###############################################################
#  Generated by:      Cadence Innovus 23.30-p003_1
#  OS:                Linux x86_64(Host ID dell52)
#  Generated on:      Mon May  4 14:32:32 2026
#  Design:            top
#  Command:           write_lef_abstract -5.8 -specifyTopLayer M11 -PGpinLayers M8 -stripePin -cutObsMinSpacing ../models/lef/top.lef
###############################################################

VERSION 5.8 ;

BUSBITCHARS "[]" ;
DIVIDERCHAR "/" ;

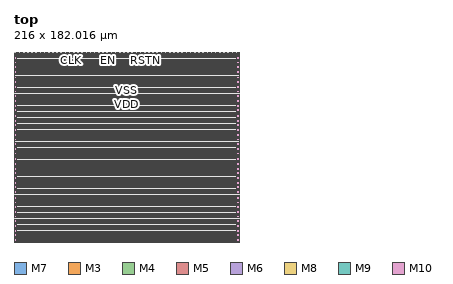
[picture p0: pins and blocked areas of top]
MACRO top
  CLASS BLOCK ;
  SIZE 216.000000 BY 182.016000 ;
  FOREIGN top 0.000000 0.000000 ;
  ORIGIN 0 0 ;
  SYMMETRY X Y R90 ;
  PIN CLK
    DIRECTION INPUT ;
    USE SIGNAL ;
    PORT
      LAYER M7 ;
        RECT 54.640000 181.641000 54.680000 182.016000 ;
    END
  END CLK
  PIN EN
    DIRECTION INPUT ;
    USE SIGNAL ;
    PORT
      LAYER M7 ;
        RECT 90.240000 181.641000 90.280000 182.016000 ;
    END
  END EN
  PIN RSTN
    DIRECTION INPUT ;
    USE SIGNAL ;
    PORT
      LAYER M7 ;
        RECT 125.840000 181.641000 125.880000 182.016000 ;
    END
  END RSTN
  PIN out_clk
    DIRECTION OUTPUT ;
    USE SIGNAL ;
    PORT
      LAYER M7 ;
        RECT 161.520000 181.641000 161.560000 182.016000 ;
    END
  END out_clk
  PIN VSS
    DIRECTION INOUT ;
    USE GROUND ;
    PORT
      LAYER M3 ;
        RECT 1.281000 0.000000 1.319000 0.038000 ;
    END
    PORT
      LAYER M3 ;
        RECT 1.281000 181.978000 1.319000 182.016000 ;
    END
    PORT
      LAYER M3 ;
        RECT 3.777000 0.000000 3.815000 0.038000 ;
    END
    PORT
      LAYER M3 ;
        RECT 3.777000 181.978000 3.815000 182.016000 ;
    END
    PORT
      LAYER M3 ;
        RECT 6.273000 0.000000 6.311000 0.038000 ;
    END
    PORT
      LAYER M3 ;
        RECT 6.273000 181.978000 6.311000 182.016000 ;
    END
    PORT
      LAYER M3 ;
        RECT 8.833000 0.000000 8.871000 0.038000 ;
    END
    PORT
      LAYER M3 ;
        RECT 8.833000 181.978000 8.871000 182.016000 ;
    END
    PORT
      LAYER M3 ;
        RECT 11.329000 0.000000 11.367000 0.038000 ;
    END
    PORT
      LAYER M3 ;
        RECT 11.329000 181.978000 11.367000 182.016000 ;
    END
    PORT
      LAYER M3 ;
        RECT 13.889000 0.000000 13.927000 0.038000 ;
    END
    PORT
      LAYER M3 ;
        RECT 13.889000 181.978000 13.927000 182.016000 ;
    END
    PORT
      LAYER M3 ;
        RECT 16.385000 0.000000 16.423000 0.038000 ;
    END
    PORT
      LAYER M3 ;
        RECT 16.385000 181.978000 16.423000 182.016000 ;
    END
    PORT
      LAYER M3 ;
        RECT 18.881000 0.000000 18.919000 0.038000 ;
    END
    PORT
      LAYER M3 ;
        RECT 18.881000 181.978000 18.919000 182.016000 ;
    END
    PORT
      LAYER M3 ;
        RECT 21.441000 0.000000 21.479000 0.038000 ;
    END
    PORT
      LAYER M3 ;
        RECT 21.441000 181.978000 21.479000 182.016000 ;
    END
    PORT
      LAYER M3 ;
        RECT 23.937000 0.000000 23.975000 0.038000 ;
    END
    PORT
      LAYER M3 ;
        RECT 23.937000 181.978000 23.975000 182.016000 ;
    END
    PORT
      LAYER M3 ;
        RECT 26.433000 0.000000 26.471000 0.038000 ;
    END
    PORT
      LAYER M3 ;
        RECT 26.433000 181.978000 26.471000 182.016000 ;
    END
    PORT
      LAYER M3 ;
        RECT 28.993000 0.000000 29.031000 0.038000 ;
    END
    PORT
      LAYER M3 ;
        RECT 28.993000 181.978000 29.031000 182.016000 ;
    END
    PORT
      LAYER M3 ;
        RECT 31.489000 0.000000 31.527000 0.038000 ;
    END
    PORT
      LAYER M3 ;
        RECT 31.489000 181.978000 31.527000 182.016000 ;
    END
    PORT
      LAYER M3 ;
        RECT 34.049000 0.000000 34.087000 0.038000 ;
    END
    PORT
      LAYER M3 ;
        RECT 34.049000 181.978000 34.087000 182.016000 ;
    END
    PORT
      LAYER M3 ;
        RECT 36.545000 0.000000 36.583000 0.038000 ;
    END
    PORT
      LAYER M3 ;
        RECT 36.545000 181.978000 36.583000 182.016000 ;
    END
    PORT
      LAYER M3 ;
        RECT 39.041000 0.000000 39.079000 0.038000 ;
    END
    PORT
      LAYER M3 ;
        RECT 39.041000 181.978000 39.079000 182.016000 ;
    END
    PORT
      LAYER M3 ;
        RECT 41.601000 0.000000 41.639000 0.038000 ;
    END
    PORT
      LAYER M3 ;
        RECT 41.601000 181.978000 41.639000 182.016000 ;
    END
    PORT
      LAYER M3 ;
        RECT 44.097000 0.000000 44.135000 0.038000 ;
    END
    PORT
      LAYER M3 ;
        RECT 44.097000 181.978000 44.135000 182.016000 ;
    END
    PORT
      LAYER M3 ;
        RECT 46.593000 0.000000 46.631000 0.038000 ;
    END
    PORT
      LAYER M3 ;
        RECT 46.593000 181.978000 46.631000 182.016000 ;
    END
    PORT
      LAYER M3 ;
        RECT 49.153000 0.000000 49.191000 0.038000 ;
    END
    PORT
      LAYER M3 ;
        RECT 49.153000 181.978000 49.191000 182.016000 ;
    END
    PORT
      LAYER M3 ;
        RECT 51.649000 0.000000 51.687000 0.038000 ;
    END
    PORT
      LAYER M3 ;
        RECT 51.649000 181.978000 51.687000 182.016000 ;
    END
    PORT
      LAYER M3 ;
        RECT 54.209000 0.000000 54.247000 0.038000 ;
    END
    PORT
      LAYER M3 ;
        RECT 54.209000 181.978000 54.247000 182.016000 ;
    END
    PORT
      LAYER M3 ;
        RECT 56.705000 0.000000 56.743000 0.038000 ;
    END
    PORT
      LAYER M3 ;
        RECT 56.705000 181.978000 56.743000 182.016000 ;
    END
    PORT
      LAYER M3 ;
        RECT 59.201000 0.000000 59.239000 0.038000 ;
    END
    PORT
      LAYER M3 ;
        RECT 59.201000 181.978000 59.239000 182.016000 ;
    END
    PORT
      LAYER M3 ;
        RECT 61.761000 0.000000 61.799000 0.038000 ;
    END
    PORT
      LAYER M3 ;
        RECT 61.761000 181.978000 61.799000 182.016000 ;
    END
    PORT
      LAYER M3 ;
        RECT 64.257000 0.000000 64.295000 0.038000 ;
    END
    PORT
      LAYER M3 ;
        RECT 64.257000 181.978000 64.295000 182.016000 ;
    END
    PORT
      LAYER M3 ;
        RECT 66.753000 0.000000 66.791000 0.038000 ;
    END
    PORT
      LAYER M3 ;
        RECT 66.753000 181.978000 66.791000 182.016000 ;
    END
    PORT
      LAYER M3 ;
        RECT 69.313000 0.000000 69.351000 0.038000 ;
    END
    PORT
      LAYER M3 ;
        RECT 69.313000 181.978000 69.351000 182.016000 ;
    END
    PORT
      LAYER M3 ;
        RECT 71.809000 0.000000 71.847000 0.038000 ;
    END
    PORT
      LAYER M3 ;
        RECT 71.809000 181.978000 71.847000 182.016000 ;
    END
    PORT
      LAYER M3 ;
        RECT 74.369000 0.000000 74.407000 0.038000 ;
    END
    PORT
      LAYER M3 ;
        RECT 74.369000 181.978000 74.407000 182.016000 ;
    END
    PORT
      LAYER M3 ;
        RECT 76.865000 0.000000 76.903000 0.038000 ;
    END
    PORT
      LAYER M3 ;
        RECT 76.865000 181.978000 76.903000 182.016000 ;
    END
    PORT
      LAYER M3 ;
        RECT 79.361000 0.000000 79.399000 0.038000 ;
    END
    PORT
      LAYER M3 ;
        RECT 79.361000 181.978000 79.399000 182.016000 ;
    END
    PORT
      LAYER M3 ;
        RECT 81.921000 0.000000 81.959000 0.038000 ;
    END
    PORT
      LAYER M3 ;
        RECT 81.921000 181.978000 81.959000 182.016000 ;
    END
    PORT
      LAYER M3 ;
        RECT 84.417000 0.000000 84.455000 0.038000 ;
    END
    PORT
      LAYER M3 ;
        RECT 84.417000 181.978000 84.455000 182.016000 ;
    END
    PORT
      LAYER M3 ;
        RECT 86.913000 0.000000 86.951000 0.038000 ;
    END
    PORT
      LAYER M3 ;
        RECT 86.913000 181.978000 86.951000 182.016000 ;
    END
    PORT
      LAYER M3 ;
        RECT 89.473000 0.000000 89.511000 0.038000 ;
    END
    PORT
      LAYER M3 ;
        RECT 89.473000 181.978000 89.511000 182.016000 ;
    END
    PORT
      LAYER M3 ;
        RECT 91.969000 0.000000 92.007000 0.038000 ;
    END
    PORT
      LAYER M3 ;
        RECT 91.969000 181.978000 92.007000 182.016000 ;
    END
    PORT
      LAYER M3 ;
        RECT 94.529000 0.000000 94.567000 0.038000 ;
    END
    PORT
      LAYER M3 ;
        RECT 94.529000 181.978000 94.567000 182.016000 ;
    END
    PORT
      LAYER M3 ;
        RECT 97.025000 0.000000 97.063000 0.038000 ;
    END
    PORT
      LAYER M3 ;
        RECT 97.025000 181.978000 97.063000 182.016000 ;
    END
    PORT
      LAYER M3 ;
        RECT 99.521000 0.000000 99.559000 0.038000 ;
    END
    PORT
      LAYER M3 ;
        RECT 99.521000 181.978000 99.559000 182.016000 ;
    END
    PORT
      LAYER M3 ;
        RECT 102.081000 0.000000 102.119000 0.038000 ;
    END
    PORT
      LAYER M3 ;
        RECT 102.081000 181.978000 102.119000 182.016000 ;
    END
    PORT
      LAYER M3 ;
        RECT 104.577000 0.000000 104.615000 0.038000 ;
    END
    PORT
      LAYER M3 ;
        RECT 104.577000 181.978000 104.615000 182.016000 ;
    END
    PORT
      LAYER M3 ;
        RECT 107.073000 0.000000 107.111000 0.038000 ;
    END
    PORT
      LAYER M3 ;
        RECT 107.073000 181.978000 107.111000 182.016000 ;
    END
    PORT
      LAYER M3 ;
        RECT 109.633000 0.000000 109.671000 0.038000 ;
    END
    PORT
      LAYER M3 ;
        RECT 109.633000 181.978000 109.671000 182.016000 ;
    END
    PORT
      LAYER M3 ;
        RECT 112.129000 0.000000 112.167000 0.038000 ;
    END
    PORT
      LAYER M3 ;
        RECT 112.129000 181.978000 112.167000 182.016000 ;
    END
    PORT
      LAYER M3 ;
        RECT 114.689000 0.000000 114.727000 0.038000 ;
    END
    PORT
      LAYER M3 ;
        RECT 114.689000 181.978000 114.727000 182.016000 ;
    END
    PORT
      LAYER M3 ;
        RECT 117.185000 0.000000 117.223000 0.038000 ;
    END
    PORT
      LAYER M3 ;
        RECT 117.185000 181.978000 117.223000 182.016000 ;
    END
    PORT
      LAYER M3 ;
        RECT 119.681000 0.000000 119.719000 0.038000 ;
    END
    PORT
      LAYER M3 ;
        RECT 119.681000 181.978000 119.719000 182.016000 ;
    END
    PORT
      LAYER M3 ;
        RECT 122.241000 0.000000 122.279000 0.038000 ;
    END
    PORT
      LAYER M3 ;
        RECT 122.241000 181.978000 122.279000 182.016000 ;
    END
    PORT
      LAYER M3 ;
        RECT 124.737000 0.000000 124.775000 0.038000 ;
    END
    PORT
      LAYER M3 ;
        RECT 124.737000 181.978000 124.775000 182.016000 ;
    END
    PORT
      LAYER M3 ;
        RECT 127.233000 0.000000 127.271000 0.038000 ;
    END
    PORT
      LAYER M3 ;
        RECT 127.233000 181.978000 127.271000 182.016000 ;
    END
    PORT
      LAYER M3 ;
        RECT 129.793000 0.000000 129.831000 0.038000 ;
    END
    PORT
      LAYER M3 ;
        RECT 129.793000 181.978000 129.831000 182.016000 ;
    END
    PORT
      LAYER M3 ;
        RECT 132.289000 0.000000 132.327000 0.038000 ;
    END
    PORT
      LAYER M3 ;
        RECT 132.289000 181.978000 132.327000 182.016000 ;
    END
    PORT
      LAYER M3 ;
        RECT 134.849000 0.000000 134.887000 0.038000 ;
    END
    PORT
      LAYER M3 ;
        RECT 134.849000 181.978000 134.887000 182.016000 ;
    END
    PORT
      LAYER M3 ;
        RECT 137.345000 0.000000 137.383000 0.038000 ;
    END
    PORT
      LAYER M3 ;
        RECT 137.345000 181.978000 137.383000 182.016000 ;
    END
    PORT
      LAYER M3 ;
        RECT 139.841000 0.000000 139.879000 0.038000 ;
    END
    PORT
      LAYER M3 ;
        RECT 139.841000 181.978000 139.879000 182.016000 ;
    END
    PORT
      LAYER M3 ;
        RECT 142.401000 0.000000 142.439000 0.038000 ;
    END
    PORT
      LAYER M3 ;
        RECT 142.401000 181.978000 142.439000 182.016000 ;
    END
    PORT
      LAYER M3 ;
        RECT 144.897000 0.000000 144.935000 0.038000 ;
    END
    PORT
      LAYER M3 ;
        RECT 144.897000 181.978000 144.935000 182.016000 ;
    END
    PORT
      LAYER M3 ;
        RECT 147.393000 0.000000 147.431000 0.038000 ;
    END
    PORT
      LAYER M3 ;
        RECT 147.393000 181.978000 147.431000 182.016000 ;
    END
    PORT
      LAYER M3 ;
        RECT 149.953000 0.000000 149.991000 0.038000 ;
    END
    PORT
      LAYER M3 ;
        RECT 149.953000 181.978000 149.991000 182.016000 ;
    END
    PORT
      LAYER M3 ;
        RECT 152.449000 0.000000 152.487000 0.038000 ;
    END
    PORT
      LAYER M3 ;
        RECT 152.449000 181.978000 152.487000 182.016000 ;
    END
    PORT
      LAYER M3 ;
        RECT 155.009000 0.000000 155.047000 0.038000 ;
    END
    PORT
      LAYER M3 ;
        RECT 155.009000 181.978000 155.047000 182.016000 ;
    END
    PORT
      LAYER M3 ;
        RECT 157.505000 0.000000 157.543000 0.038000 ;
    END
    PORT
      LAYER M3 ;
        RECT 157.505000 181.978000 157.543000 182.016000 ;
    END
    PORT
      LAYER M3 ;
        RECT 160.001000 0.000000 160.039000 0.038000 ;
    END
    PORT
      LAYER M3 ;
        RECT 160.001000 181.978000 160.039000 182.016000 ;
    END
    PORT
      LAYER M3 ;
        RECT 162.561000 0.000000 162.599000 0.038000 ;
    END
    PORT
      LAYER M3 ;
        RECT 162.561000 181.978000 162.599000 182.016000 ;
    END
    PORT
      LAYER M3 ;
        RECT 165.057000 0.000000 165.095000 0.038000 ;
    END
    PORT
      LAYER M3 ;
        RECT 165.057000 181.978000 165.095000 182.016000 ;
    END
    PORT
      LAYER M3 ;
        RECT 167.553000 0.000000 167.591000 0.038000 ;
    END
    PORT
      LAYER M3 ;
        RECT 167.553000 181.978000 167.591000 182.016000 ;
    END
    PORT
      LAYER M3 ;
        RECT 170.113000 0.000000 170.151000 0.038000 ;
    END
    PORT
      LAYER M3 ;
        RECT 170.113000 181.978000 170.151000 182.016000 ;
    END
    PORT
      LAYER M3 ;
        RECT 172.609000 0.000000 172.647000 0.038000 ;
    END
    PORT
      LAYER M3 ;
        RECT 172.609000 181.978000 172.647000 182.016000 ;
    END
    PORT
      LAYER M3 ;
        RECT 175.169000 0.000000 175.207000 0.038000 ;
    END
    PORT
      LAYER M3 ;
        RECT 175.169000 181.978000 175.207000 182.016000 ;
    END
    PORT
      LAYER M3 ;
        RECT 177.665000 0.000000 177.703000 0.038000 ;
    END
    PORT
      LAYER M3 ;
        RECT 177.665000 181.978000 177.703000 182.016000 ;
    END
    PORT
      LAYER M3 ;
        RECT 180.161000 0.000000 180.199000 0.038000 ;
    END
    PORT
      LAYER M3 ;
        RECT 180.161000 181.978000 180.199000 182.016000 ;
    END
    PORT
      LAYER M3 ;
        RECT 182.721000 0.000000 182.759000 0.038000 ;
    END
    PORT
      LAYER M3 ;
        RECT 182.721000 181.978000 182.759000 182.016000 ;
    END
    PORT
      LAYER M3 ;
        RECT 185.217000 0.000000 185.255000 0.038000 ;
    END
    PORT
      LAYER M3 ;
        RECT 185.217000 181.978000 185.255000 182.016000 ;
    END
    PORT
      LAYER M3 ;
        RECT 187.713000 0.000000 187.751000 0.038000 ;
    END
    PORT
      LAYER M3 ;
        RECT 187.713000 181.978000 187.751000 182.016000 ;
    END
    PORT
      LAYER M3 ;
        RECT 190.273000 0.000000 190.311000 0.038000 ;
    END
    PORT
      LAYER M3 ;
        RECT 190.273000 181.978000 190.311000 182.016000 ;
    END
    PORT
      LAYER M3 ;
        RECT 192.769000 0.000000 192.807000 0.038000 ;
    END
    PORT
      LAYER M3 ;
        RECT 192.769000 181.978000 192.807000 182.016000 ;
    END
    PORT
      LAYER M3 ;
        RECT 195.329000 0.000000 195.367000 0.038000 ;
    END
    PORT
      LAYER M3 ;
        RECT 195.329000 181.978000 195.367000 182.016000 ;
    END
    PORT
      LAYER M3 ;
        RECT 197.825000 0.000000 197.863000 0.038000 ;
    END
    PORT
      LAYER M3 ;
        RECT 197.825000 181.978000 197.863000 182.016000 ;
    END
    PORT
      LAYER M3 ;
        RECT 200.321000 0.000000 200.359000 0.038000 ;
    END
    PORT
      LAYER M3 ;
        RECT 200.321000 181.978000 200.359000 182.016000 ;
    END
    PORT
      LAYER M3 ;
        RECT 202.881000 0.000000 202.919000 0.038000 ;
    END
    PORT
      LAYER M3 ;
        RECT 202.881000 181.978000 202.919000 182.016000 ;
    END
    PORT
      LAYER M3 ;
        RECT 205.377000 0.000000 205.415000 0.038000 ;
    END
    PORT
      LAYER M3 ;
        RECT 205.377000 181.978000 205.415000 182.016000 ;
    END
    PORT
      LAYER M3 ;
        RECT 207.873000 0.000000 207.911000 0.038000 ;
    END
    PORT
      LAYER M3 ;
        RECT 207.873000 181.978000 207.911000 182.016000 ;
    END
    PORT
      LAYER M3 ;
        RECT 210.433000 0.000000 210.471000 0.038000 ;
    END
    PORT
      LAYER M3 ;
        RECT 210.433000 181.978000 210.471000 182.016000 ;
    END
    PORT
      LAYER M3 ;
        RECT 212.929000 0.000000 212.967000 0.038000 ;
    END
    PORT
      LAYER M3 ;
        RECT 212.929000 181.978000 212.967000 182.016000 ;
    END
    PORT
      LAYER M3 ;
        RECT 215.489000 0.000000 215.527000 0.038000 ;
    END
    PORT
      LAYER M3 ;
        RECT 215.489000 181.978000 215.527000 182.016000 ;
    END
    PORT
      LAYER M4 ;
        RECT 0.000000 1.228000 0.040000 1.268000 ;
    END
    PORT
      LAYER M4 ;
        RECT 215.960000 1.228000 216.000000 1.268000 ;
    END
    PORT
      LAYER M4 ;
        RECT 0.000000 3.468000 0.040000 3.508000 ;
    END
    PORT
      LAYER M4 ;
        RECT 215.960000 3.468000 216.000000 3.508000 ;
    END
    PORT
      LAYER M4 ;
        RECT 0.000000 5.788000 0.040000 5.828000 ;
    END
    PORT
      LAYER M4 ;
        RECT 215.960000 5.788000 216.000000 5.828000 ;
    END
    PORT
      LAYER M4 ;
        RECT 0.000000 8.028000 0.040000 8.068000 ;
    END
    PORT
      LAYER M4 ;
        RECT 215.960000 8.028000 216.000000 8.068000 ;
    END
    PORT
      LAYER M4 ;
        RECT 0.000000 10.348000 0.040000 10.388000 ;
    END
    PORT
      LAYER M4 ;
        RECT 215.960000 10.348000 216.000000 10.388000 ;
    END
    PORT
      LAYER M4 ;
        RECT 0.000000 12.668000 0.040000 12.708000 ;
    END
    PORT
      LAYER M4 ;
        RECT 215.960000 12.668000 216.000000 12.708000 ;
    END
    PORT
      LAYER M4 ;
        RECT 0.000000 14.988000 0.040000 15.028000 ;
    END
    PORT
      LAYER M4 ;
        RECT 215.960000 14.988000 216.000000 15.028000 ;
    END
    PORT
      LAYER M4 ;
        RECT 0.000000 17.308000 0.040000 17.348000 ;
    END
    PORT
      LAYER M4 ;
        RECT 215.960000 17.308000 216.000000 17.348000 ;
    END
    PORT
      LAYER M4 ;
        RECT 0.000000 19.548000 0.040000 19.588000 ;
    END
    PORT
      LAYER M4 ;
        RECT 215.960000 19.548000 216.000000 19.588000 ;
    END
    PORT
      LAYER M4 ;
        RECT 0.000000 21.868000 0.040000 21.908000 ;
    END
    PORT
      LAYER M4 ;
        RECT 215.960000 21.868000 216.000000 21.908000 ;
    END
    PORT
      LAYER M4 ;
        RECT 0.000000 24.188000 0.040000 24.228000 ;
    END
    PORT
      LAYER M4 ;
        RECT 215.960000 24.188000 216.000000 24.228000 ;
    END
    PORT
      LAYER M4 ;
        RECT 0.000000 26.508000 0.040000 26.548000 ;
    END
    PORT
      LAYER M4 ;
        RECT 215.960000 26.508000 216.000000 26.548000 ;
    END
    PORT
      LAYER M4 ;
        RECT 0.000000 28.828000 0.040000 28.868000 ;
    END
    PORT
      LAYER M4 ;
        RECT 215.960000 28.828000 216.000000 28.868000 ;
    END
    PORT
      LAYER M4 ;
        RECT 0.000000 31.068000 0.040000 31.108000 ;
    END
    PORT
      LAYER M4 ;
        RECT 215.960000 31.068000 216.000000 31.108000 ;
    END
    PORT
      LAYER M4 ;
        RECT 0.000000 33.388000 0.040000 33.428000 ;
    END
    PORT
      LAYER M4 ;
        RECT 215.960000 33.388000 216.000000 33.428000 ;
    END
    PORT
      LAYER M4 ;
        RECT 0.000000 35.708000 0.040000 35.748000 ;
    END
    PORT
      LAYER M4 ;
        RECT 215.960000 35.708000 216.000000 35.748000 ;
    END
    PORT
      LAYER M4 ;
        RECT 0.000000 38.028000 0.040000 38.068000 ;
    END
    PORT
      LAYER M4 ;
        RECT 215.960000 38.028000 216.000000 38.068000 ;
    END
    PORT
      LAYER M4 ;
        RECT 0.000000 40.348000 0.040000 40.388000 ;
    END
    PORT
      LAYER M4 ;
        RECT 215.960000 40.348000 216.000000 40.388000 ;
    END
    PORT
      LAYER M4 ;
        RECT 0.000000 42.588000 0.040000 42.628000 ;
    END
    PORT
      LAYER M4 ;
        RECT 215.960000 42.588000 216.000000 42.628000 ;
    END
    PORT
      LAYER M4 ;
        RECT 0.000000 44.908000 0.040000 44.948000 ;
    END
    PORT
      LAYER M4 ;
        RECT 215.960000 44.908000 216.000000 44.948000 ;
    END
    PORT
      LAYER M4 ;
        RECT 0.000000 47.228000 0.040000 47.268000 ;
    END
    PORT
      LAYER M4 ;
        RECT 215.960000 47.228000 216.000000 47.268000 ;
    END
    PORT
      LAYER M4 ;
        RECT 0.000000 49.548000 0.040000 49.588000 ;
    END
    PORT
      LAYER M4 ;
        RECT 215.960000 49.548000 216.000000 49.588000 ;
    END
    PORT
      LAYER M4 ;
        RECT 0.000000 51.868000 0.040000 51.908000 ;
    END
    PORT
      LAYER M4 ;
        RECT 215.960000 51.868000 216.000000 51.908000 ;
    END
    PORT
      LAYER M4 ;
        RECT 0.000000 54.108000 0.040000 54.148000 ;
    END
    PORT
      LAYER M4 ;
        RECT 215.960000 54.108000 216.000000 54.148000 ;
    END
    PORT
      LAYER M4 ;
        RECT 0.000000 56.428000 0.040000 56.468000 ;
    END
    PORT
      LAYER M4 ;
        RECT 215.960000 56.428000 216.000000 56.468000 ;
    END
    PORT
      LAYER M4 ;
        RECT 0.000000 58.748000 0.040000 58.788000 ;
    END
    PORT
      LAYER M4 ;
        RECT 215.960000 58.748000 216.000000 58.788000 ;
    END
    PORT
      LAYER M4 ;
        RECT 0.000000 61.068000 0.040000 61.108000 ;
    END
    PORT
      LAYER M4 ;
        RECT 215.960000 61.068000 216.000000 61.108000 ;
    END
    PORT
      LAYER M4 ;
        RECT 0.000000 63.388000 0.040000 63.428000 ;
    END
    PORT
      LAYER M4 ;
        RECT 215.960000 63.388000 216.000000 63.428000 ;
    END
    PORT
      LAYER M4 ;
        RECT 0.000000 65.628000 0.040000 65.668000 ;
    END
    PORT
      LAYER M4 ;
        RECT 215.960000 65.628000 216.000000 65.668000 ;
    END
    PORT
      LAYER M4 ;
        RECT 0.000000 67.948000 0.040000 67.988000 ;
    END
    PORT
      LAYER M4 ;
        RECT 215.960000 67.948000 216.000000 67.988000 ;
    END
    PORT
      LAYER M4 ;
        RECT 0.000000 70.268000 0.040000 70.308000 ;
    END
    PORT
      LAYER M4 ;
        RECT 215.960000 70.268000 216.000000 70.308000 ;
    END
    PORT
      LAYER M4 ;
        RECT 0.000000 72.588000 0.040000 72.628000 ;
    END
    PORT
      LAYER M4 ;
        RECT 215.960000 72.588000 216.000000 72.628000 ;
    END
    PORT
      LAYER M4 ;
        RECT 0.000000 74.908000 0.040000 74.948000 ;
    END
    PORT
      LAYER M4 ;
        RECT 215.960000 74.908000 216.000000 74.948000 ;
    END
    PORT
      LAYER M4 ;
        RECT 0.000000 77.148000 0.040000 77.188000 ;
    END
    PORT
      LAYER M4 ;
        RECT 215.960000 77.148000 216.000000 77.188000 ;
    END
    PORT
      LAYER M4 ;
        RECT 0.000000 79.468000 0.040000 79.508000 ;
    END
    PORT
      LAYER M4 ;
        RECT 215.960000 79.468000 216.000000 79.508000 ;
    END
    PORT
      LAYER M4 ;
        RECT 0.000000 81.788000 0.040000 81.828000 ;
    END
    PORT
      LAYER M4 ;
        RECT 215.960000 81.788000 216.000000 81.828000 ;
    END
    PORT
      LAYER M4 ;
        RECT 0.000000 84.108000 0.040000 84.148000 ;
    END
    PORT
      LAYER M4 ;
        RECT 215.960000 84.108000 216.000000 84.148000 ;
    END
    PORT
      LAYER M4 ;
        RECT 0.000000 86.428000 0.040000 86.468000 ;
    END
    PORT
      LAYER M4 ;
        RECT 215.960000 86.428000 216.000000 86.468000 ;
    END
    PORT
      LAYER M4 ;
        RECT 0.000000 88.668000 0.040000 88.708000 ;
    END
    PORT
      LAYER M4 ;
        RECT 215.960000 88.668000 216.000000 88.708000 ;
    END
    PORT
      LAYER M4 ;
        RECT 0.000000 90.988000 0.040000 91.028000 ;
    END
    PORT
      LAYER M4 ;
        RECT 215.960000 90.988000 216.000000 91.028000 ;
    END
    PORT
      LAYER M4 ;
        RECT 0.000000 93.308000 0.040000 93.348000 ;
    END
    PORT
      LAYER M4 ;
        RECT 215.960000 93.308000 216.000000 93.348000 ;
    END
    PORT
      LAYER M4 ;
        RECT 0.000000 95.628000 0.040000 95.668000 ;
    END
    PORT
      LAYER M4 ;
        RECT 215.960000 95.628000 216.000000 95.668000 ;
    END
    PORT
      LAYER M4 ;
        RECT 0.000000 97.948000 0.040000 97.988000 ;
    END
    PORT
      LAYER M4 ;
        RECT 215.960000 97.948000 216.000000 97.988000 ;
    END
    PORT
      LAYER M4 ;
        RECT 0.000000 100.188000 0.040000 100.228000 ;
    END
    PORT
      LAYER M4 ;
        RECT 215.960000 100.188000 216.000000 100.228000 ;
    END
    PORT
      LAYER M4 ;
        RECT 0.000000 102.508000 0.040000 102.548000 ;
    END
    PORT
      LAYER M4 ;
        RECT 215.960000 102.508000 216.000000 102.548000 ;
    END
    PORT
      LAYER M4 ;
        RECT 0.000000 104.828000 0.040000 104.868000 ;
    END
    PORT
      LAYER M4 ;
        RECT 215.960000 104.828000 216.000000 104.868000 ;
    END
    PORT
      LAYER M4 ;
        RECT 0.000000 107.148000 0.040000 107.188000 ;
    END
    PORT
      LAYER M4 ;
        RECT 215.960000 107.148000 216.000000 107.188000 ;
    END
    PORT
      LAYER M4 ;
        RECT 0.000000 109.468000 0.040000 109.508000 ;
    END
    PORT
      LAYER M4 ;
        RECT 215.960000 109.468000 216.000000 109.508000 ;
    END
    PORT
      LAYER M4 ;
        RECT 0.000000 111.708000 0.040000 111.748000 ;
    END
    PORT
      LAYER M4 ;
        RECT 215.960000 111.708000 216.000000 111.748000 ;
    END
    PORT
      LAYER M4 ;
        RECT 0.000000 114.028000 0.040000 114.068000 ;
    END
    PORT
      LAYER M4 ;
        RECT 215.960000 114.028000 216.000000 114.068000 ;
    END
    PORT
      LAYER M4 ;
        RECT 0.000000 116.348000 0.040000 116.388000 ;
    END
    PORT
      LAYER M4 ;
        RECT 215.960000 116.348000 216.000000 116.388000 ;
    END
    PORT
      LAYER M4 ;
        RECT 0.000000 118.668000 0.040000 118.708000 ;
    END
    PORT
      LAYER M4 ;
        RECT 215.960000 118.668000 216.000000 118.708000 ;
    END
    PORT
      LAYER M4 ;
        RECT 0.000000 120.988000 0.040000 121.028000 ;
    END
    PORT
      LAYER M4 ;
        RECT 215.960000 120.988000 216.000000 121.028000 ;
    END
    PORT
      LAYER M4 ;
        RECT 0.000000 123.228000 0.040000 123.268000 ;
    END
    PORT
      LAYER M4 ;
        RECT 215.960000 123.228000 216.000000 123.268000 ;
    END
    PORT
      LAYER M4 ;
        RECT 0.000000 125.548000 0.040000 125.588000 ;
    END
    PORT
      LAYER M4 ;
        RECT 215.960000 125.548000 216.000000 125.588000 ;
    END
    PORT
      LAYER M4 ;
        RECT 0.000000 127.868000 0.040000 127.908000 ;
    END
    PORT
      LAYER M4 ;
        RECT 215.960000 127.868000 216.000000 127.908000 ;
    END
    PORT
      LAYER M4 ;
        RECT 0.000000 130.188000 0.040000 130.228000 ;
    END
    PORT
      LAYER M4 ;
        RECT 215.960000 130.188000 216.000000 130.228000 ;
    END
    PORT
      LAYER M4 ;
        RECT 0.000000 132.508000 0.040000 132.548000 ;
    END
    PORT
      LAYER M4 ;
        RECT 215.960000 132.508000 216.000000 132.548000 ;
    END
    PORT
      LAYER M4 ;
        RECT 0.000000 134.748000 0.040000 134.788000 ;
    END
    PORT
      LAYER M4 ;
        RECT 215.960000 134.748000 216.000000 134.788000 ;
    END
    PORT
      LAYER M4 ;
        RECT 0.000000 137.068000 0.040000 137.108000 ;
    END
    PORT
      LAYER M4 ;
        RECT 215.960000 137.068000 216.000000 137.108000 ;
    END
    PORT
      LAYER M4 ;
        RECT 0.000000 139.388000 0.040000 139.428000 ;
    END
    PORT
      LAYER M4 ;
        RECT 215.960000 139.388000 216.000000 139.428000 ;
    END
    PORT
      LAYER M4 ;
        RECT 0.000000 141.708000 0.040000 141.748000 ;
    END
    PORT
      LAYER M4 ;
        RECT 215.960000 141.708000 216.000000 141.748000 ;
    END
    PORT
      LAYER M4 ;
        RECT 0.000000 144.028000 0.040000 144.068000 ;
    END
    PORT
      LAYER M4 ;
        RECT 215.960000 144.028000 216.000000 144.068000 ;
    END
    PORT
      LAYER M4 ;
        RECT 0.000000 146.268000 0.040000 146.308000 ;
    END
    PORT
      LAYER M4 ;
        RECT 215.960000 146.268000 216.000000 146.308000 ;
    END
    PORT
      LAYER M4 ;
        RECT 0.000000 148.588000 0.040000 148.628000 ;
    END
    PORT
      LAYER M4 ;
        RECT 215.960000 148.588000 216.000000 148.628000 ;
    END
    PORT
      LAYER M4 ;
        RECT 0.000000 150.908000 0.040000 150.948000 ;
    END
    PORT
      LAYER M4 ;
        RECT 215.960000 150.908000 216.000000 150.948000 ;
    END
    PORT
      LAYER M4 ;
        RECT 0.000000 153.228000 0.040000 153.268000 ;
    END
    PORT
      LAYER M4 ;
        RECT 215.960000 153.228000 216.000000 153.268000 ;
    END
    PORT
      LAYER M4 ;
        RECT 0.000000 155.548000 0.040000 155.588000 ;
    END
    PORT
      LAYER M4 ;
        RECT 215.960000 155.548000 216.000000 155.588000 ;
    END
    PORT
      LAYER M4 ;
        RECT 0.000000 157.788000 0.040000 157.828000 ;
    END
    PORT
      LAYER M4 ;
        RECT 215.960000 157.788000 216.000000 157.828000 ;
    END
    PORT
      LAYER M4 ;
        RECT 0.000000 160.108000 0.040000 160.148000 ;
    END
    PORT
      LAYER M4 ;
        RECT 215.960000 160.108000 216.000000 160.148000 ;
    END
    PORT
      LAYER M4 ;
        RECT 0.000000 162.428000 0.040000 162.468000 ;
    END
    PORT
      LAYER M4 ;
        RECT 215.960000 162.428000 216.000000 162.468000 ;
    END
    PORT
      LAYER M4 ;
        RECT 0.000000 164.748000 0.040000 164.788000 ;
    END
    PORT
      LAYER M4 ;
        RECT 215.960000 164.748000 216.000000 164.788000 ;
    END
    PORT
      LAYER M4 ;
        RECT 0.000000 167.068000 0.040000 167.108000 ;
    END
    PORT
      LAYER M4 ;
        RECT 215.960000 167.068000 216.000000 167.108000 ;
    END
    PORT
      LAYER M4 ;
        RECT 0.000000 169.308000 0.040000 169.348000 ;
    END
    PORT
      LAYER M4 ;
        RECT 215.960000 169.308000 216.000000 169.348000 ;
    END
    PORT
      LAYER M4 ;
        RECT 0.000000 171.628000 0.040000 171.668000 ;
    END
    PORT
      LAYER M4 ;
        RECT 215.960000 171.628000 216.000000 171.668000 ;
    END
    PORT
      LAYER M4 ;
        RECT 0.000000 173.948000 0.040000 173.988000 ;
    END
    PORT
      LAYER M4 ;
        RECT 215.960000 173.948000 216.000000 173.988000 ;
    END
    PORT
      LAYER M4 ;
        RECT 0.000000 176.268000 0.040000 176.308000 ;
    END
    PORT
      LAYER M4 ;
        RECT 215.960000 176.268000 216.000000 176.308000 ;
    END
    PORT
      LAYER M4 ;
        RECT 0.000000 178.588000 0.040000 178.628000 ;
    END
    PORT
      LAYER M4 ;
        RECT 215.960000 178.588000 216.000000 178.628000 ;
    END
    PORT
      LAYER M4 ;
        RECT 0.000000 180.828000 0.040000 180.868000 ;
    END
    PORT
      LAYER M4 ;
        RECT 215.960000 180.828000 216.000000 180.868000 ;
    END
    PORT
      LAYER M5 ;
        RECT 1.280000 0.000000 1.320000 0.040000 ;
    END
    PORT
      LAYER M5 ;
        RECT 1.280000 181.976000 1.320000 182.016000 ;
    END
    PORT
      LAYER M5 ;
        RECT 3.760000 0.000000 3.800000 0.040000 ;
    END
    PORT
      LAYER M5 ;
        RECT 3.760000 181.976000 3.800000 182.016000 ;
    END
    PORT
      LAYER M5 ;
        RECT 6.320000 0.000000 6.360000 0.040000 ;
    END
    PORT
      LAYER M5 ;
        RECT 6.320000 181.976000 6.360000 182.016000 ;
    END
    PORT
      LAYER M5 ;
        RECT 8.800000 0.000000 8.840000 0.040000 ;
    END
    PORT
      LAYER M5 ;
        RECT 8.800000 181.976000 8.840000 182.016000 ;
    END
    PORT
      LAYER M5 ;
        RECT 11.360000 0.000000 11.400000 0.040000 ;
    END
    PORT
      LAYER M5 ;
        RECT 11.360000 181.976000 11.400000 182.016000 ;
    END
    PORT
      LAYER M5 ;
        RECT 13.840000 0.000000 13.880000 0.040000 ;
    END
    PORT
      LAYER M5 ;
        RECT 13.840000 181.976000 13.880000 182.016000 ;
    END
    PORT
      LAYER M5 ;
        RECT 16.400000 0.000000 16.440000 0.040000 ;
    END
    PORT
      LAYER M5 ;
        RECT 16.400000 181.976000 16.440000 182.016000 ;
    END
    PORT
      LAYER M5 ;
        RECT 18.880000 0.000000 18.920000 0.040000 ;
    END
    PORT
      LAYER M5 ;
        RECT 18.880000 181.976000 18.920000 182.016000 ;
    END
    PORT
      LAYER M5 ;
        RECT 21.440000 0.000000 21.480000 0.040000 ;
    END
    PORT
      LAYER M5 ;
        RECT 21.440000 181.976000 21.480000 182.016000 ;
    END
    PORT
      LAYER M5 ;
        RECT 23.920000 0.000000 23.960000 0.040000 ;
    END
    PORT
      LAYER M5 ;
        RECT 23.920000 181.976000 23.960000 182.016000 ;
    END
    PORT
      LAYER M5 ;
        RECT 26.480000 0.000000 26.520000 0.040000 ;
    END
    PORT
      LAYER M5 ;
        RECT 26.480000 181.976000 26.520000 182.016000 ;
    END
    PORT
      LAYER M5 ;
        RECT 28.960000 0.000000 29.000000 0.040000 ;
    END
    PORT
      LAYER M5 ;
        RECT 28.960000 181.976000 29.000000 182.016000 ;
    END
    PORT
      LAYER M5 ;
        RECT 31.520000 0.000000 31.560000 0.040000 ;
    END
    PORT
      LAYER M5 ;
        RECT 31.520000 181.976000 31.560000 182.016000 ;
    END
    PORT
      LAYER M5 ;
        RECT 34.000000 0.000000 34.040000 0.040000 ;
    END
    PORT
      LAYER M5 ;
        RECT 34.000000 181.976000 34.040000 182.016000 ;
    END
    PORT
      LAYER M5 ;
        RECT 36.560000 0.000000 36.600000 0.040000 ;
    END
    PORT
      LAYER M5 ;
        RECT 36.560000 181.976000 36.600000 182.016000 ;
    END
    PORT
      LAYER M5 ;
        RECT 39.040000 0.000000 39.080000 0.040000 ;
    END
    PORT
      LAYER M5 ;
        RECT 39.040000 181.976000 39.080000 182.016000 ;
    END
    PORT
      LAYER M5 ;
        RECT 41.600000 0.000000 41.640000 0.040000 ;
    END
    PORT
      LAYER M5 ;
        RECT 41.600000 181.976000 41.640000 182.016000 ;
    END
    PORT
      LAYER M5 ;
        RECT 44.080000 0.000000 44.120000 0.040000 ;
    END
    PORT
      LAYER M5 ;
        RECT 44.080000 181.976000 44.120000 182.016000 ;
    END
    PORT
      LAYER M5 ;
        RECT 46.640000 0.000000 46.680000 0.040000 ;
    END
    PORT
      LAYER M5 ;
        RECT 46.640000 181.976000 46.680000 182.016000 ;
    END
    PORT
      LAYER M5 ;
        RECT 49.120000 0.000000 49.160000 0.040000 ;
    END
    PORT
      LAYER M5 ;
        RECT 49.120000 181.976000 49.160000 182.016000 ;
    END
    PORT
      LAYER M5 ;
        RECT 51.680000 0.000000 51.720000 0.040000 ;
    END
    PORT
      LAYER M5 ;
        RECT 51.680000 181.976000 51.720000 182.016000 ;
    END
    PORT
      LAYER M5 ;
        RECT 54.160000 0.000000 54.200000 0.040000 ;
    END
    PORT
      LAYER M5 ;
        RECT 54.160000 181.976000 54.200000 182.016000 ;
    END
    PORT
      LAYER M5 ;
        RECT 56.720000 0.000000 56.760000 0.040000 ;
    END
    PORT
      LAYER M5 ;
        RECT 56.720000 181.976000 56.760000 182.016000 ;
    END
    PORT
      LAYER M5 ;
        RECT 59.200000 0.000000 59.240000 0.040000 ;
    END
    PORT
      LAYER M5 ;
        RECT 59.200000 181.976000 59.240000 182.016000 ;
    END
    PORT
      LAYER M5 ;
        RECT 61.760000 0.000000 61.800000 0.040000 ;
    END
    PORT
      LAYER M5 ;
        RECT 61.760000 181.976000 61.800000 182.016000 ;
    END
    PORT
      LAYER M5 ;
        RECT 64.240000 0.000000 64.280000 0.040000 ;
    END
    PORT
      LAYER M5 ;
        RECT 64.240000 181.976000 64.280000 182.016000 ;
    END
    PORT
      LAYER M5 ;
        RECT 66.800000 0.000000 66.840000 0.040000 ;
    END
    PORT
      LAYER M5 ;
        RECT 66.800000 181.976000 66.840000 182.016000 ;
    END
    PORT
      LAYER M5 ;
        RECT 69.280000 0.000000 69.320000 0.040000 ;
    END
    PORT
      LAYER M5 ;
        RECT 69.280000 181.976000 69.320000 182.016000 ;
    END
    PORT
      LAYER M5 ;
        RECT 71.840000 0.000000 71.880000 0.040000 ;
    END
    PORT
      LAYER M5 ;
        RECT 71.840000 181.976000 71.880000 182.016000 ;
    END
    PORT
      LAYER M5 ;
        RECT 74.320000 0.000000 74.360000 0.040000 ;
    END
    PORT
      LAYER M5 ;
        RECT 74.320000 181.976000 74.360000 182.016000 ;
    END
    PORT
      LAYER M5 ;
        RECT 76.880000 0.000000 76.920000 0.040000 ;
    END
    PORT
      LAYER M5 ;
        RECT 76.880000 181.976000 76.920000 182.016000 ;
    END
    PORT
      LAYER M5 ;
        RECT 79.360000 0.000000 79.400000 0.040000 ;
    END
    PORT
      LAYER M5 ;
        RECT 79.360000 181.976000 79.400000 182.016000 ;
    END
    PORT
      LAYER M5 ;
        RECT 81.920000 0.000000 81.960000 0.040000 ;
    END
    PORT
      LAYER M5 ;
        RECT 81.920000 181.976000 81.960000 182.016000 ;
    END
    PORT
      LAYER M5 ;
        RECT 84.400000 0.000000 84.440000 0.040000 ;
    END
    PORT
      LAYER M5 ;
        RECT 84.400000 181.976000 84.440000 182.016000 ;
    END
    PORT
      LAYER M5 ;
        RECT 86.960000 0.000000 87.000000 0.040000 ;
    END
    PORT
      LAYER M5 ;
        RECT 86.960000 181.976000 87.000000 182.016000 ;
    END
    PORT
      LAYER M5 ;
        RECT 89.440000 0.000000 89.480000 0.040000 ;
    END
    PORT
      LAYER M5 ;
        RECT 89.440000 181.976000 89.480000 182.016000 ;
    END
    PORT
      LAYER M5 ;
        RECT 92.000000 0.000000 92.040000 0.040000 ;
    END
    PORT
      LAYER M5 ;
        RECT 92.000000 181.976000 92.040000 182.016000 ;
    END
    PORT
      LAYER M5 ;
        RECT 94.480000 0.000000 94.520000 0.040000 ;
    END
    PORT
      LAYER M5 ;
        RECT 94.480000 181.976000 94.520000 182.016000 ;
    END
    PORT
      LAYER M5 ;
        RECT 97.040000 0.000000 97.080000 0.040000 ;
    END
    PORT
      LAYER M5 ;
        RECT 97.040000 181.976000 97.080000 182.016000 ;
    END
    PORT
      LAYER M5 ;
        RECT 99.520000 0.000000 99.560000 0.040000 ;
    END
    PORT
      LAYER M5 ;
        RECT 99.520000 181.976000 99.560000 182.016000 ;
    END
    PORT
      LAYER M5 ;
        RECT 102.080000 0.000000 102.120000 0.040000 ;
    END
    PORT
      LAYER M5 ;
        RECT 102.080000 181.976000 102.120000 182.016000 ;
    END
    PORT
      LAYER M5 ;
        RECT 104.560000 0.000000 104.600000 0.040000 ;
    END
    PORT
      LAYER M5 ;
        RECT 104.560000 181.976000 104.600000 182.016000 ;
    END
    PORT
      LAYER M5 ;
        RECT 107.120000 0.000000 107.160000 0.040000 ;
    END
    PORT
      LAYER M5 ;
        RECT 107.120000 181.976000 107.160000 182.016000 ;
    END
    PORT
      LAYER M5 ;
        RECT 109.600000 0.000000 109.640000 0.040000 ;
    END
    PORT
      LAYER M5 ;
        RECT 109.600000 181.976000 109.640000 182.016000 ;
    END
    PORT
      LAYER M5 ;
        RECT 112.160000 0.000000 112.200000 0.040000 ;
    END
    PORT
      LAYER M5 ;
        RECT 112.160000 181.976000 112.200000 182.016000 ;
    END
    PORT
      LAYER M5 ;
        RECT 114.640000 0.000000 114.680000 0.040000 ;
    END
    PORT
      LAYER M5 ;
        RECT 114.640000 181.976000 114.680000 182.016000 ;
    END
    PORT
      LAYER M5 ;
        RECT 117.200000 0.000000 117.240000 0.040000 ;
    END
    PORT
      LAYER M5 ;
        RECT 117.200000 181.976000 117.240000 182.016000 ;
    END
    PORT
      LAYER M5 ;
        RECT 119.680000 0.000000 119.720000 0.040000 ;
    END
    PORT
      LAYER M5 ;
        RECT 119.680000 181.976000 119.720000 182.016000 ;
    END
    PORT
      LAYER M5 ;
        RECT 122.240000 0.000000 122.280000 0.040000 ;
    END
    PORT
      LAYER M5 ;
        RECT 122.240000 181.976000 122.280000 182.016000 ;
    END
    PORT
      LAYER M5 ;
        RECT 124.720000 0.000000 124.760000 0.040000 ;
    END
    PORT
      LAYER M5 ;
        RECT 124.720000 181.976000 124.760000 182.016000 ;
    END
    PORT
      LAYER M5 ;
        RECT 127.280000 0.000000 127.320000 0.040000 ;
    END
    PORT
      LAYER M5 ;
        RECT 127.280000 181.976000 127.320000 182.016000 ;
    END
    PORT
      LAYER M5 ;
        RECT 129.760000 0.000000 129.800000 0.040000 ;
    END
    PORT
      LAYER M5 ;
        RECT 129.760000 181.976000 129.800000 182.016000 ;
    END
    PORT
      LAYER M5 ;
        RECT 132.320000 0.000000 132.360000 0.040000 ;
    END
    PORT
      LAYER M5 ;
        RECT 132.320000 181.976000 132.360000 182.016000 ;
    END
    PORT
      LAYER M5 ;
        RECT 134.800000 0.000000 134.840000 0.040000 ;
    END
    PORT
      LAYER M5 ;
        RECT 134.800000 181.976000 134.840000 182.016000 ;
    END
    PORT
      LAYER M5 ;
        RECT 137.360000 0.000000 137.400000 0.040000 ;
    END
    PORT
      LAYER M5 ;
        RECT 137.360000 181.976000 137.400000 182.016000 ;
    END
    PORT
      LAYER M5 ;
        RECT 139.840000 0.000000 139.880000 0.040000 ;
    END
    PORT
      LAYER M5 ;
        RECT 139.840000 181.976000 139.880000 182.016000 ;
    END
    PORT
      LAYER M5 ;
        RECT 142.400000 0.000000 142.440000 0.040000 ;
    END
    PORT
      LAYER M5 ;
        RECT 142.400000 181.976000 142.440000 182.016000 ;
    END
    PORT
      LAYER M5 ;
        RECT 144.880000 0.000000 144.920000 0.040000 ;
    END
    PORT
      LAYER M5 ;
        RECT 144.880000 181.976000 144.920000 182.016000 ;
    END
    PORT
      LAYER M5 ;
        RECT 147.440000 0.000000 147.480000 0.040000 ;
    END
    PORT
      LAYER M5 ;
        RECT 147.440000 181.976000 147.480000 182.016000 ;
    END
    PORT
      LAYER M5 ;
        RECT 149.920000 0.000000 149.960000 0.040000 ;
    END
    PORT
      LAYER M5 ;
        RECT 149.920000 181.976000 149.960000 182.016000 ;
    END
    PORT
      LAYER M5 ;
        RECT 152.480000 0.000000 152.520000 0.040000 ;
    END
    PORT
      LAYER M5 ;
        RECT 152.480000 181.976000 152.520000 182.016000 ;
    END
    PORT
      LAYER M5 ;
        RECT 154.960000 0.000000 155.000000 0.040000 ;
    END
    PORT
      LAYER M5 ;
        RECT 154.960000 181.976000 155.000000 182.016000 ;
    END
    PORT
      LAYER M5 ;
        RECT 157.520000 0.000000 157.560000 0.040000 ;
    END
    PORT
      LAYER M5 ;
        RECT 157.520000 181.976000 157.560000 182.016000 ;
    END
    PORT
      LAYER M5 ;
        RECT 160.000000 0.000000 160.040000 0.040000 ;
    END
    PORT
      LAYER M5 ;
        RECT 160.000000 181.976000 160.040000 182.016000 ;
    END
    PORT
      LAYER M5 ;
        RECT 162.560000 0.000000 162.600000 0.040000 ;
    END
    PORT
      LAYER M5 ;
        RECT 162.560000 181.976000 162.600000 182.016000 ;
    END
    PORT
      LAYER M5 ;
        RECT 165.040000 0.000000 165.080000 0.040000 ;
    END
    PORT
      LAYER M5 ;
        RECT 165.040000 181.976000 165.080000 182.016000 ;
    END
    PORT
      LAYER M5 ;
        RECT 167.600000 0.000000 167.640000 0.040000 ;
    END
    PORT
      LAYER M5 ;
        RECT 167.600000 181.976000 167.640000 182.016000 ;
    END
    PORT
      LAYER M5 ;
        RECT 170.080000 0.000000 170.120000 0.040000 ;
    END
    PORT
      LAYER M5 ;
        RECT 170.080000 181.976000 170.120000 182.016000 ;
    END
    PORT
      LAYER M5 ;
        RECT 172.640000 0.000000 172.680000 0.040000 ;
    END
    PORT
      LAYER M5 ;
        RECT 172.640000 181.976000 172.680000 182.016000 ;
    END
    PORT
      LAYER M5 ;
        RECT 175.120000 0.000000 175.160000 0.040000 ;
    END
    PORT
      LAYER M5 ;
        RECT 175.120000 181.976000 175.160000 182.016000 ;
    END
    PORT
      LAYER M5 ;
        RECT 177.680000 0.000000 177.720000 0.040000 ;
    END
    PORT
      LAYER M5 ;
        RECT 177.680000 181.976000 177.720000 182.016000 ;
    END
    PORT
      LAYER M5 ;
        RECT 180.160000 0.000000 180.200000 0.040000 ;
    END
    PORT
      LAYER M5 ;
        RECT 180.160000 181.976000 180.200000 182.016000 ;
    END
    PORT
      LAYER M5 ;
        RECT 182.720000 0.000000 182.760000 0.040000 ;
    END
    PORT
      LAYER M5 ;
        RECT 182.720000 181.976000 182.760000 182.016000 ;
    END
    PORT
      LAYER M5 ;
        RECT 185.200000 0.000000 185.240000 0.040000 ;
    END
    PORT
      LAYER M5 ;
        RECT 185.200000 181.976000 185.240000 182.016000 ;
    END
    PORT
      LAYER M5 ;
        RECT 187.760000 0.000000 187.800000 0.040000 ;
    END
    PORT
      LAYER M5 ;
        RECT 187.760000 181.976000 187.800000 182.016000 ;
    END
    PORT
      LAYER M5 ;
        RECT 190.240000 0.000000 190.280000 0.040000 ;
    END
    PORT
      LAYER M5 ;
        RECT 190.240000 181.976000 190.280000 182.016000 ;
    END
    PORT
      LAYER M5 ;
        RECT 192.800000 0.000000 192.840000 0.040000 ;
    END
    PORT
      LAYER M5 ;
        RECT 192.800000 181.976000 192.840000 182.016000 ;
    END
    PORT
      LAYER M5 ;
        RECT 195.280000 0.000000 195.320000 0.040000 ;
    END
    PORT
      LAYER M5 ;
        RECT 195.280000 181.976000 195.320000 182.016000 ;
    END
    PORT
      LAYER M5 ;
        RECT 197.840000 0.000000 197.880000 0.040000 ;
    END
    PORT
      LAYER M5 ;
        RECT 197.840000 181.976000 197.880000 182.016000 ;
    END
    PORT
      LAYER M5 ;
        RECT 200.320000 0.000000 200.360000 0.040000 ;
    END
    PORT
      LAYER M5 ;
        RECT 200.320000 181.976000 200.360000 182.016000 ;
    END
    PORT
      LAYER M5 ;
        RECT 202.880000 0.000000 202.920000 0.040000 ;
    END
    PORT
      LAYER M5 ;
        RECT 202.880000 181.976000 202.920000 182.016000 ;
    END
    PORT
      LAYER M5 ;
        RECT 205.360000 0.000000 205.400000 0.040000 ;
    END
    PORT
      LAYER M5 ;
        RECT 205.360000 181.976000 205.400000 182.016000 ;
    END
    PORT
      LAYER M5 ;
        RECT 207.920000 0.000000 207.960000 0.040000 ;
    END
    PORT
      LAYER M5 ;
        RECT 207.920000 181.976000 207.960000 182.016000 ;
    END
    PORT
      LAYER M5 ;
        RECT 210.400000 0.000000 210.440000 0.040000 ;
    END
    PORT
      LAYER M5 ;
        RECT 210.400000 181.976000 210.440000 182.016000 ;
    END
    PORT
      LAYER M5 ;
        RECT 212.960000 0.000000 213.000000 0.040000 ;
    END
    PORT
      LAYER M5 ;
        RECT 212.960000 181.976000 213.000000 182.016000 ;
    END
    PORT
      LAYER M5 ;
        RECT 215.440000 0.000000 215.480000 0.040000 ;
    END
    PORT
      LAYER M5 ;
        RECT 215.440000 181.976000 215.480000 182.016000 ;
    END
    PORT
      LAYER M6 ;
        RECT 0.000000 1.228000 0.040000 1.268000 ;
    END
    PORT
      LAYER M6 ;
        RECT 215.960000 1.228000 216.000000 1.268000 ;
    END
    PORT
      LAYER M6 ;
        RECT 0.000000 3.468000 0.040000 3.508000 ;
    END
    PORT
      LAYER M6 ;
        RECT 215.960000 3.468000 216.000000 3.508000 ;
    END
    PORT
      LAYER M6 ;
        RECT 0.000000 5.788000 0.040000 5.828000 ;
    END
    PORT
      LAYER M6 ;
        RECT 215.960000 5.788000 216.000000 5.828000 ;
    END
    PORT
      LAYER M6 ;
        RECT 0.000000 8.028000 0.040000 8.068000 ;
    END
    PORT
      LAYER M6 ;
        RECT 215.960000 8.028000 216.000000 8.068000 ;
    END
    PORT
      LAYER M6 ;
        RECT 0.000000 10.348000 0.040000 10.388000 ;
    END
    PORT
      LAYER M6 ;
        RECT 215.960000 10.348000 216.000000 10.388000 ;
    END
    PORT
      LAYER M6 ;
        RECT 0.000000 12.668000 0.040000 12.708000 ;
    END
    PORT
      LAYER M6 ;
        RECT 215.960000 12.668000 216.000000 12.708000 ;
    END
    PORT
      LAYER M6 ;
        RECT 0.000000 14.988000 0.040000 15.028000 ;
    END
    PORT
      LAYER M6 ;
        RECT 215.960000 14.988000 216.000000 15.028000 ;
    END
    PORT
      LAYER M6 ;
        RECT 0.000000 17.308000 0.040000 17.348000 ;
    END
    PORT
      LAYER M6 ;
        RECT 215.960000 17.308000 216.000000 17.348000 ;
    END
    PORT
      LAYER M6 ;
        RECT 0.000000 19.548000 0.040000 19.588000 ;
    END
    PORT
      LAYER M6 ;
        RECT 215.960000 19.548000 216.000000 19.588000 ;
    END
    PORT
      LAYER M6 ;
        RECT 0.000000 21.868000 0.040000 21.908000 ;
    END
    PORT
      LAYER M6 ;
        RECT 215.960000 21.868000 216.000000 21.908000 ;
    END
    PORT
      LAYER M6 ;
        RECT 0.000000 24.188000 0.040000 24.228000 ;
    END
    PORT
      LAYER M6 ;
        RECT 215.960000 24.188000 216.000000 24.228000 ;
    END
    PORT
      LAYER M6 ;
        RECT 0.000000 26.508000 0.040000 26.548000 ;
    END
    PORT
      LAYER M6 ;
        RECT 215.960000 26.508000 216.000000 26.548000 ;
    END
    PORT
      LAYER M6 ;
        RECT 0.000000 28.828000 0.040000 28.868000 ;
    END
    PORT
      LAYER M6 ;
        RECT 215.960000 28.828000 216.000000 28.868000 ;
    END
    PORT
      LAYER M6 ;
        RECT 0.000000 31.068000 0.040000 31.108000 ;
    END
    PORT
      LAYER M6 ;
        RECT 215.960000 31.068000 216.000000 31.108000 ;
    END
    PORT
      LAYER M6 ;
        RECT 0.000000 33.388000 0.040000 33.428000 ;
    END
    PORT
      LAYER M6 ;
        RECT 215.960000 33.388000 216.000000 33.428000 ;
    END
    PORT
      LAYER M6 ;
        RECT 0.000000 35.708000 0.040000 35.748000 ;
    END
    PORT
      LAYER M6 ;
        RECT 215.960000 35.708000 216.000000 35.748000 ;
    END
    PORT
      LAYER M6 ;
        RECT 0.000000 38.028000 0.040000 38.068000 ;
    END
    PORT
      LAYER M6 ;
        RECT 215.960000 38.028000 216.000000 38.068000 ;
    END
    PORT
      LAYER M6 ;
        RECT 0.000000 40.348000 0.040000 40.388000 ;
    END
    PORT
      LAYER M6 ;
        RECT 215.960000 40.348000 216.000000 40.388000 ;
    END
    PORT
      LAYER M6 ;
        RECT 0.000000 42.588000 0.040000 42.628000 ;
    END
    PORT
      LAYER M6 ;
        RECT 215.960000 42.588000 216.000000 42.628000 ;
    END
    PORT
      LAYER M6 ;
        RECT 0.000000 44.908000 0.040000 44.948000 ;
    END
    PORT
      LAYER M6 ;
        RECT 215.960000 44.908000 216.000000 44.948000 ;
    END
    PORT
      LAYER M6 ;
        RECT 0.000000 47.228000 0.040000 47.268000 ;
    END
    PORT
      LAYER M6 ;
        RECT 215.960000 47.228000 216.000000 47.268000 ;
    END
    PORT
      LAYER M6 ;
        RECT 0.000000 49.548000 0.040000 49.588000 ;
    END
    PORT
      LAYER M6 ;
        RECT 215.960000 49.548000 216.000000 49.588000 ;
    END
    PORT
      LAYER M6 ;
        RECT 0.000000 51.868000 0.040000 51.908000 ;
    END
    PORT
      LAYER M6 ;
        RECT 215.960000 51.868000 216.000000 51.908000 ;
    END
    PORT
      LAYER M6 ;
        RECT 0.000000 54.108000 0.040000 54.148000 ;
    END
    PORT
      LAYER M6 ;
        RECT 215.960000 54.108000 216.000000 54.148000 ;
    END
    PORT
      LAYER M6 ;
        RECT 0.000000 56.428000 0.040000 56.468000 ;
    END
    PORT
      LAYER M6 ;
        RECT 215.960000 56.428000 216.000000 56.468000 ;
    END
    PORT
      LAYER M6 ;
        RECT 0.000000 58.748000 0.040000 58.788000 ;
    END
    PORT
      LAYER M6 ;
        RECT 215.960000 58.748000 216.000000 58.788000 ;
    END
    PORT
      LAYER M6 ;
        RECT 0.000000 61.068000 0.040000 61.108000 ;
    END
    PORT
      LAYER M6 ;
        RECT 215.960000 61.068000 216.000000 61.108000 ;
    END
    PORT
      LAYER M6 ;
        RECT 0.000000 63.388000 0.040000 63.428000 ;
    END
    PORT
      LAYER M6 ;
        RECT 215.960000 63.388000 216.000000 63.428000 ;
    END
    PORT
      LAYER M6 ;
        RECT 0.000000 65.628000 0.040000 65.668000 ;
    END
    PORT
      LAYER M6 ;
        RECT 215.960000 65.628000 216.000000 65.668000 ;
    END
    PORT
      LAYER M6 ;
        RECT 0.000000 67.948000 0.040000 67.988000 ;
    END
    PORT
      LAYER M6 ;
        RECT 215.960000 67.948000 216.000000 67.988000 ;
    END
    PORT
      LAYER M6 ;
        RECT 0.000000 70.268000 0.040000 70.308000 ;
    END
    PORT
      LAYER M6 ;
        RECT 215.960000 70.268000 216.000000 70.308000 ;
    END
    PORT
      LAYER M6 ;
        RECT 0.000000 72.588000 0.040000 72.628000 ;
    END
    PORT
      LAYER M6 ;
        RECT 215.960000 72.588000 216.000000 72.628000 ;
    END
    PORT
      LAYER M6 ;
        RECT 0.000000 74.908000 0.040000 74.948000 ;
    END
    PORT
      LAYER M6 ;
        RECT 215.960000 74.908000 216.000000 74.948000 ;
    END
    PORT
      LAYER M6 ;
        RECT 0.000000 77.148000 0.040000 77.188000 ;
    END
    PORT
      LAYER M6 ;
        RECT 215.960000 77.148000 216.000000 77.188000 ;
    END
    PORT
      LAYER M6 ;
        RECT 0.000000 79.468000 0.040000 79.508000 ;
    END
    PORT
      LAYER M6 ;
        RECT 215.960000 79.468000 216.000000 79.508000 ;
    END
    PORT
      LAYER M6 ;
        RECT 0.000000 81.788000 0.040000 81.828000 ;
    END
    PORT
      LAYER M6 ;
        RECT 215.960000 81.788000 216.000000 81.828000 ;
    END
    PORT
      LAYER M6 ;
        RECT 0.000000 84.108000 0.040000 84.148000 ;
    END
    PORT
      LAYER M6 ;
        RECT 215.960000 84.108000 216.000000 84.148000 ;
    END
    PORT
      LAYER M6 ;
        RECT 0.000000 86.428000 0.040000 86.468000 ;
    END
    PORT
      LAYER M6 ;
        RECT 215.960000 86.428000 216.000000 86.468000 ;
    END
    PORT
      LAYER M6 ;
        RECT 0.000000 88.668000 0.040000 88.708000 ;
    END
    PORT
      LAYER M6 ;
        RECT 215.960000 88.668000 216.000000 88.708000 ;
    END
    PORT
      LAYER M6 ;
        RECT 0.000000 90.988000 0.040000 91.028000 ;
    END
    PORT
      LAYER M6 ;
        RECT 215.960000 90.988000 216.000000 91.028000 ;
    END
    PORT
      LAYER M6 ;
        RECT 0.000000 93.308000 0.040000 93.348000 ;
    END
    PORT
      LAYER M6 ;
        RECT 215.960000 93.308000 216.000000 93.348000 ;
    END
    PORT
      LAYER M6 ;
        RECT 0.000000 95.628000 0.040000 95.668000 ;
    END
    PORT
      LAYER M6 ;
        RECT 215.960000 95.628000 216.000000 95.668000 ;
    END
    PORT
      LAYER M6 ;
        RECT 0.000000 97.948000 0.040000 97.988000 ;
    END
    PORT
      LAYER M6 ;
        RECT 215.960000 97.948000 216.000000 97.988000 ;
    END
    PORT
      LAYER M6 ;
        RECT 0.000000 100.188000 0.040000 100.228000 ;
    END
    PORT
      LAYER M6 ;
        RECT 215.960000 100.188000 216.000000 100.228000 ;
    END
    PORT
      LAYER M6 ;
        RECT 0.000000 102.508000 0.040000 102.548000 ;
    END
    PORT
      LAYER M6 ;
        RECT 215.960000 102.508000 216.000000 102.548000 ;
    END
    PORT
      LAYER M6 ;
        RECT 0.000000 104.828000 0.040000 104.868000 ;
    END
    PORT
      LAYER M6 ;
        RECT 215.960000 104.828000 216.000000 104.868000 ;
    END
    PORT
      LAYER M6 ;
        RECT 0.000000 107.148000 0.040000 107.188000 ;
    END
    PORT
      LAYER M6 ;
        RECT 215.960000 107.148000 216.000000 107.188000 ;
    END
    PORT
      LAYER M6 ;
        RECT 0.000000 109.468000 0.040000 109.508000 ;
    END
    PORT
      LAYER M6 ;
        RECT 215.960000 109.468000 216.000000 109.508000 ;
    END
    PORT
      LAYER M6 ;
        RECT 0.000000 111.708000 0.040000 111.748000 ;
    END
    PORT
      LAYER M6 ;
        RECT 215.960000 111.708000 216.000000 111.748000 ;
    END
    PORT
      LAYER M6 ;
        RECT 0.000000 114.028000 0.040000 114.068000 ;
    END
    PORT
      LAYER M6 ;
        RECT 215.960000 114.028000 216.000000 114.068000 ;
    END
    PORT
      LAYER M6 ;
        RECT 0.000000 116.348000 0.040000 116.388000 ;
    END
    PORT
      LAYER M6 ;
        RECT 215.960000 116.348000 216.000000 116.388000 ;
    END
    PORT
      LAYER M6 ;
        RECT 0.000000 118.668000 0.040000 118.708000 ;
    END
    PORT
      LAYER M6 ;
        RECT 215.960000 118.668000 216.000000 118.708000 ;
    END
    PORT
      LAYER M6 ;
        RECT 0.000000 120.988000 0.040000 121.028000 ;
    END
    PORT
      LAYER M6 ;
        RECT 215.960000 120.988000 216.000000 121.028000 ;
    END
    PORT
      LAYER M6 ;
        RECT 0.000000 123.228000 0.040000 123.268000 ;
    END
    PORT
      LAYER M6 ;
        RECT 215.960000 123.228000 216.000000 123.268000 ;
    END
    PORT
      LAYER M6 ;
        RECT 0.000000 125.548000 0.040000 125.588000 ;
    END
    PORT
      LAYER M6 ;
        RECT 215.960000 125.548000 216.000000 125.588000 ;
    END
    PORT
      LAYER M6 ;
        RECT 0.000000 127.868000 0.040000 127.908000 ;
    END
    PORT
      LAYER M6 ;
        RECT 215.960000 127.868000 216.000000 127.908000 ;
    END
    PORT
      LAYER M6 ;
        RECT 0.000000 130.188000 0.040000 130.228000 ;
    END
    PORT
      LAYER M6 ;
        RECT 215.960000 130.188000 216.000000 130.228000 ;
    END
    PORT
      LAYER M6 ;
        RECT 0.000000 132.508000 0.040000 132.548000 ;
    END
    PORT
      LAYER M6 ;
        RECT 215.960000 132.508000 216.000000 132.548000 ;
    END
    PORT
      LAYER M6 ;
        RECT 0.000000 134.748000 0.040000 134.788000 ;
    END
    PORT
      LAYER M6 ;
        RECT 215.960000 134.748000 216.000000 134.788000 ;
    END
    PORT
      LAYER M6 ;
        RECT 0.000000 137.068000 0.040000 137.108000 ;
    END
    PORT
      LAYER M6 ;
        RECT 215.960000 137.068000 216.000000 137.108000 ;
    END
    PORT
      LAYER M6 ;
        RECT 0.000000 139.388000 0.040000 139.428000 ;
    END
    PORT
      LAYER M6 ;
        RECT 215.960000 139.388000 216.000000 139.428000 ;
    END
    PORT
      LAYER M6 ;
        RECT 0.000000 141.708000 0.040000 141.748000 ;
    END
    PORT
      LAYER M6 ;
        RECT 215.960000 141.708000 216.000000 141.748000 ;
    END
    PORT
      LAYER M6 ;
        RECT 0.000000 144.028000 0.040000 144.068000 ;
    END
    PORT
      LAYER M6 ;
        RECT 215.960000 144.028000 216.000000 144.068000 ;
    END
    PORT
      LAYER M6 ;
        RECT 0.000000 146.268000 0.040000 146.308000 ;
    END
    PORT
      LAYER M6 ;
        RECT 215.960000 146.268000 216.000000 146.308000 ;
    END
    PORT
      LAYER M6 ;
        RECT 0.000000 148.588000 0.040000 148.628000 ;
    END
    PORT
      LAYER M6 ;
        RECT 215.960000 148.588000 216.000000 148.628000 ;
    END
    PORT
      LAYER M6 ;
        RECT 0.000000 150.908000 0.040000 150.948000 ;
    END
    PORT
      LAYER M6 ;
        RECT 215.960000 150.908000 216.000000 150.948000 ;
    END
    PORT
      LAYER M6 ;
        RECT 0.000000 153.228000 0.040000 153.268000 ;
    END
    PORT
      LAYER M6 ;
        RECT 215.960000 153.228000 216.000000 153.268000 ;
    END
    PORT
      LAYER M6 ;
        RECT 0.000000 155.548000 0.040000 155.588000 ;
    END
    PORT
      LAYER M6 ;
        RECT 215.960000 155.548000 216.000000 155.588000 ;
    END
    PORT
      LAYER M6 ;
        RECT 0.000000 157.788000 0.040000 157.828000 ;
    END
    PORT
      LAYER M6 ;
        RECT 215.960000 157.788000 216.000000 157.828000 ;
    END
    PORT
      LAYER M6 ;
        RECT 0.000000 160.108000 0.040000 160.148000 ;
    END
    PORT
      LAYER M6 ;
        RECT 215.960000 160.108000 216.000000 160.148000 ;
    END
    PORT
      LAYER M6 ;
        RECT 0.000000 162.428000 0.040000 162.468000 ;
    END
    PORT
      LAYER M6 ;
        RECT 215.960000 162.428000 216.000000 162.468000 ;
    END
    PORT
      LAYER M6 ;
        RECT 0.000000 164.748000 0.040000 164.788000 ;
    END
    PORT
      LAYER M6 ;
        RECT 215.960000 164.748000 216.000000 164.788000 ;
    END
    PORT
      LAYER M6 ;
        RECT 0.000000 167.068000 0.040000 167.108000 ;
    END
    PORT
      LAYER M6 ;
        RECT 215.960000 167.068000 216.000000 167.108000 ;
    END
    PORT
      LAYER M6 ;
        RECT 0.000000 169.308000 0.040000 169.348000 ;
    END
    PORT
      LAYER M6 ;
        RECT 215.960000 169.308000 216.000000 169.348000 ;
    END
    PORT
      LAYER M6 ;
        RECT 0.000000 171.628000 0.040000 171.668000 ;
    END
    PORT
      LAYER M6 ;
        RECT 215.960000 171.628000 216.000000 171.668000 ;
    END
    PORT
      LAYER M6 ;
        RECT 0.000000 173.948000 0.040000 173.988000 ;
    END
    PORT
      LAYER M6 ;
        RECT 215.960000 173.948000 216.000000 173.988000 ;
    END
    PORT
      LAYER M6 ;
        RECT 0.000000 176.268000 0.040000 176.308000 ;
    END
    PORT
      LAYER M6 ;
        RECT 215.960000 176.268000 216.000000 176.308000 ;
    END
    PORT
      LAYER M6 ;
        RECT 0.000000 178.588000 0.040000 178.628000 ;
    END
    PORT
      LAYER M6 ;
        RECT 215.960000 178.588000 216.000000 178.628000 ;
    END
    PORT
      LAYER M6 ;
        RECT 0.000000 180.828000 0.040000 180.868000 ;
    END
    PORT
      LAYER M6 ;
        RECT 215.960000 180.828000 216.000000 180.868000 ;
    END
    PORT
      LAYER M7 ;
        RECT 1.320000 0.000000 1.440000 0.120000 ;
    END
    PORT
      LAYER M7 ;
        RECT 1.320000 181.896000 1.440000 182.016000 ;
    END
    PORT
      LAYER M7 ;
        RECT 3.800000 0.000000 3.920000 0.120000 ;
    END
    PORT
      LAYER M7 ;
        RECT 3.800000 181.896000 3.920000 182.016000 ;
    END
    PORT
      LAYER M7 ;
        RECT 6.280000 0.000000 6.400000 0.120000 ;
    END
    PORT
      LAYER M7 ;
        RECT 6.280000 181.896000 6.400000 182.016000 ;
    END
    PORT
      LAYER M7 ;
        RECT 8.840000 0.000000 8.960000 0.120000 ;
    END
    PORT
      LAYER M7 ;
        RECT 8.840000 181.896000 8.960000 182.016000 ;
    END
    PORT
      LAYER M7 ;
        RECT 11.320000 0.000000 11.440000 0.120000 ;
    END
    PORT
      LAYER M7 ;
        RECT 11.320000 181.896000 11.440000 182.016000 ;
    END
    PORT
      LAYER M7 ;
        RECT 13.880000 0.000000 14.000000 0.120000 ;
    END
    PORT
      LAYER M7 ;
        RECT 13.880000 181.896000 14.000000 182.016000 ;
    END
    PORT
      LAYER M7 ;
        RECT 16.360000 0.000000 16.480000 0.120000 ;
    END
    PORT
      LAYER M7 ;
        RECT 16.360000 181.896000 16.480000 182.016000 ;
    END
    PORT
      LAYER M7 ;
        RECT 18.920000 0.000000 19.040000 0.120000 ;
    END
    PORT
      LAYER M7 ;
        RECT 18.920000 181.896000 19.040000 182.016000 ;
    END
    PORT
      LAYER M7 ;
        RECT 21.400000 0.000000 21.520000 0.120000 ;
    END
    PORT
      LAYER M7 ;
        RECT 21.400000 181.896000 21.520000 182.016000 ;
    END
    PORT
      LAYER M7 ;
        RECT 23.960000 0.000000 24.080000 0.120000 ;
    END
    PORT
      LAYER M7 ;
        RECT 23.960000 181.896000 24.080000 182.016000 ;
    END
    PORT
      LAYER M7 ;
        RECT 26.440000 0.000000 26.560000 0.120000 ;
    END
    PORT
      LAYER M7 ;
        RECT 26.440000 181.896000 26.560000 182.016000 ;
    END
    PORT
      LAYER M7 ;
        RECT 29.000000 0.000000 29.120000 0.120000 ;
    END
    PORT
      LAYER M7 ;
        RECT 29.000000 181.896000 29.120000 182.016000 ;
    END
    PORT
      LAYER M7 ;
        RECT 31.480000 0.000000 31.600000 0.120000 ;
    END
    PORT
      LAYER M7 ;
        RECT 31.480000 181.896000 31.600000 182.016000 ;
    END
    PORT
      LAYER M7 ;
        RECT 34.040000 0.000000 34.160000 0.120000 ;
    END
    PORT
      LAYER M7 ;
        RECT 34.040000 181.896000 34.160000 182.016000 ;
    END
    PORT
      LAYER M7 ;
        RECT 36.520000 0.000000 36.640000 0.120000 ;
    END
    PORT
      LAYER M7 ;
        RECT 36.520000 181.896000 36.640000 182.016000 ;
    END
    PORT
      LAYER M7 ;
        RECT 39.080000 0.000000 39.200000 0.120000 ;
    END
    PORT
      LAYER M7 ;
        RECT 39.080000 181.896000 39.200000 182.016000 ;
    END
    PORT
      LAYER M7 ;
        RECT 41.560000 0.000000 41.680000 0.120000 ;
    END
    PORT
      LAYER M7 ;
        RECT 41.560000 181.896000 41.680000 182.016000 ;
    END
    PORT
      LAYER M7 ;
        RECT 44.120000 0.000000 44.240000 0.120000 ;
    END
    PORT
      LAYER M7 ;
        RECT 44.120000 181.896000 44.240000 182.016000 ;
    END
    PORT
      LAYER M7 ;
        RECT 46.600000 0.000000 46.720000 0.120000 ;
    END
    PORT
      LAYER M7 ;
        RECT 46.600000 181.896000 46.720000 182.016000 ;
    END
    PORT
      LAYER M7 ;
        RECT 49.160000 0.000000 49.280000 0.120000 ;
    END
    PORT
      LAYER M7 ;
        RECT 49.160000 181.896000 49.280000 182.016000 ;
    END
    PORT
      LAYER M7 ;
        RECT 51.640000 0.000000 51.760000 0.120000 ;
    END
    PORT
      LAYER M7 ;
        RECT 51.640000 181.896000 51.760000 182.016000 ;
    END
    PORT
      LAYER M7 ;
        RECT 54.200000 0.000000 54.320000 0.120000 ;
    END
    PORT
      LAYER M7 ;
        RECT 54.200000 181.896000 54.320000 182.016000 ;
    END
    PORT
      LAYER M7 ;
        RECT 56.680000 0.000000 56.800000 0.120000 ;
    END
    PORT
      LAYER M7 ;
        RECT 56.680000 181.896000 56.800000 182.016000 ;
    END
    PORT
      LAYER M7 ;
        RECT 59.240000 0.000000 59.360000 0.120000 ;
    END
    PORT
      LAYER M7 ;
        RECT 59.240000 181.896000 59.360000 182.016000 ;
    END
    PORT
      LAYER M7 ;
        RECT 61.720000 0.000000 61.840000 0.120000 ;
    END
    PORT
      LAYER M7 ;
        RECT 61.720000 181.896000 61.840000 182.016000 ;
    END
    PORT
      LAYER M7 ;
        RECT 64.280000 0.000000 64.400000 0.120000 ;
    END
    PORT
      LAYER M7 ;
        RECT 64.280000 181.896000 64.400000 182.016000 ;
    END
    PORT
      LAYER M7 ;
        RECT 66.760000 0.000000 66.880000 0.120000 ;
    END
    PORT
      LAYER M7 ;
        RECT 66.760000 181.896000 66.880000 182.016000 ;
    END
    PORT
      LAYER M7 ;
        RECT 69.320000 0.000000 69.440000 0.120000 ;
    END
    PORT
      LAYER M7 ;
        RECT 69.320000 181.896000 69.440000 182.016000 ;
    END
    PORT
      LAYER M7 ;
        RECT 71.800000 0.000000 71.920000 0.120000 ;
    END
    PORT
      LAYER M7 ;
        RECT 71.800000 181.896000 71.920000 182.016000 ;
    END
    PORT
      LAYER M7 ;
        RECT 74.360000 0.000000 74.480000 0.120000 ;
    END
    PORT
      LAYER M7 ;
        RECT 74.360000 181.896000 74.480000 182.016000 ;
    END
    PORT
      LAYER M7 ;
        RECT 76.840000 0.000000 76.960000 0.120000 ;
    END
    PORT
      LAYER M7 ;
        RECT 76.840000 181.896000 76.960000 182.016000 ;
    END
    PORT
      LAYER M7 ;
        RECT 79.400000 0.000000 79.520000 0.120000 ;
    END
    PORT
      LAYER M7 ;
        RECT 79.400000 181.896000 79.520000 182.016000 ;
    END
    PORT
      LAYER M7 ;
        RECT 81.880000 0.000000 82.000000 0.120000 ;
    END
    PORT
      LAYER M7 ;
        RECT 81.880000 181.896000 82.000000 182.016000 ;
    END
    PORT
      LAYER M7 ;
        RECT 84.440000 0.000000 84.560000 0.120000 ;
    END
    PORT
      LAYER M7 ;
        RECT 84.440000 181.896000 84.560000 182.016000 ;
    END
    PORT
      LAYER M7 ;
        RECT 86.920000 0.000000 87.040000 0.120000 ;
    END
    PORT
      LAYER M7 ;
        RECT 86.920000 181.896000 87.040000 182.016000 ;
    END
    PORT
      LAYER M7 ;
        RECT 89.480000 0.000000 89.600000 0.120000 ;
    END
    PORT
      LAYER M7 ;
        RECT 89.480000 181.896000 89.600000 182.016000 ;
    END
    PORT
      LAYER M7 ;
        RECT 91.960000 0.000000 92.080000 0.120000 ;
    END
    PORT
      LAYER M7 ;
        RECT 91.960000 181.896000 92.080000 182.016000 ;
    END
    PORT
      LAYER M7 ;
        RECT 94.520000 0.000000 94.640000 0.120000 ;
    END
    PORT
      LAYER M7 ;
        RECT 94.520000 181.896000 94.640000 182.016000 ;
    END
    PORT
      LAYER M7 ;
        RECT 97.000000 0.000000 97.120000 0.120000 ;
    END
    PORT
      LAYER M7 ;
        RECT 97.000000 181.896000 97.120000 182.016000 ;
    END
    PORT
      LAYER M7 ;
        RECT 99.560000 0.000000 99.680000 0.120000 ;
    END
    PORT
      LAYER M7 ;
        RECT 99.560000 181.896000 99.680000 182.016000 ;
    END
    PORT
      LAYER M7 ;
        RECT 102.040000 0.000000 102.160000 0.120000 ;
    END
    PORT
      LAYER M7 ;
        RECT 102.040000 181.896000 102.160000 182.016000 ;
    END
    PORT
      LAYER M7 ;
        RECT 104.600000 0.000000 104.720000 0.120000 ;
    END
    PORT
      LAYER M7 ;
        RECT 104.600000 181.896000 104.720000 182.016000 ;
    END
    PORT
      LAYER M7 ;
        RECT 107.080000 0.000000 107.200000 0.120000 ;
    END
    PORT
      LAYER M7 ;
        RECT 107.080000 181.896000 107.200000 182.016000 ;
    END
    PORT
      LAYER M7 ;
        RECT 109.640000 0.000000 109.760000 0.120000 ;
    END
    PORT
      LAYER M7 ;
        RECT 109.640000 181.896000 109.760000 182.016000 ;
    END
    PORT
      LAYER M7 ;
        RECT 112.120000 0.000000 112.240000 0.120000 ;
    END
    PORT
      LAYER M7 ;
        RECT 112.120000 181.896000 112.240000 182.016000 ;
    END
    PORT
      LAYER M7 ;
        RECT 114.680000 0.000000 114.800000 0.120000 ;
    END
    PORT
      LAYER M7 ;
        RECT 114.680000 181.896000 114.800000 182.016000 ;
    END
    PORT
      LAYER M7 ;
        RECT 117.160000 0.000000 117.280000 0.120000 ;
    END
    PORT
      LAYER M7 ;
        RECT 117.160000 181.896000 117.280000 182.016000 ;
    END
    PORT
      LAYER M7 ;
        RECT 119.720000 0.000000 119.840000 0.120000 ;
    END
    PORT
      LAYER M7 ;
        RECT 119.720000 181.896000 119.840000 182.016000 ;
    END
    PORT
      LAYER M7 ;
        RECT 122.200000 0.000000 122.320000 0.120000 ;
    END
    PORT
      LAYER M7 ;
        RECT 122.200000 181.896000 122.320000 182.016000 ;
    END
    PORT
      LAYER M7 ;
        RECT 124.760000 0.000000 124.880000 0.120000 ;
    END
    PORT
      LAYER M7 ;
        RECT 124.760000 181.896000 124.880000 182.016000 ;
    END
    PORT
      LAYER M7 ;
        RECT 127.240000 0.000000 127.360000 0.120000 ;
    END
    PORT
      LAYER M7 ;
        RECT 127.240000 181.896000 127.360000 182.016000 ;
    END
    PORT
      LAYER M7 ;
        RECT 129.800000 0.000000 129.920000 0.120000 ;
    END
    PORT
      LAYER M7 ;
        RECT 129.800000 181.896000 129.920000 182.016000 ;
    END
    PORT
      LAYER M7 ;
        RECT 132.280000 0.000000 132.400000 0.120000 ;
    END
    PORT
      LAYER M7 ;
        RECT 132.280000 181.896000 132.400000 182.016000 ;
    END
    PORT
      LAYER M7 ;
        RECT 134.840000 0.000000 134.960000 0.120000 ;
    END
    PORT
      LAYER M7 ;
        RECT 134.840000 181.896000 134.960000 182.016000 ;
    END
    PORT
      LAYER M7 ;
        RECT 137.320000 0.000000 137.440000 0.120000 ;
    END
    PORT
      LAYER M7 ;
        RECT 137.320000 181.896000 137.440000 182.016000 ;
    END
    PORT
      LAYER M7 ;
        RECT 139.880000 0.000000 140.000000 0.120000 ;
    END
    PORT
      LAYER M7 ;
        RECT 139.880000 181.896000 140.000000 182.016000 ;
    END
    PORT
      LAYER M7 ;
        RECT 142.360000 0.000000 142.480000 0.120000 ;
    END
    PORT
      LAYER M7 ;
        RECT 142.360000 181.896000 142.480000 182.016000 ;
    END
    PORT
      LAYER M7 ;
        RECT 144.920000 0.000000 145.040000 0.120000 ;
    END
    PORT
      LAYER M7 ;
        RECT 144.920000 181.896000 145.040000 182.016000 ;
    END
    PORT
      LAYER M7 ;
        RECT 147.400000 0.000000 147.520000 0.120000 ;
    END
    PORT
      LAYER M7 ;
        RECT 147.400000 181.896000 147.520000 182.016000 ;
    END
    PORT
      LAYER M7 ;
        RECT 149.960000 0.000000 150.080000 0.120000 ;
    END
    PORT
      LAYER M7 ;
        RECT 149.960000 181.896000 150.080000 182.016000 ;
    END
    PORT
      LAYER M7 ;
        RECT 152.440000 0.000000 152.560000 0.120000 ;
    END
    PORT
      LAYER M7 ;
        RECT 152.440000 181.896000 152.560000 182.016000 ;
    END
    PORT
      LAYER M7 ;
        RECT 155.000000 0.000000 155.120000 0.120000 ;
    END
    PORT
      LAYER M7 ;
        RECT 155.000000 181.896000 155.120000 182.016000 ;
    END
    PORT
      LAYER M7 ;
        RECT 157.480000 0.000000 157.600000 0.120000 ;
    END
    PORT
      LAYER M7 ;
        RECT 157.480000 181.896000 157.600000 182.016000 ;
    END
    PORT
      LAYER M7 ;
        RECT 160.040000 0.000000 160.160000 0.120000 ;
    END
    PORT
      LAYER M7 ;
        RECT 160.040000 181.896000 160.160000 182.016000 ;
    END
    PORT
      LAYER M7 ;
        RECT 162.520000 0.000000 162.640000 0.120000 ;
    END
    PORT
      LAYER M7 ;
        RECT 162.520000 181.896000 162.640000 182.016000 ;
    END
    PORT
      LAYER M7 ;
        RECT 165.080000 0.000000 165.200000 0.120000 ;
    END
    PORT
      LAYER M7 ;
        RECT 165.080000 181.896000 165.200000 182.016000 ;
    END
    PORT
      LAYER M7 ;
        RECT 167.560000 0.000000 167.680000 0.120000 ;
    END
    PORT
      LAYER M7 ;
        RECT 167.560000 181.896000 167.680000 182.016000 ;
    END
    PORT
      LAYER M7 ;
        RECT 170.120000 0.000000 170.240000 0.120000 ;
    END
    PORT
      LAYER M7 ;
        RECT 170.120000 181.896000 170.240000 182.016000 ;
    END
    PORT
      LAYER M7 ;
        RECT 172.600000 0.000000 172.720000 0.120000 ;
    END
    PORT
      LAYER M7 ;
        RECT 172.600000 181.896000 172.720000 182.016000 ;
    END
    PORT
      LAYER M7 ;
        RECT 175.160000 0.000000 175.280000 0.120000 ;
    END
    PORT
      LAYER M7 ;
        RECT 175.160000 181.896000 175.280000 182.016000 ;
    END
    PORT
      LAYER M7 ;
        RECT 177.640000 0.000000 177.760000 0.120000 ;
    END
    PORT
      LAYER M7 ;
        RECT 177.640000 181.896000 177.760000 182.016000 ;
    END
    PORT
      LAYER M7 ;
        RECT 180.200000 0.000000 180.320000 0.120000 ;
    END
    PORT
      LAYER M7 ;
        RECT 180.200000 181.896000 180.320000 182.016000 ;
    END
    PORT
      LAYER M7 ;
        RECT 182.680000 0.000000 182.800000 0.120000 ;
    END
    PORT
      LAYER M7 ;
        RECT 182.680000 181.896000 182.800000 182.016000 ;
    END
    PORT
      LAYER M7 ;
        RECT 185.240000 0.000000 185.360000 0.120000 ;
    END
    PORT
      LAYER M7 ;
        RECT 185.240000 181.896000 185.360000 182.016000 ;
    END
    PORT
      LAYER M7 ;
        RECT 187.720000 0.000000 187.840000 0.120000 ;
    END
    PORT
      LAYER M7 ;
        RECT 187.720000 181.896000 187.840000 182.016000 ;
    END
    PORT
      LAYER M7 ;
        RECT 190.280000 0.000000 190.400000 0.120000 ;
    END
    PORT
      LAYER M7 ;
        RECT 190.280000 181.896000 190.400000 182.016000 ;
    END
    PORT
      LAYER M7 ;
        RECT 192.760000 0.000000 192.880000 0.120000 ;
    END
    PORT
      LAYER M7 ;
        RECT 192.760000 181.896000 192.880000 182.016000 ;
    END
    PORT
      LAYER M7 ;
        RECT 195.320000 0.000000 195.440000 0.120000 ;
    END
    PORT
      LAYER M7 ;
        RECT 195.320000 181.896000 195.440000 182.016000 ;
    END
    PORT
      LAYER M7 ;
        RECT 197.800000 0.000000 197.920000 0.120000 ;
    END
    PORT
      LAYER M7 ;
        RECT 197.800000 181.896000 197.920000 182.016000 ;
    END
    PORT
      LAYER M7 ;
        RECT 200.360000 0.000000 200.480000 0.120000 ;
    END
    PORT
      LAYER M7 ;
        RECT 200.360000 181.896000 200.480000 182.016000 ;
    END
    PORT
      LAYER M7 ;
        RECT 202.840000 0.000000 202.960000 0.120000 ;
    END
    PORT
      LAYER M7 ;
        RECT 202.840000 181.896000 202.960000 182.016000 ;
    END
    PORT
      LAYER M7 ;
        RECT 205.400000 0.000000 205.520000 0.120000 ;
    END
    PORT
      LAYER M7 ;
        RECT 205.400000 181.896000 205.520000 182.016000 ;
    END
    PORT
      LAYER M7 ;
        RECT 207.880000 0.000000 208.000000 0.120000 ;
    END
    PORT
      LAYER M7 ;
        RECT 207.880000 181.896000 208.000000 182.016000 ;
    END
    PORT
      LAYER M7 ;
        RECT 210.440000 0.000000 210.560000 0.120000 ;
    END
    PORT
      LAYER M7 ;
        RECT 210.440000 181.896000 210.560000 182.016000 ;
    END
    PORT
      LAYER M7 ;
        RECT 212.920000 0.000000 213.040000 0.120000 ;
    END
    PORT
      LAYER M7 ;
        RECT 212.920000 181.896000 213.040000 182.016000 ;
    END
    PORT
      LAYER M7 ;
        RECT 215.480000 0.000000 215.600000 0.120000 ;
    END
    PORT
      LAYER M7 ;
        RECT 215.480000 181.896000 215.600000 182.016000 ;
    END
    PORT
      LAYER M8 ;
        RECT 0.000000 1.175000 0.062000 1.237000 ;
    END
    PORT
      LAYER M8 ;
        RECT 215.938000 1.175000 216.000000 1.237000 ;
    END
    PORT
      LAYER M8 ;
        RECT 0.000000 3.443000 0.062000 3.505000 ;
    END
    PORT
      LAYER M8 ;
        RECT 215.938000 3.443000 216.000000 3.505000 ;
    END
    PORT
      LAYER M8 ;
        RECT 0.000000 5.711000 0.062000 5.773000 ;
    END
    PORT
      LAYER M8 ;
        RECT 215.938000 5.711000 216.000000 5.773000 ;
    END
    PORT
      LAYER M8 ;
        RECT 0.000000 8.105000 0.062000 8.167000 ;
    END
    PORT
      LAYER M8 ;
        RECT 215.938000 8.105000 216.000000 8.167000 ;
    END
    PORT
      LAYER M8 ;
        RECT 0.000000 10.373000 0.062000 10.435000 ;
    END
    PORT
      LAYER M8 ;
        RECT 215.938000 10.373000 216.000000 10.435000 ;
    END
    PORT
      LAYER M8 ;
        RECT 0.000000 12.641000 0.062000 12.703000 ;
    END
    PORT
      LAYER M8 ;
        RECT 215.938000 12.641000 216.000000 12.703000 ;
    END
    PORT
      LAYER M8 ;
        RECT 0.000000 15.035000 0.062000 15.097000 ;
    END
    PORT
      LAYER M8 ;
        RECT 215.938000 15.035000 216.000000 15.097000 ;
    END
    PORT
      LAYER M8 ;
        RECT 0.000000 17.303000 0.062000 17.365000 ;
    END
    PORT
      LAYER M8 ;
        RECT 215.938000 17.303000 216.000000 17.365000 ;
    END
    PORT
      LAYER M8 ;
        RECT 0.000000 19.571000 0.062000 19.633000 ;
    END
    PORT
      LAYER M8 ;
        RECT 215.938000 19.571000 216.000000 19.633000 ;
    END
    PORT
      LAYER M8 ;
        RECT 0.000000 21.839000 0.062000 21.901000 ;
    END
    PORT
      LAYER M8 ;
        RECT 215.938000 21.839000 216.000000 21.901000 ;
    END
    PORT
      LAYER M8 ;
        RECT 0.000000 24.233000 0.062000 24.295000 ;
    END
    PORT
      LAYER M8 ;
        RECT 215.938000 24.233000 216.000000 24.295000 ;
    END
    PORT
      LAYER M8 ;
        RECT 0.000000 26.501000 0.062000 26.563000 ;
    END
    PORT
      LAYER M8 ;
        RECT 215.938000 26.501000 216.000000 26.563000 ;
    END
    PORT
      LAYER M8 ;
        RECT 0.000000 28.769000 0.062000 28.831000 ;
    END
    PORT
      LAYER M8 ;
        RECT 215.938000 28.769000 216.000000 28.831000 ;
    END
    PORT
      LAYER M8 ;
        RECT 0.000000 31.163000 0.062000 31.225000 ;
    END
    PORT
      LAYER M8 ;
        RECT 215.938000 31.163000 216.000000 31.225000 ;
    END
    PORT
      LAYER M8 ;
        RECT 0.000000 33.431000 0.062000 33.493000 ;
    END
    PORT
      LAYER M8 ;
        RECT 215.938000 33.431000 216.000000 33.493000 ;
    END
    PORT
      LAYER M8 ;
        RECT 0.000000 35.699000 0.062000 35.761000 ;
    END
    PORT
      LAYER M8 ;
        RECT 215.938000 35.699000 216.000000 35.761000 ;
    END
    PORT
      LAYER M8 ;
        RECT 0.000000 37.967000 0.062000 38.029000 ;
    END
    PORT
      LAYER M8 ;
        RECT 215.938000 37.967000 216.000000 38.029000 ;
    END
    PORT
      LAYER M8 ;
        RECT 0.000000 40.361000 0.062000 40.423000 ;
    END
    PORT
      LAYER M8 ;
        RECT 215.938000 40.361000 216.000000 40.423000 ;
    END
    PORT
      LAYER M8 ;
        RECT 0.000000 42.629000 0.062000 42.691000 ;
    END
    PORT
      LAYER M8 ;
        RECT 215.938000 42.629000 216.000000 42.691000 ;
    END
    PORT
      LAYER M8 ;
        RECT 0.000000 44.897000 0.062000 44.959000 ;
    END
    PORT
      LAYER M8 ;
        RECT 215.938000 44.897000 216.000000 44.959000 ;
    END
    PORT
      LAYER M8 ;
        RECT 0.000000 47.291000 0.062000 47.353000 ;
    END
    PORT
      LAYER M8 ;
        RECT 215.938000 47.291000 216.000000 47.353000 ;
    END
    PORT
      LAYER M8 ;
        RECT 0.000000 49.559000 0.062000 49.621000 ;
    END
    PORT
      LAYER M8 ;
        RECT 215.938000 49.559000 216.000000 49.621000 ;
    END
    PORT
      LAYER M8 ;
        RECT 0.000000 51.827000 0.062000 51.889000 ;
    END
    PORT
      LAYER M8 ;
        RECT 215.938000 51.827000 216.000000 51.889000 ;
    END
    PORT
      LAYER M8 ;
        RECT 0.000000 54.095000 0.062000 54.157000 ;
    END
    PORT
      LAYER M8 ;
        RECT 215.938000 54.095000 216.000000 54.157000 ;
    END
    PORT
      LAYER M8 ;
        RECT 0.000000 56.489000 0.062000 56.551000 ;
    END
    PORT
      LAYER M8 ;
        RECT 215.938000 56.489000 216.000000 56.551000 ;
    END
    PORT
      LAYER M8 ;
        RECT 0.000000 58.757000 0.062000 58.819000 ;
    END
    PORT
      LAYER M8 ;
        RECT 215.938000 58.757000 216.000000 58.819000 ;
    END
    PORT
      LAYER M8 ;
        RECT 0.000000 61.025000 0.062000 61.087000 ;
    END
    PORT
      LAYER M8 ;
        RECT 215.938000 61.025000 216.000000 61.087000 ;
    END
    PORT
      LAYER M8 ;
        RECT 0.000000 63.419000 0.062000 63.481000 ;
    END
    PORT
      LAYER M8 ;
        RECT 215.938000 63.419000 216.000000 63.481000 ;
    END
    PORT
      LAYER M8 ;
        RECT 0.000000 65.687000 0.062000 65.749000 ;
    END
    PORT
      LAYER M8 ;
        RECT 215.938000 65.687000 216.000000 65.749000 ;
    END
    PORT
      LAYER M8 ;
        RECT 0.000000 67.955000 0.062000 68.017000 ;
    END
    PORT
      LAYER M8 ;
        RECT 215.938000 67.955000 216.000000 68.017000 ;
    END
    PORT
      LAYER M8 ;
        RECT 0.000000 70.223000 0.062000 70.285000 ;
    END
    PORT
      LAYER M8 ;
        RECT 215.938000 70.223000 216.000000 70.285000 ;
    END
    PORT
      LAYER M8 ;
        RECT 0.000000 72.617000 0.062000 72.679000 ;
    END
    PORT
      LAYER M8 ;
        RECT 215.938000 72.617000 216.000000 72.679000 ;
    END
    PORT
      LAYER M8 ;
        RECT 0.000000 74.885000 0.062000 74.947000 ;
    END
    PORT
      LAYER M8 ;
        RECT 215.938000 74.885000 216.000000 74.947000 ;
    END
    PORT
      LAYER M8 ;
        RECT 0.000000 77.153000 0.062000 77.215000 ;
    END
    PORT
      LAYER M8 ;
        RECT 215.938000 77.153000 216.000000 77.215000 ;
    END
    PORT
      LAYER M8 ;
        RECT 0.000000 79.547000 0.062000 79.609000 ;
    END
    PORT
      LAYER M8 ;
        RECT 215.938000 79.547000 216.000000 79.609000 ;
    END
    PORT
      LAYER M8 ;
        RECT 0.000000 81.815000 0.062000 81.877000 ;
    END
    PORT
      LAYER M8 ;
        RECT 215.938000 81.815000 216.000000 81.877000 ;
    END
    PORT
      LAYER M8 ;
        RECT 0.000000 84.083000 0.062000 84.145000 ;
    END
    PORT
      LAYER M8 ;
        RECT 215.938000 84.083000 216.000000 84.145000 ;
    END
    PORT
      LAYER M8 ;
        RECT 0.000000 86.351000 0.062000 86.413000 ;
    END
    PORT
      LAYER M8 ;
        RECT 215.938000 86.351000 216.000000 86.413000 ;
    END
    PORT
      LAYER M8 ;
        RECT 0.000000 88.745000 0.062000 88.807000 ;
    END
    PORT
      LAYER M8 ;
        RECT 215.938000 88.745000 216.000000 88.807000 ;
    END
    PORT
      LAYER M8 ;
        RECT 0.000000 91.013000 0.062000 91.075000 ;
    END
    PORT
      LAYER M8 ;
        RECT 215.938000 91.013000 216.000000 91.075000 ;
    END
    PORT
      LAYER M8 ;
        RECT 0.000000 93.281000 0.062000 93.343000 ;
    END
    PORT
      LAYER M8 ;
        RECT 215.938000 93.281000 216.000000 93.343000 ;
    END
    PORT
      LAYER M8 ;
        RECT 0.000000 95.675000 0.062000 95.737000 ;
    END
    PORT
      LAYER M8 ;
        RECT 215.938000 95.675000 216.000000 95.737000 ;
    END
    PORT
      LAYER M8 ;
        RECT 0.000000 97.943000 0.062000 98.005000 ;
    END
    PORT
      LAYER M8 ;
        RECT 215.938000 97.943000 216.000000 98.005000 ;
    END
    PORT
      LAYER M8 ;
        RECT 0.000000 100.211000 0.062000 100.273000 ;
    END
    PORT
      LAYER M8 ;
        RECT 215.938000 100.211000 216.000000 100.273000 ;
    END
    PORT
      LAYER M8 ;
        RECT 0.000000 102.479000 0.062000 102.541000 ;
    END
    PORT
      LAYER M8 ;
        RECT 215.938000 102.479000 216.000000 102.541000 ;
    END
    PORT
      LAYER M8 ;
        RECT 0.000000 104.873000 0.062000 104.935000 ;
    END
    PORT
      LAYER M8 ;
        RECT 215.938000 104.873000 216.000000 104.935000 ;
    END
    PORT
      LAYER M8 ;
        RECT 0.000000 107.141000 0.062000 107.203000 ;
    END
    PORT
      LAYER M8 ;
        RECT 215.938000 107.141000 216.000000 107.203000 ;
    END
    PORT
      LAYER M8 ;
        RECT 0.000000 109.409000 0.062000 109.471000 ;
    END
    PORT
      LAYER M8 ;
        RECT 215.938000 109.409000 216.000000 109.471000 ;
    END
    PORT
      LAYER M8 ;
        RECT 0.000000 111.803000 0.062000 111.865000 ;
    END
    PORT
      LAYER M8 ;
        RECT 215.938000 111.803000 216.000000 111.865000 ;
    END
    PORT
      LAYER M8 ;
        RECT 0.000000 114.071000 0.062000 114.133000 ;
    END
    PORT
      LAYER M8 ;
        RECT 215.938000 114.071000 216.000000 114.133000 ;
    END
    PORT
      LAYER M8 ;
        RECT 0.000000 116.339000 0.062000 116.401000 ;
    END
    PORT
      LAYER M8 ;
        RECT 215.938000 116.339000 216.000000 116.401000 ;
    END
    PORT
      LAYER M8 ;
        RECT 0.000000 118.607000 0.062000 118.669000 ;
    END
    PORT
      LAYER M8 ;
        RECT 215.938000 118.607000 216.000000 118.669000 ;
    END
    PORT
      LAYER M8 ;
        RECT 0.000000 121.001000 0.062000 121.063000 ;
    END
    PORT
      LAYER M8 ;
        RECT 215.938000 121.001000 216.000000 121.063000 ;
    END
    PORT
      LAYER M8 ;
        RECT 0.000000 123.269000 0.062000 123.331000 ;
    END
    PORT
      LAYER M8 ;
        RECT 215.938000 123.269000 216.000000 123.331000 ;
    END
    PORT
      LAYER M8 ;
        RECT 0.000000 125.537000 0.062000 125.599000 ;
    END
    PORT
      LAYER M8 ;
        RECT 215.938000 125.537000 216.000000 125.599000 ;
    END
    PORT
      LAYER M8 ;
        RECT 0.000000 127.931000 0.062000 127.993000 ;
    END
    PORT
      LAYER M8 ;
        RECT 215.938000 127.931000 216.000000 127.993000 ;
    END
    PORT
      LAYER M8 ;
        RECT 0.000000 130.199000 0.062000 130.261000 ;
    END
    PORT
      LAYER M8 ;
        RECT 215.938000 130.199000 216.000000 130.261000 ;
    END
    PORT
      LAYER M8 ;
        RECT 0.000000 132.467000 0.062000 132.529000 ;
    END
    PORT
      LAYER M8 ;
        RECT 215.938000 132.467000 216.000000 132.529000 ;
    END
    PORT
      LAYER M8 ;
        RECT 0.000000 134.735000 0.062000 134.797000 ;
    END
    PORT
      LAYER M8 ;
        RECT 215.938000 134.735000 216.000000 134.797000 ;
    END
    PORT
      LAYER M8 ;
        RECT 0.000000 137.129000 0.062000 137.191000 ;
    END
    PORT
      LAYER M8 ;
        RECT 215.938000 137.129000 216.000000 137.191000 ;
    END
    PORT
      LAYER M8 ;
        RECT 0.000000 139.397000 0.062000 139.459000 ;
    END
    PORT
      LAYER M8 ;
        RECT 215.938000 139.397000 216.000000 139.459000 ;
    END
    PORT
      LAYER M8 ;
        RECT 0.000000 141.665000 0.062000 141.727000 ;
    END
    PORT
      LAYER M8 ;
        RECT 215.938000 141.665000 216.000000 141.727000 ;
    END
    PORT
      LAYER M8 ;
        RECT 0.000000 144.059000 0.062000 144.121000 ;
    END
    PORT
      LAYER M8 ;
        RECT 215.938000 144.059000 216.000000 144.121000 ;
    END
    PORT
      LAYER M8 ;
        RECT 0.000000 146.327000 0.062000 146.389000 ;
    END
    PORT
      LAYER M8 ;
        RECT 215.938000 146.327000 216.000000 146.389000 ;
    END
    PORT
      LAYER M8 ;
        RECT 0.000000 148.595000 0.062000 148.657000 ;
    END
    PORT
      LAYER M8 ;
        RECT 215.938000 148.595000 216.000000 148.657000 ;
    END
    PORT
      LAYER M8 ;
        RECT 0.000000 150.863000 0.062000 150.925000 ;
    END
    PORT
      LAYER M8 ;
        RECT 215.938000 150.863000 216.000000 150.925000 ;
    END
    PORT
      LAYER M8 ;
        RECT 0.000000 153.257000 0.062000 153.319000 ;
    END
    PORT
      LAYER M8 ;
        RECT 215.938000 153.257000 216.000000 153.319000 ;
    END
    PORT
      LAYER M8 ;
        RECT 0.000000 155.525000 0.062000 155.587000 ;
    END
    PORT
      LAYER M8 ;
        RECT 215.938000 155.525000 216.000000 155.587000 ;
    END
    PORT
      LAYER M8 ;
        RECT 0.000000 157.793000 0.062000 157.855000 ;
    END
    PORT
      LAYER M8 ;
        RECT 215.938000 157.793000 216.000000 157.855000 ;
    END
    PORT
      LAYER M8 ;
        RECT 0.000000 160.187000 0.062000 160.249000 ;
    END
    PORT
      LAYER M8 ;
        RECT 215.938000 160.187000 216.000000 160.249000 ;
    END
    PORT
      LAYER M8 ;
        RECT 0.000000 162.455000 0.062000 162.517000 ;
    END
    PORT
      LAYER M8 ;
        RECT 215.938000 162.455000 216.000000 162.517000 ;
    END
    PORT
      LAYER M8 ;
        RECT 0.000000 164.723000 0.062000 164.785000 ;
    END
    PORT
      LAYER M8 ;
        RECT 215.938000 164.723000 216.000000 164.785000 ;
    END
    PORT
      LAYER M8 ;
        RECT 0.000000 166.991000 0.062000 167.053000 ;
    END
    PORT
      LAYER M8 ;
        RECT 215.938000 166.991000 216.000000 167.053000 ;
    END
    PORT
      LAYER M8 ;
        RECT 0.000000 169.385000 0.062000 169.447000 ;
    END
    PORT
      LAYER M8 ;
        RECT 215.938000 169.385000 216.000000 169.447000 ;
    END
    PORT
      LAYER M8 ;
        RECT 0.000000 171.653000 0.062000 171.715000 ;
    END
    PORT
      LAYER M8 ;
        RECT 215.938000 171.653000 216.000000 171.715000 ;
    END
    PORT
      LAYER M8 ;
        RECT 0.000000 173.921000 0.062000 173.983000 ;
    END
    PORT
      LAYER M8 ;
        RECT 215.938000 173.921000 216.000000 173.983000 ;
    END
    PORT
      LAYER M8 ;
        RECT 0.000000 176.315000 0.062000 176.377000 ;
    END
    PORT
      LAYER M8 ;
        RECT 215.938000 176.315000 216.000000 176.377000 ;
    END
    PORT
      LAYER M8 ;
        RECT 0.000000 178.583000 0.062000 178.645000 ;
    END
    PORT
      LAYER M8 ;
        RECT 215.938000 178.583000 216.000000 178.645000 ;
    END
    PORT
      LAYER M8 ;
        RECT 0.000000 180.851000 0.062000 180.913000 ;
    END
    PORT
      LAYER M8 ;
        RECT 215.938000 180.851000 216.000000 180.913000 ;
    END
    PORT
      LAYER M9 ;
        RECT 1.377000 0.000000 1.827000 0.450000 ;
    END
    PORT
      LAYER M9 ;
        RECT 1.377000 181.566000 1.827000 182.016000 ;
    END
    PORT
      LAYER M9 ;
        RECT 3.771000 0.000000 4.221000 0.450000 ;
    END
    PORT
      LAYER M9 ;
        RECT 3.771000 181.566000 4.221000 182.016000 ;
    END
    PORT
      LAYER M9 ;
        RECT 6.291000 0.000000 6.741000 0.450000 ;
    END
    PORT
      LAYER M9 ;
        RECT 6.291000 181.566000 6.741000 182.016000 ;
    END
    PORT
      LAYER M9 ;
        RECT 8.811000 0.000000 9.261000 0.450000 ;
    END
    PORT
      LAYER M9 ;
        RECT 8.811000 181.566000 9.261000 182.016000 ;
    END
    PORT
      LAYER M9 ;
        RECT 11.331000 0.000000 11.781000 0.450000 ;
    END
    PORT
      LAYER M9 ;
        RECT 11.331000 181.566000 11.781000 182.016000 ;
    END
    PORT
      LAYER M9 ;
        RECT 13.851000 0.000000 14.301000 0.450000 ;
    END
    PORT
      LAYER M9 ;
        RECT 13.851000 181.566000 14.301000 182.016000 ;
    END
    PORT
      LAYER M9 ;
        RECT 16.371000 0.000000 16.821000 0.450000 ;
    END
    PORT
      LAYER M9 ;
        RECT 16.371000 181.566000 16.821000 182.016000 ;
    END
    PORT
      LAYER M9 ;
        RECT 18.891000 0.000000 19.341000 0.450000 ;
    END
    PORT
      LAYER M9 ;
        RECT 18.891000 181.566000 19.341000 182.016000 ;
    END
    PORT
      LAYER M9 ;
        RECT 21.411000 0.000000 21.861000 0.450000 ;
    END
    PORT
      LAYER M9 ;
        RECT 21.411000 181.566000 21.861000 182.016000 ;
    END
    PORT
      LAYER M9 ;
        RECT 23.931000 0.000000 24.381000 0.450000 ;
    END
    PORT
      LAYER M9 ;
        RECT 23.931000 181.566000 24.381000 182.016000 ;
    END
    PORT
      LAYER M9 ;
        RECT 26.451000 0.000000 26.901000 0.450000 ;
    END
    PORT
      LAYER M9 ;
        RECT 26.451000 181.566000 26.901000 182.016000 ;
    END
    PORT
      LAYER M9 ;
        RECT 28.971000 0.000000 29.421000 0.450000 ;
    END
    PORT
      LAYER M9 ;
        RECT 28.971000 181.566000 29.421000 182.016000 ;
    END
    PORT
      LAYER M9 ;
        RECT 31.491000 0.000000 31.941000 0.450000 ;
    END
    PORT
      LAYER M9 ;
        RECT 31.491000 181.566000 31.941000 182.016000 ;
    END
    PORT
      LAYER M9 ;
        RECT 34.011000 0.000000 34.461000 0.450000 ;
    END
    PORT
      LAYER M9 ;
        RECT 34.011000 181.566000 34.461000 182.016000 ;
    END
    PORT
      LAYER M9 ;
        RECT 36.531000 0.000000 36.981000 0.450000 ;
    END
    PORT
      LAYER M9 ;
        RECT 36.531000 181.566000 36.981000 182.016000 ;
    END
    PORT
      LAYER M9 ;
        RECT 39.051000 0.000000 39.501000 0.450000 ;
    END
    PORT
      LAYER M9 ;
        RECT 39.051000 181.566000 39.501000 182.016000 ;
    END
    PORT
      LAYER M9 ;
        RECT 41.571000 0.000000 42.021000 0.450000 ;
    END
    PORT
      LAYER M9 ;
        RECT 41.571000 181.566000 42.021000 182.016000 ;
    END
    PORT
      LAYER M9 ;
        RECT 44.091000 0.000000 44.541000 0.450000 ;
    END
    PORT
      LAYER M9 ;
        RECT 44.091000 181.566000 44.541000 182.016000 ;
    END
    PORT
      LAYER M9 ;
        RECT 46.611000 0.000000 47.061000 0.450000 ;
    END
    PORT
      LAYER M9 ;
        RECT 46.611000 181.566000 47.061000 182.016000 ;
    END
    PORT
      LAYER M9 ;
        RECT 49.131000 0.000000 49.581000 0.450000 ;
    END
    PORT
      LAYER M9 ;
        RECT 49.131000 181.566000 49.581000 182.016000 ;
    END
    PORT
      LAYER M9 ;
        RECT 51.651000 0.000000 52.101000 0.450000 ;
    END
    PORT
      LAYER M9 ;
        RECT 51.651000 181.566000 52.101000 182.016000 ;
    END
    PORT
      LAYER M9 ;
        RECT 54.171000 0.000000 54.621000 0.450000 ;
    END
    PORT
      LAYER M9 ;
        RECT 54.171000 181.566000 54.621000 182.016000 ;
    END
    PORT
      LAYER M9 ;
        RECT 56.691000 0.000000 57.141000 0.450000 ;
    END
    PORT
      LAYER M9 ;
        RECT 56.691000 181.566000 57.141000 182.016000 ;
    END
    PORT
      LAYER M9 ;
        RECT 59.211000 0.000000 59.661000 0.450000 ;
    END
    PORT
      LAYER M9 ;
        RECT 59.211000 181.566000 59.661000 182.016000 ;
    END
    PORT
      LAYER M9 ;
        RECT 61.731000 0.000000 62.181000 0.450000 ;
    END
    PORT
      LAYER M9 ;
        RECT 61.731000 181.566000 62.181000 182.016000 ;
    END
    PORT
      LAYER M9 ;
        RECT 64.251000 0.000000 64.701000 0.450000 ;
    END
    PORT
      LAYER M9 ;
        RECT 64.251000 181.566000 64.701000 182.016000 ;
    END
    PORT
      LAYER M9 ;
        RECT 66.771000 0.000000 67.221000 0.450000 ;
    END
    PORT
      LAYER M9 ;
        RECT 66.771000 181.566000 67.221000 182.016000 ;
    END
    PORT
      LAYER M9 ;
        RECT 69.291000 0.000000 69.741000 0.450000 ;
    END
    PORT
      LAYER M9 ;
        RECT 69.291000 181.566000 69.741000 182.016000 ;
    END
    PORT
      LAYER M9 ;
        RECT 71.811000 0.000000 72.261000 0.450000 ;
    END
    PORT
      LAYER M9 ;
        RECT 71.811000 181.566000 72.261000 182.016000 ;
    END
    PORT
      LAYER M9 ;
        RECT 74.331000 0.000000 74.781000 0.450000 ;
    END
    PORT
      LAYER M9 ;
        RECT 74.331000 181.566000 74.781000 182.016000 ;
    END
    PORT
      LAYER M9 ;
        RECT 76.851000 0.000000 77.301000 0.450000 ;
    END
    PORT
      LAYER M9 ;
        RECT 76.851000 181.566000 77.301000 182.016000 ;
    END
    PORT
      LAYER M9 ;
        RECT 79.371000 0.000000 79.821000 0.450000 ;
    END
    PORT
      LAYER M9 ;
        RECT 79.371000 181.566000 79.821000 182.016000 ;
    END
    PORT
      LAYER M9 ;
        RECT 81.891000 0.000000 82.341000 0.450000 ;
    END
    PORT
      LAYER M9 ;
        RECT 81.891000 181.566000 82.341000 182.016000 ;
    END
    PORT
      LAYER M9 ;
        RECT 84.411000 0.000000 84.861000 0.450000 ;
    END
    PORT
      LAYER M9 ;
        RECT 84.411000 181.566000 84.861000 182.016000 ;
    END
    PORT
      LAYER M9 ;
        RECT 86.931000 0.000000 87.381000 0.450000 ;
    END
    PORT
      LAYER M9 ;
        RECT 86.931000 181.566000 87.381000 182.016000 ;
    END
    PORT
      LAYER M9 ;
        RECT 89.451000 0.000000 89.901000 0.450000 ;
    END
    PORT
      LAYER M9 ;
        RECT 89.451000 181.566000 89.901000 182.016000 ;
    END
    PORT
      LAYER M9 ;
        RECT 91.971000 0.000000 92.421000 0.450000 ;
    END
    PORT
      LAYER M9 ;
        RECT 91.971000 181.566000 92.421000 182.016000 ;
    END
    PORT
      LAYER M9 ;
        RECT 94.491000 0.000000 94.941000 0.450000 ;
    END
    PORT
      LAYER M9 ;
        RECT 94.491000 181.566000 94.941000 182.016000 ;
    END
    PORT
      LAYER M9 ;
        RECT 97.011000 0.000000 97.461000 0.450000 ;
    END
    PORT
      LAYER M9 ;
        RECT 97.011000 181.566000 97.461000 182.016000 ;
    END
    PORT
      LAYER M9 ;
        RECT 99.531000 0.000000 99.981000 0.450000 ;
    END
    PORT
      LAYER M9 ;
        RECT 99.531000 181.566000 99.981000 182.016000 ;
    END
    PORT
      LAYER M9 ;
        RECT 102.051000 0.000000 102.501000 0.450000 ;
    END
    PORT
      LAYER M9 ;
        RECT 102.051000 181.566000 102.501000 182.016000 ;
    END
    PORT
      LAYER M9 ;
        RECT 104.571000 0.000000 105.021000 0.450000 ;
    END
    PORT
      LAYER M9 ;
        RECT 104.571000 181.566000 105.021000 182.016000 ;
    END
    PORT
      LAYER M9 ;
        RECT 107.091000 0.000000 107.541000 0.450000 ;
    END
    PORT
      LAYER M9 ;
        RECT 107.091000 181.566000 107.541000 182.016000 ;
    END
    PORT
      LAYER M9 ;
        RECT 109.611000 0.000000 110.061000 0.450000 ;
    END
    PORT
      LAYER M9 ;
        RECT 109.611000 181.566000 110.061000 182.016000 ;
    END
    PORT
      LAYER M9 ;
        RECT 112.131000 0.000000 112.581000 0.450000 ;
    END
    PORT
      LAYER M9 ;
        RECT 112.131000 181.566000 112.581000 182.016000 ;
    END
    PORT
      LAYER M9 ;
        RECT 114.651000 0.000000 115.101000 0.450000 ;
    END
    PORT
      LAYER M9 ;
        RECT 114.651000 181.566000 115.101000 182.016000 ;
    END
    PORT
      LAYER M9 ;
        RECT 117.171000 0.000000 117.621000 0.450000 ;
    END
    PORT
      LAYER M9 ;
        RECT 117.171000 181.566000 117.621000 182.016000 ;
    END
    PORT
      LAYER M9 ;
        RECT 119.691000 0.000000 120.141000 0.450000 ;
    END
    PORT
      LAYER M9 ;
        RECT 119.691000 181.566000 120.141000 182.016000 ;
    END
    PORT
      LAYER M9 ;
        RECT 122.211000 0.000000 122.661000 0.450000 ;
    END
    PORT
      LAYER M9 ;
        RECT 122.211000 181.566000 122.661000 182.016000 ;
    END
    PORT
      LAYER M9 ;
        RECT 124.731000 0.000000 125.181000 0.450000 ;
    END
    PORT
      LAYER M9 ;
        RECT 124.731000 181.566000 125.181000 182.016000 ;
    END
    PORT
      LAYER M9 ;
        RECT 127.251000 0.000000 127.701000 0.450000 ;
    END
    PORT
      LAYER M9 ;
        RECT 127.251000 181.566000 127.701000 182.016000 ;
    END
    PORT
      LAYER M9 ;
        RECT 129.771000 0.000000 130.221000 0.450000 ;
    END
    PORT
      LAYER M9 ;
        RECT 129.771000 181.566000 130.221000 182.016000 ;
    END
    PORT
      LAYER M9 ;
        RECT 132.291000 0.000000 132.741000 0.450000 ;
    END
    PORT
      LAYER M9 ;
        RECT 132.291000 181.566000 132.741000 182.016000 ;
    END
    PORT
      LAYER M9 ;
        RECT 134.811000 0.000000 135.261000 0.450000 ;
    END
    PORT
      LAYER M9 ;
        RECT 134.811000 181.566000 135.261000 182.016000 ;
    END
    PORT
      LAYER M9 ;
        RECT 137.331000 0.000000 137.781000 0.450000 ;
    END
    PORT
      LAYER M9 ;
        RECT 137.331000 181.566000 137.781000 182.016000 ;
    END
    PORT
      LAYER M9 ;
        RECT 139.851000 0.000000 140.301000 0.450000 ;
    END
    PORT
      LAYER M9 ;
        RECT 139.851000 181.566000 140.301000 182.016000 ;
    END
    PORT
      LAYER M9 ;
        RECT 142.371000 0.000000 142.821000 0.450000 ;
    END
    PORT
      LAYER M9 ;
        RECT 142.371000 181.566000 142.821000 182.016000 ;
    END
    PORT
      LAYER M9 ;
        RECT 144.891000 0.000000 145.341000 0.450000 ;
    END
    PORT
      LAYER M9 ;
        RECT 144.891000 181.566000 145.341000 182.016000 ;
    END
    PORT
      LAYER M9 ;
        RECT 147.411000 0.000000 147.861000 0.450000 ;
    END
    PORT
      LAYER M9 ;
        RECT 147.411000 181.566000 147.861000 182.016000 ;
    END
    PORT
      LAYER M9 ;
        RECT 149.931000 0.000000 150.381000 0.450000 ;
    END
    PORT
      LAYER M9 ;
        RECT 149.931000 181.566000 150.381000 182.016000 ;
    END
    PORT
      LAYER M9 ;
        RECT 152.451000 0.000000 152.901000 0.450000 ;
    END
    PORT
      LAYER M9 ;
        RECT 152.451000 181.566000 152.901000 182.016000 ;
    END
    PORT
      LAYER M9 ;
        RECT 154.971000 0.000000 155.421000 0.450000 ;
    END
    PORT
      LAYER M9 ;
        RECT 154.971000 181.566000 155.421000 182.016000 ;
    END
    PORT
      LAYER M9 ;
        RECT 157.491000 0.000000 157.941000 0.450000 ;
    END
    PORT
      LAYER M9 ;
        RECT 157.491000 181.566000 157.941000 182.016000 ;
    END
    PORT
      LAYER M9 ;
        RECT 160.011000 0.000000 160.461000 0.450000 ;
    END
    PORT
      LAYER M9 ;
        RECT 160.011000 181.566000 160.461000 182.016000 ;
    END
    PORT
      LAYER M9 ;
        RECT 162.531000 0.000000 162.981000 0.450000 ;
    END
    PORT
      LAYER M9 ;
        RECT 162.531000 181.566000 162.981000 182.016000 ;
    END
    PORT
      LAYER M9 ;
        RECT 165.051000 0.000000 165.501000 0.450000 ;
    END
    PORT
      LAYER M9 ;
        RECT 165.051000 181.566000 165.501000 182.016000 ;
    END
    PORT
      LAYER M9 ;
        RECT 167.571000 0.000000 168.021000 0.450000 ;
    END
    PORT
      LAYER M9 ;
        RECT 167.571000 181.566000 168.021000 182.016000 ;
    END
    PORT
      LAYER M9 ;
        RECT 170.091000 0.000000 170.541000 0.450000 ;
    END
    PORT
      LAYER M9 ;
        RECT 170.091000 181.566000 170.541000 182.016000 ;
    END
    PORT
      LAYER M9 ;
        RECT 172.611000 0.000000 173.061000 0.450000 ;
    END
    PORT
      LAYER M9 ;
        RECT 172.611000 181.566000 173.061000 182.016000 ;
    END
    PORT
      LAYER M9 ;
        RECT 175.131000 0.000000 175.581000 0.450000 ;
    END
    PORT
      LAYER M9 ;
        RECT 175.131000 181.566000 175.581000 182.016000 ;
    END
    PORT
      LAYER M9 ;
        RECT 177.651000 0.000000 178.101000 0.450000 ;
    END
    PORT
      LAYER M9 ;
        RECT 177.651000 181.566000 178.101000 182.016000 ;
    END
    PORT
      LAYER M9 ;
        RECT 180.171000 0.000000 180.621000 0.450000 ;
    END
    PORT
      LAYER M9 ;
        RECT 180.171000 181.566000 180.621000 182.016000 ;
    END
    PORT
      LAYER M9 ;
        RECT 182.691000 0.000000 183.141000 0.450000 ;
    END
    PORT
      LAYER M9 ;
        RECT 182.691000 181.566000 183.141000 182.016000 ;
    END
    PORT
      LAYER M9 ;
        RECT 185.211000 0.000000 185.661000 0.450000 ;
    END
    PORT
      LAYER M9 ;
        RECT 185.211000 181.566000 185.661000 182.016000 ;
    END
    PORT
      LAYER M9 ;
        RECT 187.731000 0.000000 188.181000 0.450000 ;
    END
    PORT
      LAYER M9 ;
        RECT 187.731000 181.566000 188.181000 182.016000 ;
    END
    PORT
      LAYER M9 ;
        RECT 190.251000 0.000000 190.701000 0.450000 ;
    END
    PORT
      LAYER M9 ;
        RECT 190.251000 181.566000 190.701000 182.016000 ;
    END
    PORT
      LAYER M9 ;
        RECT 192.771000 0.000000 193.221000 0.450000 ;
    END
    PORT
      LAYER M9 ;
        RECT 192.771000 181.566000 193.221000 182.016000 ;
    END
    PORT
      LAYER M9 ;
        RECT 195.291000 0.000000 195.741000 0.450000 ;
    END
    PORT
      LAYER M9 ;
        RECT 195.291000 181.566000 195.741000 182.016000 ;
    END
    PORT
      LAYER M9 ;
        RECT 197.811000 0.000000 198.261000 0.450000 ;
    END
    PORT
      LAYER M9 ;
        RECT 197.811000 181.566000 198.261000 182.016000 ;
    END
    PORT
      LAYER M9 ;
        RECT 200.331000 0.000000 200.781000 0.450000 ;
    END
    PORT
      LAYER M9 ;
        RECT 200.331000 181.566000 200.781000 182.016000 ;
    END
    PORT
      LAYER M9 ;
        RECT 202.851000 0.000000 203.301000 0.450000 ;
    END
    PORT
      LAYER M9 ;
        RECT 202.851000 181.566000 203.301000 182.016000 ;
    END
    PORT
      LAYER M9 ;
        RECT 205.371000 0.000000 205.821000 0.450000 ;
    END
    PORT
      LAYER M9 ;
        RECT 205.371000 181.566000 205.821000 182.016000 ;
    END
    PORT
      LAYER M9 ;
        RECT 207.891000 0.000000 208.341000 0.450000 ;
    END
    PORT
      LAYER M9 ;
        RECT 207.891000 181.566000 208.341000 182.016000 ;
    END
    PORT
      LAYER M9 ;
        RECT 210.411000 0.000000 210.861000 0.450000 ;
    END
    PORT
      LAYER M9 ;
        RECT 210.411000 181.566000 210.861000 182.016000 ;
    END
    PORT
      LAYER M9 ;
        RECT 212.931000 0.000000 213.381000 0.450000 ;
    END
    PORT
      LAYER M9 ;
        RECT 212.931000 181.566000 213.381000 182.016000 ;
    END
    PORT
      LAYER M9 ;
        RECT 215.451000 0.000000 215.901000 0.450000 ;
    END
    PORT
      LAYER M9 ;
        RECT 215.451000 181.566000 215.901000 182.016000 ;
    END
    PORT
      LAYER M10 ;
        RECT 0.000000 5.058000 2.700000 7.758000 ;
    END
    PORT
      LAYER M10 ;
        RECT 213.300000 5.058000 216.000000 7.758000 ;
    END
    PORT
      LAYER M10 ;
        RECT 0.000000 14.058000 2.700000 16.758000 ;
    END
    PORT
      LAYER M10 ;
        RECT 213.300000 14.058000 216.000000 16.758000 ;
    END
    PORT
      LAYER M10 ;
        RECT 0.000000 23.058000 2.700000 25.758000 ;
    END
    PORT
      LAYER M10 ;
        RECT 213.300000 23.058000 216.000000 25.758000 ;
    END
    PORT
      LAYER M10 ;
        RECT 0.000000 32.058000 2.700000 34.758000 ;
    END
    PORT
      LAYER M10 ;
        RECT 213.300000 32.058000 216.000000 34.758000 ;
    END
    PORT
      LAYER M10 ;
        RECT 0.000000 41.058000 2.700000 43.758000 ;
    END
    PORT
      LAYER M10 ;
        RECT 213.300000 41.058000 216.000000 43.758000 ;
    END
    PORT
      LAYER M10 ;
        RECT 0.000000 50.958000 2.700000 53.658000 ;
    END
    PORT
      LAYER M10 ;
        RECT 213.300000 50.958000 216.000000 53.658000 ;
    END
    PORT
      LAYER M10 ;
        RECT 0.000000 59.958000 2.700000 62.658000 ;
    END
    PORT
      LAYER M10 ;
        RECT 213.300000 59.958000 216.000000 62.658000 ;
    END
    PORT
      LAYER M10 ;
        RECT 0.000000 68.958000 2.700000 71.658000 ;
    END
    PORT
      LAYER M10 ;
        RECT 213.300000 68.958000 216.000000 71.658000 ;
    END
    PORT
      LAYER M10 ;
        RECT 0.000000 77.958000 2.700000 80.658000 ;
    END
    PORT
      LAYER M10 ;
        RECT 213.300000 77.958000 216.000000 80.658000 ;
    END
    PORT
      LAYER M10 ;
        RECT 0.000000 87.858000 2.700000 90.558000 ;
    END
    PORT
      LAYER M10 ;
        RECT 213.300000 87.858000 216.000000 90.558000 ;
    END
    PORT
      LAYER M10 ;
        RECT 0.000000 96.858000 2.700000 99.558000 ;
    END
    PORT
      LAYER M10 ;
        RECT 213.300000 96.858000 216.000000 99.558000 ;
    END
    PORT
      LAYER M10 ;
        RECT 0.000000 105.858000 2.700000 108.558000 ;
    END
    PORT
      LAYER M10 ;
        RECT 213.300000 105.858000 216.000000 108.558000 ;
    END
    PORT
      LAYER M10 ;
        RECT 0.000000 114.858000 2.700000 117.558000 ;
    END
    PORT
      LAYER M10 ;
        RECT 213.300000 114.858000 216.000000 117.558000 ;
    END
    PORT
      LAYER M10 ;
        RECT 0.000000 124.758000 2.700000 127.458000 ;
    END
    PORT
      LAYER M10 ;
        RECT 213.300000 124.758000 216.000000 127.458000 ;
    END
    PORT
      LAYER M10 ;
        RECT 0.000000 133.758000 2.700000 136.458000 ;
    END
    PORT
      LAYER M10 ;
        RECT 213.300000 133.758000 216.000000 136.458000 ;
    END
    PORT
      LAYER M10 ;
        RECT 0.000000 142.758000 2.700000 145.458000 ;
    END
    PORT
      LAYER M10 ;
        RECT 213.300000 142.758000 216.000000 145.458000 ;
    END
    PORT
      LAYER M10 ;
        RECT 0.000000 151.758000 2.700000 154.458000 ;
    END
    PORT
      LAYER M10 ;
        RECT 213.300000 151.758000 216.000000 154.458000 ;
    END
    PORT
      LAYER M10 ;
        RECT 0.000000 161.658000 2.700000 164.358000 ;
    END
    PORT
      LAYER M10 ;
        RECT 213.300000 161.658000 216.000000 164.358000 ;
    END
    PORT
      LAYER M10 ;
        RECT 0.000000 170.658000 2.700000 173.358000 ;
    END
    PORT
      LAYER M10 ;
        RECT 213.300000 170.658000 216.000000 173.358000 ;
    END

# P/G power stripe data as pin
    PORT
      LAYER M8 ;
        RECT 0.000000 1.175000 216.000000 1.237000 ;
        RECT 0.000000 5.711000 216.000000 5.773000 ;
        RECT 0.000000 3.443000 216.000000 3.505000 ;
        RECT 0.000000 8.105000 216.000000 8.167000 ;
        RECT 0.000000 15.035000 216.000000 15.097000 ;
        RECT 0.000000 12.641000 216.000000 12.703000 ;
        RECT 0.000000 10.373000 216.000000 10.435000 ;
        RECT 0.000000 21.839000 216.000000 21.901000 ;
        RECT 0.000000 19.571000 216.000000 19.633000 ;
        RECT 0.000000 17.303000 216.000000 17.365000 ;
        RECT 0.000000 28.769000 216.000000 28.831000 ;
        RECT 0.000000 26.501000 216.000000 26.563000 ;
        RECT 0.000000 24.233000 216.000000 24.295000 ;
        RECT 0.000000 35.699000 216.000000 35.761000 ;
        RECT 0.000000 33.431000 216.000000 33.493000 ;
        RECT 0.000000 31.163000 216.000000 31.225000 ;
        RECT 0.000000 42.629000 216.000000 42.691000 ;
        RECT 0.000000 40.361000 216.000000 40.423000 ;
        RECT 0.000000 37.967000 216.000000 38.029000 ;
        RECT 0.000000 44.897000 216.000000 44.959000 ;
        RECT 0.000000 49.559000 216.000000 49.621000 ;
        RECT 0.000000 47.291000 216.000000 47.353000 ;
        RECT 0.000000 56.489000 216.000000 56.551000 ;
        RECT 0.000000 54.095000 216.000000 54.157000 ;
        RECT 0.000000 51.827000 216.000000 51.889000 ;
        RECT 0.000000 61.025000 216.000000 61.087000 ;
        RECT 0.000000 58.757000 216.000000 58.819000 ;
        RECT 0.000000 63.419000 216.000000 63.481000 ;
        RECT 0.000000 70.223000 216.000000 70.285000 ;
        RECT 0.000000 67.955000 216.000000 68.017000 ;
        RECT 0.000000 65.687000 216.000000 65.749000 ;
        RECT 0.000000 77.153000 216.000000 77.215000 ;
        RECT 0.000000 74.885000 216.000000 74.947000 ;
        RECT 0.000000 72.617000 216.000000 72.679000 ;
        RECT 0.000000 84.083000 216.000000 84.145000 ;
        RECT 0.000000 81.815000 216.000000 81.877000 ;
        RECT 0.000000 79.547000 216.000000 79.609000 ;
        RECT 0.000000 86.351000 216.000000 86.413000 ;
        RECT 0.000000 88.745000 216.000000 88.807000 ;
        RECT 0.000000 95.675000 216.000000 95.737000 ;
        RECT 0.000000 93.281000 216.000000 93.343000 ;
        RECT 0.000000 91.013000 216.000000 91.075000 ;
        RECT 0.000000 102.479000 216.000000 102.541000 ;
        RECT 0.000000 100.211000 216.000000 100.273000 ;
        RECT 0.000000 97.943000 216.000000 98.005000 ;
        RECT 0.000000 109.409000 216.000000 109.471000 ;
        RECT 0.000000 107.141000 216.000000 107.203000 ;
        RECT 0.000000 104.873000 216.000000 104.935000 ;
        RECT 0.000000 116.339000 216.000000 116.401000 ;
        RECT 0.000000 114.071000 216.000000 114.133000 ;
        RECT 0.000000 111.803000 216.000000 111.865000 ;
        RECT 0.000000 123.269000 216.000000 123.331000 ;
        RECT 0.000000 121.001000 216.000000 121.063000 ;
        RECT 0.000000 118.607000 216.000000 118.669000 ;
        RECT 0.000000 125.537000 216.000000 125.599000 ;
        RECT 0.000000 130.199000 216.000000 130.261000 ;
        RECT 0.000000 127.931000 216.000000 127.993000 ;
        RECT 0.000000 137.129000 216.000000 137.191000 ;
        RECT 0.000000 134.735000 216.000000 134.797000 ;
        RECT 0.000000 132.467000 216.000000 132.529000 ;
        RECT 0.000000 141.665000 216.000000 141.727000 ;
        RECT 0.000000 139.397000 216.000000 139.459000 ;
        RECT 0.000000 144.059000 216.000000 144.121000 ;
        RECT 0.000000 150.863000 216.000000 150.925000 ;
        RECT 0.000000 148.595000 216.000000 148.657000 ;
        RECT 0.000000 146.327000 216.000000 146.389000 ;
        RECT 0.000000 157.793000 216.000000 157.855000 ;
        RECT 0.000000 155.525000 216.000000 155.587000 ;
        RECT 0.000000 153.257000 216.000000 153.319000 ;
        RECT 0.000000 164.723000 216.000000 164.785000 ;
        RECT 0.000000 162.455000 216.000000 162.517000 ;
        RECT 0.000000 160.187000 216.000000 160.249000 ;
        RECT 0.000000 166.991000 216.000000 167.053000 ;
        RECT 0.000000 171.653000 216.000000 171.715000 ;
        RECT 0.000000 169.385000 216.000000 169.447000 ;
        RECT 0.000000 180.851000 216.000000 180.913000 ;
        RECT 0.000000 178.583000 216.000000 178.645000 ;
        RECT 0.000000 176.315000 216.000000 176.377000 ;
        RECT 0.000000 173.921000 216.000000 173.983000 ;
    END
# end of P/G power stripe data as pin

  END VSS
  PIN VDD
    DIRECTION INOUT ;
    USE POWER ;
    PORT
      LAYER M3 ;
        RECT 0.065000 0.000000 0.103000 0.038000 ;
    END
    PORT
      LAYER M3 ;
        RECT 0.065000 181.978000 0.103000 182.016000 ;
    END
    PORT
      LAYER M3 ;
        RECT 2.497000 0.000000 2.535000 0.038000 ;
    END
    PORT
      LAYER M3 ;
        RECT 2.497000 181.978000 2.535000 182.016000 ;
    END
    PORT
      LAYER M3 ;
        RECT 5.057000 0.000000 5.095000 0.038000 ;
    END
    PORT
      LAYER M3 ;
        RECT 5.057000 181.978000 5.095000 182.016000 ;
    END
    PORT
      LAYER M3 ;
        RECT 7.553000 0.000000 7.591000 0.038000 ;
    END
    PORT
      LAYER M3 ;
        RECT 7.553000 181.978000 7.591000 182.016000 ;
    END
    PORT
      LAYER M3 ;
        RECT 10.049000 0.000000 10.087000 0.038000 ;
    END
    PORT
      LAYER M3 ;
        RECT 10.049000 181.978000 10.087000 182.016000 ;
    END
    PORT
      LAYER M3 ;
        RECT 12.609000 0.000000 12.647000 0.038000 ;
    END
    PORT
      LAYER M3 ;
        RECT 12.609000 181.978000 12.647000 182.016000 ;
    END
    PORT
      LAYER M3 ;
        RECT 15.105000 0.000000 15.143000 0.038000 ;
    END
    PORT
      LAYER M3 ;
        RECT 15.105000 181.978000 15.143000 182.016000 ;
    END
    PORT
      LAYER M3 ;
        RECT 17.665000 0.000000 17.703000 0.038000 ;
    END
    PORT
      LAYER M3 ;
        RECT 17.665000 181.978000 17.703000 182.016000 ;
    END
    PORT
      LAYER M3 ;
        RECT 20.161000 0.000000 20.199000 0.038000 ;
    END
    PORT
      LAYER M3 ;
        RECT 20.161000 181.978000 20.199000 182.016000 ;
    END
    PORT
      LAYER M3 ;
        RECT 22.657000 0.000000 22.695000 0.038000 ;
    END
    PORT
      LAYER M3 ;
        RECT 22.657000 181.978000 22.695000 182.016000 ;
    END
    PORT
      LAYER M3 ;
        RECT 25.217000 0.000000 25.255000 0.038000 ;
    END
    PORT
      LAYER M3 ;
        RECT 25.217000 181.978000 25.255000 182.016000 ;
    END
    PORT
      LAYER M3 ;
        RECT 27.713000 0.000000 27.751000 0.038000 ;
    END
    PORT
      LAYER M3 ;
        RECT 27.713000 181.978000 27.751000 182.016000 ;
    END
    PORT
      LAYER M3 ;
        RECT 30.209000 0.000000 30.247000 0.038000 ;
    END
    PORT
      LAYER M3 ;
        RECT 30.209000 181.978000 30.247000 182.016000 ;
    END
    PORT
      LAYER M3 ;
        RECT 32.769000 0.000000 32.807000 0.038000 ;
    END
    PORT
      LAYER M3 ;
        RECT 32.769000 181.978000 32.807000 182.016000 ;
    END
    PORT
      LAYER M3 ;
        RECT 35.265000 0.000000 35.303000 0.038000 ;
    END
    PORT
      LAYER M3 ;
        RECT 35.265000 181.978000 35.303000 182.016000 ;
    END
    PORT
      LAYER M3 ;
        RECT 37.825000 0.000000 37.863000 0.038000 ;
    END
    PORT
      LAYER M3 ;
        RECT 37.825000 181.978000 37.863000 182.016000 ;
    END
    PORT
      LAYER M3 ;
        RECT 40.321000 0.000000 40.359000 0.038000 ;
    END
    PORT
      LAYER M3 ;
        RECT 40.321000 181.978000 40.359000 182.016000 ;
    END
    PORT
      LAYER M3 ;
        RECT 42.817000 0.000000 42.855000 0.038000 ;
    END
    PORT
      LAYER M3 ;
        RECT 42.817000 181.978000 42.855000 182.016000 ;
    END
    PORT
      LAYER M3 ;
        RECT 45.377000 0.000000 45.415000 0.038000 ;
    END
    PORT
      LAYER M3 ;
        RECT 45.377000 181.978000 45.415000 182.016000 ;
    END
    PORT
      LAYER M3 ;
        RECT 47.873000 0.000000 47.911000 0.038000 ;
    END
    PORT
      LAYER M3 ;
        RECT 47.873000 181.978000 47.911000 182.016000 ;
    END
    PORT
      LAYER M3 ;
        RECT 50.369000 0.000000 50.407000 0.038000 ;
    END
    PORT
      LAYER M3 ;
        RECT 50.369000 181.978000 50.407000 182.016000 ;
    END
    PORT
      LAYER M3 ;
        RECT 52.929000 0.000000 52.967000 0.038000 ;
    END
    PORT
      LAYER M3 ;
        RECT 52.929000 181.978000 52.967000 182.016000 ;
    END
    PORT
      LAYER M3 ;
        RECT 55.425000 0.000000 55.463000 0.038000 ;
    END
    PORT
      LAYER M3 ;
        RECT 55.425000 181.978000 55.463000 182.016000 ;
    END
    PORT
      LAYER M3 ;
        RECT 57.985000 0.000000 58.023000 0.038000 ;
    END
    PORT
      LAYER M3 ;
        RECT 57.985000 181.978000 58.023000 182.016000 ;
    END
    PORT
      LAYER M3 ;
        RECT 60.481000 0.000000 60.519000 0.038000 ;
    END
    PORT
      LAYER M3 ;
        RECT 60.481000 181.978000 60.519000 182.016000 ;
    END
    PORT
      LAYER M3 ;
        RECT 62.977000 0.000000 63.015000 0.038000 ;
    END
    PORT
      LAYER M3 ;
        RECT 62.977000 181.978000 63.015000 182.016000 ;
    END
    PORT
      LAYER M3 ;
        RECT 65.537000 0.000000 65.575000 0.038000 ;
    END
    PORT
      LAYER M3 ;
        RECT 65.537000 181.978000 65.575000 182.016000 ;
    END
    PORT
      LAYER M3 ;
        RECT 68.033000 0.000000 68.071000 0.038000 ;
    END
    PORT
      LAYER M3 ;
        RECT 68.033000 181.978000 68.071000 182.016000 ;
    END
    PORT
      LAYER M3 ;
        RECT 70.529000 0.000000 70.567000 0.038000 ;
    END
    PORT
      LAYER M3 ;
        RECT 70.529000 181.978000 70.567000 182.016000 ;
    END
    PORT
      LAYER M3 ;
        RECT 73.089000 0.000000 73.127000 0.038000 ;
    END
    PORT
      LAYER M3 ;
        RECT 73.089000 181.978000 73.127000 182.016000 ;
    END
    PORT
      LAYER M3 ;
        RECT 75.585000 0.000000 75.623000 0.038000 ;
    END
    PORT
      LAYER M3 ;
        RECT 75.585000 181.978000 75.623000 182.016000 ;
    END
    PORT
      LAYER M3 ;
        RECT 78.145000 0.000000 78.183000 0.038000 ;
    END
    PORT
      LAYER M3 ;
        RECT 78.145000 181.978000 78.183000 182.016000 ;
    END
    PORT
      LAYER M3 ;
        RECT 80.641000 0.000000 80.679000 0.038000 ;
    END
    PORT
      LAYER M3 ;
        RECT 80.641000 181.978000 80.679000 182.016000 ;
    END
    PORT
      LAYER M3 ;
        RECT 83.137000 0.000000 83.175000 0.038000 ;
    END
    PORT
      LAYER M3 ;
        RECT 83.137000 181.978000 83.175000 182.016000 ;
    END
    PORT
      LAYER M3 ;
        RECT 85.697000 0.000000 85.735000 0.038000 ;
    END
    PORT
      LAYER M3 ;
        RECT 85.697000 181.978000 85.735000 182.016000 ;
    END
    PORT
      LAYER M3 ;
        RECT 88.193000 0.000000 88.231000 0.038000 ;
    END
    PORT
      LAYER M3 ;
        RECT 88.193000 181.978000 88.231000 182.016000 ;
    END
    PORT
      LAYER M3 ;
        RECT 90.689000 0.000000 90.727000 0.038000 ;
    END
    PORT
      LAYER M3 ;
        RECT 90.689000 181.978000 90.727000 182.016000 ;
    END
    PORT
      LAYER M3 ;
        RECT 93.249000 0.000000 93.287000 0.038000 ;
    END
    PORT
      LAYER M3 ;
        RECT 93.249000 181.978000 93.287000 182.016000 ;
    END
    PORT
      LAYER M3 ;
        RECT 95.745000 0.000000 95.783000 0.038000 ;
    END
    PORT
      LAYER M3 ;
        RECT 95.745000 181.978000 95.783000 182.016000 ;
    END
    PORT
      LAYER M3 ;
        RECT 98.305000 0.000000 98.343000 0.038000 ;
    END
    PORT
      LAYER M3 ;
        RECT 98.305000 181.978000 98.343000 182.016000 ;
    END
    PORT
      LAYER M3 ;
        RECT 100.801000 0.000000 100.839000 0.038000 ;
    END
    PORT
      LAYER M3 ;
        RECT 100.801000 181.978000 100.839000 182.016000 ;
    END
    PORT
      LAYER M3 ;
        RECT 103.297000 0.000000 103.335000 0.038000 ;
    END
    PORT
      LAYER M3 ;
        RECT 103.297000 181.978000 103.335000 182.016000 ;
    END
    PORT
      LAYER M3 ;
        RECT 105.857000 0.000000 105.895000 0.038000 ;
    END
    PORT
      LAYER M3 ;
        RECT 105.857000 181.978000 105.895000 182.016000 ;
    END
    PORT
      LAYER M3 ;
        RECT 108.353000 0.000000 108.391000 0.038000 ;
    END
    PORT
      LAYER M3 ;
        RECT 108.353000 181.978000 108.391000 182.016000 ;
    END
    PORT
      LAYER M3 ;
        RECT 110.849000 0.000000 110.887000 0.038000 ;
    END
    PORT
      LAYER M3 ;
        RECT 110.849000 181.978000 110.887000 182.016000 ;
    END
    PORT
      LAYER M3 ;
        RECT 113.409000 0.000000 113.447000 0.038000 ;
    END
    PORT
      LAYER M3 ;
        RECT 113.409000 181.978000 113.447000 182.016000 ;
    END
    PORT
      LAYER M3 ;
        RECT 115.905000 0.000000 115.943000 0.038000 ;
    END
    PORT
      LAYER M3 ;
        RECT 115.905000 181.978000 115.943000 182.016000 ;
    END
    PORT
      LAYER M3 ;
        RECT 118.465000 0.000000 118.503000 0.038000 ;
    END
    PORT
      LAYER M3 ;
        RECT 118.465000 181.978000 118.503000 182.016000 ;
    END
    PORT
      LAYER M3 ;
        RECT 120.961000 0.000000 120.999000 0.038000 ;
    END
    PORT
      LAYER M3 ;
        RECT 120.961000 181.978000 120.999000 182.016000 ;
    END
    PORT
      LAYER M3 ;
        RECT 123.457000 0.000000 123.495000 0.038000 ;
    END
    PORT
      LAYER M3 ;
        RECT 123.457000 181.978000 123.495000 182.016000 ;
    END
    PORT
      LAYER M3 ;
        RECT 126.017000 0.000000 126.055000 0.038000 ;
    END
    PORT
      LAYER M3 ;
        RECT 126.017000 181.978000 126.055000 182.016000 ;
    END
    PORT
      LAYER M3 ;
        RECT 128.513000 0.000000 128.551000 0.038000 ;
    END
    PORT
      LAYER M3 ;
        RECT 128.513000 181.978000 128.551000 182.016000 ;
    END
    PORT
      LAYER M3 ;
        RECT 131.009000 0.000000 131.047000 0.038000 ;
    END
    PORT
      LAYER M3 ;
        RECT 131.009000 181.978000 131.047000 182.016000 ;
    END
    PORT
      LAYER M3 ;
        RECT 133.569000 0.000000 133.607000 0.038000 ;
    END
    PORT
      LAYER M3 ;
        RECT 133.569000 181.978000 133.607000 182.016000 ;
    END
    PORT
      LAYER M3 ;
        RECT 136.065000 0.000000 136.103000 0.038000 ;
    END
    PORT
      LAYER M3 ;
        RECT 136.065000 181.978000 136.103000 182.016000 ;
    END
    PORT
      LAYER M3 ;
        RECT 138.625000 0.000000 138.663000 0.038000 ;
    END
    PORT
      LAYER M3 ;
        RECT 138.625000 181.978000 138.663000 182.016000 ;
    END
    PORT
      LAYER M3 ;
        RECT 141.121000 0.000000 141.159000 0.038000 ;
    END
    PORT
      LAYER M3 ;
        RECT 141.121000 181.978000 141.159000 182.016000 ;
    END
    PORT
      LAYER M3 ;
        RECT 143.617000 0.000000 143.655000 0.038000 ;
    END
    PORT
      LAYER M3 ;
        RECT 143.617000 181.978000 143.655000 182.016000 ;
    END
    PORT
      LAYER M3 ;
        RECT 146.177000 0.000000 146.215000 0.038000 ;
    END
    PORT
      LAYER M3 ;
        RECT 146.177000 181.978000 146.215000 182.016000 ;
    END
    PORT
      LAYER M3 ;
        RECT 148.673000 0.000000 148.711000 0.038000 ;
    END
    PORT
      LAYER M3 ;
        RECT 148.673000 181.978000 148.711000 182.016000 ;
    END
    PORT
      LAYER M3 ;
        RECT 151.169000 0.000000 151.207000 0.038000 ;
    END
    PORT
      LAYER M3 ;
        RECT 151.169000 181.978000 151.207000 182.016000 ;
    END
    PORT
      LAYER M3 ;
        RECT 153.729000 0.000000 153.767000 0.038000 ;
    END
    PORT
      LAYER M3 ;
        RECT 153.729000 181.978000 153.767000 182.016000 ;
    END
    PORT
      LAYER M3 ;
        RECT 156.225000 0.000000 156.263000 0.038000 ;
    END
    PORT
      LAYER M3 ;
        RECT 156.225000 181.978000 156.263000 182.016000 ;
    END
    PORT
      LAYER M3 ;
        RECT 158.785000 0.000000 158.823000 0.038000 ;
    END
    PORT
      LAYER M3 ;
        RECT 158.785000 181.978000 158.823000 182.016000 ;
    END
    PORT
      LAYER M3 ;
        RECT 161.281000 0.000000 161.319000 0.038000 ;
    END
    PORT
      LAYER M3 ;
        RECT 161.281000 181.978000 161.319000 182.016000 ;
    END
    PORT
      LAYER M3 ;
        RECT 163.777000 0.000000 163.815000 0.038000 ;
    END
    PORT
      LAYER M3 ;
        RECT 163.777000 181.978000 163.815000 182.016000 ;
    END
    PORT
      LAYER M3 ;
        RECT 166.337000 0.000000 166.375000 0.038000 ;
    END
    PORT
      LAYER M3 ;
        RECT 166.337000 181.978000 166.375000 182.016000 ;
    END
    PORT
      LAYER M3 ;
        RECT 168.833000 0.000000 168.871000 0.038000 ;
    END
    PORT
      LAYER M3 ;
        RECT 168.833000 181.978000 168.871000 182.016000 ;
    END
    PORT
      LAYER M3 ;
        RECT 171.329000 0.000000 171.367000 0.038000 ;
    END
    PORT
      LAYER M3 ;
        RECT 171.329000 181.978000 171.367000 182.016000 ;
    END
    PORT
      LAYER M3 ;
        RECT 173.889000 0.000000 173.927000 0.038000 ;
    END
    PORT
      LAYER M3 ;
        RECT 173.889000 181.978000 173.927000 182.016000 ;
    END
    PORT
      LAYER M3 ;
        RECT 176.385000 0.000000 176.423000 0.038000 ;
    END
    PORT
      LAYER M3 ;
        RECT 176.385000 181.978000 176.423000 182.016000 ;
    END
    PORT
      LAYER M3 ;
        RECT 178.945000 0.000000 178.983000 0.038000 ;
    END
    PORT
      LAYER M3 ;
        RECT 178.945000 181.978000 178.983000 182.016000 ;
    END
    PORT
      LAYER M3 ;
        RECT 181.441000 0.000000 181.479000 0.038000 ;
    END
    PORT
      LAYER M3 ;
        RECT 181.441000 181.978000 181.479000 182.016000 ;
    END
    PORT
      LAYER M3 ;
        RECT 183.937000 0.000000 183.975000 0.038000 ;
    END
    PORT
      LAYER M3 ;
        RECT 183.937000 181.978000 183.975000 182.016000 ;
    END
    PORT
      LAYER M3 ;
        RECT 186.497000 0.000000 186.535000 0.038000 ;
    END
    PORT
      LAYER M3 ;
        RECT 186.497000 181.978000 186.535000 182.016000 ;
    END
    PORT
      LAYER M3 ;
        RECT 188.993000 0.000000 189.031000 0.038000 ;
    END
    PORT
      LAYER M3 ;
        RECT 188.993000 181.978000 189.031000 182.016000 ;
    END
    PORT
      LAYER M3 ;
        RECT 191.489000 0.000000 191.527000 0.038000 ;
    END
    PORT
      LAYER M3 ;
        RECT 191.489000 181.978000 191.527000 182.016000 ;
    END
    PORT
      LAYER M3 ;
        RECT 194.049000 0.000000 194.087000 0.038000 ;
    END
    PORT
      LAYER M3 ;
        RECT 194.049000 181.978000 194.087000 182.016000 ;
    END
    PORT
      LAYER M3 ;
        RECT 196.545000 0.000000 196.583000 0.038000 ;
    END
    PORT
      LAYER M3 ;
        RECT 196.545000 181.978000 196.583000 182.016000 ;
    END
    PORT
      LAYER M3 ;
        RECT 199.105000 0.000000 199.143000 0.038000 ;
    END
    PORT
      LAYER M3 ;
        RECT 199.105000 181.978000 199.143000 182.016000 ;
    END
    PORT
      LAYER M3 ;
        RECT 201.601000 0.000000 201.639000 0.038000 ;
    END
    PORT
      LAYER M3 ;
        RECT 201.601000 181.978000 201.639000 182.016000 ;
    END
    PORT
      LAYER M3 ;
        RECT 204.097000 0.000000 204.135000 0.038000 ;
    END
    PORT
      LAYER M3 ;
        RECT 204.097000 181.978000 204.135000 182.016000 ;
    END
    PORT
      LAYER M3 ;
        RECT 206.657000 0.000000 206.695000 0.038000 ;
    END
    PORT
      LAYER M3 ;
        RECT 206.657000 181.978000 206.695000 182.016000 ;
    END
    PORT
      LAYER M3 ;
        RECT 209.153000 0.000000 209.191000 0.038000 ;
    END
    PORT
      LAYER M3 ;
        RECT 209.153000 181.978000 209.191000 182.016000 ;
    END
    PORT
      LAYER M3 ;
        RECT 211.649000 0.000000 211.687000 0.038000 ;
    END
    PORT
      LAYER M3 ;
        RECT 211.649000 181.978000 211.687000 182.016000 ;
    END
    PORT
      LAYER M3 ;
        RECT 214.209000 0.000000 214.247000 0.038000 ;
    END
    PORT
      LAYER M3 ;
        RECT 214.209000 181.978000 214.247000 182.016000 ;
    END
    PORT
      LAYER M4 ;
        RECT 0.000000 0.028000 0.040000 0.068000 ;
    END
    PORT
      LAYER M4 ;
        RECT 215.960000 0.028000 216.000000 0.068000 ;
    END
    PORT
      LAYER M4 ;
        RECT 0.000000 2.268000 0.040000 2.308000 ;
    END
    PORT
      LAYER M4 ;
        RECT 215.960000 2.268000 216.000000 2.308000 ;
    END
    PORT
      LAYER M4 ;
        RECT 0.000000 4.588000 0.040000 4.628000 ;
    END
    PORT
      LAYER M4 ;
        RECT 215.960000 4.588000 216.000000 4.628000 ;
    END
    PORT
      LAYER M4 ;
        RECT 0.000000 6.908000 0.040000 6.948000 ;
    END
    PORT
      LAYER M4 ;
        RECT 215.960000 6.908000 216.000000 6.948000 ;
    END
    PORT
      LAYER M4 ;
        RECT 0.000000 9.228000 0.040000 9.268000 ;
    END
    PORT
      LAYER M4 ;
        RECT 215.960000 9.228000 216.000000 9.268000 ;
    END
    PORT
      LAYER M4 ;
        RECT 0.000000 11.548000 0.040000 11.588000 ;
    END
    PORT
      LAYER M4 ;
        RECT 215.960000 11.548000 216.000000 11.588000 ;
    END
    PORT
      LAYER M4 ;
        RECT 0.000000 13.788000 0.040000 13.828000 ;
    END
    PORT
      LAYER M4 ;
        RECT 215.960000 13.788000 216.000000 13.828000 ;
    END
    PORT
      LAYER M4 ;
        RECT 0.000000 16.108000 0.040000 16.148000 ;
    END
    PORT
      LAYER M4 ;
        RECT 215.960000 16.108000 216.000000 16.148000 ;
    END
    PORT
      LAYER M4 ;
        RECT 0.000000 18.428000 0.040000 18.468000 ;
    END
    PORT
      LAYER M4 ;
        RECT 215.960000 18.428000 216.000000 18.468000 ;
    END
    PORT
      LAYER M4 ;
        RECT 0.000000 20.748000 0.040000 20.788000 ;
    END
    PORT
      LAYER M4 ;
        RECT 215.960000 20.748000 216.000000 20.788000 ;
    END
    PORT
      LAYER M4 ;
        RECT 0.000000 23.068000 0.040000 23.108000 ;
    END
    PORT
      LAYER M4 ;
        RECT 215.960000 23.068000 216.000000 23.108000 ;
    END
    PORT
      LAYER M4 ;
        RECT 0.000000 25.308000 0.040000 25.348000 ;
    END
    PORT
      LAYER M4 ;
        RECT 215.960000 25.308000 216.000000 25.348000 ;
    END
    PORT
      LAYER M4 ;
        RECT 0.000000 27.628000 0.040000 27.668000 ;
    END
    PORT
      LAYER M4 ;
        RECT 215.960000 27.628000 216.000000 27.668000 ;
    END
    PORT
      LAYER M4 ;
        RECT 0.000000 29.948000 0.040000 29.988000 ;
    END
    PORT
      LAYER M4 ;
        RECT 215.960000 29.948000 216.000000 29.988000 ;
    END
    PORT
      LAYER M4 ;
        RECT 0.000000 32.268000 0.040000 32.308000 ;
    END
    PORT
      LAYER M4 ;
        RECT 215.960000 32.268000 216.000000 32.308000 ;
    END
    PORT
      LAYER M4 ;
        RECT 0.000000 34.588000 0.040000 34.628000 ;
    END
    PORT
      LAYER M4 ;
        RECT 215.960000 34.588000 216.000000 34.628000 ;
    END
    PORT
      LAYER M4 ;
        RECT 0.000000 36.828000 0.040000 36.868000 ;
    END
    PORT
      LAYER M4 ;
        RECT 215.960000 36.828000 216.000000 36.868000 ;
    END
    PORT
      LAYER M4 ;
        RECT 0.000000 39.148000 0.040000 39.188000 ;
    END
    PORT
      LAYER M4 ;
        RECT 215.960000 39.148000 216.000000 39.188000 ;
    END
    PORT
      LAYER M4 ;
        RECT 0.000000 41.468000 0.040000 41.508000 ;
    END
    PORT
      LAYER M4 ;
        RECT 215.960000 41.468000 216.000000 41.508000 ;
    END
    PORT
      LAYER M4 ;
        RECT 0.000000 43.788000 0.040000 43.828000 ;
    END
    PORT
      LAYER M4 ;
        RECT 215.960000 43.788000 216.000000 43.828000 ;
    END
    PORT
      LAYER M4 ;
        RECT 0.000000 46.108000 0.040000 46.148000 ;
    END
    PORT
      LAYER M4 ;
        RECT 215.960000 46.108000 216.000000 46.148000 ;
    END
    PORT
      LAYER M4 ;
        RECT 0.000000 48.348000 0.040000 48.388000 ;
    END
    PORT
      LAYER M4 ;
        RECT 215.960000 48.348000 216.000000 48.388000 ;
    END
    PORT
      LAYER M4 ;
        RECT 0.000000 50.668000 0.040000 50.708000 ;
    END
    PORT
      LAYER M4 ;
        RECT 215.960000 50.668000 216.000000 50.708000 ;
    END
    PORT
      LAYER M4 ;
        RECT 0.000000 52.988000 0.040000 53.028000 ;
    END
    PORT
      LAYER M4 ;
        RECT 215.960000 52.988000 216.000000 53.028000 ;
    END
    PORT
      LAYER M4 ;
        RECT 0.000000 55.308000 0.040000 55.348000 ;
    END
    PORT
      LAYER M4 ;
        RECT 215.960000 55.308000 216.000000 55.348000 ;
    END
    PORT
      LAYER M4 ;
        RECT 0.000000 57.628000 0.040000 57.668000 ;
    END
    PORT
      LAYER M4 ;
        RECT 215.960000 57.628000 216.000000 57.668000 ;
    END
    PORT
      LAYER M4 ;
        RECT 0.000000 59.868000 0.040000 59.908000 ;
    END
    PORT
      LAYER M4 ;
        RECT 215.960000 59.868000 216.000000 59.908000 ;
    END
    PORT
      LAYER M4 ;
        RECT 0.000000 62.188000 0.040000 62.228000 ;
    END
    PORT
      LAYER M4 ;
        RECT 215.960000 62.188000 216.000000 62.228000 ;
    END
    PORT
      LAYER M4 ;
        RECT 0.000000 64.508000 0.040000 64.548000 ;
    END
    PORT
      LAYER M4 ;
        RECT 215.960000 64.508000 216.000000 64.548000 ;
    END
    PORT
      LAYER M4 ;
        RECT 0.000000 66.828000 0.040000 66.868000 ;
    END
    PORT
      LAYER M4 ;
        RECT 215.960000 66.828000 216.000000 66.868000 ;
    END
    PORT
      LAYER M4 ;
        RECT 0.000000 69.148000 0.040000 69.188000 ;
    END
    PORT
      LAYER M4 ;
        RECT 215.960000 69.148000 216.000000 69.188000 ;
    END
    PORT
      LAYER M4 ;
        RECT 0.000000 71.388000 0.040000 71.428000 ;
    END
    PORT
      LAYER M4 ;
        RECT 215.960000 71.388000 216.000000 71.428000 ;
    END
    PORT
      LAYER M4 ;
        RECT 0.000000 73.708000 0.040000 73.748000 ;
    END
    PORT
      LAYER M4 ;
        RECT 215.960000 73.708000 216.000000 73.748000 ;
    END
    PORT
      LAYER M4 ;
        RECT 0.000000 76.028000 0.040000 76.068000 ;
    END
    PORT
      LAYER M4 ;
        RECT 215.960000 76.028000 216.000000 76.068000 ;
    END
    PORT
      LAYER M4 ;
        RECT 0.000000 78.348000 0.040000 78.388000 ;
    END
    PORT
      LAYER M4 ;
        RECT 215.960000 78.348000 216.000000 78.388000 ;
    END
    PORT
      LAYER M4 ;
        RECT 0.000000 80.668000 0.040000 80.708000 ;
    END
    PORT
      LAYER M4 ;
        RECT 215.960000 80.668000 216.000000 80.708000 ;
    END
    PORT
      LAYER M4 ;
        RECT 0.000000 82.908000 0.040000 82.948000 ;
    END
    PORT
      LAYER M4 ;
        RECT 215.960000 82.908000 216.000000 82.948000 ;
    END
    PORT
      LAYER M4 ;
        RECT 0.000000 85.228000 0.040000 85.268000 ;
    END
    PORT
      LAYER M4 ;
        RECT 215.960000 85.228000 216.000000 85.268000 ;
    END
    PORT
      LAYER M4 ;
        RECT 0.000000 87.548000 0.040000 87.588000 ;
    END
    PORT
      LAYER M4 ;
        RECT 215.960000 87.548000 216.000000 87.588000 ;
    END
    PORT
      LAYER M4 ;
        RECT 0.000000 89.868000 0.040000 89.908000 ;
    END
    PORT
      LAYER M4 ;
        RECT 215.960000 89.868000 216.000000 89.908000 ;
    END
    PORT
      LAYER M4 ;
        RECT 0.000000 92.188000 0.040000 92.228000 ;
    END
    PORT
      LAYER M4 ;
        RECT 215.960000 92.188000 216.000000 92.228000 ;
    END
    PORT
      LAYER M4 ;
        RECT 0.000000 94.428000 0.040000 94.468000 ;
    END
    PORT
      LAYER M4 ;
        RECT 215.960000 94.428000 216.000000 94.468000 ;
    END
    PORT
      LAYER M4 ;
        RECT 0.000000 96.748000 0.040000 96.788000 ;
    END
    PORT
      LAYER M4 ;
        RECT 215.960000 96.748000 216.000000 96.788000 ;
    END
    PORT
      LAYER M4 ;
        RECT 0.000000 99.068000 0.040000 99.108000 ;
    END
    PORT
      LAYER M4 ;
        RECT 215.960000 99.068000 216.000000 99.108000 ;
    END
    PORT
      LAYER M4 ;
        RECT 0.000000 101.388000 0.040000 101.428000 ;
    END
    PORT
      LAYER M4 ;
        RECT 215.960000 101.388000 216.000000 101.428000 ;
    END
    PORT
      LAYER M4 ;
        RECT 0.000000 103.708000 0.040000 103.748000 ;
    END
    PORT
      LAYER M4 ;
        RECT 215.960000 103.708000 216.000000 103.748000 ;
    END
    PORT
      LAYER M4 ;
        RECT 0.000000 105.948000 0.040000 105.988000 ;
    END
    PORT
      LAYER M4 ;
        RECT 215.960000 105.948000 216.000000 105.988000 ;
    END
    PORT
      LAYER M4 ;
        RECT 0.000000 108.268000 0.040000 108.308000 ;
    END
    PORT
      LAYER M4 ;
        RECT 215.960000 108.268000 216.000000 108.308000 ;
    END
    PORT
      LAYER M4 ;
        RECT 0.000000 110.588000 0.040000 110.628000 ;
    END
    PORT
      LAYER M4 ;
        RECT 215.960000 110.588000 216.000000 110.628000 ;
    END
    PORT
      LAYER M4 ;
        RECT 0.000000 112.908000 0.040000 112.948000 ;
    END
    PORT
      LAYER M4 ;
        RECT 215.960000 112.908000 216.000000 112.948000 ;
    END
    PORT
      LAYER M4 ;
        RECT 0.000000 115.228000 0.040000 115.268000 ;
    END
    PORT
      LAYER M4 ;
        RECT 215.960000 115.228000 216.000000 115.268000 ;
    END
    PORT
      LAYER M4 ;
        RECT 0.000000 117.468000 0.040000 117.508000 ;
    END
    PORT
      LAYER M4 ;
        RECT 215.960000 117.468000 216.000000 117.508000 ;
    END
    PORT
      LAYER M4 ;
        RECT 0.000000 119.788000 0.040000 119.828000 ;
    END
    PORT
      LAYER M4 ;
        RECT 215.960000 119.788000 216.000000 119.828000 ;
    END
    PORT
      LAYER M4 ;
        RECT 0.000000 122.108000 0.040000 122.148000 ;
    END
    PORT
      LAYER M4 ;
        RECT 215.960000 122.108000 216.000000 122.148000 ;
    END
    PORT
      LAYER M4 ;
        RECT 0.000000 124.428000 0.040000 124.468000 ;
    END
    PORT
      LAYER M4 ;
        RECT 215.960000 124.428000 216.000000 124.468000 ;
    END
    PORT
      LAYER M4 ;
        RECT 0.000000 126.748000 0.040000 126.788000 ;
    END
    PORT
      LAYER M4 ;
        RECT 215.960000 126.748000 216.000000 126.788000 ;
    END
    PORT
      LAYER M4 ;
        RECT 0.000000 128.988000 0.040000 129.028000 ;
    END
    PORT
      LAYER M4 ;
        RECT 215.960000 128.988000 216.000000 129.028000 ;
    END
    PORT
      LAYER M4 ;
        RECT 0.000000 131.308000 0.040000 131.348000 ;
    END
    PORT
      LAYER M4 ;
        RECT 215.960000 131.308000 216.000000 131.348000 ;
    END
    PORT
      LAYER M4 ;
        RECT 0.000000 133.628000 0.040000 133.668000 ;
    END
    PORT
      LAYER M4 ;
        RECT 215.960000 133.628000 216.000000 133.668000 ;
    END
    PORT
      LAYER M4 ;
        RECT 0.000000 135.948000 0.040000 135.988000 ;
    END
    PORT
      LAYER M4 ;
        RECT 215.960000 135.948000 216.000000 135.988000 ;
    END
    PORT
      LAYER M4 ;
        RECT 0.000000 138.268000 0.040000 138.308000 ;
    END
    PORT
      LAYER M4 ;
        RECT 215.960000 138.268000 216.000000 138.308000 ;
    END
    PORT
      LAYER M4 ;
        RECT 0.000000 140.508000 0.040000 140.548000 ;
    END
    PORT
      LAYER M4 ;
        RECT 215.960000 140.508000 216.000000 140.548000 ;
    END
    PORT
      LAYER M4 ;
        RECT 0.000000 142.828000 0.040000 142.868000 ;
    END
    PORT
      LAYER M4 ;
        RECT 215.960000 142.828000 216.000000 142.868000 ;
    END
    PORT
      LAYER M4 ;
        RECT 0.000000 145.148000 0.040000 145.188000 ;
    END
    PORT
      LAYER M4 ;
        RECT 215.960000 145.148000 216.000000 145.188000 ;
    END
    PORT
      LAYER M4 ;
        RECT 0.000000 147.468000 0.040000 147.508000 ;
    END
    PORT
      LAYER M4 ;
        RECT 215.960000 147.468000 216.000000 147.508000 ;
    END
    PORT
      LAYER M4 ;
        RECT 0.000000 149.788000 0.040000 149.828000 ;
    END
    PORT
      LAYER M4 ;
        RECT 215.960000 149.788000 216.000000 149.828000 ;
    END
    PORT
      LAYER M4 ;
        RECT 0.000000 152.028000 0.040000 152.068000 ;
    END
    PORT
      LAYER M4 ;
        RECT 215.960000 152.028000 216.000000 152.068000 ;
    END
    PORT
      LAYER M4 ;
        RECT 0.000000 154.348000 0.040000 154.388000 ;
    END
    PORT
      LAYER M4 ;
        RECT 215.960000 154.348000 216.000000 154.388000 ;
    END
    PORT
      LAYER M4 ;
        RECT 0.000000 156.668000 0.040000 156.708000 ;
    END
    PORT
      LAYER M4 ;
        RECT 215.960000 156.668000 216.000000 156.708000 ;
    END
    PORT
      LAYER M4 ;
        RECT 0.000000 158.988000 0.040000 159.028000 ;
    END
    PORT
      LAYER M4 ;
        RECT 215.960000 158.988000 216.000000 159.028000 ;
    END
    PORT
      LAYER M4 ;
        RECT 0.000000 161.308000 0.040000 161.348000 ;
    END
    PORT
      LAYER M4 ;
        RECT 215.960000 161.308000 216.000000 161.348000 ;
    END
    PORT
      LAYER M4 ;
        RECT 0.000000 163.548000 0.040000 163.588000 ;
    END
    PORT
      LAYER M4 ;
        RECT 215.960000 163.548000 216.000000 163.588000 ;
    END
    PORT
      LAYER M4 ;
        RECT 0.000000 165.868000 0.040000 165.908000 ;
    END
    PORT
      LAYER M4 ;
        RECT 215.960000 165.868000 216.000000 165.908000 ;
    END
    PORT
      LAYER M4 ;
        RECT 0.000000 168.188000 0.040000 168.228000 ;
    END
    PORT
      LAYER M4 ;
        RECT 215.960000 168.188000 216.000000 168.228000 ;
    END
    PORT
      LAYER M4 ;
        RECT 0.000000 170.508000 0.040000 170.548000 ;
    END
    PORT
      LAYER M4 ;
        RECT 215.960000 170.508000 216.000000 170.548000 ;
    END
    PORT
      LAYER M4 ;
        RECT 0.000000 172.828000 0.040000 172.868000 ;
    END
    PORT
      LAYER M4 ;
        RECT 215.960000 172.828000 216.000000 172.868000 ;
    END
    PORT
      LAYER M4 ;
        RECT 0.000000 175.068000 0.040000 175.108000 ;
    END
    PORT
      LAYER M4 ;
        RECT 215.960000 175.068000 216.000000 175.108000 ;
    END
    PORT
      LAYER M4 ;
        RECT 0.000000 177.388000 0.040000 177.428000 ;
    END
    PORT
      LAYER M4 ;
        RECT 215.960000 177.388000 216.000000 177.428000 ;
    END
    PORT
      LAYER M4 ;
        RECT 0.000000 179.708000 0.040000 179.748000 ;
    END
    PORT
      LAYER M4 ;
        RECT 215.960000 179.708000 216.000000 179.748000 ;
    END
    PORT
      LAYER M5 ;
        RECT 0.080000 0.000000 0.120000 0.040000 ;
    END
    PORT
      LAYER M5 ;
        RECT 0.080000 181.976000 0.120000 182.016000 ;
    END
    PORT
      LAYER M5 ;
        RECT 2.480000 0.000000 2.520000 0.040000 ;
    END
    PORT
      LAYER M5 ;
        RECT 2.480000 181.976000 2.520000 182.016000 ;
    END
    PORT
      LAYER M5 ;
        RECT 5.040000 0.000000 5.080000 0.040000 ;
    END
    PORT
      LAYER M5 ;
        RECT 5.040000 181.976000 5.080000 182.016000 ;
    END
    PORT
      LAYER M5 ;
        RECT 7.520000 0.000000 7.560000 0.040000 ;
    END
    PORT
      LAYER M5 ;
        RECT 7.520000 181.976000 7.560000 182.016000 ;
    END
    PORT
      LAYER M5 ;
        RECT 10.080000 0.000000 10.120000 0.040000 ;
    END
    PORT
      LAYER M5 ;
        RECT 10.080000 181.976000 10.120000 182.016000 ;
    END
    PORT
      LAYER M5 ;
        RECT 12.560000 0.000000 12.600000 0.040000 ;
    END
    PORT
      LAYER M5 ;
        RECT 12.560000 181.976000 12.600000 182.016000 ;
    END
    PORT
      LAYER M5 ;
        RECT 15.120000 0.000000 15.160000 0.040000 ;
    END
    PORT
      LAYER M5 ;
        RECT 15.120000 181.976000 15.160000 182.016000 ;
    END
    PORT
      LAYER M5 ;
        RECT 17.600000 0.000000 17.640000 0.040000 ;
    END
    PORT
      LAYER M5 ;
        RECT 17.600000 181.976000 17.640000 182.016000 ;
    END
    PORT
      LAYER M5 ;
        RECT 20.160000 0.000000 20.200000 0.040000 ;
    END
    PORT
      LAYER M5 ;
        RECT 20.160000 181.976000 20.200000 182.016000 ;
    END
    PORT
      LAYER M5 ;
        RECT 22.640000 0.000000 22.680000 0.040000 ;
    END
    PORT
      LAYER M5 ;
        RECT 22.640000 181.976000 22.680000 182.016000 ;
    END
    PORT
      LAYER M5 ;
        RECT 25.200000 0.000000 25.240000 0.040000 ;
    END
    PORT
      LAYER M5 ;
        RECT 25.200000 181.976000 25.240000 182.016000 ;
    END
    PORT
      LAYER M5 ;
        RECT 27.680000 0.000000 27.720000 0.040000 ;
    END
    PORT
      LAYER M5 ;
        RECT 27.680000 181.976000 27.720000 182.016000 ;
    END
    PORT
      LAYER M5 ;
        RECT 30.240000 0.000000 30.280000 0.040000 ;
    END
    PORT
      LAYER M5 ;
        RECT 30.240000 181.976000 30.280000 182.016000 ;
    END
    PORT
      LAYER M5 ;
        RECT 32.720000 0.000000 32.760000 0.040000 ;
    END
    PORT
      LAYER M5 ;
        RECT 32.720000 181.976000 32.760000 182.016000 ;
    END
    PORT
      LAYER M5 ;
        RECT 35.280000 0.000000 35.320000 0.040000 ;
    END
    PORT
      LAYER M5 ;
        RECT 35.280000 181.976000 35.320000 182.016000 ;
    END
    PORT
      LAYER M5 ;
        RECT 37.760000 0.000000 37.800000 0.040000 ;
    END
    PORT
      LAYER M5 ;
        RECT 37.760000 181.976000 37.800000 182.016000 ;
    END
    PORT
      LAYER M5 ;
        RECT 40.320000 0.000000 40.360000 0.040000 ;
    END
    PORT
      LAYER M5 ;
        RECT 40.320000 181.976000 40.360000 182.016000 ;
    END
    PORT
      LAYER M5 ;
        RECT 42.800000 0.000000 42.840000 0.040000 ;
    END
    PORT
      LAYER M5 ;
        RECT 42.800000 181.976000 42.840000 182.016000 ;
    END
    PORT
      LAYER M5 ;
        RECT 45.360000 0.000000 45.400000 0.040000 ;
    END
    PORT
      LAYER M5 ;
        RECT 45.360000 181.976000 45.400000 182.016000 ;
    END
    PORT
      LAYER M5 ;
        RECT 47.840000 0.000000 47.880000 0.040000 ;
    END
    PORT
      LAYER M5 ;
        RECT 47.840000 181.976000 47.880000 182.016000 ;
    END
    PORT
      LAYER M5 ;
        RECT 50.400000 0.000000 50.440000 0.040000 ;
    END
    PORT
      LAYER M5 ;
        RECT 50.400000 181.976000 50.440000 182.016000 ;
    END
    PORT
      LAYER M5 ;
        RECT 52.880000 0.000000 52.920000 0.040000 ;
    END
    PORT
      LAYER M5 ;
        RECT 52.880000 181.976000 52.920000 182.016000 ;
    END
    PORT
      LAYER M5 ;
        RECT 55.440000 0.000000 55.480000 0.040000 ;
    END
    PORT
      LAYER M5 ;
        RECT 55.440000 181.976000 55.480000 182.016000 ;
    END
    PORT
      LAYER M5 ;
        RECT 57.920000 0.000000 57.960000 0.040000 ;
    END
    PORT
      LAYER M5 ;
        RECT 57.920000 181.976000 57.960000 182.016000 ;
    END
    PORT
      LAYER M5 ;
        RECT 60.480000 0.000000 60.520000 0.040000 ;
    END
    PORT
      LAYER M5 ;
        RECT 60.480000 181.976000 60.520000 182.016000 ;
    END
    PORT
      LAYER M5 ;
        RECT 62.960000 0.000000 63.000000 0.040000 ;
    END
    PORT
      LAYER M5 ;
        RECT 62.960000 181.976000 63.000000 182.016000 ;
    END
    PORT
      LAYER M5 ;
        RECT 65.520000 0.000000 65.560000 0.040000 ;
    END
    PORT
      LAYER M5 ;
        RECT 65.520000 181.976000 65.560000 182.016000 ;
    END
    PORT
      LAYER M5 ;
        RECT 68.000000 0.000000 68.040000 0.040000 ;
    END
    PORT
      LAYER M5 ;
        RECT 68.000000 181.976000 68.040000 182.016000 ;
    END
    PORT
      LAYER M5 ;
        RECT 70.560000 0.000000 70.600000 0.040000 ;
    END
    PORT
      LAYER M5 ;
        RECT 70.560000 181.976000 70.600000 182.016000 ;
    END
    PORT
      LAYER M5 ;
        RECT 73.040000 0.000000 73.080000 0.040000 ;
    END
    PORT
      LAYER M5 ;
        RECT 73.040000 181.976000 73.080000 182.016000 ;
    END
    PORT
      LAYER M5 ;
        RECT 75.600000 0.000000 75.640000 0.040000 ;
    END
    PORT
      LAYER M5 ;
        RECT 75.600000 181.976000 75.640000 182.016000 ;
    END
    PORT
      LAYER M5 ;
        RECT 78.080000 0.000000 78.120000 0.040000 ;
    END
    PORT
      LAYER M5 ;
        RECT 78.080000 181.976000 78.120000 182.016000 ;
    END
    PORT
      LAYER M5 ;
        RECT 80.640000 0.000000 80.680000 0.040000 ;
    END
    PORT
      LAYER M5 ;
        RECT 80.640000 181.976000 80.680000 182.016000 ;
    END
    PORT
      LAYER M5 ;
        RECT 83.120000 0.000000 83.160000 0.040000 ;
    END
    PORT
      LAYER M5 ;
        RECT 83.120000 181.976000 83.160000 182.016000 ;
    END
    PORT
      LAYER M5 ;
        RECT 85.680000 0.000000 85.720000 0.040000 ;
    END
    PORT
      LAYER M5 ;
        RECT 85.680000 181.976000 85.720000 182.016000 ;
    END
    PORT
      LAYER M5 ;
        RECT 88.160000 0.000000 88.200000 0.040000 ;
    END
    PORT
      LAYER M5 ;
        RECT 88.160000 181.976000 88.200000 182.016000 ;
    END
    PORT
      LAYER M5 ;
        RECT 90.720000 0.000000 90.760000 0.040000 ;
    END
    PORT
      LAYER M5 ;
        RECT 90.720000 181.976000 90.760000 182.016000 ;
    END
    PORT
      LAYER M5 ;
        RECT 93.200000 0.000000 93.240000 0.040000 ;
    END
    PORT
      LAYER M5 ;
        RECT 93.200000 181.976000 93.240000 182.016000 ;
    END
    PORT
      LAYER M5 ;
        RECT 95.760000 0.000000 95.800000 0.040000 ;
    END
    PORT
      LAYER M5 ;
        RECT 95.760000 181.976000 95.800000 182.016000 ;
    END
    PORT
      LAYER M5 ;
        RECT 98.240000 0.000000 98.280000 0.040000 ;
    END
    PORT
      LAYER M5 ;
        RECT 98.240000 181.976000 98.280000 182.016000 ;
    END
    PORT
      LAYER M5 ;
        RECT 100.800000 0.000000 100.840000 0.040000 ;
    END
    PORT
      LAYER M5 ;
        RECT 100.800000 181.976000 100.840000 182.016000 ;
    END
    PORT
      LAYER M5 ;
        RECT 103.280000 0.000000 103.320000 0.040000 ;
    END
    PORT
      LAYER M5 ;
        RECT 103.280000 181.976000 103.320000 182.016000 ;
    END
    PORT
      LAYER M5 ;
        RECT 105.840000 0.000000 105.880000 0.040000 ;
    END
    PORT
      LAYER M5 ;
        RECT 105.840000 181.976000 105.880000 182.016000 ;
    END
    PORT
      LAYER M5 ;
        RECT 108.320000 0.000000 108.360000 0.040000 ;
    END
    PORT
      LAYER M5 ;
        RECT 108.320000 181.976000 108.360000 182.016000 ;
    END
    PORT
      LAYER M5 ;
        RECT 110.880000 0.000000 110.920000 0.040000 ;
    END
    PORT
      LAYER M5 ;
        RECT 110.880000 181.976000 110.920000 182.016000 ;
    END
    PORT
      LAYER M5 ;
        RECT 113.360000 0.000000 113.400000 0.040000 ;
    END
    PORT
      LAYER M5 ;
        RECT 113.360000 181.976000 113.400000 182.016000 ;
    END
    PORT
      LAYER M5 ;
        RECT 115.920000 0.000000 115.960000 0.040000 ;
    END
    PORT
      LAYER M5 ;
        RECT 115.920000 181.976000 115.960000 182.016000 ;
    END
    PORT
      LAYER M5 ;
        RECT 118.400000 0.000000 118.440000 0.040000 ;
    END
    PORT
      LAYER M5 ;
        RECT 118.400000 181.976000 118.440000 182.016000 ;
    END
    PORT
      LAYER M5 ;
        RECT 120.960000 0.000000 121.000000 0.040000 ;
    END
    PORT
      LAYER M5 ;
        RECT 120.960000 181.976000 121.000000 182.016000 ;
    END
    PORT
      LAYER M5 ;
        RECT 123.440000 0.000000 123.480000 0.040000 ;
    END
    PORT
      LAYER M5 ;
        RECT 123.440000 181.976000 123.480000 182.016000 ;
    END
    PORT
      LAYER M5 ;
        RECT 126.000000 0.000000 126.040000 0.040000 ;
    END
    PORT
      LAYER M5 ;
        RECT 126.000000 181.976000 126.040000 182.016000 ;
    END
    PORT
      LAYER M5 ;
        RECT 128.480000 0.000000 128.520000 0.040000 ;
    END
    PORT
      LAYER M5 ;
        RECT 128.480000 181.976000 128.520000 182.016000 ;
    END
    PORT
      LAYER M5 ;
        RECT 131.040000 0.000000 131.080000 0.040000 ;
    END
    PORT
      LAYER M5 ;
        RECT 131.040000 181.976000 131.080000 182.016000 ;
    END
    PORT
      LAYER M5 ;
        RECT 133.520000 0.000000 133.560000 0.040000 ;
    END
    PORT
      LAYER M5 ;
        RECT 133.520000 181.976000 133.560000 182.016000 ;
    END
    PORT
      LAYER M5 ;
        RECT 136.080000 0.000000 136.120000 0.040000 ;
    END
    PORT
      LAYER M5 ;
        RECT 136.080000 181.976000 136.120000 182.016000 ;
    END
    PORT
      LAYER M5 ;
        RECT 138.560000 0.000000 138.600000 0.040000 ;
    END
    PORT
      LAYER M5 ;
        RECT 138.560000 181.976000 138.600000 182.016000 ;
    END
    PORT
      LAYER M5 ;
        RECT 141.120000 0.000000 141.160000 0.040000 ;
    END
    PORT
      LAYER M5 ;
        RECT 141.120000 181.976000 141.160000 182.016000 ;
    END
    PORT
      LAYER M5 ;
        RECT 143.600000 0.000000 143.640000 0.040000 ;
    END
    PORT
      LAYER M5 ;
        RECT 143.600000 181.976000 143.640000 182.016000 ;
    END
    PORT
      LAYER M5 ;
        RECT 146.160000 0.000000 146.200000 0.040000 ;
    END
    PORT
      LAYER M5 ;
        RECT 146.160000 181.976000 146.200000 182.016000 ;
    END
    PORT
      LAYER M5 ;
        RECT 148.640000 0.000000 148.680000 0.040000 ;
    END
    PORT
      LAYER M5 ;
        RECT 148.640000 181.976000 148.680000 182.016000 ;
    END
    PORT
      LAYER M5 ;
        RECT 151.200000 0.000000 151.240000 0.040000 ;
    END
    PORT
      LAYER M5 ;
        RECT 151.200000 181.976000 151.240000 182.016000 ;
    END
    PORT
      LAYER M5 ;
        RECT 153.680000 0.000000 153.720000 0.040000 ;
    END
    PORT
      LAYER M5 ;
        RECT 153.680000 181.976000 153.720000 182.016000 ;
    END
    PORT
      LAYER M5 ;
        RECT 156.240000 0.000000 156.280000 0.040000 ;
    END
    PORT
      LAYER M5 ;
        RECT 156.240000 181.976000 156.280000 182.016000 ;
    END
    PORT
      LAYER M5 ;
        RECT 158.720000 0.000000 158.760000 0.040000 ;
    END
    PORT
      LAYER M5 ;
        RECT 158.720000 181.976000 158.760000 182.016000 ;
    END
    PORT
      LAYER M5 ;
        RECT 161.280000 0.000000 161.320000 0.040000 ;
    END
    PORT
      LAYER M5 ;
        RECT 161.280000 181.976000 161.320000 182.016000 ;
    END
    PORT
      LAYER M5 ;
        RECT 163.760000 0.000000 163.800000 0.040000 ;
    END
    PORT
      LAYER M5 ;
        RECT 163.760000 181.976000 163.800000 182.016000 ;
    END
    PORT
      LAYER M5 ;
        RECT 166.320000 0.000000 166.360000 0.040000 ;
    END
    PORT
      LAYER M5 ;
        RECT 166.320000 181.976000 166.360000 182.016000 ;
    END
    PORT
      LAYER M5 ;
        RECT 168.800000 0.000000 168.840000 0.040000 ;
    END
    PORT
      LAYER M5 ;
        RECT 168.800000 181.976000 168.840000 182.016000 ;
    END
    PORT
      LAYER M5 ;
        RECT 171.360000 0.000000 171.400000 0.040000 ;
    END
    PORT
      LAYER M5 ;
        RECT 171.360000 181.976000 171.400000 182.016000 ;
    END
    PORT
      LAYER M5 ;
        RECT 173.840000 0.000000 173.880000 0.040000 ;
    END
    PORT
      LAYER M5 ;
        RECT 173.840000 181.976000 173.880000 182.016000 ;
    END
    PORT
      LAYER M5 ;
        RECT 176.400000 0.000000 176.440000 0.040000 ;
    END
    PORT
      LAYER M5 ;
        RECT 176.400000 181.976000 176.440000 182.016000 ;
    END
    PORT
      LAYER M5 ;
        RECT 178.880000 0.000000 178.920000 0.040000 ;
    END
    PORT
      LAYER M5 ;
        RECT 178.880000 181.976000 178.920000 182.016000 ;
    END
    PORT
      LAYER M5 ;
        RECT 181.440000 0.000000 181.480000 0.040000 ;
    END
    PORT
      LAYER M5 ;
        RECT 181.440000 181.976000 181.480000 182.016000 ;
    END
    PORT
      LAYER M5 ;
        RECT 183.920000 0.000000 183.960000 0.040000 ;
    END
    PORT
      LAYER M5 ;
        RECT 183.920000 181.976000 183.960000 182.016000 ;
    END
    PORT
      LAYER M5 ;
        RECT 186.480000 0.000000 186.520000 0.040000 ;
    END
    PORT
      LAYER M5 ;
        RECT 186.480000 181.976000 186.520000 182.016000 ;
    END
    PORT
      LAYER M5 ;
        RECT 188.960000 0.000000 189.000000 0.040000 ;
    END
    PORT
      LAYER M5 ;
        RECT 188.960000 181.976000 189.000000 182.016000 ;
    END
    PORT
      LAYER M5 ;
        RECT 191.520000 0.000000 191.560000 0.040000 ;
    END
    PORT
      LAYER M5 ;
        RECT 191.520000 181.976000 191.560000 182.016000 ;
    END
    PORT
      LAYER M5 ;
        RECT 194.000000 0.000000 194.040000 0.040000 ;
    END
    PORT
      LAYER M5 ;
        RECT 194.000000 181.976000 194.040000 182.016000 ;
    END
    PORT
      LAYER M5 ;
        RECT 196.560000 0.000000 196.600000 0.040000 ;
    END
    PORT
      LAYER M5 ;
        RECT 196.560000 181.976000 196.600000 182.016000 ;
    END
    PORT
      LAYER M5 ;
        RECT 199.040000 0.000000 199.080000 0.040000 ;
    END
    PORT
      LAYER M5 ;
        RECT 199.040000 181.976000 199.080000 182.016000 ;
    END
    PORT
      LAYER M5 ;
        RECT 201.600000 0.000000 201.640000 0.040000 ;
    END
    PORT
      LAYER M5 ;
        RECT 201.600000 181.976000 201.640000 182.016000 ;
    END
    PORT
      LAYER M5 ;
        RECT 204.080000 0.000000 204.120000 0.040000 ;
    END
    PORT
      LAYER M5 ;
        RECT 204.080000 181.976000 204.120000 182.016000 ;
    END
    PORT
      LAYER M5 ;
        RECT 206.640000 0.000000 206.680000 0.040000 ;
    END
    PORT
      LAYER M5 ;
        RECT 206.640000 181.976000 206.680000 182.016000 ;
    END
    PORT
      LAYER M5 ;
        RECT 209.120000 0.000000 209.160000 0.040000 ;
    END
    PORT
      LAYER M5 ;
        RECT 209.120000 181.976000 209.160000 182.016000 ;
    END
    PORT
      LAYER M5 ;
        RECT 211.680000 0.000000 211.720000 0.040000 ;
    END
    PORT
      LAYER M5 ;
        RECT 211.680000 181.976000 211.720000 182.016000 ;
    END
    PORT
      LAYER M5 ;
        RECT 214.160000 0.000000 214.200000 0.040000 ;
    END
    PORT
      LAYER M5 ;
        RECT 214.160000 181.976000 214.200000 182.016000 ;
    END
    PORT
      LAYER M6 ;
        RECT 0.000000 0.028000 0.040000 0.068000 ;
    END
    PORT
      LAYER M6 ;
        RECT 215.960000 0.028000 216.000000 0.068000 ;
    END
    PORT
      LAYER M6 ;
        RECT 0.000000 2.268000 0.040000 2.308000 ;
    END
    PORT
      LAYER M6 ;
        RECT 215.960000 2.268000 216.000000 2.308000 ;
    END
    PORT
      LAYER M6 ;
        RECT 0.000000 4.588000 0.040000 4.628000 ;
    END
    PORT
      LAYER M6 ;
        RECT 215.960000 4.588000 216.000000 4.628000 ;
    END
    PORT
      LAYER M6 ;
        RECT 0.000000 6.908000 0.040000 6.948000 ;
    END
    PORT
      LAYER M6 ;
        RECT 215.960000 6.908000 216.000000 6.948000 ;
    END
    PORT
      LAYER M6 ;
        RECT 0.000000 9.228000 0.040000 9.268000 ;
    END
    PORT
      LAYER M6 ;
        RECT 215.960000 9.228000 216.000000 9.268000 ;
    END
    PORT
      LAYER M6 ;
        RECT 0.000000 11.548000 0.040000 11.588000 ;
    END
    PORT
      LAYER M6 ;
        RECT 215.960000 11.548000 216.000000 11.588000 ;
    END
    PORT
      LAYER M6 ;
        RECT 0.000000 13.788000 0.040000 13.828000 ;
    END
    PORT
      LAYER M6 ;
        RECT 215.960000 13.788000 216.000000 13.828000 ;
    END
    PORT
      LAYER M6 ;
        RECT 0.000000 16.108000 0.040000 16.148000 ;
    END
    PORT
      LAYER M6 ;
        RECT 215.960000 16.108000 216.000000 16.148000 ;
    END
    PORT
      LAYER M6 ;
        RECT 0.000000 18.428000 0.040000 18.468000 ;
    END
    PORT
      LAYER M6 ;
        RECT 215.960000 18.428000 216.000000 18.468000 ;
    END
    PORT
      LAYER M6 ;
        RECT 0.000000 20.748000 0.040000 20.788000 ;
    END
    PORT
      LAYER M6 ;
        RECT 215.960000 20.748000 216.000000 20.788000 ;
    END
    PORT
      LAYER M6 ;
        RECT 0.000000 23.068000 0.040000 23.108000 ;
    END
    PORT
      LAYER M6 ;
        RECT 215.960000 23.068000 216.000000 23.108000 ;
    END
    PORT
      LAYER M6 ;
        RECT 0.000000 25.308000 0.040000 25.348000 ;
    END
    PORT
      LAYER M6 ;
        RECT 215.960000 25.308000 216.000000 25.348000 ;
    END
    PORT
      LAYER M6 ;
        RECT 0.000000 27.628000 0.040000 27.668000 ;
    END
    PORT
      LAYER M6 ;
        RECT 215.960000 27.628000 216.000000 27.668000 ;
    END
    PORT
      LAYER M6 ;
        RECT 0.000000 29.948000 0.040000 29.988000 ;
    END
    PORT
      LAYER M6 ;
        RECT 215.960000 29.948000 216.000000 29.988000 ;
    END
    PORT
      LAYER M6 ;
        RECT 0.000000 32.268000 0.040000 32.308000 ;
    END
    PORT
      LAYER M6 ;
        RECT 215.960000 32.268000 216.000000 32.308000 ;
    END
    PORT
      LAYER M6 ;
        RECT 0.000000 34.588000 0.040000 34.628000 ;
    END
    PORT
      LAYER M6 ;
        RECT 215.960000 34.588000 216.000000 34.628000 ;
    END
    PORT
      LAYER M6 ;
        RECT 0.000000 36.828000 0.040000 36.868000 ;
    END
    PORT
      LAYER M6 ;
        RECT 215.960000 36.828000 216.000000 36.868000 ;
    END
    PORT
      LAYER M6 ;
        RECT 0.000000 39.148000 0.040000 39.188000 ;
    END
    PORT
      LAYER M6 ;
        RECT 215.960000 39.148000 216.000000 39.188000 ;
    END
    PORT
      LAYER M6 ;
        RECT 0.000000 41.468000 0.040000 41.508000 ;
    END
    PORT
      LAYER M6 ;
        RECT 215.960000 41.468000 216.000000 41.508000 ;
    END
    PORT
      LAYER M6 ;
        RECT 0.000000 43.788000 0.040000 43.828000 ;
    END
    PORT
      LAYER M6 ;
        RECT 215.960000 43.788000 216.000000 43.828000 ;
    END
    PORT
      LAYER M6 ;
        RECT 0.000000 46.108000 0.040000 46.148000 ;
    END
    PORT
      LAYER M6 ;
        RECT 215.960000 46.108000 216.000000 46.148000 ;
    END
    PORT
      LAYER M6 ;
        RECT 0.000000 48.348000 0.040000 48.388000 ;
    END
    PORT
      LAYER M6 ;
        RECT 215.960000 48.348000 216.000000 48.388000 ;
    END
    PORT
      LAYER M6 ;
        RECT 0.000000 50.668000 0.040000 50.708000 ;
    END
    PORT
      LAYER M6 ;
        RECT 215.960000 50.668000 216.000000 50.708000 ;
    END
    PORT
      LAYER M6 ;
        RECT 0.000000 52.988000 0.040000 53.028000 ;
    END
    PORT
      LAYER M6 ;
        RECT 215.960000 52.988000 216.000000 53.028000 ;
    END
    PORT
      LAYER M6 ;
        RECT 0.000000 55.308000 0.040000 55.348000 ;
    END
    PORT
      LAYER M6 ;
        RECT 215.960000 55.308000 216.000000 55.348000 ;
    END
    PORT
      LAYER M6 ;
        RECT 0.000000 57.628000 0.040000 57.668000 ;
    END
    PORT
      LAYER M6 ;
        RECT 215.960000 57.628000 216.000000 57.668000 ;
    END
    PORT
      LAYER M6 ;
        RECT 0.000000 59.868000 0.040000 59.908000 ;
    END
    PORT
      LAYER M6 ;
        RECT 215.960000 59.868000 216.000000 59.908000 ;
    END
    PORT
      LAYER M6 ;
        RECT 0.000000 62.188000 0.040000 62.228000 ;
    END
    PORT
      LAYER M6 ;
        RECT 215.960000 62.188000 216.000000 62.228000 ;
    END
    PORT
      LAYER M6 ;
        RECT 0.000000 64.508000 0.040000 64.548000 ;
    END
    PORT
      LAYER M6 ;
        RECT 215.960000 64.508000 216.000000 64.548000 ;
    END
    PORT
      LAYER M6 ;
        RECT 0.000000 66.828000 0.040000 66.868000 ;
    END
    PORT
      LAYER M6 ;
        RECT 215.960000 66.828000 216.000000 66.868000 ;
    END
    PORT
      LAYER M6 ;
        RECT 0.000000 69.148000 0.040000 69.188000 ;
    END
    PORT
      LAYER M6 ;
        RECT 215.960000 69.148000 216.000000 69.188000 ;
    END
    PORT
      LAYER M6 ;
        RECT 0.000000 71.388000 0.040000 71.428000 ;
    END
    PORT
      LAYER M6 ;
        RECT 215.960000 71.388000 216.000000 71.428000 ;
    END
    PORT
      LAYER M6 ;
        RECT 0.000000 73.708000 0.040000 73.748000 ;
    END
    PORT
      LAYER M6 ;
        RECT 215.960000 73.708000 216.000000 73.748000 ;
    END
    PORT
      LAYER M6 ;
        RECT 0.000000 76.028000 0.040000 76.068000 ;
    END
    PORT
      LAYER M6 ;
        RECT 215.960000 76.028000 216.000000 76.068000 ;
    END
    PORT
      LAYER M6 ;
        RECT 0.000000 78.348000 0.040000 78.388000 ;
    END
    PORT
      LAYER M6 ;
        RECT 215.960000 78.348000 216.000000 78.388000 ;
    END
    PORT
      LAYER M6 ;
        RECT 0.000000 80.668000 0.040000 80.708000 ;
    END
    PORT
      LAYER M6 ;
        RECT 215.960000 80.668000 216.000000 80.708000 ;
    END
    PORT
      LAYER M6 ;
        RECT 0.000000 82.908000 0.040000 82.948000 ;
    END
    PORT
      LAYER M6 ;
        RECT 215.960000 82.908000 216.000000 82.948000 ;
    END
    PORT
      LAYER M6 ;
        RECT 0.000000 85.228000 0.040000 85.268000 ;
    END
    PORT
      LAYER M6 ;
        RECT 215.960000 85.228000 216.000000 85.268000 ;
    END
    PORT
      LAYER M6 ;
        RECT 0.000000 87.548000 0.040000 87.588000 ;
    END
    PORT
      LAYER M6 ;
        RECT 215.960000 87.548000 216.000000 87.588000 ;
    END
    PORT
      LAYER M6 ;
        RECT 0.000000 89.868000 0.040000 89.908000 ;
    END
    PORT
      LAYER M6 ;
        RECT 215.960000 89.868000 216.000000 89.908000 ;
    END
    PORT
      LAYER M6 ;
        RECT 0.000000 92.188000 0.040000 92.228000 ;
    END
    PORT
      LAYER M6 ;
        RECT 215.960000 92.188000 216.000000 92.228000 ;
    END
    PORT
      LAYER M6 ;
        RECT 0.000000 94.428000 0.040000 94.468000 ;
    END
    PORT
      LAYER M6 ;
        RECT 215.960000 94.428000 216.000000 94.468000 ;
    END
    PORT
      LAYER M6 ;
        RECT 0.000000 96.748000 0.040000 96.788000 ;
    END
    PORT
      LAYER M6 ;
        RECT 215.960000 96.748000 216.000000 96.788000 ;
    END
    PORT
      LAYER M6 ;
        RECT 0.000000 99.068000 0.040000 99.108000 ;
    END
    PORT
      LAYER M6 ;
        RECT 215.960000 99.068000 216.000000 99.108000 ;
    END
    PORT
      LAYER M6 ;
        RECT 0.000000 101.388000 0.040000 101.428000 ;
    END
    PORT
      LAYER M6 ;
        RECT 215.960000 101.388000 216.000000 101.428000 ;
    END
    PORT
      LAYER M6 ;
        RECT 0.000000 103.708000 0.040000 103.748000 ;
    END
    PORT
      LAYER M6 ;
        RECT 215.960000 103.708000 216.000000 103.748000 ;
    END
    PORT
      LAYER M6 ;
        RECT 0.000000 105.948000 0.040000 105.988000 ;
    END
    PORT
      LAYER M6 ;
        RECT 215.960000 105.948000 216.000000 105.988000 ;
    END
    PORT
      LAYER M6 ;
        RECT 0.000000 108.268000 0.040000 108.308000 ;
    END
    PORT
      LAYER M6 ;
        RECT 215.960000 108.268000 216.000000 108.308000 ;
    END
    PORT
      LAYER M6 ;
        RECT 0.000000 110.588000 0.040000 110.628000 ;
    END
    PORT
      LAYER M6 ;
        RECT 215.960000 110.588000 216.000000 110.628000 ;
    END
    PORT
      LAYER M6 ;
        RECT 0.000000 112.908000 0.040000 112.948000 ;
    END
    PORT
      LAYER M6 ;
        RECT 215.960000 112.908000 216.000000 112.948000 ;
    END
    PORT
      LAYER M6 ;
        RECT 0.000000 115.228000 0.040000 115.268000 ;
    END
    PORT
      LAYER M6 ;
        RECT 215.960000 115.228000 216.000000 115.268000 ;
    END
    PORT
      LAYER M6 ;
        RECT 0.000000 117.468000 0.040000 117.508000 ;
    END
    PORT
      LAYER M6 ;
        RECT 215.960000 117.468000 216.000000 117.508000 ;
    END
    PORT
      LAYER M6 ;
        RECT 0.000000 119.788000 0.040000 119.828000 ;
    END
    PORT
      LAYER M6 ;
        RECT 215.960000 119.788000 216.000000 119.828000 ;
    END
    PORT
      LAYER M6 ;
        RECT 0.000000 122.108000 0.040000 122.148000 ;
    END
    PORT
      LAYER M6 ;
        RECT 215.960000 122.108000 216.000000 122.148000 ;
    END
    PORT
      LAYER M6 ;
        RECT 0.000000 124.428000 0.040000 124.468000 ;
    END
    PORT
      LAYER M6 ;
        RECT 215.960000 124.428000 216.000000 124.468000 ;
    END
    PORT
      LAYER M6 ;
        RECT 0.000000 126.748000 0.040000 126.788000 ;
    END
    PORT
      LAYER M6 ;
        RECT 215.960000 126.748000 216.000000 126.788000 ;
    END
    PORT
      LAYER M6 ;
        RECT 0.000000 128.988000 0.040000 129.028000 ;
    END
    PORT
      LAYER M6 ;
        RECT 215.960000 128.988000 216.000000 129.028000 ;
    END
    PORT
      LAYER M6 ;
        RECT 0.000000 131.308000 0.040000 131.348000 ;
    END
    PORT
      LAYER M6 ;
        RECT 215.960000 131.308000 216.000000 131.348000 ;
    END
    PORT
      LAYER M6 ;
        RECT 0.000000 133.628000 0.040000 133.668000 ;
    END
    PORT
      LAYER M6 ;
        RECT 215.960000 133.628000 216.000000 133.668000 ;
    END
    PORT
      LAYER M6 ;
        RECT 0.000000 135.948000 0.040000 135.988000 ;
    END
    PORT
      LAYER M6 ;
        RECT 215.960000 135.948000 216.000000 135.988000 ;
    END
    PORT
      LAYER M6 ;
        RECT 0.000000 138.268000 0.040000 138.308000 ;
    END
    PORT
      LAYER M6 ;
        RECT 215.960000 138.268000 216.000000 138.308000 ;
    END
    PORT
      LAYER M6 ;
        RECT 0.000000 140.508000 0.040000 140.548000 ;
    END
    PORT
      LAYER M6 ;
        RECT 215.960000 140.508000 216.000000 140.548000 ;
    END
    PORT
      LAYER M6 ;
        RECT 0.000000 142.828000 0.040000 142.868000 ;
    END
    PORT
      LAYER M6 ;
        RECT 215.960000 142.828000 216.000000 142.868000 ;
    END
    PORT
      LAYER M6 ;
        RECT 0.000000 145.148000 0.040000 145.188000 ;
    END
    PORT
      LAYER M6 ;
        RECT 215.960000 145.148000 216.000000 145.188000 ;
    END
    PORT
      LAYER M6 ;
        RECT 0.000000 147.468000 0.040000 147.508000 ;
    END
    PORT
      LAYER M6 ;
        RECT 215.960000 147.468000 216.000000 147.508000 ;
    END
    PORT
      LAYER M6 ;
        RECT 0.000000 149.788000 0.040000 149.828000 ;
    END
    PORT
      LAYER M6 ;
        RECT 215.960000 149.788000 216.000000 149.828000 ;
    END
    PORT
      LAYER M6 ;
        RECT 0.000000 152.028000 0.040000 152.068000 ;
    END
    PORT
      LAYER M6 ;
        RECT 215.960000 152.028000 216.000000 152.068000 ;
    END
    PORT
      LAYER M6 ;
        RECT 0.000000 154.348000 0.040000 154.388000 ;
    END
    PORT
      LAYER M6 ;
        RECT 215.960000 154.348000 216.000000 154.388000 ;
    END
    PORT
      LAYER M6 ;
        RECT 0.000000 156.668000 0.040000 156.708000 ;
    END
    PORT
      LAYER M6 ;
        RECT 215.960000 156.668000 216.000000 156.708000 ;
    END
    PORT
      LAYER M6 ;
        RECT 0.000000 158.988000 0.040000 159.028000 ;
    END
    PORT
      LAYER M6 ;
        RECT 215.960000 158.988000 216.000000 159.028000 ;
    END
    PORT
      LAYER M6 ;
        RECT 0.000000 161.308000 0.040000 161.348000 ;
    END
    PORT
      LAYER M6 ;
        RECT 215.960000 161.308000 216.000000 161.348000 ;
    END
    PORT
      LAYER M6 ;
        RECT 0.000000 163.548000 0.040000 163.588000 ;
    END
    PORT
      LAYER M6 ;
        RECT 215.960000 163.548000 216.000000 163.588000 ;
    END
    PORT
      LAYER M6 ;
        RECT 0.000000 165.868000 0.040000 165.908000 ;
    END
    PORT
      LAYER M6 ;
        RECT 215.960000 165.868000 216.000000 165.908000 ;
    END
    PORT
      LAYER M6 ;
        RECT 0.000000 168.188000 0.040000 168.228000 ;
    END
    PORT
      LAYER M6 ;
        RECT 215.960000 168.188000 216.000000 168.228000 ;
    END
    PORT
      LAYER M6 ;
        RECT 0.000000 170.508000 0.040000 170.548000 ;
    END
    PORT
      LAYER M6 ;
        RECT 215.960000 170.508000 216.000000 170.548000 ;
    END
    PORT
      LAYER M6 ;
        RECT 0.000000 172.828000 0.040000 172.868000 ;
    END
    PORT
      LAYER M6 ;
        RECT 215.960000 172.828000 216.000000 172.868000 ;
    END
    PORT
      LAYER M6 ;
        RECT 0.000000 175.068000 0.040000 175.108000 ;
    END
    PORT
      LAYER M6 ;
        RECT 215.960000 175.068000 216.000000 175.108000 ;
    END
    PORT
      LAYER M6 ;
        RECT 0.000000 177.388000 0.040000 177.428000 ;
    END
    PORT
      LAYER M6 ;
        RECT 215.960000 177.388000 216.000000 177.428000 ;
    END
    PORT
      LAYER M6 ;
        RECT 0.000000 179.708000 0.040000 179.748000 ;
    END
    PORT
      LAYER M6 ;
        RECT 215.960000 179.708000 216.000000 179.748000 ;
    END
    PORT
      LAYER M7 ;
        RECT 0.040000 0.000000 0.160000 0.120000 ;
    END
    PORT
      LAYER M7 ;
        RECT 0.040000 181.896000 0.160000 182.016000 ;
    END
    PORT
      LAYER M7 ;
        RECT 2.520000 0.000000 2.640000 0.120000 ;
    END
    PORT
      LAYER M7 ;
        RECT 2.520000 181.896000 2.640000 182.016000 ;
    END
    PORT
      LAYER M7 ;
        RECT 5.000000 0.000000 5.120000 0.120000 ;
    END
    PORT
      LAYER M7 ;
        RECT 5.000000 181.896000 5.120000 182.016000 ;
    END
    PORT
      LAYER M7 ;
        RECT 7.560000 0.000000 7.680000 0.120000 ;
    END
    PORT
      LAYER M7 ;
        RECT 7.560000 181.896000 7.680000 182.016000 ;
    END
    PORT
      LAYER M7 ;
        RECT 10.040000 0.000000 10.160000 0.120000 ;
    END
    PORT
      LAYER M7 ;
        RECT 10.040000 181.896000 10.160000 182.016000 ;
    END
    PORT
      LAYER M7 ;
        RECT 12.600000 0.000000 12.720000 0.120000 ;
    END
    PORT
      LAYER M7 ;
        RECT 12.600000 181.896000 12.720000 182.016000 ;
    END
    PORT
      LAYER M7 ;
        RECT 15.080000 0.000000 15.200000 0.120000 ;
    END
    PORT
      LAYER M7 ;
        RECT 15.080000 181.896000 15.200000 182.016000 ;
    END
    PORT
      LAYER M7 ;
        RECT 17.640000 0.000000 17.760000 0.120000 ;
    END
    PORT
      LAYER M7 ;
        RECT 17.640000 181.896000 17.760000 182.016000 ;
    END
    PORT
      LAYER M7 ;
        RECT 20.120000 0.000000 20.240000 0.120000 ;
    END
    PORT
      LAYER M7 ;
        RECT 20.120000 181.896000 20.240000 182.016000 ;
    END
    PORT
      LAYER M7 ;
        RECT 22.680000 0.000000 22.800000 0.120000 ;
    END
    PORT
      LAYER M7 ;
        RECT 22.680000 181.896000 22.800000 182.016000 ;
    END
    PORT
      LAYER M7 ;
        RECT 25.160000 0.000000 25.280000 0.120000 ;
    END
    PORT
      LAYER M7 ;
        RECT 25.160000 181.896000 25.280000 182.016000 ;
    END
    PORT
      LAYER M7 ;
        RECT 27.720000 0.000000 27.840000 0.120000 ;
    END
    PORT
      LAYER M7 ;
        RECT 27.720000 181.896000 27.840000 182.016000 ;
    END
    PORT
      LAYER M7 ;
        RECT 30.200000 0.000000 30.320000 0.120000 ;
    END
    PORT
      LAYER M7 ;
        RECT 30.200000 181.896000 30.320000 182.016000 ;
    END
    PORT
      LAYER M7 ;
        RECT 32.760000 0.000000 32.880000 0.120000 ;
    END
    PORT
      LAYER M7 ;
        RECT 32.760000 181.896000 32.880000 182.016000 ;
    END
    PORT
      LAYER M7 ;
        RECT 35.240000 0.000000 35.360000 0.120000 ;
    END
    PORT
      LAYER M7 ;
        RECT 35.240000 181.896000 35.360000 182.016000 ;
    END
    PORT
      LAYER M7 ;
        RECT 37.800000 0.000000 37.920000 0.120000 ;
    END
    PORT
      LAYER M7 ;
        RECT 37.800000 181.896000 37.920000 182.016000 ;
    END
    PORT
      LAYER M7 ;
        RECT 40.280000 0.000000 40.400000 0.120000 ;
    END
    PORT
      LAYER M7 ;
        RECT 40.280000 181.896000 40.400000 182.016000 ;
    END
    PORT
      LAYER M7 ;
        RECT 42.840000 0.000000 42.960000 0.120000 ;
    END
    PORT
      LAYER M7 ;
        RECT 42.840000 181.896000 42.960000 182.016000 ;
    END
    PORT
      LAYER M7 ;
        RECT 45.320000 0.000000 45.440000 0.120000 ;
    END
    PORT
      LAYER M7 ;
        RECT 45.320000 181.896000 45.440000 182.016000 ;
    END
    PORT
      LAYER M7 ;
        RECT 47.880000 0.000000 48.000000 0.120000 ;
    END
    PORT
      LAYER M7 ;
        RECT 47.880000 181.896000 48.000000 182.016000 ;
    END
    PORT
      LAYER M7 ;
        RECT 50.360000 0.000000 50.480000 0.120000 ;
    END
    PORT
      LAYER M7 ;
        RECT 50.360000 181.896000 50.480000 182.016000 ;
    END
    PORT
      LAYER M7 ;
        RECT 52.920000 0.000000 53.040000 0.120000 ;
    END
    PORT
      LAYER M7 ;
        RECT 52.920000 181.896000 53.040000 182.016000 ;
    END
    PORT
      LAYER M7 ;
        RECT 55.400000 0.000000 55.520000 0.120000 ;
    END
    PORT
      LAYER M7 ;
        RECT 55.400000 181.896000 55.520000 182.016000 ;
    END
    PORT
      LAYER M7 ;
        RECT 57.960000 0.000000 58.080000 0.120000 ;
    END
    PORT
      LAYER M7 ;
        RECT 57.960000 181.896000 58.080000 182.016000 ;
    END
    PORT
      LAYER M7 ;
        RECT 60.440000 0.000000 60.560000 0.120000 ;
    END
    PORT
      LAYER M7 ;
        RECT 60.440000 181.896000 60.560000 182.016000 ;
    END
    PORT
      LAYER M7 ;
        RECT 63.000000 0.000000 63.120000 0.120000 ;
    END
    PORT
      LAYER M7 ;
        RECT 63.000000 181.896000 63.120000 182.016000 ;
    END
    PORT
      LAYER M7 ;
        RECT 65.480000 0.000000 65.600000 0.120000 ;
    END
    PORT
      LAYER M7 ;
        RECT 65.480000 181.896000 65.600000 182.016000 ;
    END
    PORT
      LAYER M7 ;
        RECT 68.040000 0.000000 68.160000 0.120000 ;
    END
    PORT
      LAYER M7 ;
        RECT 68.040000 181.896000 68.160000 182.016000 ;
    END
    PORT
      LAYER M7 ;
        RECT 70.520000 0.000000 70.640000 0.120000 ;
    END
    PORT
      LAYER M7 ;
        RECT 70.520000 181.896000 70.640000 182.016000 ;
    END
    PORT
      LAYER M7 ;
        RECT 73.080000 0.000000 73.200000 0.120000 ;
    END
    PORT
      LAYER M7 ;
        RECT 73.080000 181.896000 73.200000 182.016000 ;
    END
    PORT
      LAYER M7 ;
        RECT 75.560000 0.000000 75.680000 0.120000 ;
    END
    PORT
      LAYER M7 ;
        RECT 75.560000 181.896000 75.680000 182.016000 ;
    END
    PORT
      LAYER M7 ;
        RECT 78.120000 0.000000 78.240000 0.120000 ;
    END
    PORT
      LAYER M7 ;
        RECT 78.120000 181.896000 78.240000 182.016000 ;
    END
    PORT
      LAYER M7 ;
        RECT 80.600000 0.000000 80.720000 0.120000 ;
    END
    PORT
      LAYER M7 ;
        RECT 80.600000 181.896000 80.720000 182.016000 ;
    END
    PORT
      LAYER M7 ;
        RECT 83.160000 0.000000 83.280000 0.120000 ;
    END
    PORT
      LAYER M7 ;
        RECT 83.160000 181.896000 83.280000 182.016000 ;
    END
    PORT
      LAYER M7 ;
        RECT 85.640000 0.000000 85.760000 0.120000 ;
    END
    PORT
      LAYER M7 ;
        RECT 85.640000 181.896000 85.760000 182.016000 ;
    END
    PORT
      LAYER M7 ;
        RECT 88.200000 0.000000 88.320000 0.120000 ;
    END
    PORT
      LAYER M7 ;
        RECT 88.200000 181.896000 88.320000 182.016000 ;
    END
    PORT
      LAYER M7 ;
        RECT 90.680000 0.000000 90.800000 0.120000 ;
    END
    PORT
      LAYER M7 ;
        RECT 90.680000 181.896000 90.800000 182.016000 ;
    END
    PORT
      LAYER M7 ;
        RECT 93.240000 0.000000 93.360000 0.120000 ;
    END
    PORT
      LAYER M7 ;
        RECT 93.240000 181.896000 93.360000 182.016000 ;
    END
    PORT
      LAYER M7 ;
        RECT 95.720000 0.000000 95.840000 0.120000 ;
    END
    PORT
      LAYER M7 ;
        RECT 95.720000 181.896000 95.840000 182.016000 ;
    END
    PORT
      LAYER M7 ;
        RECT 98.280000 0.000000 98.400000 0.120000 ;
    END
    PORT
      LAYER M7 ;
        RECT 98.280000 181.896000 98.400000 182.016000 ;
    END
    PORT
      LAYER M7 ;
        RECT 100.760000 0.000000 100.880000 0.120000 ;
    END
    PORT
      LAYER M7 ;
        RECT 100.760000 181.896000 100.880000 182.016000 ;
    END
    PORT
      LAYER M7 ;
        RECT 103.320000 0.000000 103.440000 0.120000 ;
    END
    PORT
      LAYER M7 ;
        RECT 103.320000 181.896000 103.440000 182.016000 ;
    END
    PORT
      LAYER M7 ;
        RECT 105.800000 0.000000 105.920000 0.120000 ;
    END
    PORT
      LAYER M7 ;
        RECT 105.800000 181.896000 105.920000 182.016000 ;
    END
    PORT
      LAYER M7 ;
        RECT 108.360000 0.000000 108.480000 0.120000 ;
    END
    PORT
      LAYER M7 ;
        RECT 108.360000 181.896000 108.480000 182.016000 ;
    END
    PORT
      LAYER M7 ;
        RECT 110.840000 0.000000 110.960000 0.120000 ;
    END
    PORT
      LAYER M7 ;
        RECT 110.840000 181.896000 110.960000 182.016000 ;
    END
    PORT
      LAYER M7 ;
        RECT 113.400000 0.000000 113.520000 0.120000 ;
    END
    PORT
      LAYER M7 ;
        RECT 113.400000 181.896000 113.520000 182.016000 ;
    END
    PORT
      LAYER M7 ;
        RECT 115.880000 0.000000 116.000000 0.120000 ;
    END
    PORT
      LAYER M7 ;
        RECT 115.880000 181.896000 116.000000 182.016000 ;
    END
    PORT
      LAYER M7 ;
        RECT 118.440000 0.000000 118.560000 0.120000 ;
    END
    PORT
      LAYER M7 ;
        RECT 118.440000 181.896000 118.560000 182.016000 ;
    END
    PORT
      LAYER M7 ;
        RECT 120.920000 0.000000 121.040000 0.120000 ;
    END
    PORT
      LAYER M7 ;
        RECT 120.920000 181.896000 121.040000 182.016000 ;
    END
    PORT
      LAYER M7 ;
        RECT 123.480000 0.000000 123.600000 0.120000 ;
    END
    PORT
      LAYER M7 ;
        RECT 123.480000 181.896000 123.600000 182.016000 ;
    END
    PORT
      LAYER M7 ;
        RECT 125.960000 0.000000 126.080000 0.120000 ;
    END
    PORT
      LAYER M7 ;
        RECT 125.960000 181.896000 126.080000 182.016000 ;
    END
    PORT
      LAYER M7 ;
        RECT 128.520000 0.000000 128.640000 0.120000 ;
    END
    PORT
      LAYER M7 ;
        RECT 128.520000 181.896000 128.640000 182.016000 ;
    END
    PORT
      LAYER M7 ;
        RECT 131.000000 0.000000 131.120000 0.120000 ;
    END
    PORT
      LAYER M7 ;
        RECT 131.000000 181.896000 131.120000 182.016000 ;
    END
    PORT
      LAYER M7 ;
        RECT 133.560000 0.000000 133.680000 0.120000 ;
    END
    PORT
      LAYER M7 ;
        RECT 133.560000 181.896000 133.680000 182.016000 ;
    END
    PORT
      LAYER M7 ;
        RECT 136.040000 0.000000 136.160000 0.120000 ;
    END
    PORT
      LAYER M7 ;
        RECT 136.040000 181.896000 136.160000 182.016000 ;
    END
    PORT
      LAYER M7 ;
        RECT 138.600000 0.000000 138.720000 0.120000 ;
    END
    PORT
      LAYER M7 ;
        RECT 138.600000 181.896000 138.720000 182.016000 ;
    END
    PORT
      LAYER M7 ;
        RECT 141.080000 0.000000 141.200000 0.120000 ;
    END
    PORT
      LAYER M7 ;
        RECT 141.080000 181.896000 141.200000 182.016000 ;
    END
    PORT
      LAYER M7 ;
        RECT 143.640000 0.000000 143.760000 0.120000 ;
    END
    PORT
      LAYER M7 ;
        RECT 143.640000 181.896000 143.760000 182.016000 ;
    END
    PORT
      LAYER M7 ;
        RECT 146.120000 0.000000 146.240000 0.120000 ;
    END
    PORT
      LAYER M7 ;
        RECT 146.120000 181.896000 146.240000 182.016000 ;
    END
    PORT
      LAYER M7 ;
        RECT 148.680000 0.000000 148.800000 0.120000 ;
    END
    PORT
      LAYER M7 ;
        RECT 148.680000 181.896000 148.800000 182.016000 ;
    END
    PORT
      LAYER M7 ;
        RECT 151.160000 0.000000 151.280000 0.120000 ;
    END
    PORT
      LAYER M7 ;
        RECT 151.160000 181.896000 151.280000 182.016000 ;
    END
    PORT
      LAYER M7 ;
        RECT 153.720000 0.000000 153.840000 0.120000 ;
    END
    PORT
      LAYER M7 ;
        RECT 153.720000 181.896000 153.840000 182.016000 ;
    END
    PORT
      LAYER M7 ;
        RECT 156.200000 0.000000 156.320000 0.120000 ;
    END
    PORT
      LAYER M7 ;
        RECT 156.200000 181.896000 156.320000 182.016000 ;
    END
    PORT
      LAYER M7 ;
        RECT 158.760000 0.000000 158.880000 0.120000 ;
    END
    PORT
      LAYER M7 ;
        RECT 158.760000 181.896000 158.880000 182.016000 ;
    END
    PORT
      LAYER M7 ;
        RECT 161.240000 0.000000 161.360000 0.120000 ;
    END
    PORT
      LAYER M7 ;
        RECT 161.240000 181.896000 161.360000 182.016000 ;
    END
    PORT
      LAYER M7 ;
        RECT 163.800000 0.000000 163.920000 0.120000 ;
    END
    PORT
      LAYER M7 ;
        RECT 163.800000 181.896000 163.920000 182.016000 ;
    END
    PORT
      LAYER M7 ;
        RECT 166.280000 0.000000 166.400000 0.120000 ;
    END
    PORT
      LAYER M7 ;
        RECT 166.280000 181.896000 166.400000 182.016000 ;
    END
    PORT
      LAYER M7 ;
        RECT 168.840000 0.000000 168.960000 0.120000 ;
    END
    PORT
      LAYER M7 ;
        RECT 168.840000 181.896000 168.960000 182.016000 ;
    END
    PORT
      LAYER M7 ;
        RECT 171.320000 0.000000 171.440000 0.120000 ;
    END
    PORT
      LAYER M7 ;
        RECT 171.320000 181.896000 171.440000 182.016000 ;
    END
    PORT
      LAYER M7 ;
        RECT 173.880000 0.000000 174.000000 0.120000 ;
    END
    PORT
      LAYER M7 ;
        RECT 173.880000 181.896000 174.000000 182.016000 ;
    END
    PORT
      LAYER M7 ;
        RECT 176.360000 0.000000 176.480000 0.120000 ;
    END
    PORT
      LAYER M7 ;
        RECT 176.360000 181.896000 176.480000 182.016000 ;
    END
    PORT
      LAYER M7 ;
        RECT 178.920000 0.000000 179.040000 0.120000 ;
    END
    PORT
      LAYER M7 ;
        RECT 178.920000 181.896000 179.040000 182.016000 ;
    END
    PORT
      LAYER M7 ;
        RECT 181.400000 0.000000 181.520000 0.120000 ;
    END
    PORT
      LAYER M7 ;
        RECT 181.400000 181.896000 181.520000 182.016000 ;
    END
    PORT
      LAYER M7 ;
        RECT 183.960000 0.000000 184.080000 0.120000 ;
    END
    PORT
      LAYER M7 ;
        RECT 183.960000 181.896000 184.080000 182.016000 ;
    END
    PORT
      LAYER M7 ;
        RECT 186.440000 0.000000 186.560000 0.120000 ;
    END
    PORT
      LAYER M7 ;
        RECT 186.440000 181.896000 186.560000 182.016000 ;
    END
    PORT
      LAYER M7 ;
        RECT 189.000000 0.000000 189.120000 0.120000 ;
    END
    PORT
      LAYER M7 ;
        RECT 189.000000 181.896000 189.120000 182.016000 ;
    END
    PORT
      LAYER M7 ;
        RECT 191.480000 0.000000 191.600000 0.120000 ;
    END
    PORT
      LAYER M7 ;
        RECT 191.480000 181.896000 191.600000 182.016000 ;
    END
    PORT
      LAYER M7 ;
        RECT 194.040000 0.000000 194.160000 0.120000 ;
    END
    PORT
      LAYER M7 ;
        RECT 194.040000 181.896000 194.160000 182.016000 ;
    END
    PORT
      LAYER M7 ;
        RECT 196.520000 0.000000 196.640000 0.120000 ;
    END
    PORT
      LAYER M7 ;
        RECT 196.520000 181.896000 196.640000 182.016000 ;
    END
    PORT
      LAYER M7 ;
        RECT 199.080000 0.000000 199.200000 0.120000 ;
    END
    PORT
      LAYER M7 ;
        RECT 199.080000 181.896000 199.200000 182.016000 ;
    END
    PORT
      LAYER M7 ;
        RECT 201.560000 0.000000 201.680000 0.120000 ;
    END
    PORT
      LAYER M7 ;
        RECT 201.560000 181.896000 201.680000 182.016000 ;
    END
    PORT
      LAYER M7 ;
        RECT 204.120000 0.000000 204.240000 0.120000 ;
    END
    PORT
      LAYER M7 ;
        RECT 204.120000 181.896000 204.240000 182.016000 ;
    END
    PORT
      LAYER M7 ;
        RECT 206.600000 0.000000 206.720000 0.120000 ;
    END
    PORT
      LAYER M7 ;
        RECT 206.600000 181.896000 206.720000 182.016000 ;
    END
    PORT
      LAYER M7 ;
        RECT 209.160000 0.000000 209.280000 0.120000 ;
    END
    PORT
      LAYER M7 ;
        RECT 209.160000 181.896000 209.280000 182.016000 ;
    END
    PORT
      LAYER M7 ;
        RECT 211.640000 0.000000 211.760000 0.120000 ;
    END
    PORT
      LAYER M7 ;
        RECT 211.640000 181.896000 211.760000 182.016000 ;
    END
    PORT
      LAYER M7 ;
        RECT 214.200000 0.000000 214.320000 0.120000 ;
    END
    PORT
      LAYER M7 ;
        RECT 214.200000 181.896000 214.320000 182.016000 ;
    END
    PORT
      LAYER M8 ;
        RECT 0.000000 0.041000 0.062000 0.103000 ;
    END
    PORT
      LAYER M8 ;
        RECT 215.938000 0.041000 216.000000 0.103000 ;
    END
    PORT
      LAYER M8 ;
        RECT 0.000000 2.309000 0.062000 2.371000 ;
    END
    PORT
      LAYER M8 ;
        RECT 215.938000 2.309000 216.000000 2.371000 ;
    END
    PORT
      LAYER M8 ;
        RECT 0.000000 4.577000 0.062000 4.639000 ;
    END
    PORT
      LAYER M8 ;
        RECT 215.938000 4.577000 216.000000 4.639000 ;
    END
    PORT
      LAYER M8 ;
        RECT 0.000000 6.971000 0.062000 7.033000 ;
    END
    PORT
      LAYER M8 ;
        RECT 215.938000 6.971000 216.000000 7.033000 ;
    END
    PORT
      LAYER M8 ;
        RECT 0.000000 9.239000 0.062000 9.301000 ;
    END
    PORT
      LAYER M8 ;
        RECT 215.938000 9.239000 216.000000 9.301000 ;
    END
    PORT
      LAYER M8 ;
        RECT 0.000000 11.507000 0.062000 11.569000 ;
    END
    PORT
      LAYER M8 ;
        RECT 215.938000 11.507000 216.000000 11.569000 ;
    END
    PORT
      LAYER M8 ;
        RECT 0.000000 13.775000 0.062000 13.837000 ;
    END
    PORT
      LAYER M8 ;
        RECT 215.938000 13.775000 216.000000 13.837000 ;
    END
    PORT
      LAYER M8 ;
        RECT 0.000000 16.169000 0.062000 16.231000 ;
    END
    PORT
      LAYER M8 ;
        RECT 215.938000 16.169000 216.000000 16.231000 ;
    END
    PORT
      LAYER M8 ;
        RECT 0.000000 18.437000 0.062000 18.499000 ;
    END
    PORT
      LAYER M8 ;
        RECT 215.938000 18.437000 216.000000 18.499000 ;
    END
    PORT
      LAYER M8 ;
        RECT 0.000000 20.705000 0.062000 20.767000 ;
    END
    PORT
      LAYER M8 ;
        RECT 215.938000 20.705000 216.000000 20.767000 ;
    END
    PORT
      LAYER M8 ;
        RECT 0.000000 23.099000 0.062000 23.161000 ;
    END
    PORT
      LAYER M8 ;
        RECT 215.938000 23.099000 216.000000 23.161000 ;
    END
    PORT
      LAYER M8 ;
        RECT 0.000000 25.367000 0.062000 25.429000 ;
    END
    PORT
      LAYER M8 ;
        RECT 215.938000 25.367000 216.000000 25.429000 ;
    END
    PORT
      LAYER M8 ;
        RECT 0.000000 27.635000 0.062000 27.697000 ;
    END
    PORT
      LAYER M8 ;
        RECT 215.938000 27.635000 216.000000 27.697000 ;
    END
    PORT
      LAYER M8 ;
        RECT 0.000000 29.903000 0.062000 29.965000 ;
    END
    PORT
      LAYER M8 ;
        RECT 215.938000 29.903000 216.000000 29.965000 ;
    END
    PORT
      LAYER M8 ;
        RECT 0.000000 32.297000 0.062000 32.359000 ;
    END
    PORT
      LAYER M8 ;
        RECT 215.938000 32.297000 216.000000 32.359000 ;
    END
    PORT
      LAYER M8 ;
        RECT 0.000000 34.565000 0.062000 34.627000 ;
    END
    PORT
      LAYER M8 ;
        RECT 215.938000 34.565000 216.000000 34.627000 ;
    END
    PORT
      LAYER M8 ;
        RECT 0.000000 36.833000 0.062000 36.895000 ;
    END
    PORT
      LAYER M8 ;
        RECT 215.938000 36.833000 216.000000 36.895000 ;
    END
    PORT
      LAYER M8 ;
        RECT 0.000000 39.227000 0.062000 39.289000 ;
    END
    PORT
      LAYER M8 ;
        RECT 215.938000 39.227000 216.000000 39.289000 ;
    END
    PORT
      LAYER M8 ;
        RECT 0.000000 41.495000 0.062000 41.557000 ;
    END
    PORT
      LAYER M8 ;
        RECT 215.938000 41.495000 216.000000 41.557000 ;
    END
    PORT
      LAYER M8 ;
        RECT 0.000000 43.763000 0.062000 43.825000 ;
    END
    PORT
      LAYER M8 ;
        RECT 215.938000 43.763000 216.000000 43.825000 ;
    END
    PORT
      LAYER M8 ;
        RECT 0.000000 46.031000 0.062000 46.093000 ;
    END
    PORT
      LAYER M8 ;
        RECT 215.938000 46.031000 216.000000 46.093000 ;
    END
    PORT
      LAYER M8 ;
        RECT 0.000000 48.425000 0.062000 48.487000 ;
    END
    PORT
      LAYER M8 ;
        RECT 215.938000 48.425000 216.000000 48.487000 ;
    END
    PORT
      LAYER M8 ;
        RECT 0.000000 50.693000 0.062000 50.755000 ;
    END
    PORT
      LAYER M8 ;
        RECT 215.938000 50.693000 216.000000 50.755000 ;
    END
    PORT
      LAYER M8 ;
        RECT 0.000000 52.961000 0.062000 53.023000 ;
    END
    PORT
      LAYER M8 ;
        RECT 215.938000 52.961000 216.000000 53.023000 ;
    END
    PORT
      LAYER M8 ;
        RECT 0.000000 55.355000 0.062000 55.417000 ;
    END
    PORT
      LAYER M8 ;
        RECT 215.938000 55.355000 216.000000 55.417000 ;
    END
    PORT
      LAYER M8 ;
        RECT 0.000000 57.623000 0.062000 57.685000 ;
    END
    PORT
      LAYER M8 ;
        RECT 215.938000 57.623000 216.000000 57.685000 ;
    END
    PORT
      LAYER M8 ;
        RECT 0.000000 59.891000 0.062000 59.953000 ;
    END
    PORT
      LAYER M8 ;
        RECT 215.938000 59.891000 216.000000 59.953000 ;
    END
    PORT
      LAYER M8 ;
        RECT 0.000000 62.159000 0.062000 62.221000 ;
    END
    PORT
      LAYER M8 ;
        RECT 215.938000 62.159000 216.000000 62.221000 ;
    END
    PORT
      LAYER M8 ;
        RECT 0.000000 64.553000 0.062000 64.615000 ;
    END
    PORT
      LAYER M8 ;
        RECT 215.938000 64.553000 216.000000 64.615000 ;
    END
    PORT
      LAYER M8 ;
        RECT 0.000000 66.821000 0.062000 66.883000 ;
    END
    PORT
      LAYER M8 ;
        RECT 215.938000 66.821000 216.000000 66.883000 ;
    END
    PORT
      LAYER M8 ;
        RECT 0.000000 69.089000 0.062000 69.151000 ;
    END
    PORT
      LAYER M8 ;
        RECT 215.938000 69.089000 216.000000 69.151000 ;
    END
    PORT
      LAYER M8 ;
        RECT 0.000000 71.483000 0.062000 71.545000 ;
    END
    PORT
      LAYER M8 ;
        RECT 215.938000 71.483000 216.000000 71.545000 ;
    END
    PORT
      LAYER M8 ;
        RECT 0.000000 73.751000 0.062000 73.813000 ;
    END
    PORT
      LAYER M8 ;
        RECT 215.938000 73.751000 216.000000 73.813000 ;
    END
    PORT
      LAYER M8 ;
        RECT 0.000000 76.019000 0.062000 76.081000 ;
    END
    PORT
      LAYER M8 ;
        RECT 215.938000 76.019000 216.000000 76.081000 ;
    END
    PORT
      LAYER M8 ;
        RECT 0.000000 78.287000 0.062000 78.349000 ;
    END
    PORT
      LAYER M8 ;
        RECT 215.938000 78.287000 216.000000 78.349000 ;
    END
    PORT
      LAYER M8 ;
        RECT 0.000000 80.681000 0.062000 80.743000 ;
    END
    PORT
      LAYER M8 ;
        RECT 215.938000 80.681000 216.000000 80.743000 ;
    END
    PORT
      LAYER M8 ;
        RECT 0.000000 82.949000 0.062000 83.011000 ;
    END
    PORT
      LAYER M8 ;
        RECT 215.938000 82.949000 216.000000 83.011000 ;
    END
    PORT
      LAYER M8 ;
        RECT 0.000000 85.217000 0.062000 85.279000 ;
    END
    PORT
      LAYER M8 ;
        RECT 215.938000 85.217000 216.000000 85.279000 ;
    END
    PORT
      LAYER M8 ;
        RECT 0.000000 87.611000 0.062000 87.673000 ;
    END
    PORT
      LAYER M8 ;
        RECT 215.938000 87.611000 216.000000 87.673000 ;
    END
    PORT
      LAYER M8 ;
        RECT 0.000000 89.879000 0.062000 89.941000 ;
    END
    PORT
      LAYER M8 ;
        RECT 215.938000 89.879000 216.000000 89.941000 ;
    END
    PORT
      LAYER M8 ;
        RECT 0.000000 92.147000 0.062000 92.209000 ;
    END
    PORT
      LAYER M8 ;
        RECT 215.938000 92.147000 216.000000 92.209000 ;
    END
    PORT
      LAYER M8 ;
        RECT 0.000000 94.415000 0.062000 94.477000 ;
    END
    PORT
      LAYER M8 ;
        RECT 215.938000 94.415000 216.000000 94.477000 ;
    END
    PORT
      LAYER M8 ;
        RECT 0.000000 96.809000 0.062000 96.871000 ;
    END
    PORT
      LAYER M8 ;
        RECT 215.938000 96.809000 216.000000 96.871000 ;
    END
    PORT
      LAYER M8 ;
        RECT 0.000000 99.077000 0.062000 99.139000 ;
    END
    PORT
      LAYER M8 ;
        RECT 215.938000 99.077000 216.000000 99.139000 ;
    END
    PORT
      LAYER M8 ;
        RECT 0.000000 101.345000 0.062000 101.407000 ;
    END
    PORT
      LAYER M8 ;
        RECT 215.938000 101.345000 216.000000 101.407000 ;
    END
    PORT
      LAYER M8 ;
        RECT 0.000000 103.739000 0.062000 103.801000 ;
    END
    PORT
      LAYER M8 ;
        RECT 215.938000 103.739000 216.000000 103.801000 ;
    END
    PORT
      LAYER M8 ;
        RECT 0.000000 106.007000 0.062000 106.069000 ;
    END
    PORT
      LAYER M8 ;
        RECT 215.938000 106.007000 216.000000 106.069000 ;
    END
    PORT
      LAYER M8 ;
        RECT 0.000000 108.275000 0.062000 108.337000 ;
    END
    PORT
      LAYER M8 ;
        RECT 215.938000 108.275000 216.000000 108.337000 ;
    END
    PORT
      LAYER M8 ;
        RECT 0.000000 110.543000 0.062000 110.605000 ;
    END
    PORT
      LAYER M8 ;
        RECT 215.938000 110.543000 216.000000 110.605000 ;
    END
    PORT
      LAYER M8 ;
        RECT 0.000000 112.937000 0.062000 112.999000 ;
    END
    PORT
      LAYER M8 ;
        RECT 215.938000 112.937000 216.000000 112.999000 ;
    END
    PORT
      LAYER M8 ;
        RECT 0.000000 115.205000 0.062000 115.267000 ;
    END
    PORT
      LAYER M8 ;
        RECT 215.938000 115.205000 216.000000 115.267000 ;
    END
    PORT
      LAYER M8 ;
        RECT 0.000000 117.473000 0.062000 117.535000 ;
    END
    PORT
      LAYER M8 ;
        RECT 215.938000 117.473000 216.000000 117.535000 ;
    END
    PORT
      LAYER M8 ;
        RECT 0.000000 119.867000 0.062000 119.929000 ;
    END
    PORT
      LAYER M8 ;
        RECT 215.938000 119.867000 216.000000 119.929000 ;
    END
    PORT
      LAYER M8 ;
        RECT 0.000000 122.135000 0.062000 122.197000 ;
    END
    PORT
      LAYER M8 ;
        RECT 215.938000 122.135000 216.000000 122.197000 ;
    END
    PORT
      LAYER M8 ;
        RECT 0.000000 124.403000 0.062000 124.465000 ;
    END
    PORT
      LAYER M8 ;
        RECT 215.938000 124.403000 216.000000 124.465000 ;
    END
    PORT
      LAYER M8 ;
        RECT 0.000000 126.671000 0.062000 126.733000 ;
    END
    PORT
      LAYER M8 ;
        RECT 215.938000 126.671000 216.000000 126.733000 ;
    END
    PORT
      LAYER M8 ;
        RECT 0.000000 129.065000 0.062000 129.127000 ;
    END
    PORT
      LAYER M8 ;
        RECT 215.938000 129.065000 216.000000 129.127000 ;
    END
    PORT
      LAYER M8 ;
        RECT 0.000000 131.333000 0.062000 131.395000 ;
    END
    PORT
      LAYER M8 ;
        RECT 215.938000 131.333000 216.000000 131.395000 ;
    END
    PORT
      LAYER M8 ;
        RECT 0.000000 133.601000 0.062000 133.663000 ;
    END
    PORT
      LAYER M8 ;
        RECT 215.938000 133.601000 216.000000 133.663000 ;
    END
    PORT
      LAYER M8 ;
        RECT 0.000000 135.995000 0.062000 136.057000 ;
    END
    PORT
      LAYER M8 ;
        RECT 215.938000 135.995000 216.000000 136.057000 ;
    END
    PORT
      LAYER M8 ;
        RECT 0.000000 138.263000 0.062000 138.325000 ;
    END
    PORT
      LAYER M8 ;
        RECT 215.938000 138.263000 216.000000 138.325000 ;
    END
    PORT
      LAYER M8 ;
        RECT 0.000000 140.531000 0.062000 140.593000 ;
    END
    PORT
      LAYER M8 ;
        RECT 215.938000 140.531000 216.000000 140.593000 ;
    END
    PORT
      LAYER M8 ;
        RECT 0.000000 142.799000 0.062000 142.861000 ;
    END
    PORT
      LAYER M8 ;
        RECT 215.938000 142.799000 216.000000 142.861000 ;
    END
    PORT
      LAYER M8 ;
        RECT 0.000000 145.193000 0.062000 145.255000 ;
    END
    PORT
      LAYER M8 ;
        RECT 215.938000 145.193000 216.000000 145.255000 ;
    END
    PORT
      LAYER M8 ;
        RECT 0.000000 147.461000 0.062000 147.523000 ;
    END
    PORT
      LAYER M8 ;
        RECT 215.938000 147.461000 216.000000 147.523000 ;
    END
    PORT
      LAYER M8 ;
        RECT 0.000000 149.729000 0.062000 149.791000 ;
    END
    PORT
      LAYER M8 ;
        RECT 215.938000 149.729000 216.000000 149.791000 ;
    END
    PORT
      LAYER M8 ;
        RECT 0.000000 152.123000 0.062000 152.185000 ;
    END
    PORT
      LAYER M8 ;
        RECT 215.938000 152.123000 216.000000 152.185000 ;
    END
    PORT
      LAYER M8 ;
        RECT 0.000000 154.391000 0.062000 154.453000 ;
    END
    PORT
      LAYER M8 ;
        RECT 215.938000 154.391000 216.000000 154.453000 ;
    END
    PORT
      LAYER M8 ;
        RECT 0.000000 156.659000 0.062000 156.721000 ;
    END
    PORT
      LAYER M8 ;
        RECT 215.938000 156.659000 216.000000 156.721000 ;
    END
    PORT
      LAYER M8 ;
        RECT 0.000000 158.927000 0.062000 158.989000 ;
    END
    PORT
      LAYER M8 ;
        RECT 215.938000 158.927000 216.000000 158.989000 ;
    END
    PORT
      LAYER M8 ;
        RECT 0.000000 161.321000 0.062000 161.383000 ;
    END
    PORT
      LAYER M8 ;
        RECT 215.938000 161.321000 216.000000 161.383000 ;
    END
    PORT
      LAYER M8 ;
        RECT 0.000000 163.589000 0.062000 163.651000 ;
    END
    PORT
      LAYER M8 ;
        RECT 215.938000 163.589000 216.000000 163.651000 ;
    END
    PORT
      LAYER M8 ;
        RECT 0.000000 165.857000 0.062000 165.919000 ;
    END
    PORT
      LAYER M8 ;
        RECT 215.938000 165.857000 216.000000 165.919000 ;
    END
    PORT
      LAYER M8 ;
        RECT 0.000000 168.251000 0.062000 168.313000 ;
    END
    PORT
      LAYER M8 ;
        RECT 215.938000 168.251000 216.000000 168.313000 ;
    END
    PORT
      LAYER M8 ;
        RECT 0.000000 170.519000 0.062000 170.581000 ;
    END
    PORT
      LAYER M8 ;
        RECT 215.938000 170.519000 216.000000 170.581000 ;
    END
    PORT
      LAYER M8 ;
        RECT 0.000000 172.787000 0.062000 172.849000 ;
    END
    PORT
      LAYER M8 ;
        RECT 215.938000 172.787000 216.000000 172.849000 ;
    END
    PORT
      LAYER M8 ;
        RECT 0.000000 175.055000 0.062000 175.117000 ;
    END
    PORT
      LAYER M8 ;
        RECT 215.938000 175.055000 216.000000 175.117000 ;
    END
    PORT
      LAYER M8 ;
        RECT 0.000000 177.449000 0.062000 177.511000 ;
    END
    PORT
      LAYER M8 ;
        RECT 215.938000 177.449000 216.000000 177.511000 ;
    END
    PORT
      LAYER M8 ;
        RECT 0.000000 179.717000 0.062000 179.779000 ;
    END
    PORT
      LAYER M8 ;
        RECT 215.938000 179.717000 216.000000 179.779000 ;
    END
    PORT
      LAYER M9 ;
        RECT 0.117000 0.000000 0.567000 0.450000 ;
    END
    PORT
      LAYER M9 ;
        RECT 0.117000 181.566000 0.567000 182.016000 ;
    END
    PORT
      LAYER M9 ;
        RECT 2.511000 0.000000 2.961000 0.450000 ;
    END
    PORT
      LAYER M9 ;
        RECT 2.511000 181.566000 2.961000 182.016000 ;
    END
    PORT
      LAYER M9 ;
        RECT 5.031000 0.000000 5.481000 0.450000 ;
    END
    PORT
      LAYER M9 ;
        RECT 5.031000 181.566000 5.481000 182.016000 ;
    END
    PORT
      LAYER M9 ;
        RECT 7.551000 0.000000 8.001000 0.450000 ;
    END
    PORT
      LAYER M9 ;
        RECT 7.551000 181.566000 8.001000 182.016000 ;
    END
    PORT
      LAYER M9 ;
        RECT 10.071000 0.000000 10.521000 0.450000 ;
    END
    PORT
      LAYER M9 ;
        RECT 10.071000 181.566000 10.521000 182.016000 ;
    END
    PORT
      LAYER M9 ;
        RECT 12.591000 0.000000 13.041000 0.450000 ;
    END
    PORT
      LAYER M9 ;
        RECT 12.591000 181.566000 13.041000 182.016000 ;
    END
    PORT
      LAYER M9 ;
        RECT 15.111000 0.000000 15.561000 0.450000 ;
    END
    PORT
      LAYER M9 ;
        RECT 15.111000 181.566000 15.561000 182.016000 ;
    END
    PORT
      LAYER M9 ;
        RECT 17.631000 0.000000 18.081000 0.450000 ;
    END
    PORT
      LAYER M9 ;
        RECT 17.631000 181.566000 18.081000 182.016000 ;
    END
    PORT
      LAYER M9 ;
        RECT 20.151000 0.000000 20.601000 0.450000 ;
    END
    PORT
      LAYER M9 ;
        RECT 20.151000 181.566000 20.601000 182.016000 ;
    END
    PORT
      LAYER M9 ;
        RECT 22.671000 0.000000 23.121000 0.450000 ;
    END
    PORT
      LAYER M9 ;
        RECT 22.671000 181.566000 23.121000 182.016000 ;
    END
    PORT
      LAYER M9 ;
        RECT 25.191000 0.000000 25.641000 0.450000 ;
    END
    PORT
      LAYER M9 ;
        RECT 25.191000 181.566000 25.641000 182.016000 ;
    END
    PORT
      LAYER M9 ;
        RECT 27.711000 0.000000 28.161000 0.450000 ;
    END
    PORT
      LAYER M9 ;
        RECT 27.711000 181.566000 28.161000 182.016000 ;
    END
    PORT
      LAYER M9 ;
        RECT 30.231000 0.000000 30.681000 0.450000 ;
    END
    PORT
      LAYER M9 ;
        RECT 30.231000 181.566000 30.681000 182.016000 ;
    END
    PORT
      LAYER M9 ;
        RECT 32.751000 0.000000 33.201000 0.450000 ;
    END
    PORT
      LAYER M9 ;
        RECT 32.751000 181.566000 33.201000 182.016000 ;
    END
    PORT
      LAYER M9 ;
        RECT 35.271000 0.000000 35.721000 0.450000 ;
    END
    PORT
      LAYER M9 ;
        RECT 35.271000 181.566000 35.721000 182.016000 ;
    END
    PORT
      LAYER M9 ;
        RECT 37.791000 0.000000 38.241000 0.450000 ;
    END
    PORT
      LAYER M9 ;
        RECT 37.791000 181.566000 38.241000 182.016000 ;
    END
    PORT
      LAYER M9 ;
        RECT 40.311000 0.000000 40.761000 0.450000 ;
    END
    PORT
      LAYER M9 ;
        RECT 40.311000 181.566000 40.761000 182.016000 ;
    END
    PORT
      LAYER M9 ;
        RECT 42.831000 0.000000 43.281000 0.450000 ;
    END
    PORT
      LAYER M9 ;
        RECT 42.831000 181.566000 43.281000 182.016000 ;
    END
    PORT
      LAYER M9 ;
        RECT 45.351000 0.000000 45.801000 0.450000 ;
    END
    PORT
      LAYER M9 ;
        RECT 45.351000 181.566000 45.801000 182.016000 ;
    END
    PORT
      LAYER M9 ;
        RECT 47.871000 0.000000 48.321000 0.450000 ;
    END
    PORT
      LAYER M9 ;
        RECT 47.871000 181.566000 48.321000 182.016000 ;
    END
    PORT
      LAYER M9 ;
        RECT 50.391000 0.000000 50.841000 0.450000 ;
    END
    PORT
      LAYER M9 ;
        RECT 50.391000 181.566000 50.841000 182.016000 ;
    END
    PORT
      LAYER M9 ;
        RECT 52.911000 0.000000 53.361000 0.450000 ;
    END
    PORT
      LAYER M9 ;
        RECT 52.911000 181.566000 53.361000 182.016000 ;
    END
    PORT
      LAYER M9 ;
        RECT 55.431000 0.000000 55.881000 0.450000 ;
    END
    PORT
      LAYER M9 ;
        RECT 55.431000 181.566000 55.881000 182.016000 ;
    END
    PORT
      LAYER M9 ;
        RECT 57.951000 0.000000 58.401000 0.450000 ;
    END
    PORT
      LAYER M9 ;
        RECT 57.951000 181.566000 58.401000 182.016000 ;
    END
    PORT
      LAYER M9 ;
        RECT 60.471000 0.000000 60.921000 0.450000 ;
    END
    PORT
      LAYER M9 ;
        RECT 60.471000 181.566000 60.921000 182.016000 ;
    END
    PORT
      LAYER M9 ;
        RECT 62.991000 0.000000 63.441000 0.450000 ;
    END
    PORT
      LAYER M9 ;
        RECT 62.991000 181.566000 63.441000 182.016000 ;
    END
    PORT
      LAYER M9 ;
        RECT 65.511000 0.000000 65.961000 0.450000 ;
    END
    PORT
      LAYER M9 ;
        RECT 65.511000 181.566000 65.961000 182.016000 ;
    END
    PORT
      LAYER M9 ;
        RECT 68.031000 0.000000 68.481000 0.450000 ;
    END
    PORT
      LAYER M9 ;
        RECT 68.031000 181.566000 68.481000 182.016000 ;
    END
    PORT
      LAYER M9 ;
        RECT 70.551000 0.000000 71.001000 0.450000 ;
    END
    PORT
      LAYER M9 ;
        RECT 70.551000 181.566000 71.001000 182.016000 ;
    END
    PORT
      LAYER M9 ;
        RECT 73.071000 0.000000 73.521000 0.450000 ;
    END
    PORT
      LAYER M9 ;
        RECT 73.071000 181.566000 73.521000 182.016000 ;
    END
    PORT
      LAYER M9 ;
        RECT 75.591000 0.000000 76.041000 0.450000 ;
    END
    PORT
      LAYER M9 ;
        RECT 75.591000 181.566000 76.041000 182.016000 ;
    END
    PORT
      LAYER M9 ;
        RECT 78.111000 0.000000 78.561000 0.450000 ;
    END
    PORT
      LAYER M9 ;
        RECT 78.111000 181.566000 78.561000 182.016000 ;
    END
    PORT
      LAYER M9 ;
        RECT 80.631000 0.000000 81.081000 0.450000 ;
    END
    PORT
      LAYER M9 ;
        RECT 80.631000 181.566000 81.081000 182.016000 ;
    END
    PORT
      LAYER M9 ;
        RECT 83.151000 0.000000 83.601000 0.450000 ;
    END
    PORT
      LAYER M9 ;
        RECT 83.151000 181.566000 83.601000 182.016000 ;
    END
    PORT
      LAYER M9 ;
        RECT 85.671000 0.000000 86.121000 0.450000 ;
    END
    PORT
      LAYER M9 ;
        RECT 85.671000 181.566000 86.121000 182.016000 ;
    END
    PORT
      LAYER M9 ;
        RECT 88.191000 0.000000 88.641000 0.450000 ;
    END
    PORT
      LAYER M9 ;
        RECT 88.191000 181.566000 88.641000 182.016000 ;
    END
    PORT
      LAYER M9 ;
        RECT 90.711000 0.000000 91.161000 0.450000 ;
    END
    PORT
      LAYER M9 ;
        RECT 90.711000 181.566000 91.161000 182.016000 ;
    END
    PORT
      LAYER M9 ;
        RECT 93.231000 0.000000 93.681000 0.450000 ;
    END
    PORT
      LAYER M9 ;
        RECT 93.231000 181.566000 93.681000 182.016000 ;
    END
    PORT
      LAYER M9 ;
        RECT 95.751000 0.000000 96.201000 0.450000 ;
    END
    PORT
      LAYER M9 ;
        RECT 95.751000 181.566000 96.201000 182.016000 ;
    END
    PORT
      LAYER M9 ;
        RECT 98.271000 0.000000 98.721000 0.450000 ;
    END
    PORT
      LAYER M9 ;
        RECT 98.271000 181.566000 98.721000 182.016000 ;
    END
    PORT
      LAYER M9 ;
        RECT 100.791000 0.000000 101.241000 0.450000 ;
    END
    PORT
      LAYER M9 ;
        RECT 100.791000 181.566000 101.241000 182.016000 ;
    END
    PORT
      LAYER M9 ;
        RECT 103.311000 0.000000 103.761000 0.450000 ;
    END
    PORT
      LAYER M9 ;
        RECT 103.311000 181.566000 103.761000 182.016000 ;
    END
    PORT
      LAYER M9 ;
        RECT 105.831000 0.000000 106.281000 0.450000 ;
    END
    PORT
      LAYER M9 ;
        RECT 105.831000 181.566000 106.281000 182.016000 ;
    END
    PORT
      LAYER M9 ;
        RECT 108.351000 0.000000 108.801000 0.450000 ;
    END
    PORT
      LAYER M9 ;
        RECT 108.351000 181.566000 108.801000 182.016000 ;
    END
    PORT
      LAYER M9 ;
        RECT 110.871000 0.000000 111.321000 0.450000 ;
    END
    PORT
      LAYER M9 ;
        RECT 110.871000 181.566000 111.321000 182.016000 ;
    END
    PORT
      LAYER M9 ;
        RECT 113.391000 0.000000 113.841000 0.450000 ;
    END
    PORT
      LAYER M9 ;
        RECT 113.391000 181.566000 113.841000 182.016000 ;
    END
    PORT
      LAYER M9 ;
        RECT 115.911000 0.000000 116.361000 0.450000 ;
    END
    PORT
      LAYER M9 ;
        RECT 115.911000 181.566000 116.361000 182.016000 ;
    END
    PORT
      LAYER M9 ;
        RECT 118.431000 0.000000 118.881000 0.450000 ;
    END
    PORT
      LAYER M9 ;
        RECT 118.431000 181.566000 118.881000 182.016000 ;
    END
    PORT
      LAYER M9 ;
        RECT 120.951000 0.000000 121.401000 0.450000 ;
    END
    PORT
      LAYER M9 ;
        RECT 120.951000 181.566000 121.401000 182.016000 ;
    END
    PORT
      LAYER M9 ;
        RECT 123.471000 0.000000 123.921000 0.450000 ;
    END
    PORT
      LAYER M9 ;
        RECT 123.471000 181.566000 123.921000 182.016000 ;
    END
    PORT
      LAYER M9 ;
        RECT 125.991000 0.000000 126.441000 0.450000 ;
    END
    PORT
      LAYER M9 ;
        RECT 125.991000 181.566000 126.441000 182.016000 ;
    END
    PORT
      LAYER M9 ;
        RECT 128.511000 0.000000 128.961000 0.450000 ;
    END
    PORT
      LAYER M9 ;
        RECT 128.511000 181.566000 128.961000 182.016000 ;
    END
    PORT
      LAYER M9 ;
        RECT 131.031000 0.000000 131.481000 0.450000 ;
    END
    PORT
      LAYER M9 ;
        RECT 131.031000 181.566000 131.481000 182.016000 ;
    END
    PORT
      LAYER M9 ;
        RECT 133.551000 0.000000 134.001000 0.450000 ;
    END
    PORT
      LAYER M9 ;
        RECT 133.551000 181.566000 134.001000 182.016000 ;
    END
    PORT
      LAYER M9 ;
        RECT 136.071000 0.000000 136.521000 0.450000 ;
    END
    PORT
      LAYER M9 ;
        RECT 136.071000 181.566000 136.521000 182.016000 ;
    END
    PORT
      LAYER M9 ;
        RECT 138.591000 0.000000 139.041000 0.450000 ;
    END
    PORT
      LAYER M9 ;
        RECT 138.591000 181.566000 139.041000 182.016000 ;
    END
    PORT
      LAYER M9 ;
        RECT 141.111000 0.000000 141.561000 0.450000 ;
    END
    PORT
      LAYER M9 ;
        RECT 141.111000 181.566000 141.561000 182.016000 ;
    END
    PORT
      LAYER M9 ;
        RECT 143.631000 0.000000 144.081000 0.450000 ;
    END
    PORT
      LAYER M9 ;
        RECT 143.631000 181.566000 144.081000 182.016000 ;
    END
    PORT
      LAYER M9 ;
        RECT 146.151000 0.000000 146.601000 0.450000 ;
    END
    PORT
      LAYER M9 ;
        RECT 146.151000 181.566000 146.601000 182.016000 ;
    END
    PORT
      LAYER M9 ;
        RECT 148.671000 0.000000 149.121000 0.450000 ;
    END
    PORT
      LAYER M9 ;
        RECT 148.671000 181.566000 149.121000 182.016000 ;
    END
    PORT
      LAYER M9 ;
        RECT 151.191000 0.000000 151.641000 0.450000 ;
    END
    PORT
      LAYER M9 ;
        RECT 151.191000 181.566000 151.641000 182.016000 ;
    END
    PORT
      LAYER M9 ;
        RECT 153.711000 0.000000 154.161000 0.450000 ;
    END
    PORT
      LAYER M9 ;
        RECT 153.711000 181.566000 154.161000 182.016000 ;
    END
    PORT
      LAYER M9 ;
        RECT 156.231000 0.000000 156.681000 0.450000 ;
    END
    PORT
      LAYER M9 ;
        RECT 156.231000 181.566000 156.681000 182.016000 ;
    END
    PORT
      LAYER M9 ;
        RECT 158.751000 0.000000 159.201000 0.450000 ;
    END
    PORT
      LAYER M9 ;
        RECT 158.751000 181.566000 159.201000 182.016000 ;
    END
    PORT
      LAYER M9 ;
        RECT 161.271000 0.000000 161.721000 0.450000 ;
    END
    PORT
      LAYER M9 ;
        RECT 161.271000 181.566000 161.721000 182.016000 ;
    END
    PORT
      LAYER M9 ;
        RECT 163.791000 0.000000 164.241000 0.450000 ;
    END
    PORT
      LAYER M9 ;
        RECT 163.791000 181.566000 164.241000 182.016000 ;
    END
    PORT
      LAYER M9 ;
        RECT 166.311000 0.000000 166.761000 0.450000 ;
    END
    PORT
      LAYER M9 ;
        RECT 166.311000 181.566000 166.761000 182.016000 ;
    END
    PORT
      LAYER M9 ;
        RECT 168.831000 0.000000 169.281000 0.450000 ;
    END
    PORT
      LAYER M9 ;
        RECT 168.831000 181.566000 169.281000 182.016000 ;
    END
    PORT
      LAYER M9 ;
        RECT 171.351000 0.000000 171.801000 0.450000 ;
    END
    PORT
      LAYER M9 ;
        RECT 171.351000 181.566000 171.801000 182.016000 ;
    END
    PORT
      LAYER M9 ;
        RECT 173.871000 0.000000 174.321000 0.450000 ;
    END
    PORT
      LAYER M9 ;
        RECT 173.871000 181.566000 174.321000 182.016000 ;
    END
    PORT
      LAYER M9 ;
        RECT 176.391000 0.000000 176.841000 0.450000 ;
    END
    PORT
      LAYER M9 ;
        RECT 176.391000 181.566000 176.841000 182.016000 ;
    END
    PORT
      LAYER M9 ;
        RECT 178.911000 0.000000 179.361000 0.450000 ;
    END
    PORT
      LAYER M9 ;
        RECT 178.911000 181.566000 179.361000 182.016000 ;
    END
    PORT
      LAYER M9 ;
        RECT 181.431000 0.000000 181.881000 0.450000 ;
    END
    PORT
      LAYER M9 ;
        RECT 181.431000 181.566000 181.881000 182.016000 ;
    END
    PORT
      LAYER M9 ;
        RECT 183.951000 0.000000 184.401000 0.450000 ;
    END
    PORT
      LAYER M9 ;
        RECT 183.951000 181.566000 184.401000 182.016000 ;
    END
    PORT
      LAYER M9 ;
        RECT 186.471000 0.000000 186.921000 0.450000 ;
    END
    PORT
      LAYER M9 ;
        RECT 186.471000 181.566000 186.921000 182.016000 ;
    END
    PORT
      LAYER M9 ;
        RECT 188.991000 0.000000 189.441000 0.450000 ;
    END
    PORT
      LAYER M9 ;
        RECT 188.991000 181.566000 189.441000 182.016000 ;
    END
    PORT
      LAYER M9 ;
        RECT 191.511000 0.000000 191.961000 0.450000 ;
    END
    PORT
      LAYER M9 ;
        RECT 191.511000 181.566000 191.961000 182.016000 ;
    END
    PORT
      LAYER M9 ;
        RECT 194.031000 0.000000 194.481000 0.450000 ;
    END
    PORT
      LAYER M9 ;
        RECT 194.031000 181.566000 194.481000 182.016000 ;
    END
    PORT
      LAYER M9 ;
        RECT 196.551000 0.000000 197.001000 0.450000 ;
    END
    PORT
      LAYER M9 ;
        RECT 196.551000 181.566000 197.001000 182.016000 ;
    END
    PORT
      LAYER M9 ;
        RECT 199.071000 0.000000 199.521000 0.450000 ;
    END
    PORT
      LAYER M9 ;
        RECT 199.071000 181.566000 199.521000 182.016000 ;
    END
    PORT
      LAYER M9 ;
        RECT 201.591000 0.000000 202.041000 0.450000 ;
    END
    PORT
      LAYER M9 ;
        RECT 201.591000 181.566000 202.041000 182.016000 ;
    END
    PORT
      LAYER M9 ;
        RECT 204.111000 0.000000 204.561000 0.450000 ;
    END
    PORT
      LAYER M9 ;
        RECT 204.111000 181.566000 204.561000 182.016000 ;
    END
    PORT
      LAYER M9 ;
        RECT 206.631000 0.000000 207.081000 0.450000 ;
    END
    PORT
      LAYER M9 ;
        RECT 206.631000 181.566000 207.081000 182.016000 ;
    END
    PORT
      LAYER M9 ;
        RECT 209.151000 0.000000 209.601000 0.450000 ;
    END
    PORT
      LAYER M9 ;
        RECT 209.151000 181.566000 209.601000 182.016000 ;
    END
    PORT
      LAYER M9 ;
        RECT 211.671000 0.000000 212.121000 0.450000 ;
    END
    PORT
      LAYER M9 ;
        RECT 211.671000 181.566000 212.121000 182.016000 ;
    END
    PORT
      LAYER M9 ;
        RECT 214.191000 0.000000 214.641000 0.450000 ;
    END
    PORT
      LAYER M9 ;
        RECT 214.191000 181.566000 214.641000 182.016000 ;
    END
    PORT
      LAYER M10 ;
        RECT 0.000000 0.558000 2.700000 3.258000 ;
    END
    PORT
      LAYER M10 ;
        RECT 213.300000 0.558000 216.000000 3.258000 ;
    END
    PORT
      LAYER M10 ;
        RECT 0.000000 9.558000 2.700000 12.258000 ;
    END
    PORT
      LAYER M10 ;
        RECT 213.300000 9.558000 216.000000 12.258000 ;
    END
    PORT
      LAYER M10 ;
        RECT 0.000000 18.558000 2.700000 21.258000 ;
    END
    PORT
      LAYER M10 ;
        RECT 213.300000 18.558000 216.000000 21.258000 ;
    END
    PORT
      LAYER M10 ;
        RECT 0.000000 27.558000 2.700000 30.258000 ;
    END
    PORT
      LAYER M10 ;
        RECT 213.300000 27.558000 216.000000 30.258000 ;
    END
    PORT
      LAYER M10 ;
        RECT 0.000000 36.558000 2.700000 39.258000 ;
    END
    PORT
      LAYER M10 ;
        RECT 213.300000 36.558000 216.000000 39.258000 ;
    END
    PORT
      LAYER M10 ;
        RECT 0.000000 46.458000 2.700000 49.158000 ;
    END
    PORT
      LAYER M10 ;
        RECT 213.300000 46.458000 216.000000 49.158000 ;
    END
    PORT
      LAYER M10 ;
        RECT 0.000000 55.458000 2.700000 58.158000 ;
    END
    PORT
      LAYER M10 ;
        RECT 213.300000 55.458000 216.000000 58.158000 ;
    END
    PORT
      LAYER M10 ;
        RECT 0.000000 64.458000 2.700000 67.158000 ;
    END
    PORT
      LAYER M10 ;
        RECT 213.300000 64.458000 216.000000 67.158000 ;
    END
    PORT
      LAYER M10 ;
        RECT 0.000000 73.458000 2.700000 76.158000 ;
    END
    PORT
      LAYER M10 ;
        RECT 213.300000 73.458000 216.000000 76.158000 ;
    END
    PORT
      LAYER M10 ;
        RECT 0.000000 83.358000 2.700000 86.058000 ;
    END
    PORT
      LAYER M10 ;
        RECT 213.300000 83.358000 216.000000 86.058000 ;
    END
    PORT
      LAYER M10 ;
        RECT 0.000000 92.358000 2.700000 95.058000 ;
    END
    PORT
      LAYER M10 ;
        RECT 213.300000 92.358000 216.000000 95.058000 ;
    END
    PORT
      LAYER M10 ;
        RECT 0.000000 101.358000 2.700000 104.058000 ;
    END
    PORT
      LAYER M10 ;
        RECT 213.300000 101.358000 216.000000 104.058000 ;
    END
    PORT
      LAYER M10 ;
        RECT 0.000000 110.358000 2.700000 113.058000 ;
    END
    PORT
      LAYER M10 ;
        RECT 213.300000 110.358000 216.000000 113.058000 ;
    END
    PORT
      LAYER M10 ;
        RECT 0.000000 119.358000 2.700000 122.058000 ;
    END
    PORT
      LAYER M10 ;
        RECT 213.300000 119.358000 216.000000 122.058000 ;
    END
    PORT
      LAYER M10 ;
        RECT 0.000000 129.258000 2.700000 131.958000 ;
    END
    PORT
      LAYER M10 ;
        RECT 213.300000 129.258000 216.000000 131.958000 ;
    END
    PORT
      LAYER M10 ;
        RECT 0.000000 138.258000 2.700000 140.958000 ;
    END
    PORT
      LAYER M10 ;
        RECT 213.300000 138.258000 216.000000 140.958000 ;
    END
    PORT
      LAYER M10 ;
        RECT 0.000000 147.258000 2.700000 149.958000 ;
    END
    PORT
      LAYER M10 ;
        RECT 213.300000 147.258000 216.000000 149.958000 ;
    END
    PORT
      LAYER M10 ;
        RECT 0.000000 156.258000 2.700000 158.958000 ;
    END
    PORT
      LAYER M10 ;
        RECT 213.300000 156.258000 216.000000 158.958000 ;
    END
    PORT
      LAYER M10 ;
        RECT 0.000000 166.158000 2.700000 168.858000 ;
    END
    PORT
      LAYER M10 ;
        RECT 213.300000 166.158000 216.000000 168.858000 ;
    END
    PORT
      LAYER M10 ;
        RECT 0.000000 175.158000 2.700000 177.858000 ;
    END
    PORT
      LAYER M10 ;
        RECT 213.300000 175.158000 216.000000 177.858000 ;
    END

# P/G power stripe data as pin
    PORT
      LAYER M8 ;
        RECT 0.000000 2.309000 216.000000 2.371000 ;
        RECT 0.000000 0.041000 216.000000 0.103000 ;
        RECT 0.000000 4.577000 216.000000 4.639000 ;
        RECT 0.000000 9.239000 216.000000 9.301000 ;
        RECT 0.000000 6.971000 216.000000 7.033000 ;
        RECT 0.000000 16.169000 216.000000 16.231000 ;
        RECT 0.000000 13.775000 216.000000 13.837000 ;
        RECT 0.000000 11.507000 216.000000 11.569000 ;
        RECT 0.000000 20.705000 216.000000 20.767000 ;
        RECT 0.000000 18.437000 216.000000 18.499000 ;
        RECT 0.000000 23.099000 216.000000 23.161000 ;
        RECT 0.000000 29.903000 216.000000 29.965000 ;
        RECT 0.000000 27.635000 216.000000 27.697000 ;
        RECT 0.000000 25.367000 216.000000 25.429000 ;
        RECT 0.000000 36.833000 216.000000 36.895000 ;
        RECT 0.000000 34.565000 216.000000 34.627000 ;
        RECT 0.000000 32.297000 216.000000 32.359000 ;
        RECT 0.000000 41.495000 216.000000 41.557000 ;
        RECT 0.000000 39.227000 216.000000 39.289000 ;
        RECT 0.000000 46.031000 216.000000 46.093000 ;
        RECT 0.000000 43.763000 216.000000 43.825000 ;
        RECT 0.000000 48.425000 216.000000 48.487000 ;
        RECT 0.000000 55.355000 216.000000 55.417000 ;
        RECT 0.000000 52.961000 216.000000 53.023000 ;
        RECT 0.000000 50.693000 216.000000 50.755000 ;
        RECT 0.000000 62.159000 216.000000 62.221000 ;
        RECT 0.000000 59.891000 216.000000 59.953000 ;
        RECT 0.000000 57.623000 216.000000 57.685000 ;
        RECT 0.000000 69.089000 216.000000 69.151000 ;
        RECT 0.000000 66.821000 216.000000 66.883000 ;
        RECT 0.000000 64.553000 216.000000 64.615000 ;
        RECT 0.000000 76.019000 216.000000 76.081000 ;
        RECT 0.000000 73.751000 216.000000 73.813000 ;
        RECT 0.000000 71.483000 216.000000 71.545000 ;
        RECT 0.000000 82.949000 216.000000 83.011000 ;
        RECT 0.000000 80.681000 216.000000 80.743000 ;
        RECT 0.000000 78.287000 216.000000 78.349000 ;
        RECT 0.000000 85.217000 216.000000 85.279000 ;
        RECT 0.000000 89.879000 216.000000 89.941000 ;
        RECT 0.000000 87.611000 216.000000 87.673000 ;
        RECT 0.000000 96.809000 216.000000 96.871000 ;
        RECT 0.000000 94.415000 216.000000 94.477000 ;
        RECT 0.000000 92.147000 216.000000 92.209000 ;
        RECT 0.000000 101.345000 216.000000 101.407000 ;
        RECT 0.000000 99.077000 216.000000 99.139000 ;
        RECT 0.000000 103.739000 216.000000 103.801000 ;
        RECT 0.000000 110.543000 216.000000 110.605000 ;
        RECT 0.000000 108.275000 216.000000 108.337000 ;
        RECT 0.000000 106.007000 216.000000 106.069000 ;
        RECT 0.000000 117.473000 216.000000 117.535000 ;
        RECT 0.000000 115.205000 216.000000 115.267000 ;
        RECT 0.000000 112.937000 216.000000 112.999000 ;
        RECT 0.000000 124.403000 216.000000 124.465000 ;
        RECT 0.000000 122.135000 216.000000 122.197000 ;
        RECT 0.000000 119.867000 216.000000 119.929000 ;
        RECT 0.000000 126.671000 216.000000 126.733000 ;
        RECT 0.000000 131.333000 216.000000 131.395000 ;
        RECT 0.000000 129.065000 216.000000 129.127000 ;
        RECT 0.000000 135.995000 216.000000 136.057000 ;
        RECT 0.000000 133.601000 216.000000 133.663000 ;
        RECT 0.000000 142.799000 216.000000 142.861000 ;
        RECT 0.000000 140.531000 216.000000 140.593000 ;
        RECT 0.000000 138.263000 216.000000 138.325000 ;
        RECT 0.000000 149.729000 216.000000 149.791000 ;
        RECT 0.000000 147.461000 216.000000 147.523000 ;
        RECT 0.000000 145.193000 216.000000 145.255000 ;
        RECT 0.000000 156.659000 216.000000 156.721000 ;
        RECT 0.000000 154.391000 216.000000 154.453000 ;
        RECT 0.000000 152.123000 216.000000 152.185000 ;
        RECT 0.000000 163.589000 216.000000 163.651000 ;
        RECT 0.000000 161.321000 216.000000 161.383000 ;
        RECT 0.000000 158.927000 216.000000 158.989000 ;
        RECT 0.000000 165.857000 216.000000 165.919000 ;
        RECT 0.000000 170.519000 216.000000 170.581000 ;
        RECT 0.000000 168.251000 216.000000 168.313000 ;
        RECT 0.000000 179.717000 216.000000 179.779000 ;
        RECT 0.000000 177.449000 216.000000 177.511000 ;
        RECT 0.000000 175.055000 216.000000 175.117000 ;
        RECT 0.000000 172.787000 216.000000 172.849000 ;
    END
# end of P/G power stripe data as pin

  END VDD
  OBS
    LAYER M1 ;
      RECT 0.000000 0.000000 216.000000 182.016000 ;
    LAYER M2 ;
      RECT 0.000000 0.000000 216.000000 182.016000 ;
    LAYER M3 ;
      RECT 215.559000 181.946000 216.000000 182.016000 ;
      RECT 214.279000 181.946000 215.457000 182.016000 ;
      RECT 212.999000 181.946000 214.177000 182.016000 ;
      RECT 211.719000 181.946000 212.897000 182.016000 ;
      RECT 210.503000 181.946000 211.617000 182.016000 ;
      RECT 209.223000 181.946000 210.401000 182.016000 ;
      RECT 207.943000 181.946000 209.121000 182.016000 ;
      RECT 206.727000 181.946000 207.841000 182.016000 ;
      RECT 205.447000 181.946000 206.625000 182.016000 ;
      RECT 204.167000 181.946000 205.345000 182.016000 ;
      RECT 202.951000 181.946000 204.065000 182.016000 ;
      RECT 201.671000 181.946000 202.849000 182.016000 ;
      RECT 200.391000 181.946000 201.569000 182.016000 ;
      RECT 199.175000 181.946000 200.289000 182.016000 ;
      RECT 197.895000 181.946000 199.073000 182.016000 ;
      RECT 196.615000 181.946000 197.793000 182.016000 ;
      RECT 195.399000 181.946000 196.513000 182.016000 ;
      RECT 194.119000 181.946000 195.297000 182.016000 ;
      RECT 192.839000 181.946000 194.017000 182.016000 ;
      RECT 191.559000 181.946000 192.737000 182.016000 ;
      RECT 190.343000 181.946000 191.457000 182.016000 ;
      RECT 189.063000 181.946000 190.241000 182.016000 ;
      RECT 187.783000 181.946000 188.961000 182.016000 ;
      RECT 186.567000 181.946000 187.681000 182.016000 ;
      RECT 185.287000 181.946000 186.465000 182.016000 ;
      RECT 184.007000 181.946000 185.185000 182.016000 ;
      RECT 182.791000 181.946000 183.905000 182.016000 ;
      RECT 181.511000 181.946000 182.689000 182.016000 ;
      RECT 180.231000 181.946000 181.409000 182.016000 ;
      RECT 179.015000 181.946000 180.129000 182.016000 ;
      RECT 177.735000 181.946000 178.913000 182.016000 ;
      RECT 176.455000 181.946000 177.633000 182.016000 ;
      RECT 175.239000 181.946000 176.353000 182.016000 ;
      RECT 173.959000 181.946000 175.137000 182.016000 ;
      RECT 172.679000 181.946000 173.857000 182.016000 ;
      RECT 171.399000 181.946000 172.577000 182.016000 ;
      RECT 170.183000 181.946000 171.297000 182.016000 ;
      RECT 168.903000 181.946000 170.081000 182.016000 ;
      RECT 167.623000 181.946000 168.801000 182.016000 ;
      RECT 166.407000 181.946000 167.521000 182.016000 ;
      RECT 165.127000 181.946000 166.305000 182.016000 ;
      RECT 163.847000 181.946000 165.025000 182.016000 ;
      RECT 162.631000 181.946000 163.745000 182.016000 ;
      RECT 161.351000 181.946000 162.529000 182.016000 ;
      RECT 160.071000 181.946000 161.249000 182.016000 ;
      RECT 158.855000 181.946000 159.969000 182.016000 ;
      RECT 157.575000 181.946000 158.753000 182.016000 ;
      RECT 156.295000 181.946000 157.473000 182.016000 ;
      RECT 155.079000 181.946000 156.193000 182.016000 ;
      RECT 153.799000 181.946000 154.977000 182.016000 ;
      RECT 152.519000 181.946000 153.697000 182.016000 ;
      RECT 151.239000 181.946000 152.417000 182.016000 ;
      RECT 150.023000 181.946000 151.137000 182.016000 ;
      RECT 148.743000 181.946000 149.921000 182.016000 ;
      RECT 147.463000 181.946000 148.641000 182.016000 ;
      RECT 146.247000 181.946000 147.361000 182.016000 ;
      RECT 144.967000 181.946000 146.145000 182.016000 ;
      RECT 143.687000 181.946000 144.865000 182.016000 ;
      RECT 142.471000 181.946000 143.585000 182.016000 ;
      RECT 141.191000 181.946000 142.369000 182.016000 ;
      RECT 139.911000 181.946000 141.089000 182.016000 ;
      RECT 138.695000 181.946000 139.809000 182.016000 ;
      RECT 137.415000 181.946000 138.593000 182.016000 ;
      RECT 136.135000 181.946000 137.313000 182.016000 ;
      RECT 134.919000 181.946000 136.033000 182.016000 ;
      RECT 133.639000 181.946000 134.817000 182.016000 ;
      RECT 132.359000 181.946000 133.537000 182.016000 ;
      RECT 131.079000 181.946000 132.257000 182.016000 ;
      RECT 129.863000 181.946000 130.977000 182.016000 ;
      RECT 128.583000 181.946000 129.761000 182.016000 ;
      RECT 127.303000 181.946000 128.481000 182.016000 ;
      RECT 126.087000 181.946000 127.201000 182.016000 ;
      RECT 124.807000 181.946000 125.985000 182.016000 ;
      RECT 123.527000 181.946000 124.705000 182.016000 ;
      RECT 122.311000 181.946000 123.425000 182.016000 ;
      RECT 121.031000 181.946000 122.209000 182.016000 ;
      RECT 119.751000 181.946000 120.929000 182.016000 ;
      RECT 118.535000 181.946000 119.649000 182.016000 ;
      RECT 117.255000 181.946000 118.433000 182.016000 ;
      RECT 115.975000 181.946000 117.153000 182.016000 ;
      RECT 114.759000 181.946000 115.873000 182.016000 ;
      RECT 113.479000 181.946000 114.657000 182.016000 ;
      RECT 112.199000 181.946000 113.377000 182.016000 ;
      RECT 110.919000 181.946000 112.097000 182.016000 ;
      RECT 109.703000 181.946000 110.817000 182.016000 ;
      RECT 108.423000 181.946000 109.601000 182.016000 ;
      RECT 107.143000 181.946000 108.321000 182.016000 ;
      RECT 105.927000 181.946000 107.041000 182.016000 ;
      RECT 104.647000 181.946000 105.825000 182.016000 ;
      RECT 103.367000 181.946000 104.545000 182.016000 ;
      RECT 102.151000 181.946000 103.265000 182.016000 ;
      RECT 100.871000 181.946000 102.049000 182.016000 ;
      RECT 99.591000 181.946000 100.769000 182.016000 ;
      RECT 98.375000 181.946000 99.489000 182.016000 ;
      RECT 97.095000 181.946000 98.273000 182.016000 ;
      RECT 95.815000 181.946000 96.993000 182.016000 ;
      RECT 94.599000 181.946000 95.713000 182.016000 ;
      RECT 93.319000 181.946000 94.497000 182.016000 ;
      RECT 92.039000 181.946000 93.217000 182.016000 ;
      RECT 90.759000 181.946000 91.937000 182.016000 ;
      RECT 89.543000 181.946000 90.657000 182.016000 ;
      RECT 88.263000 181.946000 89.441000 182.016000 ;
      RECT 86.983000 181.946000 88.161000 182.016000 ;
      RECT 85.767000 181.946000 86.881000 182.016000 ;
      RECT 84.487000 181.946000 85.665000 182.016000 ;
      RECT 83.207000 181.946000 84.385000 182.016000 ;
      RECT 81.991000 181.946000 83.105000 182.016000 ;
      RECT 80.711000 181.946000 81.889000 182.016000 ;
      RECT 79.431000 181.946000 80.609000 182.016000 ;
      RECT 78.215000 181.946000 79.329000 182.016000 ;
      RECT 76.935000 181.946000 78.113000 182.016000 ;
      RECT 75.655000 181.946000 76.833000 182.016000 ;
      RECT 74.439000 181.946000 75.553000 182.016000 ;
      RECT 73.159000 181.946000 74.337000 182.016000 ;
      RECT 71.879000 181.946000 73.057000 182.016000 ;
      RECT 70.599000 181.946000 71.777000 182.016000 ;
      RECT 69.383000 181.946000 70.497000 182.016000 ;
      RECT 68.103000 181.946000 69.281000 182.016000 ;
      RECT 66.823000 181.946000 68.001000 182.016000 ;
      RECT 65.607000 181.946000 66.721000 182.016000 ;
      RECT 64.327000 181.946000 65.505000 182.016000 ;
      RECT 63.047000 181.946000 64.225000 182.016000 ;
      RECT 61.831000 181.946000 62.945000 182.016000 ;
      RECT 60.551000 181.946000 61.729000 182.016000 ;
      RECT 59.271000 181.946000 60.449000 182.016000 ;
      RECT 58.055000 181.946000 59.169000 182.016000 ;
      RECT 56.775000 181.946000 57.953000 182.016000 ;
      RECT 55.495000 181.946000 56.673000 182.016000 ;
      RECT 54.279000 181.946000 55.393000 182.016000 ;
      RECT 52.999000 181.946000 54.177000 182.016000 ;
      RECT 51.719000 181.946000 52.897000 182.016000 ;
      RECT 50.439000 181.946000 51.617000 182.016000 ;
      RECT 49.223000 181.946000 50.337000 182.016000 ;
      RECT 47.943000 181.946000 49.121000 182.016000 ;
      RECT 46.663000 181.946000 47.841000 182.016000 ;
      RECT 45.447000 181.946000 46.561000 182.016000 ;
      RECT 44.167000 181.946000 45.345000 182.016000 ;
      RECT 42.887000 181.946000 44.065000 182.016000 ;
      RECT 41.671000 181.946000 42.785000 182.016000 ;
      RECT 40.391000 181.946000 41.569000 182.016000 ;
      RECT 39.111000 181.946000 40.289000 182.016000 ;
      RECT 37.895000 181.946000 39.009000 182.016000 ;
      RECT 36.615000 181.946000 37.793000 182.016000 ;
      RECT 35.335000 181.946000 36.513000 182.016000 ;
      RECT 34.119000 181.946000 35.233000 182.016000 ;
      RECT 32.839000 181.946000 34.017000 182.016000 ;
      RECT 31.559000 181.946000 32.737000 182.016000 ;
      RECT 30.279000 181.946000 31.457000 182.016000 ;
      RECT 29.063000 181.946000 30.177000 182.016000 ;
      RECT 27.783000 181.946000 28.961000 182.016000 ;
      RECT 26.503000 181.946000 27.681000 182.016000 ;
      RECT 25.287000 181.946000 26.401000 182.016000 ;
      RECT 24.007000 181.946000 25.185000 182.016000 ;
      RECT 22.727000 181.946000 23.905000 182.016000 ;
      RECT 21.511000 181.946000 22.625000 182.016000 ;
      RECT 20.231000 181.946000 21.409000 182.016000 ;
      RECT 18.951000 181.946000 20.129000 182.016000 ;
      RECT 17.735000 181.946000 18.849000 182.016000 ;
      RECT 16.455000 181.946000 17.633000 182.016000 ;
      RECT 15.175000 181.946000 16.353000 182.016000 ;
      RECT 13.959000 181.946000 15.073000 182.016000 ;
      RECT 12.679000 181.946000 13.857000 182.016000 ;
      RECT 11.399000 181.946000 12.577000 182.016000 ;
      RECT 10.119000 181.946000 11.297000 182.016000 ;
      RECT 8.903000 181.946000 10.017000 182.016000 ;
      RECT 7.623000 181.946000 8.801000 182.016000 ;
      RECT 6.343000 181.946000 7.521000 182.016000 ;
      RECT 5.127000 181.946000 6.241000 182.016000 ;
      RECT 3.847000 181.946000 5.025000 182.016000 ;
      RECT 2.567000 181.946000 3.745000 182.016000 ;
      RECT 1.351000 181.946000 2.465000 182.016000 ;
      RECT 0.135000 181.946000 1.249000 182.016000 ;
      RECT 0.000000 181.946000 0.033000 182.016000 ;
      RECT 0.000000 0.070000 216.000000 181.946000 ;
      RECT 215.559000 0.000000 216.000000 0.070000 ;
      RECT 214.279000 0.000000 215.457000 0.070000 ;
      RECT 212.999000 0.000000 214.177000 0.070000 ;
      RECT 211.719000 0.000000 212.897000 0.070000 ;
      RECT 210.503000 0.000000 211.617000 0.070000 ;
      RECT 209.223000 0.000000 210.401000 0.070000 ;
      RECT 207.943000 0.000000 209.121000 0.070000 ;
      RECT 206.727000 0.000000 207.841000 0.070000 ;
      RECT 205.447000 0.000000 206.625000 0.070000 ;
      RECT 204.167000 0.000000 205.345000 0.070000 ;
      RECT 202.951000 0.000000 204.065000 0.070000 ;
      RECT 201.671000 0.000000 202.849000 0.070000 ;
      RECT 200.391000 0.000000 201.569000 0.070000 ;
      RECT 199.175000 0.000000 200.289000 0.070000 ;
      RECT 197.895000 0.000000 199.073000 0.070000 ;
      RECT 196.615000 0.000000 197.793000 0.070000 ;
      RECT 195.399000 0.000000 196.513000 0.070000 ;
      RECT 194.119000 0.000000 195.297000 0.070000 ;
      RECT 192.839000 0.000000 194.017000 0.070000 ;
      RECT 191.559000 0.000000 192.737000 0.070000 ;
      RECT 190.343000 0.000000 191.457000 0.070000 ;
      RECT 189.063000 0.000000 190.241000 0.070000 ;
      RECT 187.783000 0.000000 188.961000 0.070000 ;
      RECT 186.567000 0.000000 187.681000 0.070000 ;
      RECT 185.287000 0.000000 186.465000 0.070000 ;
      RECT 184.007000 0.000000 185.185000 0.070000 ;
      RECT 182.791000 0.000000 183.905000 0.070000 ;
      RECT 181.511000 0.000000 182.689000 0.070000 ;
      RECT 180.231000 0.000000 181.409000 0.070000 ;
      RECT 179.015000 0.000000 180.129000 0.070000 ;
      RECT 177.735000 0.000000 178.913000 0.070000 ;
      RECT 176.455000 0.000000 177.633000 0.070000 ;
      RECT 175.239000 0.000000 176.353000 0.070000 ;
      RECT 173.959000 0.000000 175.137000 0.070000 ;
      RECT 172.679000 0.000000 173.857000 0.070000 ;
      RECT 171.399000 0.000000 172.577000 0.070000 ;
      RECT 170.183000 0.000000 171.297000 0.070000 ;
      RECT 168.903000 0.000000 170.081000 0.070000 ;
      RECT 167.623000 0.000000 168.801000 0.070000 ;
      RECT 166.407000 0.000000 167.521000 0.070000 ;
      RECT 165.127000 0.000000 166.305000 0.070000 ;
      RECT 163.847000 0.000000 165.025000 0.070000 ;
      RECT 162.631000 0.000000 163.745000 0.070000 ;
      RECT 161.351000 0.000000 162.529000 0.070000 ;
      RECT 160.071000 0.000000 161.249000 0.070000 ;
      RECT 158.855000 0.000000 159.969000 0.070000 ;
      RECT 157.575000 0.000000 158.753000 0.070000 ;
      RECT 156.295000 0.000000 157.473000 0.070000 ;
      RECT 155.079000 0.000000 156.193000 0.070000 ;
      RECT 153.799000 0.000000 154.977000 0.070000 ;
      RECT 152.519000 0.000000 153.697000 0.070000 ;
      RECT 151.239000 0.000000 152.417000 0.070000 ;
      RECT 150.023000 0.000000 151.137000 0.070000 ;
      RECT 148.743000 0.000000 149.921000 0.070000 ;
      RECT 147.463000 0.000000 148.641000 0.070000 ;
      RECT 146.247000 0.000000 147.361000 0.070000 ;
      RECT 144.967000 0.000000 146.145000 0.070000 ;
      RECT 143.687000 0.000000 144.865000 0.070000 ;
      RECT 142.471000 0.000000 143.585000 0.070000 ;
      RECT 141.191000 0.000000 142.369000 0.070000 ;
      RECT 139.911000 0.000000 141.089000 0.070000 ;
      RECT 138.695000 0.000000 139.809000 0.070000 ;
      RECT 137.415000 0.000000 138.593000 0.070000 ;
      RECT 136.135000 0.000000 137.313000 0.070000 ;
      RECT 134.919000 0.000000 136.033000 0.070000 ;
      RECT 133.639000 0.000000 134.817000 0.070000 ;
      RECT 132.359000 0.000000 133.537000 0.070000 ;
      RECT 131.079000 0.000000 132.257000 0.070000 ;
      RECT 129.863000 0.000000 130.977000 0.070000 ;
      RECT 128.583000 0.000000 129.761000 0.070000 ;
      RECT 127.303000 0.000000 128.481000 0.070000 ;
      RECT 126.087000 0.000000 127.201000 0.070000 ;
      RECT 124.807000 0.000000 125.985000 0.070000 ;
      RECT 123.527000 0.000000 124.705000 0.070000 ;
      RECT 122.311000 0.000000 123.425000 0.070000 ;
      RECT 121.031000 0.000000 122.209000 0.070000 ;
      RECT 119.751000 0.000000 120.929000 0.070000 ;
      RECT 118.535000 0.000000 119.649000 0.070000 ;
      RECT 117.255000 0.000000 118.433000 0.070000 ;
      RECT 115.975000 0.000000 117.153000 0.070000 ;
      RECT 114.759000 0.000000 115.873000 0.070000 ;
      RECT 113.479000 0.000000 114.657000 0.070000 ;
      RECT 112.199000 0.000000 113.377000 0.070000 ;
      RECT 110.919000 0.000000 112.097000 0.070000 ;
      RECT 109.703000 0.000000 110.817000 0.070000 ;
      RECT 108.423000 0.000000 109.601000 0.070000 ;
      RECT 107.143000 0.000000 108.321000 0.070000 ;
      RECT 105.927000 0.000000 107.041000 0.070000 ;
      RECT 104.647000 0.000000 105.825000 0.070000 ;
      RECT 103.367000 0.000000 104.545000 0.070000 ;
      RECT 102.151000 0.000000 103.265000 0.070000 ;
      RECT 100.871000 0.000000 102.049000 0.070000 ;
      RECT 99.591000 0.000000 100.769000 0.070000 ;
      RECT 98.375000 0.000000 99.489000 0.070000 ;
      RECT 97.095000 0.000000 98.273000 0.070000 ;
      RECT 95.815000 0.000000 96.993000 0.070000 ;
      RECT 94.599000 0.000000 95.713000 0.070000 ;
      RECT 93.319000 0.000000 94.497000 0.070000 ;
      RECT 92.039000 0.000000 93.217000 0.070000 ;
      RECT 90.759000 0.000000 91.937000 0.070000 ;
      RECT 89.543000 0.000000 90.657000 0.070000 ;
      RECT 88.263000 0.000000 89.441000 0.070000 ;
      RECT 86.983000 0.000000 88.161000 0.070000 ;
      RECT 85.767000 0.000000 86.881000 0.070000 ;
      RECT 84.487000 0.000000 85.665000 0.070000 ;
      RECT 83.207000 0.000000 84.385000 0.070000 ;
      RECT 81.991000 0.000000 83.105000 0.070000 ;
      RECT 80.711000 0.000000 81.889000 0.070000 ;
      RECT 79.431000 0.000000 80.609000 0.070000 ;
      RECT 78.215000 0.000000 79.329000 0.070000 ;
      RECT 76.935000 0.000000 78.113000 0.070000 ;
      RECT 75.655000 0.000000 76.833000 0.070000 ;
      RECT 74.439000 0.000000 75.553000 0.070000 ;
      RECT 73.159000 0.000000 74.337000 0.070000 ;
      RECT 71.879000 0.000000 73.057000 0.070000 ;
      RECT 70.599000 0.000000 71.777000 0.070000 ;
      RECT 69.383000 0.000000 70.497000 0.070000 ;
      RECT 68.103000 0.000000 69.281000 0.070000 ;
      RECT 66.823000 0.000000 68.001000 0.070000 ;
      RECT 65.607000 0.000000 66.721000 0.070000 ;
      RECT 64.327000 0.000000 65.505000 0.070000 ;
      RECT 63.047000 0.000000 64.225000 0.070000 ;
      RECT 61.831000 0.000000 62.945000 0.070000 ;
      RECT 60.551000 0.000000 61.729000 0.070000 ;
      RECT 59.271000 0.000000 60.449000 0.070000 ;
      RECT 58.055000 0.000000 59.169000 0.070000 ;
      RECT 56.775000 0.000000 57.953000 0.070000 ;
      RECT 55.495000 0.000000 56.673000 0.070000 ;
      RECT 54.279000 0.000000 55.393000 0.070000 ;
      RECT 52.999000 0.000000 54.177000 0.070000 ;
      RECT 51.719000 0.000000 52.897000 0.070000 ;
      RECT 50.439000 0.000000 51.617000 0.070000 ;
      RECT 49.223000 0.000000 50.337000 0.070000 ;
      RECT 47.943000 0.000000 49.121000 0.070000 ;
      RECT 46.663000 0.000000 47.841000 0.070000 ;
      RECT 45.447000 0.000000 46.561000 0.070000 ;
      RECT 44.167000 0.000000 45.345000 0.070000 ;
      RECT 42.887000 0.000000 44.065000 0.070000 ;
      RECT 41.671000 0.000000 42.785000 0.070000 ;
      RECT 40.391000 0.000000 41.569000 0.070000 ;
      RECT 39.111000 0.000000 40.289000 0.070000 ;
      RECT 37.895000 0.000000 39.009000 0.070000 ;
      RECT 36.615000 0.000000 37.793000 0.070000 ;
      RECT 35.335000 0.000000 36.513000 0.070000 ;
      RECT 34.119000 0.000000 35.233000 0.070000 ;
      RECT 32.839000 0.000000 34.017000 0.070000 ;
      RECT 31.559000 0.000000 32.737000 0.070000 ;
      RECT 30.279000 0.000000 31.457000 0.070000 ;
      RECT 29.063000 0.000000 30.177000 0.070000 ;
      RECT 27.783000 0.000000 28.961000 0.070000 ;
      RECT 26.503000 0.000000 27.681000 0.070000 ;
      RECT 25.287000 0.000000 26.401000 0.070000 ;
      RECT 24.007000 0.000000 25.185000 0.070000 ;
      RECT 22.727000 0.000000 23.905000 0.070000 ;
      RECT 21.511000 0.000000 22.625000 0.070000 ;
      RECT 20.231000 0.000000 21.409000 0.070000 ;
      RECT 18.951000 0.000000 20.129000 0.070000 ;
      RECT 17.735000 0.000000 18.849000 0.070000 ;
      RECT 16.455000 0.000000 17.633000 0.070000 ;
      RECT 15.175000 0.000000 16.353000 0.070000 ;
      RECT 13.959000 0.000000 15.073000 0.070000 ;
      RECT 12.679000 0.000000 13.857000 0.070000 ;
      RECT 11.399000 0.000000 12.577000 0.070000 ;
      RECT 10.119000 0.000000 11.297000 0.070000 ;
      RECT 8.903000 0.000000 10.017000 0.070000 ;
      RECT 7.623000 0.000000 8.801000 0.070000 ;
      RECT 6.343000 0.000000 7.521000 0.070000 ;
      RECT 5.127000 0.000000 6.241000 0.070000 ;
      RECT 3.847000 0.000000 5.025000 0.070000 ;
      RECT 2.567000 0.000000 3.745000 0.070000 ;
      RECT 1.351000 0.000000 2.465000 0.070000 ;
      RECT 0.135000 0.000000 1.249000 0.070000 ;
      RECT 0.000000 0.000000 0.033000 0.070000 ;
    LAYER M4 ;
      RECT 0.000000 180.908000 216.000000 182.016000 ;
      RECT 0.080000 180.788000 215.920000 180.908000 ;
      RECT 0.000000 179.788000 216.000000 180.788000 ;
      RECT 0.080000 179.668000 215.920000 179.788000 ;
      RECT 0.000000 178.668000 216.000000 179.668000 ;
      RECT 0.080000 178.548000 215.920000 178.668000 ;
      RECT 0.000000 177.468000 216.000000 178.548000 ;
      RECT 0.080000 177.348000 215.920000 177.468000 ;
      RECT 0.000000 176.348000 216.000000 177.348000 ;
      RECT 0.080000 176.228000 215.920000 176.348000 ;
      RECT 0.000000 175.148000 216.000000 176.228000 ;
      RECT 0.080000 175.028000 215.920000 175.148000 ;
      RECT 0.000000 174.028000 216.000000 175.028000 ;
      RECT 0.080000 173.908000 215.920000 174.028000 ;
      RECT 0.000000 172.908000 216.000000 173.908000 ;
      RECT 0.080000 172.788000 215.920000 172.908000 ;
      RECT 0.000000 171.708000 216.000000 172.788000 ;
      RECT 0.080000 171.588000 215.920000 171.708000 ;
      RECT 0.000000 170.588000 216.000000 171.588000 ;
      RECT 0.080000 170.468000 215.920000 170.588000 ;
      RECT 0.000000 169.388000 216.000000 170.468000 ;
      RECT 0.080000 169.268000 215.920000 169.388000 ;
      RECT 0.000000 168.268000 216.000000 169.268000 ;
      RECT 0.080000 168.148000 215.920000 168.268000 ;
      RECT 0.000000 167.148000 216.000000 168.148000 ;
      RECT 0.080000 167.028000 215.920000 167.148000 ;
      RECT 0.000000 165.948000 216.000000 167.028000 ;
      RECT 0.080000 165.828000 215.920000 165.948000 ;
      RECT 0.000000 164.828000 216.000000 165.828000 ;
      RECT 0.080000 164.708000 215.920000 164.828000 ;
      RECT 0.000000 163.628000 216.000000 164.708000 ;
      RECT 0.080000 163.508000 215.920000 163.628000 ;
      RECT 0.000000 162.508000 216.000000 163.508000 ;
      RECT 0.080000 162.388000 215.920000 162.508000 ;
      RECT 0.000000 161.388000 216.000000 162.388000 ;
      RECT 0.080000 161.268000 215.920000 161.388000 ;
      RECT 0.000000 160.188000 216.000000 161.268000 ;
      RECT 0.080000 160.068000 215.920000 160.188000 ;
      RECT 0.000000 159.068000 216.000000 160.068000 ;
      RECT 0.080000 158.948000 215.920000 159.068000 ;
      RECT 0.000000 157.868000 216.000000 158.948000 ;
      RECT 0.080000 157.748000 215.920000 157.868000 ;
      RECT 0.000000 156.748000 216.000000 157.748000 ;
      RECT 0.080000 156.628000 215.920000 156.748000 ;
      RECT 0.000000 155.628000 216.000000 156.628000 ;
      RECT 0.080000 155.508000 215.920000 155.628000 ;
      RECT 0.000000 154.428000 216.000000 155.508000 ;
      RECT 0.080000 154.308000 215.920000 154.428000 ;
      RECT 0.000000 153.308000 216.000000 154.308000 ;
      RECT 0.080000 153.188000 215.920000 153.308000 ;
      RECT 0.000000 152.108000 216.000000 153.188000 ;
      RECT 0.080000 151.988000 215.920000 152.108000 ;
      RECT 0.000000 150.988000 216.000000 151.988000 ;
      RECT 0.080000 150.868000 215.920000 150.988000 ;
      RECT 0.000000 149.868000 216.000000 150.868000 ;
      RECT 0.080000 149.748000 215.920000 149.868000 ;
      RECT 0.000000 148.668000 216.000000 149.748000 ;
      RECT 0.080000 148.548000 215.920000 148.668000 ;
      RECT 0.000000 147.548000 216.000000 148.548000 ;
      RECT 0.080000 147.428000 215.920000 147.548000 ;
      RECT 0.000000 146.348000 216.000000 147.428000 ;
      RECT 0.080000 146.228000 215.920000 146.348000 ;
      RECT 0.000000 145.228000 216.000000 146.228000 ;
      RECT 0.080000 145.108000 215.920000 145.228000 ;
      RECT 0.000000 144.108000 216.000000 145.108000 ;
      RECT 0.080000 143.988000 215.920000 144.108000 ;
      RECT 0.000000 142.908000 216.000000 143.988000 ;
      RECT 0.080000 142.788000 215.920000 142.908000 ;
      RECT 0.000000 141.788000 216.000000 142.788000 ;
      RECT 0.080000 141.668000 215.920000 141.788000 ;
      RECT 0.000000 140.588000 216.000000 141.668000 ;
      RECT 0.080000 140.468000 215.920000 140.588000 ;
      RECT 0.000000 139.468000 216.000000 140.468000 ;
      RECT 0.080000 139.348000 215.920000 139.468000 ;
      RECT 0.000000 138.348000 216.000000 139.348000 ;
      RECT 0.080000 138.228000 215.920000 138.348000 ;
      RECT 0.000000 137.148000 216.000000 138.228000 ;
      RECT 0.080000 137.028000 215.920000 137.148000 ;
      RECT 0.000000 136.028000 216.000000 137.028000 ;
      RECT 0.080000 135.908000 215.920000 136.028000 ;
      RECT 0.000000 134.828000 216.000000 135.908000 ;
      RECT 0.080000 134.708000 215.920000 134.828000 ;
      RECT 0.000000 133.708000 216.000000 134.708000 ;
      RECT 0.080000 133.588000 215.920000 133.708000 ;
      RECT 0.000000 132.588000 216.000000 133.588000 ;
      RECT 0.080000 132.468000 215.920000 132.588000 ;
      RECT 0.000000 131.388000 216.000000 132.468000 ;
      RECT 0.080000 131.268000 215.920000 131.388000 ;
      RECT 0.000000 130.268000 216.000000 131.268000 ;
      RECT 0.080000 130.148000 215.920000 130.268000 ;
      RECT 0.000000 129.068000 216.000000 130.148000 ;
      RECT 0.080000 128.948000 215.920000 129.068000 ;
      RECT 0.000000 127.948000 216.000000 128.948000 ;
      RECT 0.080000 127.828000 215.920000 127.948000 ;
      RECT 0.000000 126.828000 216.000000 127.828000 ;
      RECT 0.080000 126.708000 215.920000 126.828000 ;
      RECT 0.000000 125.628000 216.000000 126.708000 ;
      RECT 0.080000 125.508000 215.920000 125.628000 ;
      RECT 0.000000 124.508000 216.000000 125.508000 ;
      RECT 0.080000 124.388000 215.920000 124.508000 ;
      RECT 0.000000 123.308000 216.000000 124.388000 ;
      RECT 0.080000 123.188000 215.920000 123.308000 ;
      RECT 0.000000 122.188000 216.000000 123.188000 ;
      RECT 0.080000 122.068000 215.920000 122.188000 ;
      RECT 0.000000 121.068000 216.000000 122.068000 ;
      RECT 0.080000 120.948000 215.920000 121.068000 ;
      RECT 0.000000 119.868000 216.000000 120.948000 ;
      RECT 0.080000 119.748000 215.920000 119.868000 ;
      RECT 0.000000 118.748000 216.000000 119.748000 ;
      RECT 0.080000 118.628000 215.920000 118.748000 ;
      RECT 0.000000 117.548000 216.000000 118.628000 ;
      RECT 0.080000 117.428000 215.920000 117.548000 ;
      RECT 0.000000 116.428000 216.000000 117.428000 ;
      RECT 0.080000 116.308000 215.920000 116.428000 ;
      RECT 0.000000 115.308000 216.000000 116.308000 ;
      RECT 0.080000 115.188000 215.920000 115.308000 ;
      RECT 0.000000 114.108000 216.000000 115.188000 ;
      RECT 0.080000 113.988000 215.920000 114.108000 ;
      RECT 0.000000 112.988000 216.000000 113.988000 ;
      RECT 0.080000 112.868000 215.920000 112.988000 ;
      RECT 0.000000 111.788000 216.000000 112.868000 ;
      RECT 0.080000 111.668000 215.920000 111.788000 ;
      RECT 0.000000 110.668000 216.000000 111.668000 ;
      RECT 0.080000 110.548000 215.920000 110.668000 ;
      RECT 0.000000 109.548000 216.000000 110.548000 ;
      RECT 0.080000 109.428000 215.920000 109.548000 ;
      RECT 0.000000 108.348000 216.000000 109.428000 ;
      RECT 0.080000 108.228000 215.920000 108.348000 ;
      RECT 0.000000 107.228000 216.000000 108.228000 ;
      RECT 0.080000 107.108000 215.920000 107.228000 ;
      RECT 0.000000 106.028000 216.000000 107.108000 ;
      RECT 0.080000 105.908000 215.920000 106.028000 ;
      RECT 0.000000 104.908000 216.000000 105.908000 ;
      RECT 0.080000 104.788000 215.920000 104.908000 ;
      RECT 0.000000 103.788000 216.000000 104.788000 ;
      RECT 0.080000 103.668000 215.920000 103.788000 ;
      RECT 0.000000 102.588000 216.000000 103.668000 ;
      RECT 0.080000 102.468000 215.920000 102.588000 ;
      RECT 0.000000 101.468000 216.000000 102.468000 ;
      RECT 0.080000 101.348000 215.920000 101.468000 ;
      RECT 0.000000 100.268000 216.000000 101.348000 ;
      RECT 0.080000 100.148000 215.920000 100.268000 ;
      RECT 0.000000 99.148000 216.000000 100.148000 ;
      RECT 0.080000 99.028000 215.920000 99.148000 ;
      RECT 0.000000 98.028000 216.000000 99.028000 ;
      RECT 0.080000 97.908000 215.920000 98.028000 ;
      RECT 0.000000 96.828000 216.000000 97.908000 ;
      RECT 0.080000 96.708000 215.920000 96.828000 ;
      RECT 0.000000 95.708000 216.000000 96.708000 ;
      RECT 0.080000 95.588000 215.920000 95.708000 ;
      RECT 0.000000 94.508000 216.000000 95.588000 ;
      RECT 0.080000 94.388000 215.920000 94.508000 ;
      RECT 0.000000 93.388000 216.000000 94.388000 ;
      RECT 0.080000 93.268000 215.920000 93.388000 ;
      RECT 0.000000 92.268000 216.000000 93.268000 ;
      RECT 0.080000 92.148000 215.920000 92.268000 ;
      RECT 0.000000 91.068000 216.000000 92.148000 ;
      RECT 0.080000 90.948000 215.920000 91.068000 ;
      RECT 0.000000 89.948000 216.000000 90.948000 ;
      RECT 0.080000 89.828000 215.920000 89.948000 ;
      RECT 0.000000 88.748000 216.000000 89.828000 ;
      RECT 0.080000 88.628000 215.920000 88.748000 ;
      RECT 0.000000 87.628000 216.000000 88.628000 ;
      RECT 0.080000 87.508000 215.920000 87.628000 ;
      RECT 0.000000 86.508000 216.000000 87.508000 ;
      RECT 0.080000 86.388000 215.920000 86.508000 ;
      RECT 0.000000 85.308000 216.000000 86.388000 ;
      RECT 0.080000 85.188000 215.920000 85.308000 ;
      RECT 0.000000 84.188000 216.000000 85.188000 ;
      RECT 0.080000 84.068000 215.920000 84.188000 ;
      RECT 0.000000 82.988000 216.000000 84.068000 ;
      RECT 0.080000 82.868000 215.920000 82.988000 ;
      RECT 0.000000 81.868000 216.000000 82.868000 ;
      RECT 0.080000 81.748000 215.920000 81.868000 ;
      RECT 0.000000 80.748000 216.000000 81.748000 ;
      RECT 0.080000 80.628000 215.920000 80.748000 ;
      RECT 0.000000 79.548000 216.000000 80.628000 ;
      RECT 0.080000 79.428000 215.920000 79.548000 ;
      RECT 0.000000 78.428000 216.000000 79.428000 ;
      RECT 0.080000 78.308000 215.920000 78.428000 ;
      RECT 0.000000 77.228000 216.000000 78.308000 ;
      RECT 0.080000 77.108000 215.920000 77.228000 ;
      RECT 0.000000 76.108000 216.000000 77.108000 ;
      RECT 0.080000 75.988000 215.920000 76.108000 ;
      RECT 0.000000 74.988000 216.000000 75.988000 ;
      RECT 0.080000 74.868000 215.920000 74.988000 ;
      RECT 0.000000 73.788000 216.000000 74.868000 ;
      RECT 0.080000 73.668000 215.920000 73.788000 ;
      RECT 0.000000 72.668000 216.000000 73.668000 ;
      RECT 0.080000 72.548000 215.920000 72.668000 ;
      RECT 0.000000 71.468000 216.000000 72.548000 ;
      RECT 0.080000 71.348000 215.920000 71.468000 ;
      RECT 0.000000 70.348000 216.000000 71.348000 ;
      RECT 0.080000 70.228000 215.920000 70.348000 ;
      RECT 0.000000 69.228000 216.000000 70.228000 ;
      RECT 0.080000 69.108000 215.920000 69.228000 ;
      RECT 0.000000 68.028000 216.000000 69.108000 ;
      RECT 0.080000 67.908000 215.920000 68.028000 ;
      RECT 0.000000 66.908000 216.000000 67.908000 ;
      RECT 0.080000 66.788000 215.920000 66.908000 ;
      RECT 0.000000 65.708000 216.000000 66.788000 ;
      RECT 0.080000 65.588000 215.920000 65.708000 ;
      RECT 0.000000 64.588000 216.000000 65.588000 ;
      RECT 0.080000 64.468000 215.920000 64.588000 ;
      RECT 0.000000 63.468000 216.000000 64.468000 ;
      RECT 0.080000 63.348000 215.920000 63.468000 ;
      RECT 0.000000 62.268000 216.000000 63.348000 ;
      RECT 0.080000 62.148000 215.920000 62.268000 ;
      RECT 0.000000 61.148000 216.000000 62.148000 ;
      RECT 0.080000 61.028000 215.920000 61.148000 ;
      RECT 0.000000 59.948000 216.000000 61.028000 ;
      RECT 0.080000 59.828000 215.920000 59.948000 ;
      RECT 0.000000 58.828000 216.000000 59.828000 ;
      RECT 0.080000 58.708000 215.920000 58.828000 ;
      RECT 0.000000 57.708000 216.000000 58.708000 ;
      RECT 0.080000 57.588000 215.920000 57.708000 ;
      RECT 0.000000 56.508000 216.000000 57.588000 ;
      RECT 0.080000 56.388000 215.920000 56.508000 ;
      RECT 0.000000 55.388000 216.000000 56.388000 ;
      RECT 0.080000 55.268000 215.920000 55.388000 ;
      RECT 0.000000 54.188000 216.000000 55.268000 ;
      RECT 0.080000 54.068000 215.920000 54.188000 ;
      RECT 0.000000 53.068000 216.000000 54.068000 ;
      RECT 0.080000 52.948000 215.920000 53.068000 ;
      RECT 0.000000 51.948000 216.000000 52.948000 ;
      RECT 0.080000 51.828000 215.920000 51.948000 ;
      RECT 0.000000 50.748000 216.000000 51.828000 ;
      RECT 0.080000 50.628000 215.920000 50.748000 ;
      RECT 0.000000 49.628000 216.000000 50.628000 ;
      RECT 0.080000 49.508000 215.920000 49.628000 ;
      RECT 0.000000 48.428000 216.000000 49.508000 ;
      RECT 0.080000 48.308000 215.920000 48.428000 ;
      RECT 0.000000 47.308000 216.000000 48.308000 ;
      RECT 0.080000 47.188000 215.920000 47.308000 ;
      RECT 0.000000 46.188000 216.000000 47.188000 ;
      RECT 0.080000 46.068000 215.920000 46.188000 ;
      RECT 0.000000 44.988000 216.000000 46.068000 ;
      RECT 0.080000 44.868000 215.920000 44.988000 ;
      RECT 0.000000 43.868000 216.000000 44.868000 ;
      RECT 0.080000 43.748000 215.920000 43.868000 ;
      RECT 0.000000 42.668000 216.000000 43.748000 ;
      RECT 0.080000 42.548000 215.920000 42.668000 ;
      RECT 0.000000 41.548000 216.000000 42.548000 ;
      RECT 0.080000 41.428000 215.920000 41.548000 ;
      RECT 0.000000 40.428000 216.000000 41.428000 ;
      RECT 0.080000 40.308000 215.920000 40.428000 ;
      RECT 0.000000 39.228000 216.000000 40.308000 ;
      RECT 0.080000 39.108000 215.920000 39.228000 ;
      RECT 0.000000 38.108000 216.000000 39.108000 ;
      RECT 0.080000 37.988000 215.920000 38.108000 ;
      RECT 0.000000 36.908000 216.000000 37.988000 ;
      RECT 0.080000 36.788000 215.920000 36.908000 ;
      RECT 0.000000 35.788000 216.000000 36.788000 ;
      RECT 0.080000 35.668000 215.920000 35.788000 ;
      RECT 0.000000 34.668000 216.000000 35.668000 ;
      RECT 0.080000 34.548000 215.920000 34.668000 ;
      RECT 0.000000 33.468000 216.000000 34.548000 ;
      RECT 0.080000 33.348000 215.920000 33.468000 ;
      RECT 0.000000 32.348000 216.000000 33.348000 ;
      RECT 0.080000 32.228000 215.920000 32.348000 ;
      RECT 0.000000 31.148000 216.000000 32.228000 ;
      RECT 0.080000 31.028000 215.920000 31.148000 ;
      RECT 0.000000 30.028000 216.000000 31.028000 ;
      RECT 0.080000 29.908000 215.920000 30.028000 ;
      RECT 0.000000 28.908000 216.000000 29.908000 ;
      RECT 0.080000 28.788000 215.920000 28.908000 ;
      RECT 0.000000 27.708000 216.000000 28.788000 ;
      RECT 0.080000 27.588000 215.920000 27.708000 ;
      RECT 0.000000 26.588000 216.000000 27.588000 ;
      RECT 0.080000 26.468000 215.920000 26.588000 ;
      RECT 0.000000 25.388000 216.000000 26.468000 ;
      RECT 0.080000 25.268000 215.920000 25.388000 ;
      RECT 0.000000 24.268000 216.000000 25.268000 ;
      RECT 0.080000 24.148000 215.920000 24.268000 ;
      RECT 0.000000 23.148000 216.000000 24.148000 ;
      RECT 0.080000 23.028000 215.920000 23.148000 ;
      RECT 0.000000 21.948000 216.000000 23.028000 ;
      RECT 0.080000 21.828000 215.920000 21.948000 ;
      RECT 0.000000 20.828000 216.000000 21.828000 ;
      RECT 0.080000 20.708000 215.920000 20.828000 ;
      RECT 0.000000 19.628000 216.000000 20.708000 ;
      RECT 0.080000 19.508000 215.920000 19.628000 ;
      RECT 0.000000 18.508000 216.000000 19.508000 ;
      RECT 0.080000 18.388000 215.920000 18.508000 ;
      RECT 0.000000 17.388000 216.000000 18.388000 ;
      RECT 0.080000 17.268000 215.920000 17.388000 ;
      RECT 0.000000 16.188000 216.000000 17.268000 ;
      RECT 0.080000 16.068000 215.920000 16.188000 ;
      RECT 0.000000 15.068000 216.000000 16.068000 ;
      RECT 0.080000 14.948000 215.920000 15.068000 ;
      RECT 0.000000 13.868000 216.000000 14.948000 ;
      RECT 0.080000 13.748000 215.920000 13.868000 ;
      RECT 0.000000 12.748000 216.000000 13.748000 ;
      RECT 0.080000 12.628000 215.920000 12.748000 ;
      RECT 0.000000 11.628000 216.000000 12.628000 ;
      RECT 0.080000 11.508000 215.920000 11.628000 ;
      RECT 0.000000 10.428000 216.000000 11.508000 ;
      RECT 0.080000 10.308000 215.920000 10.428000 ;
      RECT 0.000000 9.308000 216.000000 10.308000 ;
      RECT 0.080000 9.188000 215.920000 9.308000 ;
      RECT 0.000000 8.108000 216.000000 9.188000 ;
      RECT 0.080000 7.988000 215.920000 8.108000 ;
      RECT 0.000000 6.988000 216.000000 7.988000 ;
      RECT 0.080000 6.868000 215.920000 6.988000 ;
      RECT 0.000000 5.868000 216.000000 6.868000 ;
      RECT 0.080000 5.748000 215.920000 5.868000 ;
      RECT 0.000000 4.668000 216.000000 5.748000 ;
      RECT 0.080000 4.548000 215.920000 4.668000 ;
      RECT 0.000000 3.548000 216.000000 4.548000 ;
      RECT 0.080000 3.428000 215.920000 3.548000 ;
      RECT 0.000000 2.348000 216.000000 3.428000 ;
      RECT 0.080000 2.228000 215.920000 2.348000 ;
      RECT 0.000000 1.308000 216.000000 2.228000 ;
      RECT 0.080000 1.188000 215.920000 1.308000 ;
      RECT 0.000000 0.108000 216.000000 1.188000 ;
      RECT 0.080000 0.000000 215.920000 0.108000 ;
    LAYER M5 ;
      RECT 215.560000 181.896000 216.000000 182.016000 ;
      RECT 214.280000 181.896000 215.360000 182.016000 ;
      RECT 213.080000 181.896000 214.080000 182.016000 ;
      RECT 211.800000 181.896000 212.880000 182.016000 ;
      RECT 210.520000 181.896000 211.600000 182.016000 ;
      RECT 209.240000 181.896000 210.320000 182.016000 ;
      RECT 208.040000 181.896000 209.040000 182.016000 ;
      RECT 206.760000 181.896000 207.840000 182.016000 ;
      RECT 205.480000 181.896000 206.560000 182.016000 ;
      RECT 204.200000 181.896000 205.280000 182.016000 ;
      RECT 203.000000 181.896000 204.000000 182.016000 ;
      RECT 201.720000 181.896000 202.800000 182.016000 ;
      RECT 200.440000 181.896000 201.520000 182.016000 ;
      RECT 199.160000 181.896000 200.240000 182.016000 ;
      RECT 197.960000 181.896000 198.960000 182.016000 ;
      RECT 196.680000 181.896000 197.760000 182.016000 ;
      RECT 195.400000 181.896000 196.480000 182.016000 ;
      RECT 194.120000 181.896000 195.200000 182.016000 ;
      RECT 192.920000 181.896000 193.920000 182.016000 ;
      RECT 191.640000 181.896000 192.720000 182.016000 ;
      RECT 190.360000 181.896000 191.440000 182.016000 ;
      RECT 189.080000 181.896000 190.160000 182.016000 ;
      RECT 187.880000 181.896000 188.880000 182.016000 ;
      RECT 186.600000 181.896000 187.680000 182.016000 ;
      RECT 185.320000 181.896000 186.400000 182.016000 ;
      RECT 184.040000 181.896000 185.120000 182.016000 ;
      RECT 182.840000 181.896000 183.840000 182.016000 ;
      RECT 181.560000 181.896000 182.640000 182.016000 ;
      RECT 180.280000 181.896000 181.360000 182.016000 ;
      RECT 179.000000 181.896000 180.080000 182.016000 ;
      RECT 177.800000 181.896000 178.800000 182.016000 ;
      RECT 176.520000 181.896000 177.600000 182.016000 ;
      RECT 175.240000 181.896000 176.320000 182.016000 ;
      RECT 173.960000 181.896000 175.040000 182.016000 ;
      RECT 172.760000 181.896000 173.760000 182.016000 ;
      RECT 171.480000 181.896000 172.560000 182.016000 ;
      RECT 170.200000 181.896000 171.280000 182.016000 ;
      RECT 168.920000 181.896000 170.000000 182.016000 ;
      RECT 167.720000 181.896000 168.720000 182.016000 ;
      RECT 166.440000 181.896000 167.520000 182.016000 ;
      RECT 165.160000 181.896000 166.240000 182.016000 ;
      RECT 163.880000 181.896000 164.960000 182.016000 ;
      RECT 162.680000 181.896000 163.680000 182.016000 ;
      RECT 161.400000 181.896000 162.480000 182.016000 ;
      RECT 160.120000 181.896000 161.200000 182.016000 ;
      RECT 158.840000 181.896000 159.920000 182.016000 ;
      RECT 157.640000 181.896000 158.640000 182.016000 ;
      RECT 156.360000 181.896000 157.440000 182.016000 ;
      RECT 155.080000 181.896000 156.160000 182.016000 ;
      RECT 153.800000 181.896000 154.880000 182.016000 ;
      RECT 152.600000 181.896000 153.600000 182.016000 ;
      RECT 151.320000 181.896000 152.400000 182.016000 ;
      RECT 150.040000 181.896000 151.120000 182.016000 ;
      RECT 148.760000 181.896000 149.840000 182.016000 ;
      RECT 147.560000 181.896000 148.560000 182.016000 ;
      RECT 146.280000 181.896000 147.360000 182.016000 ;
      RECT 145.000000 181.896000 146.080000 182.016000 ;
      RECT 143.720000 181.896000 144.800000 182.016000 ;
      RECT 142.520000 181.896000 143.520000 182.016000 ;
      RECT 141.240000 181.896000 142.320000 182.016000 ;
      RECT 139.960000 181.896000 141.040000 182.016000 ;
      RECT 138.680000 181.896000 139.760000 182.016000 ;
      RECT 137.480000 181.896000 138.480000 182.016000 ;
      RECT 136.200000 181.896000 137.280000 182.016000 ;
      RECT 134.920000 181.896000 136.000000 182.016000 ;
      RECT 133.640000 181.896000 134.720000 182.016000 ;
      RECT 132.440000 181.896000 133.440000 182.016000 ;
      RECT 131.160000 181.896000 132.240000 182.016000 ;
      RECT 129.880000 181.896000 130.960000 182.016000 ;
      RECT 128.600000 181.896000 129.680000 182.016000 ;
      RECT 127.400000 181.896000 128.400000 182.016000 ;
      RECT 126.120000 181.896000 127.200000 182.016000 ;
      RECT 124.840000 181.896000 125.920000 182.016000 ;
      RECT 123.560000 181.896000 124.640000 182.016000 ;
      RECT 122.360000 181.896000 123.360000 182.016000 ;
      RECT 121.080000 181.896000 122.160000 182.016000 ;
      RECT 119.800000 181.896000 120.880000 182.016000 ;
      RECT 118.520000 181.896000 119.600000 182.016000 ;
      RECT 117.320000 181.896000 118.320000 182.016000 ;
      RECT 116.040000 181.896000 117.120000 182.016000 ;
      RECT 114.760000 181.896000 115.840000 182.016000 ;
      RECT 113.480000 181.896000 114.560000 182.016000 ;
      RECT 112.280000 181.896000 113.280000 182.016000 ;
      RECT 111.000000 181.896000 112.080000 182.016000 ;
      RECT 109.720000 181.896000 110.800000 182.016000 ;
      RECT 108.440000 181.896000 109.520000 182.016000 ;
      RECT 107.240000 181.896000 108.240000 182.016000 ;
      RECT 105.960000 181.896000 107.040000 182.016000 ;
      RECT 104.680000 181.896000 105.760000 182.016000 ;
      RECT 103.400000 181.896000 104.480000 182.016000 ;
      RECT 102.200000 181.896000 103.200000 182.016000 ;
      RECT 100.920000 181.896000 102.000000 182.016000 ;
      RECT 99.640000 181.896000 100.720000 182.016000 ;
      RECT 98.360000 181.896000 99.440000 182.016000 ;
      RECT 97.160000 181.896000 98.160000 182.016000 ;
      RECT 95.880000 181.896000 96.960000 182.016000 ;
      RECT 94.600000 181.896000 95.680000 182.016000 ;
      RECT 93.320000 181.896000 94.400000 182.016000 ;
      RECT 92.120000 181.896000 93.120000 182.016000 ;
      RECT 90.840000 181.896000 91.920000 182.016000 ;
      RECT 89.560000 181.896000 90.640000 182.016000 ;
      RECT 88.280000 181.896000 89.360000 182.016000 ;
      RECT 87.080000 181.896000 88.080000 182.016000 ;
      RECT 85.800000 181.896000 86.880000 182.016000 ;
      RECT 84.520000 181.896000 85.600000 182.016000 ;
      RECT 83.240000 181.896000 84.320000 182.016000 ;
      RECT 82.040000 181.896000 83.040000 182.016000 ;
      RECT 80.760000 181.896000 81.840000 182.016000 ;
      RECT 79.480000 181.896000 80.560000 182.016000 ;
      RECT 78.200000 181.896000 79.280000 182.016000 ;
      RECT 77.000000 181.896000 78.000000 182.016000 ;
      RECT 75.720000 181.896000 76.800000 182.016000 ;
      RECT 74.440000 181.896000 75.520000 182.016000 ;
      RECT 73.160000 181.896000 74.240000 182.016000 ;
      RECT 71.960000 181.896000 72.960000 182.016000 ;
      RECT 70.680000 181.896000 71.760000 182.016000 ;
      RECT 69.400000 181.896000 70.480000 182.016000 ;
      RECT 68.120000 181.896000 69.200000 182.016000 ;
      RECT 66.920000 181.896000 67.920000 182.016000 ;
      RECT 65.640000 181.896000 66.720000 182.016000 ;
      RECT 64.360000 181.896000 65.440000 182.016000 ;
      RECT 63.080000 181.896000 64.160000 182.016000 ;
      RECT 61.880000 181.896000 62.880000 182.016000 ;
      RECT 60.600000 181.896000 61.680000 182.016000 ;
      RECT 59.320000 181.896000 60.400000 182.016000 ;
      RECT 58.040000 181.896000 59.120000 182.016000 ;
      RECT 56.840000 181.896000 57.840000 182.016000 ;
      RECT 55.560000 181.896000 56.640000 182.016000 ;
      RECT 54.280000 181.896000 55.360000 182.016000 ;
      RECT 53.000000 181.896000 54.080000 182.016000 ;
      RECT 51.800000 181.896000 52.800000 182.016000 ;
      RECT 50.520000 181.896000 51.600000 182.016000 ;
      RECT 49.240000 181.896000 50.320000 182.016000 ;
      RECT 47.960000 181.896000 49.040000 182.016000 ;
      RECT 46.760000 181.896000 47.760000 182.016000 ;
      RECT 45.480000 181.896000 46.560000 182.016000 ;
      RECT 44.200000 181.896000 45.280000 182.016000 ;
      RECT 42.920000 181.896000 44.000000 182.016000 ;
      RECT 41.720000 181.896000 42.720000 182.016000 ;
      RECT 40.440000 181.896000 41.520000 182.016000 ;
      RECT 39.160000 181.896000 40.240000 182.016000 ;
      RECT 37.880000 181.896000 38.960000 182.016000 ;
      RECT 36.680000 181.896000 37.680000 182.016000 ;
      RECT 35.400000 181.896000 36.480000 182.016000 ;
      RECT 34.120000 181.896000 35.200000 182.016000 ;
      RECT 32.840000 181.896000 33.920000 182.016000 ;
      RECT 31.640000 181.896000 32.640000 182.016000 ;
      RECT 30.360000 181.896000 31.440000 182.016000 ;
      RECT 29.080000 181.896000 30.160000 182.016000 ;
      RECT 27.800000 181.896000 28.880000 182.016000 ;
      RECT 26.600000 181.896000 27.600000 182.016000 ;
      RECT 25.320000 181.896000 26.400000 182.016000 ;
      RECT 24.040000 181.896000 25.120000 182.016000 ;
      RECT 22.760000 181.896000 23.840000 182.016000 ;
      RECT 21.560000 181.896000 22.560000 182.016000 ;
      RECT 20.280000 181.896000 21.360000 182.016000 ;
      RECT 19.000000 181.896000 20.080000 182.016000 ;
      RECT 17.720000 181.896000 18.800000 182.016000 ;
      RECT 16.520000 181.896000 17.520000 182.016000 ;
      RECT 15.240000 181.896000 16.320000 182.016000 ;
      RECT 13.960000 181.896000 15.040000 182.016000 ;
      RECT 12.680000 181.896000 13.760000 182.016000 ;
      RECT 11.480000 181.896000 12.480000 182.016000 ;
      RECT 10.200000 181.896000 11.280000 182.016000 ;
      RECT 8.920000 181.896000 10.000000 182.016000 ;
      RECT 7.640000 181.896000 8.720000 182.016000 ;
      RECT 6.440000 181.896000 7.440000 182.016000 ;
      RECT 5.160000 181.896000 6.240000 182.016000 ;
      RECT 3.880000 181.896000 4.960000 182.016000 ;
      RECT 2.600000 181.896000 3.680000 182.016000 ;
      RECT 1.400000 181.896000 2.400000 182.016000 ;
      RECT 0.200000 181.896000 1.200000 182.016000 ;
      RECT 0.000000 0.120000 216.000000 181.896000 ;
      RECT 215.560000 0.000000 216.000000 0.120000 ;
      RECT 214.280000 0.000000 215.360000 0.120000 ;
      RECT 213.080000 0.000000 214.080000 0.120000 ;
      RECT 211.800000 0.000000 212.880000 0.120000 ;
      RECT 210.520000 0.000000 211.600000 0.120000 ;
      RECT 209.240000 0.000000 210.320000 0.120000 ;
      RECT 208.040000 0.000000 209.040000 0.120000 ;
      RECT 206.760000 0.000000 207.840000 0.120000 ;
      RECT 205.480000 0.000000 206.560000 0.120000 ;
      RECT 204.200000 0.000000 205.280000 0.120000 ;
      RECT 203.000000 0.000000 204.000000 0.120000 ;
      RECT 201.720000 0.000000 202.800000 0.120000 ;
      RECT 200.440000 0.000000 201.520000 0.120000 ;
      RECT 199.160000 0.000000 200.240000 0.120000 ;
      RECT 197.960000 0.000000 198.960000 0.120000 ;
      RECT 196.680000 0.000000 197.760000 0.120000 ;
      RECT 195.400000 0.000000 196.480000 0.120000 ;
      RECT 194.120000 0.000000 195.200000 0.120000 ;
      RECT 192.920000 0.000000 193.920000 0.120000 ;
      RECT 191.640000 0.000000 192.720000 0.120000 ;
      RECT 190.360000 0.000000 191.440000 0.120000 ;
      RECT 189.080000 0.000000 190.160000 0.120000 ;
      RECT 187.880000 0.000000 188.880000 0.120000 ;
      RECT 186.600000 0.000000 187.680000 0.120000 ;
      RECT 185.320000 0.000000 186.400000 0.120000 ;
      RECT 184.040000 0.000000 185.120000 0.120000 ;
      RECT 182.840000 0.000000 183.840000 0.120000 ;
      RECT 181.560000 0.000000 182.640000 0.120000 ;
      RECT 180.280000 0.000000 181.360000 0.120000 ;
      RECT 179.000000 0.000000 180.080000 0.120000 ;
      RECT 177.800000 0.000000 178.800000 0.120000 ;
      RECT 176.520000 0.000000 177.600000 0.120000 ;
      RECT 175.240000 0.000000 176.320000 0.120000 ;
      RECT 173.960000 0.000000 175.040000 0.120000 ;
      RECT 172.760000 0.000000 173.760000 0.120000 ;
      RECT 171.480000 0.000000 172.560000 0.120000 ;
      RECT 170.200000 0.000000 171.280000 0.120000 ;
      RECT 168.920000 0.000000 170.000000 0.120000 ;
      RECT 167.720000 0.000000 168.720000 0.120000 ;
      RECT 166.440000 0.000000 167.520000 0.120000 ;
      RECT 165.160000 0.000000 166.240000 0.120000 ;
      RECT 163.880000 0.000000 164.960000 0.120000 ;
      RECT 162.680000 0.000000 163.680000 0.120000 ;
      RECT 161.400000 0.000000 162.480000 0.120000 ;
      RECT 160.120000 0.000000 161.200000 0.120000 ;
      RECT 158.840000 0.000000 159.920000 0.120000 ;
      RECT 157.640000 0.000000 158.640000 0.120000 ;
      RECT 156.360000 0.000000 157.440000 0.120000 ;
      RECT 155.080000 0.000000 156.160000 0.120000 ;
      RECT 153.800000 0.000000 154.880000 0.120000 ;
      RECT 152.600000 0.000000 153.600000 0.120000 ;
      RECT 151.320000 0.000000 152.400000 0.120000 ;
      RECT 150.040000 0.000000 151.120000 0.120000 ;
      RECT 148.760000 0.000000 149.840000 0.120000 ;
      RECT 147.560000 0.000000 148.560000 0.120000 ;
      RECT 146.280000 0.000000 147.360000 0.120000 ;
      RECT 145.000000 0.000000 146.080000 0.120000 ;
      RECT 143.720000 0.000000 144.800000 0.120000 ;
      RECT 142.520000 0.000000 143.520000 0.120000 ;
      RECT 141.240000 0.000000 142.320000 0.120000 ;
      RECT 139.960000 0.000000 141.040000 0.120000 ;
      RECT 138.680000 0.000000 139.760000 0.120000 ;
      RECT 137.480000 0.000000 138.480000 0.120000 ;
      RECT 136.200000 0.000000 137.280000 0.120000 ;
      RECT 134.920000 0.000000 136.000000 0.120000 ;
      RECT 133.640000 0.000000 134.720000 0.120000 ;
      RECT 132.440000 0.000000 133.440000 0.120000 ;
      RECT 131.160000 0.000000 132.240000 0.120000 ;
      RECT 129.880000 0.000000 130.960000 0.120000 ;
      RECT 128.600000 0.000000 129.680000 0.120000 ;
      RECT 127.400000 0.000000 128.400000 0.120000 ;
      RECT 126.120000 0.000000 127.200000 0.120000 ;
      RECT 124.840000 0.000000 125.920000 0.120000 ;
      RECT 123.560000 0.000000 124.640000 0.120000 ;
      RECT 122.360000 0.000000 123.360000 0.120000 ;
      RECT 121.080000 0.000000 122.160000 0.120000 ;
      RECT 119.800000 0.000000 120.880000 0.120000 ;
      RECT 118.520000 0.000000 119.600000 0.120000 ;
      RECT 117.320000 0.000000 118.320000 0.120000 ;
      RECT 116.040000 0.000000 117.120000 0.120000 ;
      RECT 114.760000 0.000000 115.840000 0.120000 ;
      RECT 113.480000 0.000000 114.560000 0.120000 ;
      RECT 112.280000 0.000000 113.280000 0.120000 ;
      RECT 111.000000 0.000000 112.080000 0.120000 ;
      RECT 109.720000 0.000000 110.800000 0.120000 ;
      RECT 108.440000 0.000000 109.520000 0.120000 ;
      RECT 107.240000 0.000000 108.240000 0.120000 ;
      RECT 105.960000 0.000000 107.040000 0.120000 ;
      RECT 104.680000 0.000000 105.760000 0.120000 ;
      RECT 103.400000 0.000000 104.480000 0.120000 ;
      RECT 102.200000 0.000000 103.200000 0.120000 ;
      RECT 100.920000 0.000000 102.000000 0.120000 ;
      RECT 99.640000 0.000000 100.720000 0.120000 ;
      RECT 98.360000 0.000000 99.440000 0.120000 ;
      RECT 97.160000 0.000000 98.160000 0.120000 ;
      RECT 95.880000 0.000000 96.960000 0.120000 ;
      RECT 94.600000 0.000000 95.680000 0.120000 ;
      RECT 93.320000 0.000000 94.400000 0.120000 ;
      RECT 92.120000 0.000000 93.120000 0.120000 ;
      RECT 90.840000 0.000000 91.920000 0.120000 ;
      RECT 89.560000 0.000000 90.640000 0.120000 ;
      RECT 88.280000 0.000000 89.360000 0.120000 ;
      RECT 87.080000 0.000000 88.080000 0.120000 ;
      RECT 85.800000 0.000000 86.880000 0.120000 ;
      RECT 84.520000 0.000000 85.600000 0.120000 ;
      RECT 83.240000 0.000000 84.320000 0.120000 ;
      RECT 82.040000 0.000000 83.040000 0.120000 ;
      RECT 80.760000 0.000000 81.840000 0.120000 ;
      RECT 79.480000 0.000000 80.560000 0.120000 ;
      RECT 78.200000 0.000000 79.280000 0.120000 ;
      RECT 77.000000 0.000000 78.000000 0.120000 ;
      RECT 75.720000 0.000000 76.800000 0.120000 ;
      RECT 74.440000 0.000000 75.520000 0.120000 ;
      RECT 73.160000 0.000000 74.240000 0.120000 ;
      RECT 71.960000 0.000000 72.960000 0.120000 ;
      RECT 70.680000 0.000000 71.760000 0.120000 ;
      RECT 69.400000 0.000000 70.480000 0.120000 ;
      RECT 68.120000 0.000000 69.200000 0.120000 ;
      RECT 66.920000 0.000000 67.920000 0.120000 ;
      RECT 65.640000 0.000000 66.720000 0.120000 ;
      RECT 64.360000 0.000000 65.440000 0.120000 ;
      RECT 63.080000 0.000000 64.160000 0.120000 ;
      RECT 61.880000 0.000000 62.880000 0.120000 ;
      RECT 60.600000 0.000000 61.680000 0.120000 ;
      RECT 59.320000 0.000000 60.400000 0.120000 ;
      RECT 58.040000 0.000000 59.120000 0.120000 ;
      RECT 56.840000 0.000000 57.840000 0.120000 ;
      RECT 55.560000 0.000000 56.640000 0.120000 ;
      RECT 54.280000 0.000000 55.360000 0.120000 ;
      RECT 53.000000 0.000000 54.080000 0.120000 ;
      RECT 51.800000 0.000000 52.800000 0.120000 ;
      RECT 50.520000 0.000000 51.600000 0.120000 ;
      RECT 49.240000 0.000000 50.320000 0.120000 ;
      RECT 47.960000 0.000000 49.040000 0.120000 ;
      RECT 46.760000 0.000000 47.760000 0.120000 ;
      RECT 45.480000 0.000000 46.560000 0.120000 ;
      RECT 44.200000 0.000000 45.280000 0.120000 ;
      RECT 42.920000 0.000000 44.000000 0.120000 ;
      RECT 41.720000 0.000000 42.720000 0.120000 ;
      RECT 40.440000 0.000000 41.520000 0.120000 ;
      RECT 39.160000 0.000000 40.240000 0.120000 ;
      RECT 37.880000 0.000000 38.960000 0.120000 ;
      RECT 36.680000 0.000000 37.680000 0.120000 ;
      RECT 35.400000 0.000000 36.480000 0.120000 ;
      RECT 34.120000 0.000000 35.200000 0.120000 ;
      RECT 32.840000 0.000000 33.920000 0.120000 ;
      RECT 31.640000 0.000000 32.640000 0.120000 ;
      RECT 30.360000 0.000000 31.440000 0.120000 ;
      RECT 29.080000 0.000000 30.160000 0.120000 ;
      RECT 27.800000 0.000000 28.880000 0.120000 ;
      RECT 26.600000 0.000000 27.600000 0.120000 ;
      RECT 25.320000 0.000000 26.400000 0.120000 ;
      RECT 24.040000 0.000000 25.120000 0.120000 ;
      RECT 22.760000 0.000000 23.840000 0.120000 ;
      RECT 21.560000 0.000000 22.560000 0.120000 ;
      RECT 20.280000 0.000000 21.360000 0.120000 ;
      RECT 19.000000 0.000000 20.080000 0.120000 ;
      RECT 17.720000 0.000000 18.800000 0.120000 ;
      RECT 16.520000 0.000000 17.520000 0.120000 ;
      RECT 15.240000 0.000000 16.320000 0.120000 ;
      RECT 13.960000 0.000000 15.040000 0.120000 ;
      RECT 12.680000 0.000000 13.760000 0.120000 ;
      RECT 11.480000 0.000000 12.480000 0.120000 ;
      RECT 10.200000 0.000000 11.280000 0.120000 ;
      RECT 8.920000 0.000000 10.000000 0.120000 ;
      RECT 7.640000 0.000000 8.720000 0.120000 ;
      RECT 6.440000 0.000000 7.440000 0.120000 ;
      RECT 5.160000 0.000000 6.240000 0.120000 ;
      RECT 3.880000 0.000000 4.960000 0.120000 ;
      RECT 2.600000 0.000000 3.680000 0.120000 ;
      RECT 1.400000 0.000000 2.400000 0.120000 ;
      RECT 0.200000 0.000000 1.200000 0.120000 ;
    LAYER M6 ;
      RECT 0.000000 180.908000 216.000000 182.016000 ;
      RECT 0.080000 180.788000 215.920000 180.908000 ;
      RECT 0.000000 179.788000 216.000000 180.788000 ;
      RECT 0.080000 179.668000 215.920000 179.788000 ;
      RECT 0.000000 178.668000 216.000000 179.668000 ;
      RECT 0.080000 178.548000 215.920000 178.668000 ;
      RECT 0.000000 177.468000 216.000000 178.548000 ;
      RECT 0.080000 177.348000 215.920000 177.468000 ;
      RECT 0.000000 176.348000 216.000000 177.348000 ;
      RECT 0.080000 176.228000 215.920000 176.348000 ;
      RECT 0.000000 175.148000 216.000000 176.228000 ;
      RECT 0.080000 175.028000 215.920000 175.148000 ;
      RECT 0.000000 174.028000 216.000000 175.028000 ;
      RECT 0.080000 173.908000 215.920000 174.028000 ;
      RECT 0.000000 172.908000 216.000000 173.908000 ;
      RECT 0.080000 172.788000 215.920000 172.908000 ;
      RECT 0.000000 171.708000 216.000000 172.788000 ;
      RECT 0.080000 171.588000 215.920000 171.708000 ;
      RECT 0.000000 170.588000 216.000000 171.588000 ;
      RECT 0.080000 170.468000 215.920000 170.588000 ;
      RECT 0.000000 169.388000 216.000000 170.468000 ;
      RECT 0.080000 169.268000 215.920000 169.388000 ;
      RECT 0.000000 168.268000 216.000000 169.268000 ;
      RECT 0.080000 168.148000 215.920000 168.268000 ;
      RECT 0.000000 167.148000 216.000000 168.148000 ;
      RECT 0.080000 167.028000 215.920000 167.148000 ;
      RECT 0.000000 165.948000 216.000000 167.028000 ;
      RECT 0.080000 165.828000 215.920000 165.948000 ;
      RECT 0.000000 164.828000 216.000000 165.828000 ;
      RECT 0.080000 164.708000 215.920000 164.828000 ;
      RECT 0.000000 163.628000 216.000000 164.708000 ;
      RECT 0.080000 163.508000 215.920000 163.628000 ;
      RECT 0.000000 162.508000 216.000000 163.508000 ;
      RECT 0.080000 162.388000 215.920000 162.508000 ;
      RECT 0.000000 161.388000 216.000000 162.388000 ;
      RECT 0.080000 161.268000 215.920000 161.388000 ;
      RECT 0.000000 160.188000 216.000000 161.268000 ;
      RECT 0.080000 160.068000 215.920000 160.188000 ;
      RECT 0.000000 159.068000 216.000000 160.068000 ;
      RECT 0.080000 158.948000 215.920000 159.068000 ;
      RECT 0.000000 157.868000 216.000000 158.948000 ;
      RECT 0.080000 157.748000 215.920000 157.868000 ;
      RECT 0.000000 156.748000 216.000000 157.748000 ;
      RECT 0.080000 156.628000 215.920000 156.748000 ;
      RECT 0.000000 155.628000 216.000000 156.628000 ;
      RECT 0.080000 155.508000 215.920000 155.628000 ;
      RECT 0.000000 154.428000 216.000000 155.508000 ;
      RECT 0.080000 154.308000 215.920000 154.428000 ;
      RECT 0.000000 153.308000 216.000000 154.308000 ;
      RECT 0.080000 153.188000 215.920000 153.308000 ;
      RECT 0.000000 152.108000 216.000000 153.188000 ;
      RECT 0.080000 151.988000 215.920000 152.108000 ;
      RECT 0.000000 150.988000 216.000000 151.988000 ;
      RECT 0.080000 150.868000 215.920000 150.988000 ;
      RECT 0.000000 149.868000 216.000000 150.868000 ;
      RECT 0.080000 149.748000 215.920000 149.868000 ;
      RECT 0.000000 148.668000 216.000000 149.748000 ;
      RECT 0.080000 148.548000 215.920000 148.668000 ;
      RECT 0.000000 147.548000 216.000000 148.548000 ;
      RECT 0.080000 147.428000 215.920000 147.548000 ;
      RECT 0.000000 146.348000 216.000000 147.428000 ;
      RECT 0.080000 146.228000 215.920000 146.348000 ;
      RECT 0.000000 145.228000 216.000000 146.228000 ;
      RECT 0.080000 145.108000 215.920000 145.228000 ;
      RECT 0.000000 144.108000 216.000000 145.108000 ;
      RECT 0.080000 143.988000 215.920000 144.108000 ;
      RECT 0.000000 142.908000 216.000000 143.988000 ;
      RECT 0.080000 142.788000 215.920000 142.908000 ;
      RECT 0.000000 141.788000 216.000000 142.788000 ;
      RECT 0.080000 141.668000 215.920000 141.788000 ;
      RECT 0.000000 140.588000 216.000000 141.668000 ;
      RECT 0.080000 140.468000 215.920000 140.588000 ;
      RECT 0.000000 139.468000 216.000000 140.468000 ;
      RECT 0.080000 139.348000 215.920000 139.468000 ;
      RECT 0.000000 138.348000 216.000000 139.348000 ;
      RECT 0.080000 138.228000 215.920000 138.348000 ;
      RECT 0.000000 137.148000 216.000000 138.228000 ;
      RECT 0.080000 137.028000 215.920000 137.148000 ;
      RECT 0.000000 136.028000 216.000000 137.028000 ;
      RECT 0.080000 135.908000 215.920000 136.028000 ;
      RECT 0.000000 134.828000 216.000000 135.908000 ;
      RECT 0.080000 134.708000 215.920000 134.828000 ;
      RECT 0.000000 133.708000 216.000000 134.708000 ;
      RECT 0.080000 133.588000 215.920000 133.708000 ;
      RECT 0.000000 132.588000 216.000000 133.588000 ;
      RECT 0.080000 132.468000 215.920000 132.588000 ;
      RECT 0.000000 131.388000 216.000000 132.468000 ;
      RECT 0.080000 131.268000 215.920000 131.388000 ;
      RECT 0.000000 130.268000 216.000000 131.268000 ;
      RECT 0.080000 130.148000 215.920000 130.268000 ;
      RECT 0.000000 129.068000 216.000000 130.148000 ;
      RECT 0.080000 128.948000 215.920000 129.068000 ;
      RECT 0.000000 127.948000 216.000000 128.948000 ;
      RECT 0.080000 127.828000 215.920000 127.948000 ;
      RECT 0.000000 126.828000 216.000000 127.828000 ;
      RECT 0.080000 126.708000 215.920000 126.828000 ;
      RECT 0.000000 125.628000 216.000000 126.708000 ;
      RECT 0.080000 125.508000 215.920000 125.628000 ;
      RECT 0.000000 124.508000 216.000000 125.508000 ;
      RECT 0.080000 124.388000 215.920000 124.508000 ;
      RECT 0.000000 123.308000 216.000000 124.388000 ;
      RECT 0.080000 123.188000 215.920000 123.308000 ;
      RECT 0.000000 122.188000 216.000000 123.188000 ;
      RECT 0.080000 122.068000 215.920000 122.188000 ;
      RECT 0.000000 121.068000 216.000000 122.068000 ;
      RECT 0.080000 120.948000 215.920000 121.068000 ;
      RECT 0.000000 119.868000 216.000000 120.948000 ;
      RECT 0.080000 119.748000 215.920000 119.868000 ;
      RECT 0.000000 118.748000 216.000000 119.748000 ;
      RECT 0.080000 118.628000 215.920000 118.748000 ;
      RECT 0.000000 117.548000 216.000000 118.628000 ;
      RECT 0.080000 117.428000 215.920000 117.548000 ;
      RECT 0.000000 116.428000 216.000000 117.428000 ;
      RECT 0.080000 116.308000 215.920000 116.428000 ;
      RECT 0.000000 115.308000 216.000000 116.308000 ;
      RECT 0.080000 115.188000 215.920000 115.308000 ;
      RECT 0.000000 114.108000 216.000000 115.188000 ;
      RECT 0.080000 113.988000 215.920000 114.108000 ;
      RECT 0.000000 112.988000 216.000000 113.988000 ;
      RECT 0.080000 112.868000 215.920000 112.988000 ;
      RECT 0.000000 111.788000 216.000000 112.868000 ;
      RECT 0.080000 111.668000 215.920000 111.788000 ;
      RECT 0.000000 110.668000 216.000000 111.668000 ;
      RECT 0.080000 110.548000 215.920000 110.668000 ;
      RECT 0.000000 109.548000 216.000000 110.548000 ;
      RECT 0.080000 109.428000 215.920000 109.548000 ;
      RECT 0.000000 108.348000 216.000000 109.428000 ;
      RECT 0.080000 108.228000 215.920000 108.348000 ;
      RECT 0.000000 107.228000 216.000000 108.228000 ;
      RECT 0.080000 107.108000 215.920000 107.228000 ;
      RECT 0.000000 106.028000 216.000000 107.108000 ;
      RECT 0.080000 105.908000 215.920000 106.028000 ;
      RECT 0.000000 104.908000 216.000000 105.908000 ;
      RECT 0.080000 104.788000 215.920000 104.908000 ;
      RECT 0.000000 103.788000 216.000000 104.788000 ;
      RECT 0.080000 103.668000 215.920000 103.788000 ;
      RECT 0.000000 102.588000 216.000000 103.668000 ;
      RECT 0.080000 102.468000 215.920000 102.588000 ;
      RECT 0.000000 101.468000 216.000000 102.468000 ;
      RECT 0.080000 101.348000 215.920000 101.468000 ;
      RECT 0.000000 100.268000 216.000000 101.348000 ;
      RECT 0.080000 100.148000 215.920000 100.268000 ;
      RECT 0.000000 99.148000 216.000000 100.148000 ;
      RECT 0.080000 99.028000 215.920000 99.148000 ;
      RECT 0.000000 98.028000 216.000000 99.028000 ;
      RECT 0.080000 97.908000 215.920000 98.028000 ;
      RECT 0.000000 96.828000 216.000000 97.908000 ;
      RECT 0.080000 96.708000 215.920000 96.828000 ;
      RECT 0.000000 95.708000 216.000000 96.708000 ;
      RECT 0.080000 95.588000 215.920000 95.708000 ;
      RECT 0.000000 94.508000 216.000000 95.588000 ;
      RECT 0.080000 94.388000 215.920000 94.508000 ;
      RECT 0.000000 93.388000 216.000000 94.388000 ;
      RECT 0.080000 93.268000 215.920000 93.388000 ;
      RECT 0.000000 92.268000 216.000000 93.268000 ;
      RECT 0.080000 92.148000 215.920000 92.268000 ;
      RECT 0.000000 91.068000 216.000000 92.148000 ;
      RECT 0.080000 90.948000 215.920000 91.068000 ;
      RECT 0.000000 89.948000 216.000000 90.948000 ;
      RECT 0.080000 89.828000 215.920000 89.948000 ;
      RECT 0.000000 88.748000 216.000000 89.828000 ;
      RECT 0.080000 88.628000 215.920000 88.748000 ;
      RECT 0.000000 87.628000 216.000000 88.628000 ;
      RECT 0.080000 87.508000 215.920000 87.628000 ;
      RECT 0.000000 86.508000 216.000000 87.508000 ;
      RECT 0.080000 86.388000 215.920000 86.508000 ;
      RECT 0.000000 85.308000 216.000000 86.388000 ;
      RECT 0.080000 85.188000 215.920000 85.308000 ;
      RECT 0.000000 84.188000 216.000000 85.188000 ;
      RECT 0.080000 84.068000 215.920000 84.188000 ;
      RECT 0.000000 82.988000 216.000000 84.068000 ;
      RECT 0.080000 82.868000 215.920000 82.988000 ;
      RECT 0.000000 81.868000 216.000000 82.868000 ;
      RECT 0.080000 81.748000 215.920000 81.868000 ;
      RECT 0.000000 80.748000 216.000000 81.748000 ;
      RECT 0.080000 80.628000 215.920000 80.748000 ;
      RECT 0.000000 79.548000 216.000000 80.628000 ;
      RECT 0.080000 79.428000 215.920000 79.548000 ;
      RECT 0.000000 78.428000 216.000000 79.428000 ;
      RECT 0.080000 78.308000 215.920000 78.428000 ;
      RECT 0.000000 77.228000 216.000000 78.308000 ;
      RECT 0.080000 77.108000 215.920000 77.228000 ;
      RECT 0.000000 76.108000 216.000000 77.108000 ;
      RECT 0.080000 75.988000 215.920000 76.108000 ;
      RECT 0.000000 74.988000 216.000000 75.988000 ;
      RECT 0.080000 74.868000 215.920000 74.988000 ;
      RECT 0.000000 73.788000 216.000000 74.868000 ;
      RECT 0.080000 73.668000 215.920000 73.788000 ;
      RECT 0.000000 72.668000 216.000000 73.668000 ;
      RECT 0.080000 72.548000 215.920000 72.668000 ;
      RECT 0.000000 71.468000 216.000000 72.548000 ;
      RECT 0.080000 71.348000 215.920000 71.468000 ;
      RECT 0.000000 70.348000 216.000000 71.348000 ;
      RECT 0.080000 70.228000 215.920000 70.348000 ;
      RECT 0.000000 69.228000 216.000000 70.228000 ;
      RECT 0.080000 69.108000 215.920000 69.228000 ;
      RECT 0.000000 68.028000 216.000000 69.108000 ;
      RECT 0.080000 67.908000 215.920000 68.028000 ;
      RECT 0.000000 66.908000 216.000000 67.908000 ;
      RECT 0.080000 66.788000 215.920000 66.908000 ;
      RECT 0.000000 65.708000 216.000000 66.788000 ;
      RECT 0.080000 65.588000 215.920000 65.708000 ;
      RECT 0.000000 64.588000 216.000000 65.588000 ;
      RECT 0.080000 64.468000 215.920000 64.588000 ;
      RECT 0.000000 63.468000 216.000000 64.468000 ;
      RECT 0.080000 63.348000 215.920000 63.468000 ;
      RECT 0.000000 62.268000 216.000000 63.348000 ;
      RECT 0.080000 62.148000 215.920000 62.268000 ;
      RECT 0.000000 61.148000 216.000000 62.148000 ;
      RECT 0.080000 61.028000 215.920000 61.148000 ;
      RECT 0.000000 59.948000 216.000000 61.028000 ;
      RECT 0.080000 59.828000 215.920000 59.948000 ;
      RECT 0.000000 58.828000 216.000000 59.828000 ;
      RECT 0.080000 58.708000 215.920000 58.828000 ;
      RECT 0.000000 57.708000 216.000000 58.708000 ;
      RECT 0.080000 57.588000 215.920000 57.708000 ;
      RECT 0.000000 56.508000 216.000000 57.588000 ;
      RECT 0.080000 56.388000 215.920000 56.508000 ;
      RECT 0.000000 55.388000 216.000000 56.388000 ;
      RECT 0.080000 55.268000 215.920000 55.388000 ;
      RECT 0.000000 54.188000 216.000000 55.268000 ;
      RECT 0.080000 54.068000 215.920000 54.188000 ;
      RECT 0.000000 53.068000 216.000000 54.068000 ;
      RECT 0.080000 52.948000 215.920000 53.068000 ;
      RECT 0.000000 51.948000 216.000000 52.948000 ;
      RECT 0.080000 51.828000 215.920000 51.948000 ;
      RECT 0.000000 50.748000 216.000000 51.828000 ;
      RECT 0.080000 50.628000 215.920000 50.748000 ;
      RECT 0.000000 49.628000 216.000000 50.628000 ;
      RECT 0.080000 49.508000 215.920000 49.628000 ;
      RECT 0.000000 48.428000 216.000000 49.508000 ;
      RECT 0.080000 48.308000 215.920000 48.428000 ;
      RECT 0.000000 47.308000 216.000000 48.308000 ;
      RECT 0.080000 47.188000 215.920000 47.308000 ;
      RECT 0.000000 46.188000 216.000000 47.188000 ;
      RECT 0.080000 46.068000 215.920000 46.188000 ;
      RECT 0.000000 44.988000 216.000000 46.068000 ;
      RECT 0.080000 44.868000 215.920000 44.988000 ;
      RECT 0.000000 43.868000 216.000000 44.868000 ;
      RECT 0.080000 43.748000 215.920000 43.868000 ;
      RECT 0.000000 42.668000 216.000000 43.748000 ;
      RECT 0.080000 42.548000 215.920000 42.668000 ;
      RECT 0.000000 41.548000 216.000000 42.548000 ;
      RECT 0.080000 41.428000 215.920000 41.548000 ;
      RECT 0.000000 40.428000 216.000000 41.428000 ;
      RECT 0.080000 40.308000 215.920000 40.428000 ;
      RECT 0.000000 39.228000 216.000000 40.308000 ;
      RECT 0.080000 39.108000 215.920000 39.228000 ;
      RECT 0.000000 38.108000 216.000000 39.108000 ;
      RECT 0.080000 37.988000 215.920000 38.108000 ;
      RECT 0.000000 36.908000 216.000000 37.988000 ;
      RECT 0.080000 36.788000 215.920000 36.908000 ;
      RECT 0.000000 35.788000 216.000000 36.788000 ;
      RECT 0.080000 35.668000 215.920000 35.788000 ;
      RECT 0.000000 34.668000 216.000000 35.668000 ;
      RECT 0.080000 34.548000 215.920000 34.668000 ;
      RECT 0.000000 33.468000 216.000000 34.548000 ;
      RECT 0.080000 33.348000 215.920000 33.468000 ;
      RECT 0.000000 32.348000 216.000000 33.348000 ;
      RECT 0.080000 32.228000 215.920000 32.348000 ;
      RECT 0.000000 31.148000 216.000000 32.228000 ;
      RECT 0.080000 31.028000 215.920000 31.148000 ;
      RECT 0.000000 30.028000 216.000000 31.028000 ;
      RECT 0.080000 29.908000 215.920000 30.028000 ;
      RECT 0.000000 28.908000 216.000000 29.908000 ;
      RECT 0.080000 28.788000 215.920000 28.908000 ;
      RECT 0.000000 27.708000 216.000000 28.788000 ;
      RECT 0.080000 27.588000 215.920000 27.708000 ;
      RECT 0.000000 26.588000 216.000000 27.588000 ;
      RECT 0.080000 26.468000 215.920000 26.588000 ;
      RECT 0.000000 25.388000 216.000000 26.468000 ;
      RECT 0.080000 25.268000 215.920000 25.388000 ;
      RECT 0.000000 24.268000 216.000000 25.268000 ;
      RECT 0.080000 24.148000 215.920000 24.268000 ;
      RECT 0.000000 23.148000 216.000000 24.148000 ;
      RECT 0.080000 23.028000 215.920000 23.148000 ;
      RECT 0.000000 21.948000 216.000000 23.028000 ;
      RECT 0.080000 21.828000 215.920000 21.948000 ;
      RECT 0.000000 20.828000 216.000000 21.828000 ;
      RECT 0.080000 20.708000 215.920000 20.828000 ;
      RECT 0.000000 19.628000 216.000000 20.708000 ;
      RECT 0.080000 19.508000 215.920000 19.628000 ;
      RECT 0.000000 18.508000 216.000000 19.508000 ;
      RECT 0.080000 18.388000 215.920000 18.508000 ;
      RECT 0.000000 17.388000 216.000000 18.388000 ;
      RECT 0.080000 17.268000 215.920000 17.388000 ;
      RECT 0.000000 16.188000 216.000000 17.268000 ;
      RECT 0.080000 16.068000 215.920000 16.188000 ;
      RECT 0.000000 15.068000 216.000000 16.068000 ;
      RECT 0.080000 14.948000 215.920000 15.068000 ;
      RECT 0.000000 13.868000 216.000000 14.948000 ;
      RECT 0.080000 13.748000 215.920000 13.868000 ;
      RECT 0.000000 12.748000 216.000000 13.748000 ;
      RECT 0.080000 12.628000 215.920000 12.748000 ;
      RECT 0.000000 11.628000 216.000000 12.628000 ;
      RECT 0.080000 11.508000 215.920000 11.628000 ;
      RECT 0.000000 10.428000 216.000000 11.508000 ;
      RECT 0.080000 10.308000 215.920000 10.428000 ;
      RECT 0.000000 9.308000 216.000000 10.308000 ;
      RECT 0.080000 9.188000 215.920000 9.308000 ;
      RECT 0.000000 8.108000 216.000000 9.188000 ;
      RECT 0.080000 7.988000 215.920000 8.108000 ;
      RECT 0.000000 6.988000 216.000000 7.988000 ;
      RECT 0.080000 6.868000 215.920000 6.988000 ;
      RECT 0.000000 5.868000 216.000000 6.868000 ;
      RECT 0.080000 5.748000 215.920000 5.868000 ;
      RECT 0.000000 4.668000 216.000000 5.748000 ;
      RECT 0.080000 4.548000 215.920000 4.668000 ;
      RECT 0.000000 3.548000 216.000000 4.548000 ;
      RECT 0.080000 3.428000 215.920000 3.548000 ;
      RECT 0.000000 2.348000 216.000000 3.428000 ;
      RECT 0.080000 2.228000 215.920000 2.348000 ;
      RECT 0.000000 1.308000 216.000000 2.228000 ;
      RECT 0.080000 1.188000 215.920000 1.308000 ;
      RECT 0.000000 0.108000 216.000000 1.188000 ;
      RECT 0.080000 0.000000 215.920000 0.108000 ;
    LAYER M7 ;
      RECT 215.680000 181.816000 216.000000 182.016000 ;
      RECT 214.400000 181.816000 215.400000 182.016000 ;
      RECT 213.120000 181.816000 214.120000 182.016000 ;
      RECT 211.840000 181.816000 212.840000 182.016000 ;
      RECT 210.640000 181.816000 211.560000 182.016000 ;
      RECT 209.360000 181.816000 210.360000 182.016000 ;
      RECT 208.080000 181.816000 209.080000 182.016000 ;
      RECT 206.800000 181.816000 207.800000 182.016000 ;
      RECT 205.600000 181.816000 206.520000 182.016000 ;
      RECT 204.320000 181.816000 205.320000 182.016000 ;
      RECT 203.040000 181.816000 204.040000 182.016000 ;
      RECT 201.760000 181.816000 202.760000 182.016000 ;
      RECT 200.560000 181.816000 201.480000 182.016000 ;
      RECT 199.280000 181.816000 200.280000 182.016000 ;
      RECT 198.000000 181.816000 199.000000 182.016000 ;
      RECT 196.720000 181.816000 197.720000 182.016000 ;
      RECT 195.520000 181.816000 196.440000 182.016000 ;
      RECT 194.240000 181.816000 195.240000 182.016000 ;
      RECT 192.960000 181.816000 193.960000 182.016000 ;
      RECT 191.680000 181.816000 192.680000 182.016000 ;
      RECT 190.480000 181.816000 191.400000 182.016000 ;
      RECT 189.200000 181.816000 190.200000 182.016000 ;
      RECT 187.920000 181.816000 188.920000 182.016000 ;
      RECT 186.640000 181.816000 187.640000 182.016000 ;
      RECT 185.440000 181.816000 186.360000 182.016000 ;
      RECT 184.160000 181.816000 185.160000 182.016000 ;
      RECT 182.880000 181.816000 183.880000 182.016000 ;
      RECT 181.600000 181.816000 182.600000 182.016000 ;
      RECT 180.400000 181.816000 181.320000 182.016000 ;
      RECT 179.120000 181.816000 180.120000 182.016000 ;
      RECT 177.840000 181.816000 178.840000 182.016000 ;
      RECT 176.560000 181.816000 177.560000 182.016000 ;
      RECT 175.360000 181.816000 176.280000 182.016000 ;
      RECT 174.080000 181.816000 175.080000 182.016000 ;
      RECT 172.800000 181.816000 173.800000 182.016000 ;
      RECT 171.520000 181.816000 172.520000 182.016000 ;
      RECT 170.320000 181.816000 171.240000 182.016000 ;
      RECT 169.040000 181.816000 170.040000 182.016000 ;
      RECT 167.760000 181.816000 168.760000 182.016000 ;
      RECT 166.480000 181.816000 167.480000 182.016000 ;
      RECT 165.280000 181.816000 166.200000 182.016000 ;
      RECT 164.000000 181.816000 165.000000 182.016000 ;
      RECT 162.720000 181.816000 163.720000 182.016000 ;
      RECT 161.640000 181.816000 162.440000 182.016000 ;
      RECT 160.240000 181.816000 161.160000 182.016000 ;
      RECT 158.960000 181.816000 159.960000 182.016000 ;
      RECT 157.680000 181.816000 158.680000 182.016000 ;
      RECT 156.400000 181.816000 157.400000 182.016000 ;
      RECT 155.200000 181.816000 156.120000 182.016000 ;
      RECT 153.920000 181.816000 154.920000 182.016000 ;
      RECT 152.640000 181.816000 153.640000 182.016000 ;
      RECT 151.360000 181.816000 152.360000 182.016000 ;
      RECT 150.160000 181.816000 151.080000 182.016000 ;
      RECT 148.880000 181.816000 149.880000 182.016000 ;
      RECT 147.600000 181.816000 148.600000 182.016000 ;
      RECT 146.320000 181.816000 147.320000 182.016000 ;
      RECT 145.120000 181.816000 146.040000 182.016000 ;
      RECT 143.840000 181.816000 144.840000 182.016000 ;
      RECT 142.560000 181.816000 143.560000 182.016000 ;
      RECT 141.280000 181.816000 142.280000 182.016000 ;
      RECT 140.080000 181.816000 141.000000 182.016000 ;
      RECT 138.800000 181.816000 139.800000 182.016000 ;
      RECT 137.520000 181.816000 138.520000 182.016000 ;
      RECT 136.240000 181.816000 137.240000 182.016000 ;
      RECT 135.040000 181.816000 135.960000 182.016000 ;
      RECT 133.760000 181.816000 134.760000 182.016000 ;
      RECT 132.480000 181.816000 133.480000 182.016000 ;
      RECT 131.200000 181.816000 132.200000 182.016000 ;
      RECT 130.000000 181.816000 130.920000 182.016000 ;
      RECT 128.720000 181.816000 129.720000 182.016000 ;
      RECT 127.440000 181.816000 128.440000 182.016000 ;
      RECT 126.160000 181.816000 127.160000 182.016000 ;
      RECT 124.960000 181.816000 125.760000 182.016000 ;
      RECT 123.680000 181.816000 124.680000 182.016000 ;
      RECT 122.400000 181.816000 123.400000 182.016000 ;
      RECT 121.120000 181.816000 122.120000 182.016000 ;
      RECT 119.920000 181.816000 120.840000 182.016000 ;
      RECT 118.640000 181.816000 119.640000 182.016000 ;
      RECT 117.360000 181.816000 118.360000 182.016000 ;
      RECT 116.080000 181.816000 117.080000 182.016000 ;
      RECT 114.880000 181.816000 115.800000 182.016000 ;
      RECT 113.600000 181.816000 114.600000 182.016000 ;
      RECT 112.320000 181.816000 113.320000 182.016000 ;
      RECT 111.040000 181.816000 112.040000 182.016000 ;
      RECT 109.840000 181.816000 110.760000 182.016000 ;
      RECT 108.560000 181.816000 109.560000 182.016000 ;
      RECT 107.280000 181.816000 108.280000 182.016000 ;
      RECT 106.000000 181.816000 107.000000 182.016000 ;
      RECT 104.800000 181.816000 105.720000 182.016000 ;
      RECT 103.520000 181.816000 104.520000 182.016000 ;
      RECT 102.240000 181.816000 103.240000 182.016000 ;
      RECT 100.960000 181.816000 101.960000 182.016000 ;
      RECT 99.760000 181.816000 100.680000 182.016000 ;
      RECT 98.480000 181.816000 99.480000 182.016000 ;
      RECT 97.200000 181.816000 98.200000 182.016000 ;
      RECT 95.920000 181.816000 96.920000 182.016000 ;
      RECT 94.720000 181.816000 95.640000 182.016000 ;
      RECT 93.440000 181.816000 94.440000 182.016000 ;
      RECT 92.160000 181.816000 93.160000 182.016000 ;
      RECT 90.880000 181.816000 91.880000 182.016000 ;
      RECT 90.360000 181.816000 90.600000 182.016000 ;
      RECT 89.680000 181.816000 90.160000 182.016000 ;
      RECT 88.400000 181.816000 89.400000 182.016000 ;
      RECT 87.120000 181.816000 88.120000 182.016000 ;
      RECT 85.840000 181.816000 86.840000 182.016000 ;
      RECT 84.640000 181.816000 85.560000 182.016000 ;
      RECT 83.360000 181.816000 84.360000 182.016000 ;
      RECT 82.080000 181.816000 83.080000 182.016000 ;
      RECT 80.800000 181.816000 81.800000 182.016000 ;
      RECT 79.600000 181.816000 80.520000 182.016000 ;
      RECT 78.320000 181.816000 79.320000 182.016000 ;
      RECT 77.040000 181.816000 78.040000 182.016000 ;
      RECT 75.760000 181.816000 76.760000 182.016000 ;
      RECT 74.560000 181.816000 75.480000 182.016000 ;
      RECT 73.280000 181.816000 74.280000 182.016000 ;
      RECT 72.000000 181.816000 73.000000 182.016000 ;
      RECT 70.720000 181.816000 71.720000 182.016000 ;
      RECT 69.520000 181.816000 70.440000 182.016000 ;
      RECT 68.240000 181.816000 69.240000 182.016000 ;
      RECT 66.960000 181.816000 67.960000 182.016000 ;
      RECT 65.680000 181.816000 66.680000 182.016000 ;
      RECT 64.480000 181.816000 65.400000 182.016000 ;
      RECT 63.200000 181.816000 64.200000 182.016000 ;
      RECT 61.920000 181.816000 62.920000 182.016000 ;
      RECT 60.640000 181.816000 61.640000 182.016000 ;
      RECT 59.440000 181.816000 60.360000 182.016000 ;
      RECT 58.160000 181.816000 59.160000 182.016000 ;
      RECT 56.880000 181.816000 57.880000 182.016000 ;
      RECT 55.600000 181.816000 56.600000 182.016000 ;
      RECT 54.760000 181.816000 55.320000 182.016000 ;
      RECT 54.400000 181.816000 54.560000 182.016000 ;
      RECT 53.120000 181.816000 54.120000 182.016000 ;
      RECT 51.840000 181.816000 52.840000 182.016000 ;
      RECT 50.560000 181.816000 51.560000 182.016000 ;
      RECT 49.360000 181.816000 50.280000 182.016000 ;
      RECT 48.080000 181.816000 49.080000 182.016000 ;
      RECT 46.800000 181.816000 47.800000 182.016000 ;
      RECT 45.520000 181.816000 46.520000 182.016000 ;
      RECT 44.320000 181.816000 45.240000 182.016000 ;
      RECT 43.040000 181.816000 44.040000 182.016000 ;
      RECT 41.760000 181.816000 42.760000 182.016000 ;
      RECT 40.480000 181.816000 41.480000 182.016000 ;
      RECT 39.280000 181.816000 40.200000 182.016000 ;
      RECT 38.000000 181.816000 39.000000 182.016000 ;
      RECT 36.720000 181.816000 37.720000 182.016000 ;
      RECT 35.440000 181.816000 36.440000 182.016000 ;
      RECT 34.240000 181.816000 35.160000 182.016000 ;
      RECT 32.960000 181.816000 33.960000 182.016000 ;
      RECT 31.680000 181.816000 32.680000 182.016000 ;
      RECT 30.400000 181.816000 31.400000 182.016000 ;
      RECT 29.200000 181.816000 30.120000 182.016000 ;
      RECT 27.920000 181.816000 28.920000 182.016000 ;
      RECT 26.640000 181.816000 27.640000 182.016000 ;
      RECT 25.360000 181.816000 26.360000 182.016000 ;
      RECT 24.160000 181.816000 25.080000 182.016000 ;
      RECT 22.880000 181.816000 23.880000 182.016000 ;
      RECT 21.600000 181.816000 22.600000 182.016000 ;
      RECT 20.320000 181.816000 21.320000 182.016000 ;
      RECT 19.120000 181.816000 20.040000 182.016000 ;
      RECT 17.840000 181.816000 18.840000 182.016000 ;
      RECT 16.560000 181.816000 17.560000 182.016000 ;
      RECT 15.280000 181.816000 16.280000 182.016000 ;
      RECT 14.080000 181.816000 15.000000 182.016000 ;
      RECT 12.800000 181.816000 13.800000 182.016000 ;
      RECT 11.520000 181.816000 12.520000 182.016000 ;
      RECT 10.240000 181.816000 11.240000 182.016000 ;
      RECT 9.040000 181.816000 9.960000 182.016000 ;
      RECT 7.760000 181.816000 8.760000 182.016000 ;
      RECT 6.480000 181.816000 7.480000 182.016000 ;
      RECT 5.200000 181.816000 6.200000 182.016000 ;
      RECT 4.000000 181.816000 4.920000 182.016000 ;
      RECT 2.720000 181.816000 3.720000 182.016000 ;
      RECT 1.520000 181.816000 2.440000 182.016000 ;
      RECT 0.240000 181.816000 1.240000 182.016000 ;
      RECT 161.640000 181.541000 216.000000 181.816000 ;
      RECT 125.960000 181.541000 161.440000 181.816000 ;
      RECT 90.360000 181.541000 125.760000 181.816000 ;
      RECT 54.760000 181.541000 90.160000 181.816000 ;
      RECT 0.000000 181.541000 54.560000 181.816000 ;
      RECT 0.000000 0.200000 216.000000 181.541000 ;
      RECT 215.680000 0.000000 216.000000 0.200000 ;
      RECT 214.400000 0.000000 215.400000 0.200000 ;
      RECT 213.120000 0.000000 214.120000 0.200000 ;
      RECT 211.840000 0.000000 212.840000 0.200000 ;
      RECT 210.640000 0.000000 211.560000 0.200000 ;
      RECT 209.360000 0.000000 210.360000 0.200000 ;
      RECT 208.080000 0.000000 209.080000 0.200000 ;
      RECT 206.800000 0.000000 207.800000 0.200000 ;
      RECT 205.600000 0.000000 206.520000 0.200000 ;
      RECT 204.320000 0.000000 205.320000 0.200000 ;
      RECT 203.040000 0.000000 204.040000 0.200000 ;
      RECT 201.760000 0.000000 202.760000 0.200000 ;
      RECT 200.560000 0.000000 201.480000 0.200000 ;
      RECT 199.280000 0.000000 200.280000 0.200000 ;
      RECT 198.000000 0.000000 199.000000 0.200000 ;
      RECT 196.720000 0.000000 197.720000 0.200000 ;
      RECT 195.520000 0.000000 196.440000 0.200000 ;
      RECT 194.240000 0.000000 195.240000 0.200000 ;
      RECT 192.960000 0.000000 193.960000 0.200000 ;
      RECT 191.680000 0.000000 192.680000 0.200000 ;
      RECT 190.480000 0.000000 191.400000 0.200000 ;
      RECT 189.200000 0.000000 190.200000 0.200000 ;
      RECT 187.920000 0.000000 188.920000 0.200000 ;
      RECT 186.640000 0.000000 187.640000 0.200000 ;
      RECT 185.440000 0.000000 186.360000 0.200000 ;
      RECT 184.160000 0.000000 185.160000 0.200000 ;
      RECT 182.880000 0.000000 183.880000 0.200000 ;
      RECT 181.600000 0.000000 182.600000 0.200000 ;
      RECT 180.400000 0.000000 181.320000 0.200000 ;
      RECT 179.120000 0.000000 180.120000 0.200000 ;
      RECT 177.840000 0.000000 178.840000 0.200000 ;
      RECT 176.560000 0.000000 177.560000 0.200000 ;
      RECT 175.360000 0.000000 176.280000 0.200000 ;
      RECT 174.080000 0.000000 175.080000 0.200000 ;
      RECT 172.800000 0.000000 173.800000 0.200000 ;
      RECT 171.520000 0.000000 172.520000 0.200000 ;
      RECT 170.320000 0.000000 171.240000 0.200000 ;
      RECT 169.040000 0.000000 170.040000 0.200000 ;
      RECT 167.760000 0.000000 168.760000 0.200000 ;
      RECT 166.480000 0.000000 167.480000 0.200000 ;
      RECT 165.280000 0.000000 166.200000 0.200000 ;
      RECT 164.000000 0.000000 165.000000 0.200000 ;
      RECT 162.720000 0.000000 163.720000 0.200000 ;
      RECT 161.440000 0.000000 162.440000 0.200000 ;
      RECT 160.240000 0.000000 161.160000 0.200000 ;
      RECT 158.960000 0.000000 159.960000 0.200000 ;
      RECT 157.680000 0.000000 158.680000 0.200000 ;
      RECT 156.400000 0.000000 157.400000 0.200000 ;
      RECT 155.200000 0.000000 156.120000 0.200000 ;
      RECT 153.920000 0.000000 154.920000 0.200000 ;
      RECT 152.640000 0.000000 153.640000 0.200000 ;
      RECT 151.360000 0.000000 152.360000 0.200000 ;
      RECT 150.160000 0.000000 151.080000 0.200000 ;
      RECT 148.880000 0.000000 149.880000 0.200000 ;
      RECT 147.600000 0.000000 148.600000 0.200000 ;
      RECT 146.320000 0.000000 147.320000 0.200000 ;
      RECT 145.120000 0.000000 146.040000 0.200000 ;
      RECT 143.840000 0.000000 144.840000 0.200000 ;
      RECT 142.560000 0.000000 143.560000 0.200000 ;
      RECT 141.280000 0.000000 142.280000 0.200000 ;
      RECT 140.080000 0.000000 141.000000 0.200000 ;
      RECT 138.800000 0.000000 139.800000 0.200000 ;
      RECT 137.520000 0.000000 138.520000 0.200000 ;
      RECT 136.240000 0.000000 137.240000 0.200000 ;
      RECT 135.040000 0.000000 135.960000 0.200000 ;
      RECT 133.760000 0.000000 134.760000 0.200000 ;
      RECT 132.480000 0.000000 133.480000 0.200000 ;
      RECT 131.200000 0.000000 132.200000 0.200000 ;
      RECT 130.000000 0.000000 130.920000 0.200000 ;
      RECT 128.720000 0.000000 129.720000 0.200000 ;
      RECT 127.440000 0.000000 128.440000 0.200000 ;
      RECT 126.160000 0.000000 127.160000 0.200000 ;
      RECT 124.960000 0.000000 125.880000 0.200000 ;
      RECT 123.680000 0.000000 124.680000 0.200000 ;
      RECT 122.400000 0.000000 123.400000 0.200000 ;
      RECT 121.120000 0.000000 122.120000 0.200000 ;
      RECT 119.920000 0.000000 120.840000 0.200000 ;
      RECT 118.640000 0.000000 119.640000 0.200000 ;
      RECT 117.360000 0.000000 118.360000 0.200000 ;
      RECT 116.080000 0.000000 117.080000 0.200000 ;
      RECT 114.880000 0.000000 115.800000 0.200000 ;
      RECT 113.600000 0.000000 114.600000 0.200000 ;
      RECT 112.320000 0.000000 113.320000 0.200000 ;
      RECT 111.040000 0.000000 112.040000 0.200000 ;
      RECT 109.840000 0.000000 110.760000 0.200000 ;
      RECT 108.560000 0.000000 109.560000 0.200000 ;
      RECT 107.280000 0.000000 108.280000 0.200000 ;
      RECT 106.000000 0.000000 107.000000 0.200000 ;
      RECT 104.800000 0.000000 105.720000 0.200000 ;
      RECT 103.520000 0.000000 104.520000 0.200000 ;
      RECT 102.240000 0.000000 103.240000 0.200000 ;
      RECT 100.960000 0.000000 101.960000 0.200000 ;
      RECT 99.760000 0.000000 100.680000 0.200000 ;
      RECT 98.480000 0.000000 99.480000 0.200000 ;
      RECT 97.200000 0.000000 98.200000 0.200000 ;
      RECT 95.920000 0.000000 96.920000 0.200000 ;
      RECT 94.720000 0.000000 95.640000 0.200000 ;
      RECT 93.440000 0.000000 94.440000 0.200000 ;
      RECT 92.160000 0.000000 93.160000 0.200000 ;
      RECT 90.880000 0.000000 91.880000 0.200000 ;
      RECT 89.680000 0.000000 90.600000 0.200000 ;
      RECT 88.400000 0.000000 89.400000 0.200000 ;
      RECT 87.120000 0.000000 88.120000 0.200000 ;
      RECT 85.840000 0.000000 86.840000 0.200000 ;
      RECT 84.640000 0.000000 85.560000 0.200000 ;
      RECT 83.360000 0.000000 84.360000 0.200000 ;
      RECT 82.080000 0.000000 83.080000 0.200000 ;
      RECT 80.800000 0.000000 81.800000 0.200000 ;
      RECT 79.600000 0.000000 80.520000 0.200000 ;
      RECT 78.320000 0.000000 79.320000 0.200000 ;
      RECT 77.040000 0.000000 78.040000 0.200000 ;
      RECT 75.760000 0.000000 76.760000 0.200000 ;
      RECT 74.560000 0.000000 75.480000 0.200000 ;
      RECT 73.280000 0.000000 74.280000 0.200000 ;
      RECT 72.000000 0.000000 73.000000 0.200000 ;
      RECT 70.720000 0.000000 71.720000 0.200000 ;
      RECT 69.520000 0.000000 70.440000 0.200000 ;
      RECT 68.240000 0.000000 69.240000 0.200000 ;
      RECT 66.960000 0.000000 67.960000 0.200000 ;
      RECT 65.680000 0.000000 66.680000 0.200000 ;
      RECT 64.480000 0.000000 65.400000 0.200000 ;
      RECT 63.200000 0.000000 64.200000 0.200000 ;
      RECT 61.920000 0.000000 62.920000 0.200000 ;
      RECT 60.640000 0.000000 61.640000 0.200000 ;
      RECT 59.440000 0.000000 60.360000 0.200000 ;
      RECT 58.160000 0.000000 59.160000 0.200000 ;
      RECT 56.880000 0.000000 57.880000 0.200000 ;
      RECT 55.600000 0.000000 56.600000 0.200000 ;
      RECT 54.400000 0.000000 55.320000 0.200000 ;
      RECT 53.120000 0.000000 54.120000 0.200000 ;
      RECT 51.840000 0.000000 52.840000 0.200000 ;
      RECT 50.560000 0.000000 51.560000 0.200000 ;
      RECT 49.360000 0.000000 50.280000 0.200000 ;
      RECT 48.080000 0.000000 49.080000 0.200000 ;
      RECT 46.800000 0.000000 47.800000 0.200000 ;
      RECT 45.520000 0.000000 46.520000 0.200000 ;
      RECT 44.320000 0.000000 45.240000 0.200000 ;
      RECT 43.040000 0.000000 44.040000 0.200000 ;
      RECT 41.760000 0.000000 42.760000 0.200000 ;
      RECT 40.480000 0.000000 41.480000 0.200000 ;
      RECT 39.280000 0.000000 40.200000 0.200000 ;
      RECT 38.000000 0.000000 39.000000 0.200000 ;
      RECT 36.720000 0.000000 37.720000 0.200000 ;
      RECT 35.440000 0.000000 36.440000 0.200000 ;
      RECT 34.240000 0.000000 35.160000 0.200000 ;
      RECT 32.960000 0.000000 33.960000 0.200000 ;
      RECT 31.680000 0.000000 32.680000 0.200000 ;
      RECT 30.400000 0.000000 31.400000 0.200000 ;
      RECT 29.200000 0.000000 30.120000 0.200000 ;
      RECT 27.920000 0.000000 28.920000 0.200000 ;
      RECT 26.640000 0.000000 27.640000 0.200000 ;
      RECT 25.360000 0.000000 26.360000 0.200000 ;
      RECT 24.160000 0.000000 25.080000 0.200000 ;
      RECT 22.880000 0.000000 23.880000 0.200000 ;
      RECT 21.600000 0.000000 22.600000 0.200000 ;
      RECT 20.320000 0.000000 21.320000 0.200000 ;
      RECT 19.120000 0.000000 20.040000 0.200000 ;
      RECT 17.840000 0.000000 18.840000 0.200000 ;
      RECT 16.560000 0.000000 17.560000 0.200000 ;
      RECT 15.280000 0.000000 16.280000 0.200000 ;
      RECT 14.080000 0.000000 15.000000 0.200000 ;
      RECT 12.800000 0.000000 13.800000 0.200000 ;
      RECT 11.520000 0.000000 12.520000 0.200000 ;
      RECT 10.240000 0.000000 11.240000 0.200000 ;
      RECT 9.040000 0.000000 9.960000 0.200000 ;
      RECT 7.760000 0.000000 8.760000 0.200000 ;
      RECT 6.480000 0.000000 7.480000 0.200000 ;
      RECT 5.200000 0.000000 6.200000 0.200000 ;
      RECT 4.000000 0.000000 4.920000 0.200000 ;
      RECT 2.720000 0.000000 3.720000 0.200000 ;
      RECT 1.520000 0.000000 2.440000 0.200000 ;
      RECT 0.240000 0.000000 1.240000 0.200000 ;
    LAYER M8 ;
      RECT 0.000000 180.977000 216.000000 182.016000 ;
      RECT 0.000000 179.843000 216.000000 180.787000 ;
      RECT 0.000000 178.709000 216.000000 179.653000 ;
      RECT 0.000000 177.575000 216.000000 178.519000 ;
      RECT 0.000000 176.441000 216.000000 177.385000 ;
      RECT 0.000000 175.181000 216.000000 176.251000 ;
      RECT 0.000000 174.047000 216.000000 174.991000 ;
      RECT 0.000000 172.913000 216.000000 173.857000 ;
      RECT 0.000000 171.779000 216.000000 172.723000 ;
      RECT 0.000000 170.645000 216.000000 171.589000 ;
      RECT 0.000000 169.511000 216.000000 170.455000 ;
      RECT 0.000000 168.377000 216.000000 169.321000 ;
      RECT 0.000000 167.117000 216.000000 168.187000 ;
      RECT 0.000000 165.983000 216.000000 166.927000 ;
      RECT 0.000000 164.849000 216.000000 165.793000 ;
      RECT 0.000000 163.715000 216.000000 164.659000 ;
      RECT 0.000000 162.581000 216.000000 163.525000 ;
      RECT 0.000000 161.447000 216.000000 162.391000 ;
      RECT 0.000000 160.313000 216.000000 161.257000 ;
      RECT 0.000000 159.053000 216.000000 160.123000 ;
      RECT 0.000000 157.919000 216.000000 158.863000 ;
      RECT 0.000000 156.785000 216.000000 157.729000 ;
      RECT 0.000000 155.651000 216.000000 156.595000 ;
      RECT 0.000000 154.517000 216.000000 155.461000 ;
      RECT 0.000000 153.383000 216.000000 154.327000 ;
      RECT 0.000000 152.249000 216.000000 153.193000 ;
      RECT 0.000000 150.989000 216.000000 152.059000 ;
      RECT 0.000000 149.855000 216.000000 150.799000 ;
      RECT 0.000000 148.721000 216.000000 149.665000 ;
      RECT 0.000000 147.587000 216.000000 148.531000 ;
      RECT 0.000000 146.453000 216.000000 147.397000 ;
      RECT 0.000000 145.319000 216.000000 146.263000 ;
      RECT 0.000000 144.185000 216.000000 145.129000 ;
      RECT 0.000000 142.925000 216.000000 143.995000 ;
      RECT 0.000000 141.791000 216.000000 142.735000 ;
      RECT 0.000000 140.657000 216.000000 141.601000 ;
      RECT 0.000000 139.523000 216.000000 140.467000 ;
      RECT 0.000000 138.389000 216.000000 139.333000 ;
      RECT 0.000000 137.255000 216.000000 138.199000 ;
      RECT 0.000000 136.121000 216.000000 137.065000 ;
      RECT 0.000000 134.861000 216.000000 135.931000 ;
      RECT 0.000000 133.727000 216.000000 134.671000 ;
      RECT 0.000000 132.593000 216.000000 133.537000 ;
      RECT 0.000000 131.459000 216.000000 132.403000 ;
      RECT 0.000000 130.325000 216.000000 131.269000 ;
      RECT 0.000000 129.191000 216.000000 130.135000 ;
      RECT 0.000000 128.057000 216.000000 129.001000 ;
      RECT 0.000000 126.797000 216.000000 127.867000 ;
      RECT 0.000000 125.663000 216.000000 126.607000 ;
      RECT 0.000000 124.529000 216.000000 125.473000 ;
      RECT 0.000000 123.395000 216.000000 124.339000 ;
      RECT 0.000000 122.261000 216.000000 123.205000 ;
      RECT 0.000000 121.127000 216.000000 122.071000 ;
      RECT 0.000000 119.993000 216.000000 120.937000 ;
      RECT 0.000000 118.733000 216.000000 119.803000 ;
      RECT 0.000000 117.599000 216.000000 118.543000 ;
      RECT 0.000000 116.465000 216.000000 117.409000 ;
      RECT 0.000000 115.331000 216.000000 116.275000 ;
      RECT 0.000000 114.197000 216.000000 115.141000 ;
      RECT 0.000000 113.063000 216.000000 114.007000 ;
      RECT 0.000000 111.929000 216.000000 112.873000 ;
      RECT 0.000000 110.669000 216.000000 111.739000 ;
      RECT 0.000000 109.535000 216.000000 110.479000 ;
      RECT 0.000000 108.401000 216.000000 109.345000 ;
      RECT 0.000000 107.267000 216.000000 108.211000 ;
      RECT 0.000000 106.133000 216.000000 107.077000 ;
      RECT 0.000000 104.999000 216.000000 105.943000 ;
      RECT 0.000000 103.865000 216.000000 104.809000 ;
      RECT 0.000000 102.605000 216.000000 103.675000 ;
      RECT 0.000000 101.471000 216.000000 102.415000 ;
      RECT 0.000000 100.337000 216.000000 101.281000 ;
      RECT 0.000000 99.203000 216.000000 100.147000 ;
      RECT 0.000000 98.069000 216.000000 99.013000 ;
      RECT 0.000000 96.935000 216.000000 97.879000 ;
      RECT 0.000000 95.801000 216.000000 96.745000 ;
      RECT 0.000000 94.541000 216.000000 95.611000 ;
      RECT 0.000000 93.407000 216.000000 94.351000 ;
      RECT 0.000000 92.273000 216.000000 93.217000 ;
      RECT 0.000000 91.139000 216.000000 92.083000 ;
      RECT 0.000000 90.005000 216.000000 90.949000 ;
      RECT 0.000000 88.871000 216.000000 89.815000 ;
      RECT 0.000000 87.737000 216.000000 88.681000 ;
      RECT 0.000000 86.477000 216.000000 87.547000 ;
      RECT 0.000000 85.343000 216.000000 86.287000 ;
      RECT 0.000000 84.209000 216.000000 85.153000 ;
      RECT 0.000000 83.075000 216.000000 84.019000 ;
      RECT 0.000000 81.941000 216.000000 82.885000 ;
      RECT 0.000000 80.807000 216.000000 81.751000 ;
      RECT 0.000000 79.673000 216.000000 80.617000 ;
      RECT 0.000000 78.413000 216.000000 79.483000 ;
      RECT 0.000000 77.279000 216.000000 78.223000 ;
      RECT 0.000000 76.145000 216.000000 77.089000 ;
      RECT 0.000000 75.011000 216.000000 75.955000 ;
      RECT 0.000000 73.877000 216.000000 74.821000 ;
      RECT 0.000000 72.743000 216.000000 73.687000 ;
      RECT 0.000000 71.609000 216.000000 72.553000 ;
      RECT 0.000000 70.349000 216.000000 71.419000 ;
      RECT 0.000000 69.215000 216.000000 70.159000 ;
      RECT 0.000000 68.081000 216.000000 69.025000 ;
      RECT 0.000000 66.947000 216.000000 67.891000 ;
      RECT 0.000000 65.813000 216.000000 66.757000 ;
      RECT 0.000000 64.679000 216.000000 65.623000 ;
      RECT 0.000000 63.545000 216.000000 64.489000 ;
      RECT 0.000000 62.285000 216.000000 63.355000 ;
      RECT 0.000000 61.151000 216.000000 62.095000 ;
      RECT 0.000000 60.017000 216.000000 60.961000 ;
      RECT 0.000000 58.883000 216.000000 59.827000 ;
      RECT 0.000000 57.749000 216.000000 58.693000 ;
      RECT 0.000000 56.615000 216.000000 57.559000 ;
      RECT 0.000000 55.481000 216.000000 56.425000 ;
      RECT 0.000000 54.221000 216.000000 55.291000 ;
      RECT 0.000000 53.087000 216.000000 54.031000 ;
      RECT 0.000000 51.953000 216.000000 52.897000 ;
      RECT 0.000000 50.819000 216.000000 51.763000 ;
      RECT 0.000000 49.685000 216.000000 50.629000 ;
      RECT 0.000000 48.551000 216.000000 49.495000 ;
      RECT 0.000000 47.417000 216.000000 48.361000 ;
      RECT 0.000000 46.157000 216.000000 47.227000 ;
      RECT 0.000000 45.023000 216.000000 45.967000 ;
      RECT 0.000000 43.889000 216.000000 44.833000 ;
      RECT 0.000000 42.755000 216.000000 43.699000 ;
      RECT 0.000000 41.621000 216.000000 42.565000 ;
      RECT 0.000000 40.487000 216.000000 41.431000 ;
      RECT 0.000000 39.353000 216.000000 40.297000 ;
      RECT 0.000000 38.093000 216.000000 39.163000 ;
      RECT 0.000000 36.959000 216.000000 37.903000 ;
      RECT 0.000000 35.825000 216.000000 36.769000 ;
      RECT 0.000000 34.691000 216.000000 35.635000 ;
      RECT 0.000000 33.557000 216.000000 34.501000 ;
      RECT 0.000000 32.423000 216.000000 33.367000 ;
      RECT 0.000000 31.289000 216.000000 32.233000 ;
      RECT 0.000000 30.029000 216.000000 31.099000 ;
      RECT 0.000000 28.895000 216.000000 29.839000 ;
      RECT 0.000000 27.761000 216.000000 28.705000 ;
      RECT 0.000000 26.627000 216.000000 27.571000 ;
      RECT 0.000000 25.493000 216.000000 26.437000 ;
      RECT 0.000000 24.359000 216.000000 25.303000 ;
      RECT 0.000000 23.225000 216.000000 24.169000 ;
      RECT 0.000000 21.965000 216.000000 23.035000 ;
      RECT 0.000000 20.831000 216.000000 21.775000 ;
      RECT 0.000000 19.697000 216.000000 20.641000 ;
      RECT 0.000000 18.563000 216.000000 19.507000 ;
      RECT 0.000000 17.429000 216.000000 18.373000 ;
      RECT 0.000000 16.295000 216.000000 17.239000 ;
      RECT 0.000000 15.161000 216.000000 16.105000 ;
      RECT 0.000000 13.901000 216.000000 14.971000 ;
      RECT 0.000000 12.767000 216.000000 13.711000 ;
      RECT 0.000000 11.633000 216.000000 12.577000 ;
      RECT 0.000000 10.499000 216.000000 11.443000 ;
      RECT 0.000000 9.365000 216.000000 10.309000 ;
      RECT 0.000000 8.231000 216.000000 9.175000 ;
      RECT 0.000000 7.097000 216.000000 8.041000 ;
      RECT 0.000000 5.837000 216.000000 6.907000 ;
      RECT 0.000000 4.703000 216.000000 5.647000 ;
      RECT 0.000000 3.569000 216.000000 4.513000 ;
      RECT 0.000000 2.435000 216.000000 3.379000 ;
      RECT 0.000000 1.301000 216.000000 2.245000 ;
      RECT 0.000000 0.167000 216.000000 1.111000 ;
    LAYER M9 ;
      RECT 214.776000 181.431000 215.316000 182.016000 ;
      RECT 213.516000 181.431000 214.056000 182.016000 ;
      RECT 212.256000 181.431000 212.796000 182.016000 ;
      RECT 210.996000 181.431000 211.536000 182.016000 ;
      RECT 209.736000 181.431000 210.276000 182.016000 ;
      RECT 208.476000 181.431000 209.016000 182.016000 ;
      RECT 207.216000 181.431000 207.756000 182.016000 ;
      RECT 205.956000 181.431000 206.496000 182.016000 ;
      RECT 204.696000 181.431000 205.236000 182.016000 ;
      RECT 203.436000 181.431000 203.976000 182.016000 ;
      RECT 202.176000 181.431000 202.716000 182.016000 ;
      RECT 200.916000 181.431000 201.456000 182.016000 ;
      RECT 199.656000 181.431000 200.196000 182.016000 ;
      RECT 198.396000 181.431000 198.936000 182.016000 ;
      RECT 197.136000 181.431000 197.676000 182.016000 ;
      RECT 195.876000 181.431000 196.416000 182.016000 ;
      RECT 194.616000 181.431000 195.156000 182.016000 ;
      RECT 193.356000 181.431000 193.896000 182.016000 ;
      RECT 192.096000 181.431000 192.636000 182.016000 ;
      RECT 190.836000 181.431000 191.376000 182.016000 ;
      RECT 189.576000 181.431000 190.116000 182.016000 ;
      RECT 188.316000 181.431000 188.856000 182.016000 ;
      RECT 187.056000 181.431000 187.596000 182.016000 ;
      RECT 185.796000 181.431000 186.336000 182.016000 ;
      RECT 184.536000 181.431000 185.076000 182.016000 ;
      RECT 183.276000 181.431000 183.816000 182.016000 ;
      RECT 182.016000 181.431000 182.556000 182.016000 ;
      RECT 180.756000 181.431000 181.296000 182.016000 ;
      RECT 179.496000 181.431000 180.036000 182.016000 ;
      RECT 178.236000 181.431000 178.776000 182.016000 ;
      RECT 176.976000 181.431000 177.516000 182.016000 ;
      RECT 175.716000 181.431000 176.256000 182.016000 ;
      RECT 174.456000 181.431000 174.996000 182.016000 ;
      RECT 173.196000 181.431000 173.736000 182.016000 ;
      RECT 171.936000 181.431000 172.476000 182.016000 ;
      RECT 170.676000 181.431000 171.216000 182.016000 ;
      RECT 169.416000 181.431000 169.956000 182.016000 ;
      RECT 168.156000 181.431000 168.696000 182.016000 ;
      RECT 166.896000 181.431000 167.436000 182.016000 ;
      RECT 165.636000 181.431000 166.176000 182.016000 ;
      RECT 164.376000 181.431000 164.916000 182.016000 ;
      RECT 163.116000 181.431000 163.656000 182.016000 ;
      RECT 161.856000 181.431000 162.396000 182.016000 ;
      RECT 160.596000 181.431000 161.136000 182.016000 ;
      RECT 159.336000 181.431000 159.876000 182.016000 ;
      RECT 158.076000 181.431000 158.616000 182.016000 ;
      RECT 156.816000 181.431000 157.356000 182.016000 ;
      RECT 155.556000 181.431000 156.096000 182.016000 ;
      RECT 154.296000 181.431000 154.836000 182.016000 ;
      RECT 153.036000 181.431000 153.576000 182.016000 ;
      RECT 151.776000 181.431000 152.316000 182.016000 ;
      RECT 150.516000 181.431000 151.056000 182.016000 ;
      RECT 149.256000 181.431000 149.796000 182.016000 ;
      RECT 147.996000 181.431000 148.536000 182.016000 ;
      RECT 146.736000 181.431000 147.276000 182.016000 ;
      RECT 145.476000 181.431000 146.016000 182.016000 ;
      RECT 144.216000 181.431000 144.756000 182.016000 ;
      RECT 142.956000 181.431000 143.496000 182.016000 ;
      RECT 141.696000 181.431000 142.236000 182.016000 ;
      RECT 140.436000 181.431000 140.976000 182.016000 ;
      RECT 139.176000 181.431000 139.716000 182.016000 ;
      RECT 137.916000 181.431000 138.456000 182.016000 ;
      RECT 136.656000 181.431000 137.196000 182.016000 ;
      RECT 135.396000 181.431000 135.936000 182.016000 ;
      RECT 134.136000 181.431000 134.676000 182.016000 ;
      RECT 132.876000 181.431000 133.416000 182.016000 ;
      RECT 131.616000 181.431000 132.156000 182.016000 ;
      RECT 130.356000 181.431000 130.896000 182.016000 ;
      RECT 129.096000 181.431000 129.636000 182.016000 ;
      RECT 127.836000 181.431000 128.376000 182.016000 ;
      RECT 126.576000 181.431000 127.116000 182.016000 ;
      RECT 125.316000 181.431000 125.856000 182.016000 ;
      RECT 124.056000 181.431000 124.596000 182.016000 ;
      RECT 122.796000 181.431000 123.336000 182.016000 ;
      RECT 121.536000 181.431000 122.076000 182.016000 ;
      RECT 120.276000 181.431000 120.816000 182.016000 ;
      RECT 119.016000 181.431000 119.556000 182.016000 ;
      RECT 117.756000 181.431000 118.296000 182.016000 ;
      RECT 116.496000 181.431000 117.036000 182.016000 ;
      RECT 115.236000 181.431000 115.776000 182.016000 ;
      RECT 113.976000 181.431000 114.516000 182.016000 ;
      RECT 112.716000 181.431000 113.256000 182.016000 ;
      RECT 111.456000 181.431000 111.996000 182.016000 ;
      RECT 110.196000 181.431000 110.736000 182.016000 ;
      RECT 108.936000 181.431000 109.476000 182.016000 ;
      RECT 107.676000 181.431000 108.216000 182.016000 ;
      RECT 106.416000 181.431000 106.956000 182.016000 ;
      RECT 105.156000 181.431000 105.696000 182.016000 ;
      RECT 103.896000 181.431000 104.436000 182.016000 ;
      RECT 102.636000 181.431000 103.176000 182.016000 ;
      RECT 101.376000 181.431000 101.916000 182.016000 ;
      RECT 100.116000 181.431000 100.656000 182.016000 ;
      RECT 98.856000 181.431000 99.396000 182.016000 ;
      RECT 97.596000 181.431000 98.136000 182.016000 ;
      RECT 96.336000 181.431000 96.876000 182.016000 ;
      RECT 95.076000 181.431000 95.616000 182.016000 ;
      RECT 93.816000 181.431000 94.356000 182.016000 ;
      RECT 92.556000 181.431000 93.096000 182.016000 ;
      RECT 91.296000 181.431000 91.836000 182.016000 ;
      RECT 90.036000 181.431000 90.576000 182.016000 ;
      RECT 88.776000 181.431000 89.316000 182.016000 ;
      RECT 87.516000 181.431000 88.056000 182.016000 ;
      RECT 86.256000 181.431000 86.796000 182.016000 ;
      RECT 84.996000 181.431000 85.536000 182.016000 ;
      RECT 83.736000 181.431000 84.276000 182.016000 ;
      RECT 82.476000 181.431000 83.016000 182.016000 ;
      RECT 81.216000 181.431000 81.756000 182.016000 ;
      RECT 79.956000 181.431000 80.496000 182.016000 ;
      RECT 78.696000 181.431000 79.236000 182.016000 ;
      RECT 77.436000 181.431000 77.976000 182.016000 ;
      RECT 76.176000 181.431000 76.716000 182.016000 ;
      RECT 74.916000 181.431000 75.456000 182.016000 ;
      RECT 73.656000 181.431000 74.196000 182.016000 ;
      RECT 72.396000 181.431000 72.936000 182.016000 ;
      RECT 71.136000 181.431000 71.676000 182.016000 ;
      RECT 69.876000 181.431000 70.416000 182.016000 ;
      RECT 68.616000 181.431000 69.156000 182.016000 ;
      RECT 67.356000 181.431000 67.896000 182.016000 ;
      RECT 66.096000 181.431000 66.636000 182.016000 ;
      RECT 64.836000 181.431000 65.376000 182.016000 ;
      RECT 63.576000 181.431000 64.116000 182.016000 ;
      RECT 62.316000 181.431000 62.856000 182.016000 ;
      RECT 61.056000 181.431000 61.596000 182.016000 ;
      RECT 59.796000 181.431000 60.336000 182.016000 ;
      RECT 58.536000 181.431000 59.076000 182.016000 ;
      RECT 57.276000 181.431000 57.816000 182.016000 ;
      RECT 56.016000 181.431000 56.556000 182.016000 ;
      RECT 54.756000 181.431000 55.296000 182.016000 ;
      RECT 53.496000 181.431000 54.036000 182.016000 ;
      RECT 52.236000 181.431000 52.776000 182.016000 ;
      RECT 50.976000 181.431000 51.516000 182.016000 ;
      RECT 49.716000 181.431000 50.256000 182.016000 ;
      RECT 48.456000 181.431000 48.996000 182.016000 ;
      RECT 47.196000 181.431000 47.736000 182.016000 ;
      RECT 45.936000 181.431000 46.476000 182.016000 ;
      RECT 44.676000 181.431000 45.216000 182.016000 ;
      RECT 43.416000 181.431000 43.956000 182.016000 ;
      RECT 42.156000 181.431000 42.696000 182.016000 ;
      RECT 40.896000 181.431000 41.436000 182.016000 ;
      RECT 39.636000 181.431000 40.176000 182.016000 ;
      RECT 38.376000 181.431000 38.916000 182.016000 ;
      RECT 37.116000 181.431000 37.656000 182.016000 ;
      RECT 35.856000 181.431000 36.396000 182.016000 ;
      RECT 34.596000 181.431000 35.136000 182.016000 ;
      RECT 33.336000 181.431000 33.876000 182.016000 ;
      RECT 32.076000 181.431000 32.616000 182.016000 ;
      RECT 30.816000 181.431000 31.356000 182.016000 ;
      RECT 29.556000 181.431000 30.096000 182.016000 ;
      RECT 28.296000 181.431000 28.836000 182.016000 ;
      RECT 27.036000 181.431000 27.576000 182.016000 ;
      RECT 25.776000 181.431000 26.316000 182.016000 ;
      RECT 24.516000 181.431000 25.056000 182.016000 ;
      RECT 23.256000 181.431000 23.796000 182.016000 ;
      RECT 21.996000 181.431000 22.536000 182.016000 ;
      RECT 20.736000 181.431000 21.276000 182.016000 ;
      RECT 19.476000 181.431000 20.016000 182.016000 ;
      RECT 18.216000 181.431000 18.756000 182.016000 ;
      RECT 16.956000 181.431000 17.496000 182.016000 ;
      RECT 15.696000 181.431000 16.236000 182.016000 ;
      RECT 14.436000 181.431000 14.976000 182.016000 ;
      RECT 13.176000 181.431000 13.716000 182.016000 ;
      RECT 11.916000 181.431000 12.456000 182.016000 ;
      RECT 10.656000 181.431000 11.196000 182.016000 ;
      RECT 9.396000 181.431000 9.936000 182.016000 ;
      RECT 8.136000 181.431000 8.676000 182.016000 ;
      RECT 6.876000 181.431000 7.416000 182.016000 ;
      RECT 5.616000 181.431000 6.156000 182.016000 ;
      RECT 4.356000 181.431000 4.896000 182.016000 ;
      RECT 3.096000 181.431000 3.636000 182.016000 ;
      RECT 1.962000 181.431000 2.376000 182.016000 ;
      RECT 0.702000 181.431000 1.242000 182.016000 ;
      RECT 0.000000 0.585000 216.000000 181.431000 ;
      RECT 214.776000 0.000000 215.316000 0.585000 ;
      RECT 213.516000 0.000000 214.056000 0.585000 ;
      RECT 212.256000 0.000000 212.796000 0.585000 ;
      RECT 210.996000 0.000000 211.536000 0.585000 ;
      RECT 209.736000 0.000000 210.276000 0.585000 ;
      RECT 208.476000 0.000000 209.016000 0.585000 ;
      RECT 207.216000 0.000000 207.756000 0.585000 ;
      RECT 205.956000 0.000000 206.496000 0.585000 ;
      RECT 204.696000 0.000000 205.236000 0.585000 ;
      RECT 203.436000 0.000000 203.976000 0.585000 ;
      RECT 202.176000 0.000000 202.716000 0.585000 ;
      RECT 200.916000 0.000000 201.456000 0.585000 ;
      RECT 199.656000 0.000000 200.196000 0.585000 ;
      RECT 198.396000 0.000000 198.936000 0.585000 ;
      RECT 197.136000 0.000000 197.676000 0.585000 ;
      RECT 195.876000 0.000000 196.416000 0.585000 ;
      RECT 194.616000 0.000000 195.156000 0.585000 ;
      RECT 193.356000 0.000000 193.896000 0.585000 ;
      RECT 192.096000 0.000000 192.636000 0.585000 ;
      RECT 190.836000 0.000000 191.376000 0.585000 ;
      RECT 189.576000 0.000000 190.116000 0.585000 ;
      RECT 188.316000 0.000000 188.856000 0.585000 ;
      RECT 187.056000 0.000000 187.596000 0.585000 ;
      RECT 185.796000 0.000000 186.336000 0.585000 ;
      RECT 184.536000 0.000000 185.076000 0.585000 ;
      RECT 183.276000 0.000000 183.816000 0.585000 ;
      RECT 182.016000 0.000000 182.556000 0.585000 ;
      RECT 180.756000 0.000000 181.296000 0.585000 ;
      RECT 179.496000 0.000000 180.036000 0.585000 ;
      RECT 178.236000 0.000000 178.776000 0.585000 ;
      RECT 176.976000 0.000000 177.516000 0.585000 ;
      RECT 175.716000 0.000000 176.256000 0.585000 ;
      RECT 174.456000 0.000000 174.996000 0.585000 ;
      RECT 173.196000 0.000000 173.736000 0.585000 ;
      RECT 171.936000 0.000000 172.476000 0.585000 ;
      RECT 170.676000 0.000000 171.216000 0.585000 ;
      RECT 169.416000 0.000000 169.956000 0.585000 ;
      RECT 168.156000 0.000000 168.696000 0.585000 ;
      RECT 166.896000 0.000000 167.436000 0.585000 ;
      RECT 165.636000 0.000000 166.176000 0.585000 ;
      RECT 164.376000 0.000000 164.916000 0.585000 ;
      RECT 163.116000 0.000000 163.656000 0.585000 ;
      RECT 161.856000 0.000000 162.396000 0.585000 ;
      RECT 160.596000 0.000000 161.136000 0.585000 ;
      RECT 159.336000 0.000000 159.876000 0.585000 ;
      RECT 158.076000 0.000000 158.616000 0.585000 ;
      RECT 156.816000 0.000000 157.356000 0.585000 ;
      RECT 155.556000 0.000000 156.096000 0.585000 ;
      RECT 154.296000 0.000000 154.836000 0.585000 ;
      RECT 153.036000 0.000000 153.576000 0.585000 ;
      RECT 151.776000 0.000000 152.316000 0.585000 ;
      RECT 150.516000 0.000000 151.056000 0.585000 ;
      RECT 149.256000 0.000000 149.796000 0.585000 ;
      RECT 147.996000 0.000000 148.536000 0.585000 ;
      RECT 146.736000 0.000000 147.276000 0.585000 ;
      RECT 145.476000 0.000000 146.016000 0.585000 ;
      RECT 144.216000 0.000000 144.756000 0.585000 ;
      RECT 142.956000 0.000000 143.496000 0.585000 ;
      RECT 141.696000 0.000000 142.236000 0.585000 ;
      RECT 140.436000 0.000000 140.976000 0.585000 ;
      RECT 139.176000 0.000000 139.716000 0.585000 ;
      RECT 137.916000 0.000000 138.456000 0.585000 ;
      RECT 136.656000 0.000000 137.196000 0.585000 ;
      RECT 135.396000 0.000000 135.936000 0.585000 ;
      RECT 134.136000 0.000000 134.676000 0.585000 ;
      RECT 132.876000 0.000000 133.416000 0.585000 ;
      RECT 131.616000 0.000000 132.156000 0.585000 ;
      RECT 130.356000 0.000000 130.896000 0.585000 ;
      RECT 129.096000 0.000000 129.636000 0.585000 ;
      RECT 127.836000 0.000000 128.376000 0.585000 ;
      RECT 126.576000 0.000000 127.116000 0.585000 ;
      RECT 125.316000 0.000000 125.856000 0.585000 ;
      RECT 124.056000 0.000000 124.596000 0.585000 ;
      RECT 122.796000 0.000000 123.336000 0.585000 ;
      RECT 121.536000 0.000000 122.076000 0.585000 ;
      RECT 120.276000 0.000000 120.816000 0.585000 ;
      RECT 119.016000 0.000000 119.556000 0.585000 ;
      RECT 117.756000 0.000000 118.296000 0.585000 ;
      RECT 116.496000 0.000000 117.036000 0.585000 ;
      RECT 115.236000 0.000000 115.776000 0.585000 ;
      RECT 113.976000 0.000000 114.516000 0.585000 ;
      RECT 112.716000 0.000000 113.256000 0.585000 ;
      RECT 111.456000 0.000000 111.996000 0.585000 ;
      RECT 110.196000 0.000000 110.736000 0.585000 ;
      RECT 108.936000 0.000000 109.476000 0.585000 ;
      RECT 107.676000 0.000000 108.216000 0.585000 ;
      RECT 106.416000 0.000000 106.956000 0.585000 ;
      RECT 105.156000 0.000000 105.696000 0.585000 ;
      RECT 103.896000 0.000000 104.436000 0.585000 ;
      RECT 102.636000 0.000000 103.176000 0.585000 ;
      RECT 101.376000 0.000000 101.916000 0.585000 ;
      RECT 100.116000 0.000000 100.656000 0.585000 ;
      RECT 98.856000 0.000000 99.396000 0.585000 ;
      RECT 97.596000 0.000000 98.136000 0.585000 ;
      RECT 96.336000 0.000000 96.876000 0.585000 ;
      RECT 95.076000 0.000000 95.616000 0.585000 ;
      RECT 93.816000 0.000000 94.356000 0.585000 ;
      RECT 92.556000 0.000000 93.096000 0.585000 ;
      RECT 91.296000 0.000000 91.836000 0.585000 ;
      RECT 90.036000 0.000000 90.576000 0.585000 ;
      RECT 88.776000 0.000000 89.316000 0.585000 ;
      RECT 87.516000 0.000000 88.056000 0.585000 ;
      RECT 86.256000 0.000000 86.796000 0.585000 ;
      RECT 84.996000 0.000000 85.536000 0.585000 ;
      RECT 83.736000 0.000000 84.276000 0.585000 ;
      RECT 82.476000 0.000000 83.016000 0.585000 ;
      RECT 81.216000 0.000000 81.756000 0.585000 ;
      RECT 79.956000 0.000000 80.496000 0.585000 ;
      RECT 78.696000 0.000000 79.236000 0.585000 ;
      RECT 77.436000 0.000000 77.976000 0.585000 ;
      RECT 76.176000 0.000000 76.716000 0.585000 ;
      RECT 74.916000 0.000000 75.456000 0.585000 ;
      RECT 73.656000 0.000000 74.196000 0.585000 ;
      RECT 72.396000 0.000000 72.936000 0.585000 ;
      RECT 71.136000 0.000000 71.676000 0.585000 ;
      RECT 69.876000 0.000000 70.416000 0.585000 ;
      RECT 68.616000 0.000000 69.156000 0.585000 ;
      RECT 67.356000 0.000000 67.896000 0.585000 ;
      RECT 66.096000 0.000000 66.636000 0.585000 ;
      RECT 64.836000 0.000000 65.376000 0.585000 ;
      RECT 63.576000 0.000000 64.116000 0.585000 ;
      RECT 62.316000 0.000000 62.856000 0.585000 ;
      RECT 61.056000 0.000000 61.596000 0.585000 ;
      RECT 59.796000 0.000000 60.336000 0.585000 ;
      RECT 58.536000 0.000000 59.076000 0.585000 ;
      RECT 57.276000 0.000000 57.816000 0.585000 ;
      RECT 56.016000 0.000000 56.556000 0.585000 ;
      RECT 54.756000 0.000000 55.296000 0.585000 ;
      RECT 53.496000 0.000000 54.036000 0.585000 ;
      RECT 52.236000 0.000000 52.776000 0.585000 ;
      RECT 50.976000 0.000000 51.516000 0.585000 ;
      RECT 49.716000 0.000000 50.256000 0.585000 ;
      RECT 48.456000 0.000000 48.996000 0.585000 ;
      RECT 47.196000 0.000000 47.736000 0.585000 ;
      RECT 45.936000 0.000000 46.476000 0.585000 ;
      RECT 44.676000 0.000000 45.216000 0.585000 ;
      RECT 43.416000 0.000000 43.956000 0.585000 ;
      RECT 42.156000 0.000000 42.696000 0.585000 ;
      RECT 40.896000 0.000000 41.436000 0.585000 ;
      RECT 39.636000 0.000000 40.176000 0.585000 ;
      RECT 38.376000 0.000000 38.916000 0.585000 ;
      RECT 37.116000 0.000000 37.656000 0.585000 ;
      RECT 35.856000 0.000000 36.396000 0.585000 ;
      RECT 34.596000 0.000000 35.136000 0.585000 ;
      RECT 33.336000 0.000000 33.876000 0.585000 ;
      RECT 32.076000 0.000000 32.616000 0.585000 ;
      RECT 30.816000 0.000000 31.356000 0.585000 ;
      RECT 29.556000 0.000000 30.096000 0.585000 ;
      RECT 28.296000 0.000000 28.836000 0.585000 ;
      RECT 27.036000 0.000000 27.576000 0.585000 ;
      RECT 25.776000 0.000000 26.316000 0.585000 ;
      RECT 24.516000 0.000000 25.056000 0.585000 ;
      RECT 23.256000 0.000000 23.796000 0.585000 ;
      RECT 21.996000 0.000000 22.536000 0.585000 ;
      RECT 20.736000 0.000000 21.276000 0.585000 ;
      RECT 19.476000 0.000000 20.016000 0.585000 ;
      RECT 18.216000 0.000000 18.756000 0.585000 ;
      RECT 16.956000 0.000000 17.496000 0.585000 ;
      RECT 15.696000 0.000000 16.236000 0.585000 ;
      RECT 14.436000 0.000000 14.976000 0.585000 ;
      RECT 13.176000 0.000000 13.716000 0.585000 ;
      RECT 11.916000 0.000000 12.456000 0.585000 ;
      RECT 10.656000 0.000000 11.196000 0.585000 ;
      RECT 9.396000 0.000000 9.936000 0.585000 ;
      RECT 8.136000 0.000000 8.676000 0.585000 ;
      RECT 6.876000 0.000000 7.416000 0.585000 ;
      RECT 5.616000 0.000000 6.156000 0.585000 ;
      RECT 4.356000 0.000000 4.896000 0.585000 ;
      RECT 3.096000 0.000000 3.636000 0.585000 ;
      RECT 1.962000 0.000000 2.376000 0.585000 ;
      RECT 0.702000 0.000000 1.242000 0.585000 ;
    LAYER M10 ;
      RECT 0.000000 178.443000 216.000000 182.016000 ;
      RECT 3.285000 174.573000 212.715000 178.443000 ;
      RECT 0.000000 173.943000 216.000000 174.573000 ;
      RECT 3.285000 170.073000 212.715000 173.943000 ;
      RECT 0.000000 169.443000 216.000000 170.073000 ;
      RECT 3.285000 165.573000 212.715000 169.443000 ;
      RECT 0.000000 164.943000 216.000000 165.573000 ;
      RECT 3.285000 161.073000 212.715000 164.943000 ;
      RECT 0.000000 159.543000 216.000000 161.073000 ;
      RECT 3.285000 155.673000 212.715000 159.543000 ;
      RECT 0.000000 155.043000 216.000000 155.673000 ;
      RECT 3.285000 151.173000 212.715000 155.043000 ;
      RECT 0.000000 150.543000 216.000000 151.173000 ;
      RECT 3.285000 146.673000 212.715000 150.543000 ;
      RECT 0.000000 146.043000 216.000000 146.673000 ;
      RECT 3.285000 142.173000 212.715000 146.043000 ;
      RECT 0.000000 141.543000 216.000000 142.173000 ;
      RECT 3.285000 137.673000 212.715000 141.543000 ;
      RECT 0.000000 137.043000 216.000000 137.673000 ;
      RECT 3.285000 133.173000 212.715000 137.043000 ;
      RECT 0.000000 132.543000 216.000000 133.173000 ;
      RECT 3.285000 128.673000 212.715000 132.543000 ;
      RECT 0.000000 128.043000 216.000000 128.673000 ;
      RECT 3.285000 124.173000 212.715000 128.043000 ;
      RECT 0.000000 122.643000 216.000000 124.173000 ;
      RECT 3.285000 118.773000 212.715000 122.643000 ;
      RECT 0.000000 118.143000 216.000000 118.773000 ;
      RECT 3.285000 114.273000 212.715000 118.143000 ;
      RECT 0.000000 113.643000 216.000000 114.273000 ;
      RECT 3.285000 109.773000 212.715000 113.643000 ;
      RECT 0.000000 109.143000 216.000000 109.773000 ;
      RECT 3.285000 105.273000 212.715000 109.143000 ;
      RECT 0.000000 104.643000 216.000000 105.273000 ;
      RECT 3.285000 100.773000 212.715000 104.643000 ;
      RECT 0.000000 100.143000 216.000000 100.773000 ;
      RECT 3.285000 96.273000 212.715000 100.143000 ;
      RECT 0.000000 95.643000 216.000000 96.273000 ;
      RECT 3.285000 91.773000 212.715000 95.643000 ;
      RECT 0.000000 91.143000 216.000000 91.773000 ;
      RECT 3.285000 87.273000 212.715000 91.143000 ;
      RECT 0.000000 86.643000 216.000000 87.273000 ;
      RECT 3.285000 82.773000 212.715000 86.643000 ;
      RECT 0.000000 81.243000 216.000000 82.773000 ;
      RECT 3.285000 77.373000 212.715000 81.243000 ;
      RECT 0.000000 76.743000 216.000000 77.373000 ;
      RECT 3.285000 72.873000 212.715000 76.743000 ;
      RECT 0.000000 72.243000 216.000000 72.873000 ;
      RECT 3.285000 68.373000 212.715000 72.243000 ;
      RECT 0.000000 67.743000 216.000000 68.373000 ;
      RECT 3.285000 63.873000 212.715000 67.743000 ;
      RECT 0.000000 63.243000 216.000000 63.873000 ;
      RECT 3.285000 59.373000 212.715000 63.243000 ;
      RECT 0.000000 58.743000 216.000000 59.373000 ;
      RECT 3.285000 54.873000 212.715000 58.743000 ;
      RECT 0.000000 54.243000 216.000000 54.873000 ;
      RECT 3.285000 50.373000 212.715000 54.243000 ;
      RECT 0.000000 49.743000 216.000000 50.373000 ;
      RECT 3.285000 45.873000 212.715000 49.743000 ;
      RECT 0.000000 44.343000 216.000000 45.873000 ;
      RECT 3.285000 40.473000 212.715000 44.343000 ;
      RECT 0.000000 39.843000 216.000000 40.473000 ;
      RECT 3.285000 35.973000 212.715000 39.843000 ;
      RECT 0.000000 35.343000 216.000000 35.973000 ;
      RECT 3.285000 31.473000 212.715000 35.343000 ;
      RECT 0.000000 30.843000 216.000000 31.473000 ;
      RECT 3.285000 26.973000 212.715000 30.843000 ;
      RECT 0.000000 26.343000 216.000000 26.973000 ;
      RECT 3.285000 22.473000 212.715000 26.343000 ;
      RECT 0.000000 21.843000 216.000000 22.473000 ;
      RECT 3.285000 17.973000 212.715000 21.843000 ;
      RECT 0.000000 17.343000 216.000000 17.973000 ;
      RECT 3.285000 13.473000 212.715000 17.343000 ;
      RECT 0.000000 12.843000 216.000000 13.473000 ;
      RECT 3.285000 8.973000 212.715000 12.843000 ;
      RECT 0.000000 8.343000 216.000000 8.973000 ;
      RECT 3.285000 4.473000 212.715000 8.343000 ;
      RECT 0.000000 3.843000 216.000000 4.473000 ;
      RECT 3.285000 0.000000 212.715000 3.843000 ;
    LAYER M11 ;
      RECT 0.000000 0.000000 216.000000 182.016000 ;
  END
END top

END LIBRARY
